VERSION 5.8 ;
BUSBITCHARS "[]" ;
DIVIDERCHAR "/" ;
UNITS
    DATABASE MICRONS 1000 ;
END UNITS

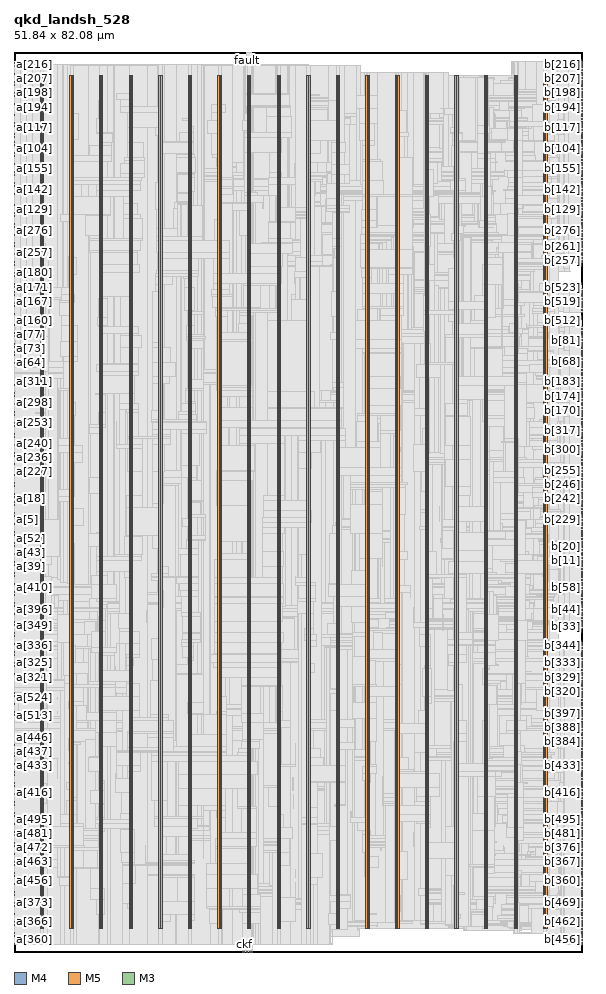
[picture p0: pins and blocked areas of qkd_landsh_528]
MACRO qkd_landsh_528
  FOREIGN qkd_landsh_528 0 0 ;
  CLASS BLOCK ;
  SIZE 51.84 BY 82.08 ;
  PIN a[0]
    DIRECTION INPUT ;
    USE SIGNAL ;
    PORT
      LAYER M4 ;
        RECT  0 38.736 0.084 38.76 ;
    END
  END a[0]
  PIN a[100]
    DIRECTION INPUT ;
    USE SIGNAL ;
    PORT
      LAYER M4 ;
        RECT  0 72.72 0.084 72.744 ;
    END
  END a[100]
  PIN a[101]
    DIRECTION INPUT ;
    USE SIGNAL ;
    PORT
      LAYER M4 ;
        RECT  0 72.864 0.084 72.888 ;
    END
  END a[101]
  PIN a[102]
    DIRECTION INPUT ;
    USE SIGNAL ;
    PORT
      LAYER M4 ;
        RECT  0 73.008 0.084 73.032 ;
    END
  END a[102]
  PIN a[103]
    DIRECTION INPUT ;
    USE SIGNAL ;
    PORT
      LAYER M4 ;
        RECT  0 73.152 0.084 73.176 ;
    END
  END a[103]
  PIN a[104]
    DIRECTION INPUT ;
    USE SIGNAL ;
    PORT
      LAYER M4 ;
        RECT  0 73.296 0.084 73.32 ;
    END
  END a[104]
  PIN a[105]
    DIRECTION INPUT ;
    USE SIGNAL ;
    PORT
      LAYER M4 ;
        RECT  0 73.44 0.084 73.464 ;
    END
  END a[105]
  PIN a[106]
    DIRECTION INPUT ;
    USE SIGNAL ;
    PORT
      LAYER M4 ;
        RECT  0 73.584 0.084 73.608 ;
    END
  END a[106]
  PIN a[107]
    DIRECTION INPUT ;
    USE SIGNAL ;
    PORT
      LAYER M4 ;
        RECT  0 73.728 0.084 73.752 ;
    END
  END a[107]
  PIN a[108]
    DIRECTION INPUT ;
    USE SIGNAL ;
    PORT
      LAYER M4 ;
        RECT  0 73.872 0.084 73.896 ;
    END
  END a[108]
  PIN a[109]
    DIRECTION INPUT ;
    USE SIGNAL ;
    PORT
      LAYER M4 ;
        RECT  0 74.016 0.084 74.04 ;
    END
  END a[109]
  PIN a[10]
    DIRECTION INPUT ;
    USE SIGNAL ;
    PORT
      LAYER M4 ;
        RECT  0 40.176 0.084 40.2 ;
    END
  END a[10]
  PIN a[110]
    DIRECTION INPUT ;
    USE SIGNAL ;
    PORT
      LAYER M4 ;
        RECT  0 74.16 0.084 74.184 ;
    END
  END a[110]
  PIN a[111]
    DIRECTION INPUT ;
    USE SIGNAL ;
    PORT
      LAYER M4 ;
        RECT  0 74.304 0.084 74.328 ;
    END
  END a[111]
  PIN a[112]
    DIRECTION INPUT ;
    USE SIGNAL ;
    PORT
      LAYER M4 ;
        RECT  0 74.448 0.084 74.472 ;
    END
  END a[112]
  PIN a[113]
    DIRECTION INPUT ;
    USE SIGNAL ;
    PORT
      LAYER M4 ;
        RECT  0 74.592 0.084 74.616 ;
    END
  END a[113]
  PIN a[114]
    DIRECTION INPUT ;
    USE SIGNAL ;
    PORT
      LAYER M4 ;
        RECT  0 74.736 0.084 74.76 ;
    END
  END a[114]
  PIN a[115]
    DIRECTION INPUT ;
    USE SIGNAL ;
    PORT
      LAYER M4 ;
        RECT  0 74.88 0.084 74.904 ;
    END
  END a[115]
  PIN a[116]
    DIRECTION INPUT ;
    USE SIGNAL ;
    PORT
      LAYER M4 ;
        RECT  0 75.024 0.084 75.048 ;
    END
  END a[116]
  PIN a[117]
    DIRECTION INPUT ;
    USE SIGNAL ;
    PORT
      LAYER M4 ;
        RECT  0 75.168 0.084 75.192 ;
    END
  END a[117]
  PIN a[118]
    DIRECTION INPUT ;
    USE SIGNAL ;
    PORT
      LAYER M4 ;
        RECT  0 75.312 0.084 75.336 ;
    END
  END a[118]
  PIN a[119]
    DIRECTION INPUT ;
    USE SIGNAL ;
    PORT
      LAYER M4 ;
        RECT  0 75.456 0.084 75.48 ;
    END
  END a[119]
  PIN a[11]
    DIRECTION INPUT ;
    USE SIGNAL ;
    PORT
      LAYER M4 ;
        RECT  0 40.32 0.084 40.344 ;
    END
  END a[11]
  PIN a[120]
    DIRECTION INPUT ;
    USE SIGNAL ;
    PORT
      LAYER M4 ;
        RECT  0 75.6 0.084 75.624 ;
    END
  END a[120]
  PIN a[121]
    DIRECTION INPUT ;
    USE SIGNAL ;
    PORT
      LAYER M4 ;
        RECT  0 75.744 0.084 75.768 ;
    END
  END a[121]
  PIN a[122]
    DIRECTION INPUT ;
    USE SIGNAL ;
    PORT
      LAYER M4 ;
        RECT  0 75.888 0.084 75.912 ;
    END
  END a[122]
  PIN a[123]
    DIRECTION INPUT ;
    USE SIGNAL ;
    PORT
      LAYER M4 ;
        RECT  0 76.032 0.084 76.056 ;
    END
  END a[123]
  PIN a[124]
    DIRECTION INPUT ;
    USE SIGNAL ;
    PORT
      LAYER M4 ;
        RECT  0 76.176 0.084 76.2 ;
    END
  END a[124]
  PIN a[125]
    DIRECTION INPUT ;
    USE SIGNAL ;
    PORT
      LAYER M4 ;
        RECT  0 76.32 0.084 76.344 ;
    END
  END a[125]
  PIN a[126]
    DIRECTION INPUT ;
    USE SIGNAL ;
    PORT
      LAYER M4 ;
        RECT  0 76.464 0.084 76.488 ;
    END
  END a[126]
  PIN a[127]
    DIRECTION INPUT ;
    USE SIGNAL ;
    PORT
      LAYER M4 ;
        RECT  0 76.608 0.084 76.632 ;
    END
  END a[127]
  PIN a[128]
    DIRECTION INPUT ;
    USE SIGNAL ;
    PORT
      LAYER M4 ;
        RECT  0 67.536 0.084 67.56 ;
    END
  END a[128]
  PIN a[129]
    DIRECTION INPUT ;
    USE SIGNAL ;
    PORT
      LAYER M4 ;
        RECT  0 67.68 0.084 67.704 ;
    END
  END a[129]
  PIN a[12]
    DIRECTION INPUT ;
    USE SIGNAL ;
    PORT
      LAYER M4 ;
        RECT  0 40.464 0.084 40.488 ;
    END
  END a[12]
  PIN a[130]
    DIRECTION INPUT ;
    USE SIGNAL ;
    PORT
      LAYER M4 ;
        RECT  0 67.824 0.084 67.848 ;
    END
  END a[130]
  PIN a[131]
    DIRECTION INPUT ;
    USE SIGNAL ;
    PORT
      LAYER M4 ;
        RECT  0 67.968 0.084 67.992 ;
    END
  END a[131]
  PIN a[132]
    DIRECTION INPUT ;
    USE SIGNAL ;
    PORT
      LAYER M4 ;
        RECT  0 68.112 0.084 68.136 ;
    END
  END a[132]
  PIN a[133]
    DIRECTION INPUT ;
    USE SIGNAL ;
    PORT
      LAYER M4 ;
        RECT  0 68.256 0.084 68.28 ;
    END
  END a[133]
  PIN a[134]
    DIRECTION INPUT ;
    USE SIGNAL ;
    PORT
      LAYER M4 ;
        RECT  0 68.4 0.084 68.424 ;
    END
  END a[134]
  PIN a[135]
    DIRECTION INPUT ;
    USE SIGNAL ;
    PORT
      LAYER M4 ;
        RECT  0 68.544 0.084 68.568 ;
    END
  END a[135]
  PIN a[136]
    DIRECTION INPUT ;
    USE SIGNAL ;
    PORT
      LAYER M4 ;
        RECT  0 68.688 0.084 68.712 ;
    END
  END a[136]
  PIN a[137]
    DIRECTION INPUT ;
    USE SIGNAL ;
    PORT
      LAYER M4 ;
        RECT  0 68.832 0.084 68.856 ;
    END
  END a[137]
  PIN a[138]
    DIRECTION INPUT ;
    USE SIGNAL ;
    PORT
      LAYER M4 ;
        RECT  0 68.976 0.084 69 ;
    END
  END a[138]
  PIN a[139]
    DIRECTION INPUT ;
    USE SIGNAL ;
    PORT
      LAYER M4 ;
        RECT  0 69.12 0.084 69.144 ;
    END
  END a[139]
  PIN a[13]
    DIRECTION INPUT ;
    USE SIGNAL ;
    PORT
      LAYER M4 ;
        RECT  0 40.608 0.084 40.632 ;
    END
  END a[13]
  PIN a[140]
    DIRECTION INPUT ;
    USE SIGNAL ;
    PORT
      LAYER M4 ;
        RECT  0 69.264 0.084 69.288 ;
    END
  END a[140]
  PIN a[141]
    DIRECTION INPUT ;
    USE SIGNAL ;
    PORT
      LAYER M4 ;
        RECT  0 69.408 0.084 69.432 ;
    END
  END a[141]
  PIN a[142]
    DIRECTION INPUT ;
    USE SIGNAL ;
    PORT
      LAYER M4 ;
        RECT  0 69.552 0.084 69.576 ;
    END
  END a[142]
  PIN a[143]
    DIRECTION INPUT ;
    USE SIGNAL ;
    PORT
      LAYER M4 ;
        RECT  0 69.696 0.084 69.72 ;
    END
  END a[143]
  PIN a[144]
    DIRECTION INPUT ;
    USE SIGNAL ;
    PORT
      LAYER M4 ;
        RECT  0 69.84 0.084 69.864 ;
    END
  END a[144]
  PIN a[145]
    DIRECTION INPUT ;
    USE SIGNAL ;
    PORT
      LAYER M4 ;
        RECT  0 69.984 0.084 70.008 ;
    END
  END a[145]
  PIN a[146]
    DIRECTION INPUT ;
    USE SIGNAL ;
    PORT
      LAYER M4 ;
        RECT  0 70.128 0.084 70.152 ;
    END
  END a[146]
  PIN a[147]
    DIRECTION INPUT ;
    USE SIGNAL ;
    PORT
      LAYER M4 ;
        RECT  0 70.272 0.084 70.296 ;
    END
  END a[147]
  PIN a[148]
    DIRECTION INPUT ;
    USE SIGNAL ;
    PORT
      LAYER M4 ;
        RECT  0 70.416 0.084 70.44 ;
    END
  END a[148]
  PIN a[149]
    DIRECTION INPUT ;
    USE SIGNAL ;
    PORT
      LAYER M4 ;
        RECT  0 70.56 0.084 70.584 ;
    END
  END a[149]
  PIN a[14]
    DIRECTION INPUT ;
    USE SIGNAL ;
    PORT
      LAYER M4 ;
        RECT  0 40.752 0.084 40.776 ;
    END
  END a[14]
  PIN a[150]
    DIRECTION INPUT ;
    USE SIGNAL ;
    PORT
      LAYER M4 ;
        RECT  0 70.704 0.084 70.728 ;
    END
  END a[150]
  PIN a[151]
    DIRECTION INPUT ;
    USE SIGNAL ;
    PORT
      LAYER M4 ;
        RECT  0 70.848 0.084 70.872 ;
    END
  END a[151]
  PIN a[152]
    DIRECTION INPUT ;
    USE SIGNAL ;
    PORT
      LAYER M4 ;
        RECT  0 70.992 0.084 71.016 ;
    END
  END a[152]
  PIN a[153]
    DIRECTION INPUT ;
    USE SIGNAL ;
    PORT
      LAYER M4 ;
        RECT  0 71.136 0.084 71.16 ;
    END
  END a[153]
  PIN a[154]
    DIRECTION INPUT ;
    USE SIGNAL ;
    PORT
      LAYER M4 ;
        RECT  0 71.28 0.084 71.304 ;
    END
  END a[154]
  PIN a[155]
    DIRECTION INPUT ;
    USE SIGNAL ;
    PORT
      LAYER M4 ;
        RECT  0 71.424 0.084 71.448 ;
    END
  END a[155]
  PIN a[156]
    DIRECTION INPUT ;
    USE SIGNAL ;
    PORT
      LAYER M4 ;
        RECT  0 71.568 0.084 71.592 ;
    END
  END a[156]
  PIN a[157]
    DIRECTION INPUT ;
    USE SIGNAL ;
    PORT
      LAYER M4 ;
        RECT  0 71.712 0.084 71.736 ;
    END
  END a[157]
  PIN a[158]
    DIRECTION INPUT ;
    USE SIGNAL ;
    PORT
      LAYER M4 ;
        RECT  0 71.856 0.084 71.88 ;
    END
  END a[158]
  PIN a[159]
    DIRECTION INPUT ;
    USE SIGNAL ;
    PORT
      LAYER M4 ;
        RECT  0 72 0.084 72.024 ;
    END
  END a[159]
  PIN a[15]
    DIRECTION INPUT ;
    USE SIGNAL ;
    PORT
      LAYER M4 ;
        RECT  0 40.896 0.084 40.92 ;
    END
  END a[15]
  PIN a[160]
    DIRECTION INPUT ;
    USE SIGNAL ;
    PORT
      LAYER M4 ;
        RECT  0 58.32 0.084 58.344 ;
    END
  END a[160]
  PIN a[161]
    DIRECTION INPUT ;
    USE SIGNAL ;
    PORT
      LAYER M4 ;
        RECT  0 58.464 0.084 58.488 ;
    END
  END a[161]
  PIN a[162]
    DIRECTION INPUT ;
    USE SIGNAL ;
    PORT
      LAYER M4 ;
        RECT  0 58.608 0.084 58.632 ;
    END
  END a[162]
  PIN a[163]
    DIRECTION INPUT ;
    USE SIGNAL ;
    PORT
      LAYER M4 ;
        RECT  0 58.752 0.084 58.776 ;
    END
  END a[163]
  PIN a[164]
    DIRECTION INPUT ;
    USE SIGNAL ;
    PORT
      LAYER M4 ;
        RECT  0 58.896 0.084 58.92 ;
    END
  END a[164]
  PIN a[165]
    DIRECTION INPUT ;
    USE SIGNAL ;
    PORT
      LAYER M4 ;
        RECT  0 59.04 0.084 59.064 ;
    END
  END a[165]
  PIN a[166]
    DIRECTION INPUT ;
    USE SIGNAL ;
    PORT
      LAYER M4 ;
        RECT  0 59.184 0.084 59.208 ;
    END
  END a[166]
  PIN a[167]
    DIRECTION INPUT ;
    USE SIGNAL ;
    PORT
      LAYER M4 ;
        RECT  0 59.328 0.084 59.352 ;
    END
  END a[167]
  PIN a[168]
    DIRECTION INPUT ;
    USE SIGNAL ;
    PORT
      LAYER M4 ;
        RECT  0 59.472 0.084 59.496 ;
    END
  END a[168]
  PIN a[169]
    DIRECTION INPUT ;
    USE SIGNAL ;
    PORT
      LAYER M4 ;
        RECT  0 59.616 0.084 59.64 ;
    END
  END a[169]
  PIN a[16]
    DIRECTION INPUT ;
    USE SIGNAL ;
    PORT
      LAYER M4 ;
        RECT  0 41.04 0.084 41.064 ;
    END
  END a[16]
  PIN a[170]
    DIRECTION INPUT ;
    USE SIGNAL ;
    PORT
      LAYER M4 ;
        RECT  0 59.76 0.084 59.784 ;
    END
  END a[170]
  PIN a[171]
    DIRECTION INPUT ;
    USE SIGNAL ;
    PORT
      LAYER M4 ;
        RECT  0 59.904 0.084 59.928 ;
    END
  END a[171]
  PIN a[172]
    DIRECTION INPUT ;
    USE SIGNAL ;
    PORT
      LAYER M4 ;
        RECT  0 60.048 0.084 60.072 ;
    END
  END a[172]
  PIN a[173]
    DIRECTION INPUT ;
    USE SIGNAL ;
    PORT
      LAYER M4 ;
        RECT  0 60.192 0.084 60.216 ;
    END
  END a[173]
  PIN a[174]
    DIRECTION INPUT ;
    USE SIGNAL ;
    PORT
      LAYER M4 ;
        RECT  0 60.336 0.084 60.36 ;
    END
  END a[174]
  PIN a[175]
    DIRECTION INPUT ;
    USE SIGNAL ;
    PORT
      LAYER M4 ;
        RECT  0 60.48 0.084 60.504 ;
    END
  END a[175]
  PIN a[176]
    DIRECTION INPUT ;
    USE SIGNAL ;
    PORT
      LAYER M4 ;
        RECT  0 60.624 0.084 60.648 ;
    END
  END a[176]
  PIN a[177]
    DIRECTION INPUT ;
    USE SIGNAL ;
    PORT
      LAYER M4 ;
        RECT  0 60.768 0.084 60.792 ;
    END
  END a[177]
  PIN a[178]
    DIRECTION INPUT ;
    USE SIGNAL ;
    PORT
      LAYER M4 ;
        RECT  0 60.912 0.084 60.936 ;
    END
  END a[178]
  PIN a[179]
    DIRECTION INPUT ;
    USE SIGNAL ;
    PORT
      LAYER M4 ;
        RECT  0 61.056 0.084 61.08 ;
    END
  END a[179]
  PIN a[17]
    DIRECTION INPUT ;
    USE SIGNAL ;
    PORT
      LAYER M4 ;
        RECT  0 41.184 0.084 41.208 ;
    END
  END a[17]
  PIN a[180]
    DIRECTION INPUT ;
    USE SIGNAL ;
    PORT
      LAYER M4 ;
        RECT  0 61.2 0.084 61.224 ;
    END
  END a[180]
  PIN a[181]
    DIRECTION INPUT ;
    USE SIGNAL ;
    PORT
      LAYER M4 ;
        RECT  0 61.344 0.084 61.368 ;
    END
  END a[181]
  PIN a[182]
    DIRECTION INPUT ;
    USE SIGNAL ;
    PORT
      LAYER M4 ;
        RECT  0 61.488 0.084 61.512 ;
    END
  END a[182]
  PIN a[183]
    DIRECTION INPUT ;
    USE SIGNAL ;
    PORT
      LAYER M4 ;
        RECT  0 61.632 0.084 61.656 ;
    END
  END a[183]
  PIN a[184]
    DIRECTION INPUT ;
    USE SIGNAL ;
    PORT
      LAYER M4 ;
        RECT  0 61.776 0.084 61.8 ;
    END
  END a[184]
  PIN a[185]
    DIRECTION INPUT ;
    USE SIGNAL ;
    PORT
      LAYER M4 ;
        RECT  0 61.92 0.084 61.944 ;
    END
  END a[185]
  PIN a[186]
    DIRECTION INPUT ;
    USE SIGNAL ;
    PORT
      LAYER M4 ;
        RECT  0 62.064 0.084 62.088 ;
    END
  END a[186]
  PIN a[187]
    DIRECTION INPUT ;
    USE SIGNAL ;
    PORT
      LAYER M4 ;
        RECT  0 62.208 0.084 62.232 ;
    END
  END a[187]
  PIN a[188]
    DIRECTION INPUT ;
    USE SIGNAL ;
    PORT
      LAYER M4 ;
        RECT  0 62.352 0.084 62.376 ;
    END
  END a[188]
  PIN a[189]
    DIRECTION INPUT ;
    USE SIGNAL ;
    PORT
      LAYER M4 ;
        RECT  0 62.496 0.084 62.52 ;
    END
  END a[189]
  PIN a[18]
    DIRECTION INPUT ;
    USE SIGNAL ;
    PORT
      LAYER M4 ;
        RECT  0 41.328 0.084 41.352 ;
    END
  END a[18]
  PIN a[190]
    DIRECTION INPUT ;
    USE SIGNAL ;
    PORT
      LAYER M4 ;
        RECT  0 62.64 0.084 62.664 ;
    END
  END a[190]
  PIN a[191]
    DIRECTION INPUT ;
    USE SIGNAL ;
    PORT
      LAYER M4 ;
        RECT  0 62.784 0.084 62.808 ;
    END
  END a[191]
  PIN a[192]
    DIRECTION INPUT ;
    USE SIGNAL ;
    PORT
      LAYER M4 ;
        RECT  0 76.752 0.084 76.776 ;
    END
  END a[192]
  PIN a[193]
    DIRECTION INPUT ;
    USE SIGNAL ;
    PORT
      LAYER M4 ;
        RECT  0 76.896 0.084 76.92 ;
    END
  END a[193]
  PIN a[194]
    DIRECTION INPUT ;
    USE SIGNAL ;
    PORT
      LAYER M4 ;
        RECT  0 77.04 0.084 77.064 ;
    END
  END a[194]
  PIN a[195]
    DIRECTION INPUT ;
    USE SIGNAL ;
    PORT
      LAYER M4 ;
        RECT  0 77.184 0.084 77.208 ;
    END
  END a[195]
  PIN a[196]
    DIRECTION INPUT ;
    USE SIGNAL ;
    PORT
      LAYER M4 ;
        RECT  0 77.328 0.084 77.352 ;
    END
  END a[196]
  PIN a[197]
    DIRECTION INPUT ;
    USE SIGNAL ;
    PORT
      LAYER M4 ;
        RECT  0 77.472 0.084 77.496 ;
    END
  END a[197]
  PIN a[198]
    DIRECTION INPUT ;
    USE SIGNAL ;
    PORT
      LAYER M4 ;
        RECT  0 77.616 0.084 77.64 ;
    END
  END a[198]
  PIN a[199]
    DIRECTION INPUT ;
    USE SIGNAL ;
    PORT
      LAYER M4 ;
        RECT  0 77.76 0.084 77.784 ;
    END
  END a[199]
  PIN a[19]
    DIRECTION INPUT ;
    USE SIGNAL ;
    PORT
      LAYER M4 ;
        RECT  0 41.472 0.084 41.496 ;
    END
  END a[19]
  PIN a[1]
    DIRECTION INPUT ;
    USE SIGNAL ;
    PORT
      LAYER M4 ;
        RECT  0 38.88 0.084 38.904 ;
    END
  END a[1]
  PIN a[200]
    DIRECTION INPUT ;
    USE SIGNAL ;
    PORT
      LAYER M4 ;
        RECT  0 77.904 0.084 77.928 ;
    END
  END a[200]
  PIN a[201]
    DIRECTION INPUT ;
    USE SIGNAL ;
    PORT
      LAYER M4 ;
        RECT  0 78.048 0.084 78.072 ;
    END
  END a[201]
  PIN a[202]
    DIRECTION INPUT ;
    USE SIGNAL ;
    PORT
      LAYER M4 ;
        RECT  0 78.192 0.084 78.216 ;
    END
  END a[202]
  PIN a[203]
    DIRECTION INPUT ;
    USE SIGNAL ;
    PORT
      LAYER M4 ;
        RECT  0 78.336 0.084 78.36 ;
    END
  END a[203]
  PIN a[204]
    DIRECTION INPUT ;
    USE SIGNAL ;
    PORT
      LAYER M4 ;
        RECT  0 78.48 0.084 78.504 ;
    END
  END a[204]
  PIN a[205]
    DIRECTION INPUT ;
    USE SIGNAL ;
    PORT
      LAYER M4 ;
        RECT  0 78.624 0.084 78.648 ;
    END
  END a[205]
  PIN a[206]
    DIRECTION INPUT ;
    USE SIGNAL ;
    PORT
      LAYER M4 ;
        RECT  0 78.768 0.084 78.792 ;
    END
  END a[206]
  PIN a[207]
    DIRECTION INPUT ;
    USE SIGNAL ;
    PORT
      LAYER M4 ;
        RECT  0 78.912 0.084 78.936 ;
    END
  END a[207]
  PIN a[208]
    DIRECTION INPUT ;
    USE SIGNAL ;
    PORT
      LAYER M4 ;
        RECT  0 79.056 0.084 79.08 ;
    END
  END a[208]
  PIN a[209]
    DIRECTION INPUT ;
    USE SIGNAL ;
    PORT
      LAYER M4 ;
        RECT  0 79.2 0.084 79.224 ;
    END
  END a[209]
  PIN a[20]
    DIRECTION INPUT ;
    USE SIGNAL ;
    PORT
      LAYER M4 ;
        RECT  0 41.616 0.084 41.64 ;
    END
  END a[20]
  PIN a[210]
    DIRECTION INPUT ;
    USE SIGNAL ;
    PORT
      LAYER M4 ;
        RECT  0 79.344 0.084 79.368 ;
    END
  END a[210]
  PIN a[211]
    DIRECTION INPUT ;
    USE SIGNAL ;
    PORT
      LAYER M4 ;
        RECT  0 79.488 0.084 79.512 ;
    END
  END a[211]
  PIN a[212]
    DIRECTION INPUT ;
    USE SIGNAL ;
    PORT
      LAYER M4 ;
        RECT  0 79.632 0.084 79.656 ;
    END
  END a[212]
  PIN a[213]
    DIRECTION INPUT ;
    USE SIGNAL ;
    PORT
      LAYER M4 ;
        RECT  0 79.776 0.084 79.8 ;
    END
  END a[213]
  PIN a[214]
    DIRECTION INPUT ;
    USE SIGNAL ;
    PORT
      LAYER M4 ;
        RECT  0 79.92 0.084 79.944 ;
    END
  END a[214]
  PIN a[215]
    DIRECTION INPUT ;
    USE SIGNAL ;
    PORT
      LAYER M4 ;
        RECT  0 80.064 0.084 80.088 ;
    END
  END a[215]
  PIN a[216]
    DIRECTION INPUT ;
    USE SIGNAL ;
    PORT
      LAYER M4 ;
        RECT  0 80.208 0.084 80.232 ;
    END
  END a[216]
  PIN a[217]
    DIRECTION INPUT ;
    USE SIGNAL ;
    PORT
      LAYER M4 ;
        RECT  0 80.352 0.084 80.376 ;
    END
  END a[217]
  PIN a[218]
    DIRECTION INPUT ;
    USE SIGNAL ;
    PORT
      LAYER M4 ;
        RECT  0 80.496 0.084 80.52 ;
    END
  END a[218]
  PIN a[219]
    DIRECTION INPUT ;
    USE SIGNAL ;
    PORT
      LAYER M4 ;
        RECT  0 80.64 0.084 80.664 ;
    END
  END a[219]
  PIN a[21]
    DIRECTION INPUT ;
    USE SIGNAL ;
    PORT
      LAYER M4 ;
        RECT  0 41.76 0.084 41.784 ;
    END
  END a[21]
  PIN a[220]
    DIRECTION INPUT ;
    USE SIGNAL ;
    PORT
      LAYER M4 ;
        RECT  0 80.784 0.084 80.808 ;
    END
  END a[220]
  PIN a[221]
    DIRECTION INPUT ;
    USE SIGNAL ;
    PORT
      LAYER M4 ;
        RECT  0 80.928 0.084 80.952 ;
    END
  END a[221]
  PIN a[222]
    DIRECTION INPUT ;
    USE SIGNAL ;
    PORT
      LAYER M4 ;
        RECT  0 81.072 0.084 81.096 ;
    END
  END a[222]
  PIN a[223]
    DIRECTION INPUT ;
    USE SIGNAL ;
    PORT
      LAYER M4 ;
        RECT  0 81.216 0.084 81.24 ;
    END
  END a[223]
  PIN a[224]
    DIRECTION INPUT ;
    USE SIGNAL ;
    PORT
      LAYER M4 ;
        RECT  0 43.344 0.084 43.368 ;
    END
  END a[224]
  PIN a[225]
    DIRECTION INPUT ;
    USE SIGNAL ;
    PORT
      LAYER M4 ;
        RECT  0 43.488 0.084 43.512 ;
    END
  END a[225]
  PIN a[226]
    DIRECTION INPUT ;
    USE SIGNAL ;
    PORT
      LAYER M4 ;
        RECT  0 43.632 0.084 43.656 ;
    END
  END a[226]
  PIN a[227]
    DIRECTION INPUT ;
    USE SIGNAL ;
    PORT
      LAYER M4 ;
        RECT  0 43.776 0.084 43.8 ;
    END
  END a[227]
  PIN a[228]
    DIRECTION INPUT ;
    USE SIGNAL ;
    PORT
      LAYER M4 ;
        RECT  0 43.92 0.084 43.944 ;
    END
  END a[228]
  PIN a[229]
    DIRECTION INPUT ;
    USE SIGNAL ;
    PORT
      LAYER M4 ;
        RECT  0 44.064 0.084 44.088 ;
    END
  END a[229]
  PIN a[22]
    DIRECTION INPUT ;
    USE SIGNAL ;
    PORT
      LAYER M4 ;
        RECT  0 41.904 0.084 41.928 ;
    END
  END a[22]
  PIN a[230]
    DIRECTION INPUT ;
    USE SIGNAL ;
    PORT
      LAYER M4 ;
        RECT  0 44.208 0.084 44.232 ;
    END
  END a[230]
  PIN a[231]
    DIRECTION INPUT ;
    USE SIGNAL ;
    PORT
      LAYER M4 ;
        RECT  0 44.352 0.084 44.376 ;
    END
  END a[231]
  PIN a[232]
    DIRECTION INPUT ;
    USE SIGNAL ;
    PORT
      LAYER M4 ;
        RECT  0 44.496 0.084 44.52 ;
    END
  END a[232]
  PIN a[233]
    DIRECTION INPUT ;
    USE SIGNAL ;
    PORT
      LAYER M4 ;
        RECT  0 44.64 0.084 44.664 ;
    END
  END a[233]
  PIN a[234]
    DIRECTION INPUT ;
    USE SIGNAL ;
    PORT
      LAYER M4 ;
        RECT  0 44.784 0.084 44.808 ;
    END
  END a[234]
  PIN a[235]
    DIRECTION INPUT ;
    USE SIGNAL ;
    PORT
      LAYER M4 ;
        RECT  0 44.928 0.084 44.952 ;
    END
  END a[235]
  PIN a[236]
    DIRECTION INPUT ;
    USE SIGNAL ;
    PORT
      LAYER M4 ;
        RECT  0 45.072 0.084 45.096 ;
    END
  END a[236]
  PIN a[237]
    DIRECTION INPUT ;
    USE SIGNAL ;
    PORT
      LAYER M4 ;
        RECT  0 45.216 0.084 45.24 ;
    END
  END a[237]
  PIN a[238]
    DIRECTION INPUT ;
    USE SIGNAL ;
    PORT
      LAYER M4 ;
        RECT  0 45.36 0.084 45.384 ;
    END
  END a[238]
  PIN a[239]
    DIRECTION INPUT ;
    USE SIGNAL ;
    PORT
      LAYER M4 ;
        RECT  0 45.504 0.084 45.528 ;
    END
  END a[239]
  PIN a[23]
    DIRECTION INPUT ;
    USE SIGNAL ;
    PORT
      LAYER M4 ;
        RECT  0 42.048 0.084 42.072 ;
    END
  END a[23]
  PIN a[240]
    DIRECTION INPUT ;
    USE SIGNAL ;
    PORT
      LAYER M4 ;
        RECT  0 45.648 0.084 45.672 ;
    END
  END a[240]
  PIN a[241]
    DIRECTION INPUT ;
    USE SIGNAL ;
    PORT
      LAYER M4 ;
        RECT  0 45.792 0.084 45.816 ;
    END
  END a[241]
  PIN a[242]
    DIRECTION INPUT ;
    USE SIGNAL ;
    PORT
      LAYER M4 ;
        RECT  0 45.936 0.084 45.96 ;
    END
  END a[242]
  PIN a[243]
    DIRECTION INPUT ;
    USE SIGNAL ;
    PORT
      LAYER M4 ;
        RECT  0 46.08 0.084 46.104 ;
    END
  END a[243]
  PIN a[244]
    DIRECTION INPUT ;
    USE SIGNAL ;
    PORT
      LAYER M4 ;
        RECT  0 46.224 0.084 46.248 ;
    END
  END a[244]
  PIN a[245]
    DIRECTION INPUT ;
    USE SIGNAL ;
    PORT
      LAYER M4 ;
        RECT  0 46.368 0.084 46.392 ;
    END
  END a[245]
  PIN a[246]
    DIRECTION INPUT ;
    USE SIGNAL ;
    PORT
      LAYER M4 ;
        RECT  0 46.512 0.084 46.536 ;
    END
  END a[246]
  PIN a[247]
    DIRECTION INPUT ;
    USE SIGNAL ;
    PORT
      LAYER M4 ;
        RECT  0 46.656 0.084 46.68 ;
    END
  END a[247]
  PIN a[248]
    DIRECTION INPUT ;
    USE SIGNAL ;
    PORT
      LAYER M4 ;
        RECT  0 46.8 0.084 46.824 ;
    END
  END a[248]
  PIN a[249]
    DIRECTION INPUT ;
    USE SIGNAL ;
    PORT
      LAYER M4 ;
        RECT  0 46.944 0.084 46.968 ;
    END
  END a[249]
  PIN a[24]
    DIRECTION INPUT ;
    USE SIGNAL ;
    PORT
      LAYER M4 ;
        RECT  0 42.192 0.084 42.216 ;
    END
  END a[24]
  PIN a[250]
    DIRECTION INPUT ;
    USE SIGNAL ;
    PORT
      LAYER M4 ;
        RECT  0 47.088 0.084 47.112 ;
    END
  END a[250]
  PIN a[251]
    DIRECTION INPUT ;
    USE SIGNAL ;
    PORT
      LAYER M4 ;
        RECT  0 47.232 0.084 47.256 ;
    END
  END a[251]
  PIN a[252]
    DIRECTION INPUT ;
    USE SIGNAL ;
    PORT
      LAYER M4 ;
        RECT  0 47.376 0.084 47.4 ;
    END
  END a[252]
  PIN a[253]
    DIRECTION INPUT ;
    USE SIGNAL ;
    PORT
      LAYER M4 ;
        RECT  0 47.52 0.084 47.544 ;
    END
  END a[253]
  PIN a[254]
    DIRECTION INPUT ;
    USE SIGNAL ;
    PORT
      LAYER M4 ;
        RECT  0 47.664 0.084 47.688 ;
    END
  END a[254]
  PIN a[255]
    DIRECTION INPUT ;
    USE SIGNAL ;
    PORT
      LAYER M4 ;
        RECT  0 47.808 0.084 47.832 ;
    END
  END a[255]
  PIN a[256]
    DIRECTION INPUT ;
    USE SIGNAL ;
    PORT
      LAYER M4 ;
        RECT  0 62.928 0.084 62.952 ;
    END
  END a[256]
  PIN a[257]
    DIRECTION INPUT ;
    USE SIGNAL ;
    PORT
      LAYER M4 ;
        RECT  0 63.072 0.084 63.096 ;
    END
  END a[257]
  PIN a[258]
    DIRECTION INPUT ;
    USE SIGNAL ;
    PORT
      LAYER M4 ;
        RECT  0 63.216 0.084 63.24 ;
    END
  END a[258]
  PIN a[259]
    DIRECTION INPUT ;
    USE SIGNAL ;
    PORT
      LAYER M4 ;
        RECT  0 63.36 0.084 63.384 ;
    END
  END a[259]
  PIN a[25]
    DIRECTION INPUT ;
    USE SIGNAL ;
    PORT
      LAYER M4 ;
        RECT  0 42.336 0.084 42.36 ;
    END
  END a[25]
  PIN a[260]
    DIRECTION INPUT ;
    USE SIGNAL ;
    PORT
      LAYER M4 ;
        RECT  0 63.504 0.084 63.528 ;
    END
  END a[260]
  PIN a[261]
    DIRECTION INPUT ;
    USE SIGNAL ;
    PORT
      LAYER M4 ;
        RECT  0 63.648 0.084 63.672 ;
    END
  END a[261]
  PIN a[262]
    DIRECTION INPUT ;
    USE SIGNAL ;
    PORT
      LAYER M4 ;
        RECT  0 63.792 0.084 63.816 ;
    END
  END a[262]
  PIN a[263]
    DIRECTION INPUT ;
    USE SIGNAL ;
    PORT
      LAYER M4 ;
        RECT  0 63.936 0.084 63.96 ;
    END
  END a[263]
  PIN a[264]
    DIRECTION INPUT ;
    USE SIGNAL ;
    PORT
      LAYER M4 ;
        RECT  0 64.08 0.084 64.104 ;
    END
  END a[264]
  PIN a[265]
    DIRECTION INPUT ;
    USE SIGNAL ;
    PORT
      LAYER M4 ;
        RECT  0 64.224 0.084 64.248 ;
    END
  END a[265]
  PIN a[266]
    DIRECTION INPUT ;
    USE SIGNAL ;
    PORT
      LAYER M4 ;
        RECT  0 64.368 0.084 64.392 ;
    END
  END a[266]
  PIN a[267]
    DIRECTION INPUT ;
    USE SIGNAL ;
    PORT
      LAYER M4 ;
        RECT  0 64.512 0.084 64.536 ;
    END
  END a[267]
  PIN a[268]
    DIRECTION INPUT ;
    USE SIGNAL ;
    PORT
      LAYER M4 ;
        RECT  0 64.656 0.084 64.68 ;
    END
  END a[268]
  PIN a[269]
    DIRECTION INPUT ;
    USE SIGNAL ;
    PORT
      LAYER M4 ;
        RECT  0 64.8 0.084 64.824 ;
    END
  END a[269]
  PIN a[26]
    DIRECTION INPUT ;
    USE SIGNAL ;
    PORT
      LAYER M4 ;
        RECT  0 42.48 0.084 42.504 ;
    END
  END a[26]
  PIN a[270]
    DIRECTION INPUT ;
    USE SIGNAL ;
    PORT
      LAYER M4 ;
        RECT  0 64.944 0.084 64.968 ;
    END
  END a[270]
  PIN a[271]
    DIRECTION INPUT ;
    USE SIGNAL ;
    PORT
      LAYER M4 ;
        RECT  0 65.088 0.084 65.112 ;
    END
  END a[271]
  PIN a[272]
    DIRECTION INPUT ;
    USE SIGNAL ;
    PORT
      LAYER M4 ;
        RECT  0 65.232 0.084 65.256 ;
    END
  END a[272]
  PIN a[273]
    DIRECTION INPUT ;
    USE SIGNAL ;
    PORT
      LAYER M4 ;
        RECT  0 65.376 0.084 65.4 ;
    END
  END a[273]
  PIN a[274]
    DIRECTION INPUT ;
    USE SIGNAL ;
    PORT
      LAYER M4 ;
        RECT  0 65.52 0.084 65.544 ;
    END
  END a[274]
  PIN a[275]
    DIRECTION INPUT ;
    USE SIGNAL ;
    PORT
      LAYER M4 ;
        RECT  0 65.664 0.084 65.688 ;
    END
  END a[275]
  PIN a[276]
    DIRECTION INPUT ;
    USE SIGNAL ;
    PORT
      LAYER M4 ;
        RECT  0 65.808 0.084 65.832 ;
    END
  END a[276]
  PIN a[277]
    DIRECTION INPUT ;
    USE SIGNAL ;
    PORT
      LAYER M4 ;
        RECT  0 65.952 0.084 65.976 ;
    END
  END a[277]
  PIN a[278]
    DIRECTION INPUT ;
    USE SIGNAL ;
    PORT
      LAYER M4 ;
        RECT  0 66.096 0.084 66.12 ;
    END
  END a[278]
  PIN a[279]
    DIRECTION INPUT ;
    USE SIGNAL ;
    PORT
      LAYER M4 ;
        RECT  0 66.24 0.084 66.264 ;
    END
  END a[279]
  PIN a[27]
    DIRECTION INPUT ;
    USE SIGNAL ;
    PORT
      LAYER M4 ;
        RECT  0 42.624 0.084 42.648 ;
    END
  END a[27]
  PIN a[280]
    DIRECTION INPUT ;
    USE SIGNAL ;
    PORT
      LAYER M4 ;
        RECT  0 66.384 0.084 66.408 ;
    END
  END a[280]
  PIN a[281]
    DIRECTION INPUT ;
    USE SIGNAL ;
    PORT
      LAYER M4 ;
        RECT  0 66.528 0.084 66.552 ;
    END
  END a[281]
  PIN a[282]
    DIRECTION INPUT ;
    USE SIGNAL ;
    PORT
      LAYER M4 ;
        RECT  0 66.672 0.084 66.696 ;
    END
  END a[282]
  PIN a[283]
    DIRECTION INPUT ;
    USE SIGNAL ;
    PORT
      LAYER M4 ;
        RECT  0 66.816 0.084 66.84 ;
    END
  END a[283]
  PIN a[284]
    DIRECTION INPUT ;
    USE SIGNAL ;
    PORT
      LAYER M4 ;
        RECT  0 66.96 0.084 66.984 ;
    END
  END a[284]
  PIN a[285]
    DIRECTION INPUT ;
    USE SIGNAL ;
    PORT
      LAYER M4 ;
        RECT  0 67.104 0.084 67.128 ;
    END
  END a[285]
  PIN a[286]
    DIRECTION INPUT ;
    USE SIGNAL ;
    PORT
      LAYER M4 ;
        RECT  0 67.248 0.084 67.272 ;
    END
  END a[286]
  PIN a[287]
    DIRECTION INPUT ;
    USE SIGNAL ;
    PORT
      LAYER M4 ;
        RECT  0 67.392 0.084 67.416 ;
    END
  END a[287]
  PIN a[288]
    DIRECTION INPUT ;
    USE SIGNAL ;
    PORT
      LAYER M4 ;
        RECT  0 47.952 0.084 47.976 ;
    END
  END a[288]
  PIN a[289]
    DIRECTION INPUT ;
    USE SIGNAL ;
    PORT
      LAYER M4 ;
        RECT  0 48.096 0.084 48.12 ;
    END
  END a[289]
  PIN a[28]
    DIRECTION INPUT ;
    USE SIGNAL ;
    PORT
      LAYER M4 ;
        RECT  0 42.768 0.084 42.792 ;
    END
  END a[28]
  PIN a[290]
    DIRECTION INPUT ;
    USE SIGNAL ;
    PORT
      LAYER M4 ;
        RECT  0 48.24 0.084 48.264 ;
    END
  END a[290]
  PIN a[291]
    DIRECTION INPUT ;
    USE SIGNAL ;
    PORT
      LAYER M4 ;
        RECT  0 48.384 0.084 48.408 ;
    END
  END a[291]
  PIN a[292]
    DIRECTION INPUT ;
    USE SIGNAL ;
    PORT
      LAYER M4 ;
        RECT  0 48.528 0.084 48.552 ;
    END
  END a[292]
  PIN a[293]
    DIRECTION INPUT ;
    USE SIGNAL ;
    PORT
      LAYER M4 ;
        RECT  0 48.672 0.084 48.696 ;
    END
  END a[293]
  PIN a[294]
    DIRECTION INPUT ;
    USE SIGNAL ;
    PORT
      LAYER M4 ;
        RECT  0 48.816 0.084 48.84 ;
    END
  END a[294]
  PIN a[295]
    DIRECTION INPUT ;
    USE SIGNAL ;
    PORT
      LAYER M4 ;
        RECT  0 48.96 0.084 48.984 ;
    END
  END a[295]
  PIN a[296]
    DIRECTION INPUT ;
    USE SIGNAL ;
    PORT
      LAYER M4 ;
        RECT  0 49.104 0.084 49.128 ;
    END
  END a[296]
  PIN a[297]
    DIRECTION INPUT ;
    USE SIGNAL ;
    PORT
      LAYER M4 ;
        RECT  0 49.248 0.084 49.272 ;
    END
  END a[297]
  PIN a[298]
    DIRECTION INPUT ;
    USE SIGNAL ;
    PORT
      LAYER M4 ;
        RECT  0 49.392 0.084 49.416 ;
    END
  END a[298]
  PIN a[299]
    DIRECTION INPUT ;
    USE SIGNAL ;
    PORT
      LAYER M4 ;
        RECT  0 49.536 0.084 49.56 ;
    END
  END a[299]
  PIN a[29]
    DIRECTION INPUT ;
    USE SIGNAL ;
    PORT
      LAYER M4 ;
        RECT  0 42.912 0.084 42.936 ;
    END
  END a[29]
  PIN a[2]
    DIRECTION INPUT ;
    USE SIGNAL ;
    PORT
      LAYER M4 ;
        RECT  0 39.024 0.084 39.048 ;
    END
  END a[2]
  PIN a[300]
    DIRECTION INPUT ;
    USE SIGNAL ;
    PORT
      LAYER M4 ;
        RECT  0 49.68 0.084 49.704 ;
    END
  END a[300]
  PIN a[301]
    DIRECTION INPUT ;
    USE SIGNAL ;
    PORT
      LAYER M4 ;
        RECT  0 49.824 0.084 49.848 ;
    END
  END a[301]
  PIN a[302]
    DIRECTION INPUT ;
    USE SIGNAL ;
    PORT
      LAYER M4 ;
        RECT  0 49.968 0.084 49.992 ;
    END
  END a[302]
  PIN a[303]
    DIRECTION INPUT ;
    USE SIGNAL ;
    PORT
      LAYER M4 ;
        RECT  0 50.112 0.084 50.136 ;
    END
  END a[303]
  PIN a[304]
    DIRECTION INPUT ;
    USE SIGNAL ;
    PORT
      LAYER M4 ;
        RECT  0 50.256 0.084 50.28 ;
    END
  END a[304]
  PIN a[305]
    DIRECTION INPUT ;
    USE SIGNAL ;
    PORT
      LAYER M4 ;
        RECT  0 50.4 0.084 50.424 ;
    END
  END a[305]
  PIN a[306]
    DIRECTION INPUT ;
    USE SIGNAL ;
    PORT
      LAYER M4 ;
        RECT  0 50.544 0.084 50.568 ;
    END
  END a[306]
  PIN a[307]
    DIRECTION INPUT ;
    USE SIGNAL ;
    PORT
      LAYER M4 ;
        RECT  0 50.688 0.084 50.712 ;
    END
  END a[307]
  PIN a[308]
    DIRECTION INPUT ;
    USE SIGNAL ;
    PORT
      LAYER M4 ;
        RECT  0 50.832 0.084 50.856 ;
    END
  END a[308]
  PIN a[309]
    DIRECTION INPUT ;
    USE SIGNAL ;
    PORT
      LAYER M4 ;
        RECT  0 50.976 0.084 51 ;
    END
  END a[309]
  PIN a[30]
    DIRECTION INPUT ;
    USE SIGNAL ;
    PORT
      LAYER M4 ;
        RECT  0 43.056 0.084 43.08 ;
    END
  END a[30]
  PIN a[310]
    DIRECTION INPUT ;
    USE SIGNAL ;
    PORT
      LAYER M4 ;
        RECT  0 51.12 0.084 51.144 ;
    END
  END a[310]
  PIN a[311]
    DIRECTION INPUT ;
    USE SIGNAL ;
    PORT
      LAYER M4 ;
        RECT  0 51.264 0.084 51.288 ;
    END
  END a[311]
  PIN a[312]
    DIRECTION INPUT ;
    USE SIGNAL ;
    PORT
      LAYER M4 ;
        RECT  0 51.408 0.084 51.432 ;
    END
  END a[312]
  PIN a[313]
    DIRECTION INPUT ;
    USE SIGNAL ;
    PORT
      LAYER M4 ;
        RECT  0 51.552 0.084 51.576 ;
    END
  END a[313]
  PIN a[314]
    DIRECTION INPUT ;
    USE SIGNAL ;
    PORT
      LAYER M4 ;
        RECT  0 51.696 0.084 51.72 ;
    END
  END a[314]
  PIN a[315]
    DIRECTION INPUT ;
    USE SIGNAL ;
    PORT
      LAYER M4 ;
        RECT  0 51.84 0.084 51.864 ;
    END
  END a[315]
  PIN a[316]
    DIRECTION INPUT ;
    USE SIGNAL ;
    PORT
      LAYER M4 ;
        RECT  0 51.984 0.084 52.008 ;
    END
  END a[316]
  PIN a[317]
    DIRECTION INPUT ;
    USE SIGNAL ;
    PORT
      LAYER M4 ;
        RECT  0 52.128 0.084 52.152 ;
    END
  END a[317]
  PIN a[318]
    DIRECTION INPUT ;
    USE SIGNAL ;
    PORT
      LAYER M4 ;
        RECT  0 52.272 0.084 52.296 ;
    END
  END a[318]
  PIN a[319]
    DIRECTION INPUT ;
    USE SIGNAL ;
    PORT
      LAYER M4 ;
        RECT  0 52.416 0.084 52.44 ;
    END
  END a[319]
  PIN a[31]
    DIRECTION INPUT ;
    USE SIGNAL ;
    PORT
      LAYER M4 ;
        RECT  0 43.2 0.084 43.224 ;
    END
  END a[31]
  PIN a[320]
    DIRECTION INPUT ;
    USE SIGNAL ;
    PORT
      LAYER M4 ;
        RECT  0 24.912 0.084 24.936 ;
    END
  END a[320]
  PIN a[321]
    DIRECTION INPUT ;
    USE SIGNAL ;
    PORT
      LAYER M4 ;
        RECT  0 25.056 0.084 25.08 ;
    END
  END a[321]
  PIN a[322]
    DIRECTION INPUT ;
    USE SIGNAL ;
    PORT
      LAYER M4 ;
        RECT  0 25.2 0.084 25.224 ;
    END
  END a[322]
  PIN a[323]
    DIRECTION INPUT ;
    USE SIGNAL ;
    PORT
      LAYER M4 ;
        RECT  0 25.344 0.084 25.368 ;
    END
  END a[323]
  PIN a[324]
    DIRECTION INPUT ;
    USE SIGNAL ;
    PORT
      LAYER M4 ;
        RECT  0 25.488 0.084 25.512 ;
    END
  END a[324]
  PIN a[325]
    DIRECTION INPUT ;
    USE SIGNAL ;
    PORT
      LAYER M4 ;
        RECT  0 25.632 0.084 25.656 ;
    END
  END a[325]
  PIN a[326]
    DIRECTION INPUT ;
    USE SIGNAL ;
    PORT
      LAYER M4 ;
        RECT  0 25.776 0.084 25.8 ;
    END
  END a[326]
  PIN a[327]
    DIRECTION INPUT ;
    USE SIGNAL ;
    PORT
      LAYER M4 ;
        RECT  0 25.92 0.084 25.944 ;
    END
  END a[327]
  PIN a[328]
    DIRECTION INPUT ;
    USE SIGNAL ;
    PORT
      LAYER M4 ;
        RECT  0 26.064 0.084 26.088 ;
    END
  END a[328]
  PIN a[329]
    DIRECTION INPUT ;
    USE SIGNAL ;
    PORT
      LAYER M4 ;
        RECT  0 26.208 0.084 26.232 ;
    END
  END a[329]
  PIN a[32]
    DIRECTION INPUT ;
    USE SIGNAL ;
    PORT
      LAYER M4 ;
        RECT  0 34.128 0.084 34.152 ;
    END
  END a[32]
  PIN a[330]
    DIRECTION INPUT ;
    USE SIGNAL ;
    PORT
      LAYER M4 ;
        RECT  0 26.352 0.084 26.376 ;
    END
  END a[330]
  PIN a[331]
    DIRECTION INPUT ;
    USE SIGNAL ;
    PORT
      LAYER M4 ;
        RECT  0 26.496 0.084 26.52 ;
    END
  END a[331]
  PIN a[332]
    DIRECTION INPUT ;
    USE SIGNAL ;
    PORT
      LAYER M4 ;
        RECT  0 26.64 0.084 26.664 ;
    END
  END a[332]
  PIN a[333]
    DIRECTION INPUT ;
    USE SIGNAL ;
    PORT
      LAYER M4 ;
        RECT  0 26.784 0.084 26.808 ;
    END
  END a[333]
  PIN a[334]
    DIRECTION INPUT ;
    USE SIGNAL ;
    PORT
      LAYER M4 ;
        RECT  0 26.928 0.084 26.952 ;
    END
  END a[334]
  PIN a[335]
    DIRECTION INPUT ;
    USE SIGNAL ;
    PORT
      LAYER M4 ;
        RECT  0 27.072 0.084 27.096 ;
    END
  END a[335]
  PIN a[336]
    DIRECTION INPUT ;
    USE SIGNAL ;
    PORT
      LAYER M4 ;
        RECT  0 27.216 0.084 27.24 ;
    END
  END a[336]
  PIN a[337]
    DIRECTION INPUT ;
    USE SIGNAL ;
    PORT
      LAYER M4 ;
        RECT  0 27.36 0.084 27.384 ;
    END
  END a[337]
  PIN a[338]
    DIRECTION INPUT ;
    USE SIGNAL ;
    PORT
      LAYER M4 ;
        RECT  0 27.504 0.084 27.528 ;
    END
  END a[338]
  PIN a[339]
    DIRECTION INPUT ;
    USE SIGNAL ;
    PORT
      LAYER M4 ;
        RECT  0 27.648 0.084 27.672 ;
    END
  END a[339]
  PIN a[33]
    DIRECTION INPUT ;
    USE SIGNAL ;
    PORT
      LAYER M4 ;
        RECT  0 34.272 0.084 34.296 ;
    END
  END a[33]
  PIN a[340]
    DIRECTION INPUT ;
    USE SIGNAL ;
    PORT
      LAYER M4 ;
        RECT  0 27.792 0.084 27.816 ;
    END
  END a[340]
  PIN a[341]
    DIRECTION INPUT ;
    USE SIGNAL ;
    PORT
      LAYER M4 ;
        RECT  0 27.936 0.084 27.96 ;
    END
  END a[341]
  PIN a[342]
    DIRECTION INPUT ;
    USE SIGNAL ;
    PORT
      LAYER M4 ;
        RECT  0 28.08 0.084 28.104 ;
    END
  END a[342]
  PIN a[343]
    DIRECTION INPUT ;
    USE SIGNAL ;
    PORT
      LAYER M4 ;
        RECT  0 28.224 0.084 28.248 ;
    END
  END a[343]
  PIN a[344]
    DIRECTION INPUT ;
    USE SIGNAL ;
    PORT
      LAYER M4 ;
        RECT  0 28.368 0.084 28.392 ;
    END
  END a[344]
  PIN a[345]
    DIRECTION INPUT ;
    USE SIGNAL ;
    PORT
      LAYER M4 ;
        RECT  0 28.512 0.084 28.536 ;
    END
  END a[345]
  PIN a[346]
    DIRECTION INPUT ;
    USE SIGNAL ;
    PORT
      LAYER M4 ;
        RECT  0 28.656 0.084 28.68 ;
    END
  END a[346]
  PIN a[347]
    DIRECTION INPUT ;
    USE SIGNAL ;
    PORT
      LAYER M4 ;
        RECT  0 28.8 0.084 28.824 ;
    END
  END a[347]
  PIN a[348]
    DIRECTION INPUT ;
    USE SIGNAL ;
    PORT
      LAYER M4 ;
        RECT  0 28.944 0.084 28.968 ;
    END
  END a[348]
  PIN a[349]
    DIRECTION INPUT ;
    USE SIGNAL ;
    PORT
      LAYER M4 ;
        RECT  0 29.088 0.084 29.112 ;
    END
  END a[349]
  PIN a[34]
    DIRECTION INPUT ;
    USE SIGNAL ;
    PORT
      LAYER M4 ;
        RECT  0 34.416 0.084 34.44 ;
    END
  END a[34]
  PIN a[350]
    DIRECTION INPUT ;
    USE SIGNAL ;
    PORT
      LAYER M4 ;
        RECT  0 29.232 0.084 29.256 ;
    END
  END a[350]
  PIN a[351]
    DIRECTION INPUT ;
    USE SIGNAL ;
    PORT
      LAYER M4 ;
        RECT  0 29.376 0.084 29.4 ;
    END
  END a[351]
  PIN a[352]
    DIRECTION INPUT ;
    USE SIGNAL ;
    PORT
      LAYER M4 ;
        RECT  0 0.72 0.084 0.744 ;
    END
  END a[352]
  PIN a[353]
    DIRECTION INPUT ;
    USE SIGNAL ;
    PORT
      LAYER M4 ;
        RECT  0 0.864 0.084 0.888 ;
    END
  END a[353]
  PIN a[354]
    DIRECTION INPUT ;
    USE SIGNAL ;
    PORT
      LAYER M4 ;
        RECT  0 1.008 0.084 1.032 ;
    END
  END a[354]
  PIN a[355]
    DIRECTION INPUT ;
    USE SIGNAL ;
    PORT
      LAYER M4 ;
        RECT  0 1.152 0.084 1.176 ;
    END
  END a[355]
  PIN a[356]
    DIRECTION INPUT ;
    USE SIGNAL ;
    PORT
      LAYER M4 ;
        RECT  0 1.296 0.084 1.32 ;
    END
  END a[356]
  PIN a[357]
    DIRECTION INPUT ;
    USE SIGNAL ;
    PORT
      LAYER M4 ;
        RECT  0 1.44 0.084 1.464 ;
    END
  END a[357]
  PIN a[358]
    DIRECTION INPUT ;
    USE SIGNAL ;
    PORT
      LAYER M4 ;
        RECT  0 1.584 0.084 1.608 ;
    END
  END a[358]
  PIN a[359]
    DIRECTION INPUT ;
    USE SIGNAL ;
    PORT
      LAYER M4 ;
        RECT  0 1.728 0.084 1.752 ;
    END
  END a[359]
  PIN a[35]
    DIRECTION INPUT ;
    USE SIGNAL ;
    PORT
      LAYER M4 ;
        RECT  0 34.56 0.084 34.584 ;
    END
  END a[35]
  PIN a[360]
    DIRECTION INPUT ;
    USE SIGNAL ;
    PORT
      LAYER M4 ;
        RECT  0 1.872 0.084 1.896 ;
    END
  END a[360]
  PIN a[361]
    DIRECTION INPUT ;
    USE SIGNAL ;
    PORT
      LAYER M4 ;
        RECT  0 2.016 0.084 2.04 ;
    END
  END a[361]
  PIN a[362]
    DIRECTION INPUT ;
    USE SIGNAL ;
    PORT
      LAYER M4 ;
        RECT  0 2.16 0.084 2.184 ;
    END
  END a[362]
  PIN a[363]
    DIRECTION INPUT ;
    USE SIGNAL ;
    PORT
      LAYER M4 ;
        RECT  0 2.304 0.084 2.328 ;
    END
  END a[363]
  PIN a[364]
    DIRECTION INPUT ;
    USE SIGNAL ;
    PORT
      LAYER M4 ;
        RECT  0 2.448 0.084 2.472 ;
    END
  END a[364]
  PIN a[365]
    DIRECTION INPUT ;
    USE SIGNAL ;
    PORT
      LAYER M4 ;
        RECT  0 2.592 0.084 2.616 ;
    END
  END a[365]
  PIN a[366]
    DIRECTION INPUT ;
    USE SIGNAL ;
    PORT
      LAYER M4 ;
        RECT  0 2.736 0.084 2.76 ;
    END
  END a[366]
  PIN a[367]
    DIRECTION INPUT ;
    USE SIGNAL ;
    PORT
      LAYER M4 ;
        RECT  0 2.88 0.084 2.904 ;
    END
  END a[367]
  PIN a[368]
    DIRECTION INPUT ;
    USE SIGNAL ;
    PORT
      LAYER M4 ;
        RECT  0 3.024 0.084 3.048 ;
    END
  END a[368]
  PIN a[369]
    DIRECTION INPUT ;
    USE SIGNAL ;
    PORT
      LAYER M4 ;
        RECT  0 3.168 0.084 3.192 ;
    END
  END a[369]
  PIN a[36]
    DIRECTION INPUT ;
    USE SIGNAL ;
    PORT
      LAYER M4 ;
        RECT  0 34.704 0.084 34.728 ;
    END
  END a[36]
  PIN a[370]
    DIRECTION INPUT ;
    USE SIGNAL ;
    PORT
      LAYER M4 ;
        RECT  0 3.312 0.084 3.336 ;
    END
  END a[370]
  PIN a[371]
    DIRECTION INPUT ;
    USE SIGNAL ;
    PORT
      LAYER M4 ;
        RECT  0 3.456 0.084 3.48 ;
    END
  END a[371]
  PIN a[372]
    DIRECTION INPUT ;
    USE SIGNAL ;
    PORT
      LAYER M4 ;
        RECT  0 3.6 0.084 3.624 ;
    END
  END a[372]
  PIN a[373]
    DIRECTION INPUT ;
    USE SIGNAL ;
    PORT
      LAYER M4 ;
        RECT  0 3.744 0.084 3.768 ;
    END
  END a[373]
  PIN a[374]
    DIRECTION INPUT ;
    USE SIGNAL ;
    PORT
      LAYER M4 ;
        RECT  0 3.888 0.084 3.912 ;
    END
  END a[374]
  PIN a[375]
    DIRECTION INPUT ;
    USE SIGNAL ;
    PORT
      LAYER M4 ;
        RECT  0 4.032 0.084 4.056 ;
    END
  END a[375]
  PIN a[376]
    DIRECTION INPUT ;
    USE SIGNAL ;
    PORT
      LAYER M4 ;
        RECT  0 4.176 0.084 4.2 ;
    END
  END a[376]
  PIN a[377]
    DIRECTION INPUT ;
    USE SIGNAL ;
    PORT
      LAYER M4 ;
        RECT  0 4.32 0.084 4.344 ;
    END
  END a[377]
  PIN a[378]
    DIRECTION INPUT ;
    USE SIGNAL ;
    PORT
      LAYER M4 ;
        RECT  0 4.464 0.084 4.488 ;
    END
  END a[378]
  PIN a[379]
    DIRECTION INPUT ;
    USE SIGNAL ;
    PORT
      LAYER M4 ;
        RECT  0 4.608 0.084 4.632 ;
    END
  END a[379]
  PIN a[37]
    DIRECTION INPUT ;
    USE SIGNAL ;
    PORT
      LAYER M4 ;
        RECT  0 34.848 0.084 34.872 ;
    END
  END a[37]
  PIN a[380]
    DIRECTION INPUT ;
    USE SIGNAL ;
    PORT
      LAYER M4 ;
        RECT  0 4.752 0.084 4.776 ;
    END
  END a[380]
  PIN a[381]
    DIRECTION INPUT ;
    USE SIGNAL ;
    PORT
      LAYER M4 ;
        RECT  0 4.896 0.084 4.92 ;
    END
  END a[381]
  PIN a[382]
    DIRECTION INPUT ;
    USE SIGNAL ;
    PORT
      LAYER M4 ;
        RECT  0 5.04 0.084 5.064 ;
    END
  END a[382]
  PIN a[383]
    DIRECTION INPUT ;
    USE SIGNAL ;
    PORT
      LAYER M4 ;
        RECT  0 5.184 0.084 5.208 ;
    END
  END a[383]
  PIN a[384]
    DIRECTION INPUT ;
    USE SIGNAL ;
    PORT
      LAYER M4 ;
        RECT  0 29.52 0.084 29.544 ;
    END
  END a[384]
  PIN a[385]
    DIRECTION INPUT ;
    USE SIGNAL ;
    PORT
      LAYER M4 ;
        RECT  0 29.664 0.084 29.688 ;
    END
  END a[385]
  PIN a[386]
    DIRECTION INPUT ;
    USE SIGNAL ;
    PORT
      LAYER M4 ;
        RECT  0 29.808 0.084 29.832 ;
    END
  END a[386]
  PIN a[387]
    DIRECTION INPUT ;
    USE SIGNAL ;
    PORT
      LAYER M4 ;
        RECT  0 29.952 0.084 29.976 ;
    END
  END a[387]
  PIN a[388]
    DIRECTION INPUT ;
    USE SIGNAL ;
    PORT
      LAYER M4 ;
        RECT  0 30.096 0.084 30.12 ;
    END
  END a[388]
  PIN a[389]
    DIRECTION INPUT ;
    USE SIGNAL ;
    PORT
      LAYER M4 ;
        RECT  0 30.24 0.084 30.264 ;
    END
  END a[389]
  PIN a[38]
    DIRECTION INPUT ;
    USE SIGNAL ;
    PORT
      LAYER M4 ;
        RECT  0 34.992 0.084 35.016 ;
    END
  END a[38]
  PIN a[390]
    DIRECTION INPUT ;
    USE SIGNAL ;
    PORT
      LAYER M4 ;
        RECT  0 30.384 0.084 30.408 ;
    END
  END a[390]
  PIN a[391]
    DIRECTION INPUT ;
    USE SIGNAL ;
    PORT
      LAYER M4 ;
        RECT  0 30.528 0.084 30.552 ;
    END
  END a[391]
  PIN a[392]
    DIRECTION INPUT ;
    USE SIGNAL ;
    PORT
      LAYER M4 ;
        RECT  0 30.672 0.084 30.696 ;
    END
  END a[392]
  PIN a[393]
    DIRECTION INPUT ;
    USE SIGNAL ;
    PORT
      LAYER M4 ;
        RECT  0 30.816 0.084 30.84 ;
    END
  END a[393]
  PIN a[394]
    DIRECTION INPUT ;
    USE SIGNAL ;
    PORT
      LAYER M4 ;
        RECT  0 30.96 0.084 30.984 ;
    END
  END a[394]
  PIN a[395]
    DIRECTION INPUT ;
    USE SIGNAL ;
    PORT
      LAYER M4 ;
        RECT  0 31.104 0.084 31.128 ;
    END
  END a[395]
  PIN a[396]
    DIRECTION INPUT ;
    USE SIGNAL ;
    PORT
      LAYER M4 ;
        RECT  0 31.248 0.084 31.272 ;
    END
  END a[396]
  PIN a[397]
    DIRECTION INPUT ;
    USE SIGNAL ;
    PORT
      LAYER M4 ;
        RECT  0 31.392 0.084 31.416 ;
    END
  END a[397]
  PIN a[398]
    DIRECTION INPUT ;
    USE SIGNAL ;
    PORT
      LAYER M4 ;
        RECT  0 31.536 0.084 31.56 ;
    END
  END a[398]
  PIN a[399]
    DIRECTION INPUT ;
    USE SIGNAL ;
    PORT
      LAYER M4 ;
        RECT  0 31.68 0.084 31.704 ;
    END
  END a[399]
  PIN a[39]
    DIRECTION INPUT ;
    USE SIGNAL ;
    PORT
      LAYER M4 ;
        RECT  0 35.136 0.084 35.16 ;
    END
  END a[39]
  PIN a[3]
    DIRECTION INPUT ;
    USE SIGNAL ;
    PORT
      LAYER M4 ;
        RECT  0 39.168 0.084 39.192 ;
    END
  END a[3]
  PIN a[400]
    DIRECTION INPUT ;
    USE SIGNAL ;
    PORT
      LAYER M4 ;
        RECT  0 31.824 0.084 31.848 ;
    END
  END a[400]
  PIN a[401]
    DIRECTION INPUT ;
    USE SIGNAL ;
    PORT
      LAYER M4 ;
        RECT  0 31.968 0.084 31.992 ;
    END
  END a[401]
  PIN a[402]
    DIRECTION INPUT ;
    USE SIGNAL ;
    PORT
      LAYER M4 ;
        RECT  0 32.112 0.084 32.136 ;
    END
  END a[402]
  PIN a[403]
    DIRECTION INPUT ;
    USE SIGNAL ;
    PORT
      LAYER M4 ;
        RECT  0 32.256 0.084 32.28 ;
    END
  END a[403]
  PIN a[404]
    DIRECTION INPUT ;
    USE SIGNAL ;
    PORT
      LAYER M4 ;
        RECT  0 32.4 0.084 32.424 ;
    END
  END a[404]
  PIN a[405]
    DIRECTION INPUT ;
    USE SIGNAL ;
    PORT
      LAYER M4 ;
        RECT  0 32.544 0.084 32.568 ;
    END
  END a[405]
  PIN a[406]
    DIRECTION INPUT ;
    USE SIGNAL ;
    PORT
      LAYER M4 ;
        RECT  0 32.688 0.084 32.712 ;
    END
  END a[406]
  PIN a[407]
    DIRECTION INPUT ;
    USE SIGNAL ;
    PORT
      LAYER M4 ;
        RECT  0 32.832 0.084 32.856 ;
    END
  END a[407]
  PIN a[408]
    DIRECTION INPUT ;
    USE SIGNAL ;
    PORT
      LAYER M4 ;
        RECT  0 32.976 0.084 33 ;
    END
  END a[408]
  PIN a[409]
    DIRECTION INPUT ;
    USE SIGNAL ;
    PORT
      LAYER M4 ;
        RECT  0 33.12 0.084 33.144 ;
    END
  END a[409]
  PIN a[40]
    DIRECTION INPUT ;
    USE SIGNAL ;
    PORT
      LAYER M4 ;
        RECT  0 35.28 0.084 35.304 ;
    END
  END a[40]
  PIN a[410]
    DIRECTION INPUT ;
    USE SIGNAL ;
    PORT
      LAYER M4 ;
        RECT  0 33.264 0.084 33.288 ;
    END
  END a[410]
  PIN a[411]
    DIRECTION INPUT ;
    USE SIGNAL ;
    PORT
      LAYER M4 ;
        RECT  0 33.408 0.084 33.432 ;
    END
  END a[411]
  PIN a[412]
    DIRECTION INPUT ;
    USE SIGNAL ;
    PORT
      LAYER M4 ;
        RECT  0 33.552 0.084 33.576 ;
    END
  END a[412]
  PIN a[413]
    DIRECTION INPUT ;
    USE SIGNAL ;
    PORT
      LAYER M4 ;
        RECT  0 33.696 0.084 33.72 ;
    END
  END a[413]
  PIN a[414]
    DIRECTION INPUT ;
    USE SIGNAL ;
    PORT
      LAYER M4 ;
        RECT  0 33.84 0.084 33.864 ;
    END
  END a[414]
  PIN a[415]
    DIRECTION INPUT ;
    USE SIGNAL ;
    PORT
      LAYER M4 ;
        RECT  0 33.984 0.084 34.008 ;
    END
  END a[415]
  PIN a[416]
    DIRECTION INPUT ;
    USE SIGNAL ;
    PORT
      LAYER M4 ;
        RECT  0 14.544 0.084 14.568 ;
    END
  END a[416]
  PIN a[417]
    DIRECTION INPUT ;
    USE SIGNAL ;
    PORT
      LAYER M4 ;
        RECT  0 14.688 0.084 14.712 ;
    END
  END a[417]
  PIN a[418]
    DIRECTION INPUT ;
    USE SIGNAL ;
    PORT
      LAYER M4 ;
        RECT  0 14.832 0.084 14.856 ;
    END
  END a[418]
  PIN a[419]
    DIRECTION INPUT ;
    USE SIGNAL ;
    PORT
      LAYER M4 ;
        RECT  0 14.976 0.084 15 ;
    END
  END a[419]
  PIN a[41]
    DIRECTION INPUT ;
    USE SIGNAL ;
    PORT
      LAYER M4 ;
        RECT  0 35.424 0.084 35.448 ;
    END
  END a[41]
  PIN a[420]
    DIRECTION INPUT ;
    USE SIGNAL ;
    PORT
      LAYER M4 ;
        RECT  0 15.12 0.084 15.144 ;
    END
  END a[420]
  PIN a[421]
    DIRECTION INPUT ;
    USE SIGNAL ;
    PORT
      LAYER M4 ;
        RECT  0 15.264 0.084 15.288 ;
    END
  END a[421]
  PIN a[422]
    DIRECTION INPUT ;
    USE SIGNAL ;
    PORT
      LAYER M4 ;
        RECT  0 15.408 0.084 15.432 ;
    END
  END a[422]
  PIN a[423]
    DIRECTION INPUT ;
    USE SIGNAL ;
    PORT
      LAYER M4 ;
        RECT  0 15.552 0.084 15.576 ;
    END
  END a[423]
  PIN a[424]
    DIRECTION INPUT ;
    USE SIGNAL ;
    PORT
      LAYER M4 ;
        RECT  0 15.696 0.084 15.72 ;
    END
  END a[424]
  PIN a[425]
    DIRECTION INPUT ;
    USE SIGNAL ;
    PORT
      LAYER M4 ;
        RECT  0 15.84 0.084 15.864 ;
    END
  END a[425]
  PIN a[426]
    DIRECTION INPUT ;
    USE SIGNAL ;
    PORT
      LAYER M4 ;
        RECT  0 15.984 0.084 16.008 ;
    END
  END a[426]
  PIN a[427]
    DIRECTION INPUT ;
    USE SIGNAL ;
    PORT
      LAYER M4 ;
        RECT  0 16.128 0.084 16.152 ;
    END
  END a[427]
  PIN a[428]
    DIRECTION INPUT ;
    USE SIGNAL ;
    PORT
      LAYER M4 ;
        RECT  0 16.272 0.084 16.296 ;
    END
  END a[428]
  PIN a[429]
    DIRECTION INPUT ;
    USE SIGNAL ;
    PORT
      LAYER M4 ;
        RECT  0 16.416 0.084 16.44 ;
    END
  END a[429]
  PIN a[42]
    DIRECTION INPUT ;
    USE SIGNAL ;
    PORT
      LAYER M4 ;
        RECT  0 35.568 0.084 35.592 ;
    END
  END a[42]
  PIN a[430]
    DIRECTION INPUT ;
    USE SIGNAL ;
    PORT
      LAYER M4 ;
        RECT  0 16.56 0.084 16.584 ;
    END
  END a[430]
  PIN a[431]
    DIRECTION INPUT ;
    USE SIGNAL ;
    PORT
      LAYER M4 ;
        RECT  0 16.704 0.084 16.728 ;
    END
  END a[431]
  PIN a[432]
    DIRECTION INPUT ;
    USE SIGNAL ;
    PORT
      LAYER M4 ;
        RECT  0 16.848 0.084 16.872 ;
    END
  END a[432]
  PIN a[433]
    DIRECTION INPUT ;
    USE SIGNAL ;
    PORT
      LAYER M4 ;
        RECT  0 16.992 0.084 17.016 ;
    END
  END a[433]
  PIN a[434]
    DIRECTION INPUT ;
    USE SIGNAL ;
    PORT
      LAYER M4 ;
        RECT  0 17.136 0.084 17.16 ;
    END
  END a[434]
  PIN a[435]
    DIRECTION INPUT ;
    USE SIGNAL ;
    PORT
      LAYER M4 ;
        RECT  0 17.28 0.084 17.304 ;
    END
  END a[435]
  PIN a[436]
    DIRECTION INPUT ;
    USE SIGNAL ;
    PORT
      LAYER M4 ;
        RECT  0 17.424 0.084 17.448 ;
    END
  END a[436]
  PIN a[437]
    DIRECTION INPUT ;
    USE SIGNAL ;
    PORT
      LAYER M4 ;
        RECT  0 17.568 0.084 17.592 ;
    END
  END a[437]
  PIN a[438]
    DIRECTION INPUT ;
    USE SIGNAL ;
    PORT
      LAYER M4 ;
        RECT  0 17.712 0.084 17.736 ;
    END
  END a[438]
  PIN a[439]
    DIRECTION INPUT ;
    USE SIGNAL ;
    PORT
      LAYER M4 ;
        RECT  0 17.856 0.084 17.88 ;
    END
  END a[439]
  PIN a[43]
    DIRECTION INPUT ;
    USE SIGNAL ;
    PORT
      LAYER M4 ;
        RECT  0 35.712 0.084 35.736 ;
    END
  END a[43]
  PIN a[440]
    DIRECTION INPUT ;
    USE SIGNAL ;
    PORT
      LAYER M4 ;
        RECT  0 18 0.084 18.024 ;
    END
  END a[440]
  PIN a[441]
    DIRECTION INPUT ;
    USE SIGNAL ;
    PORT
      LAYER M4 ;
        RECT  0 18.144 0.084 18.168 ;
    END
  END a[441]
  PIN a[442]
    DIRECTION INPUT ;
    USE SIGNAL ;
    PORT
      LAYER M4 ;
        RECT  0 18.288 0.084 18.312 ;
    END
  END a[442]
  PIN a[443]
    DIRECTION INPUT ;
    USE SIGNAL ;
    PORT
      LAYER M4 ;
        RECT  0 18.432 0.084 18.456 ;
    END
  END a[443]
  PIN a[444]
    DIRECTION INPUT ;
    USE SIGNAL ;
    PORT
      LAYER M4 ;
        RECT  0 18.576 0.084 18.6 ;
    END
  END a[444]
  PIN a[445]
    DIRECTION INPUT ;
    USE SIGNAL ;
    PORT
      LAYER M4 ;
        RECT  0 18.72 0.084 18.744 ;
    END
  END a[445]
  PIN a[446]
    DIRECTION INPUT ;
    USE SIGNAL ;
    PORT
      LAYER M4 ;
        RECT  0 18.864 0.084 18.888 ;
    END
  END a[446]
  PIN a[447]
    DIRECTION INPUT ;
    USE SIGNAL ;
    PORT
      LAYER M4 ;
        RECT  0 19.008 0.084 19.032 ;
    END
  END a[447]
  PIN a[448]
    DIRECTION INPUT ;
    USE SIGNAL ;
    PORT
      LAYER M4 ;
        RECT  0 5.328 0.084 5.352 ;
    END
  END a[448]
  PIN a[449]
    DIRECTION INPUT ;
    USE SIGNAL ;
    PORT
      LAYER M4 ;
        RECT  0 5.472 0.084 5.496 ;
    END
  END a[449]
  PIN a[44]
    DIRECTION INPUT ;
    USE SIGNAL ;
    PORT
      LAYER M4 ;
        RECT  0 35.856 0.084 35.88 ;
    END
  END a[44]
  PIN a[450]
    DIRECTION INPUT ;
    USE SIGNAL ;
    PORT
      LAYER M4 ;
        RECT  0 5.616 0.084 5.64 ;
    END
  END a[450]
  PIN a[451]
    DIRECTION INPUT ;
    USE SIGNAL ;
    PORT
      LAYER M4 ;
        RECT  0 5.76 0.084 5.784 ;
    END
  END a[451]
  PIN a[452]
    DIRECTION INPUT ;
    USE SIGNAL ;
    PORT
      LAYER M4 ;
        RECT  0 5.904 0.084 5.928 ;
    END
  END a[452]
  PIN a[453]
    DIRECTION INPUT ;
    USE SIGNAL ;
    PORT
      LAYER M4 ;
        RECT  0 6.048 0.084 6.072 ;
    END
  END a[453]
  PIN a[454]
    DIRECTION INPUT ;
    USE SIGNAL ;
    PORT
      LAYER M4 ;
        RECT  0 6.192 0.084 6.216 ;
    END
  END a[454]
  PIN a[455]
    DIRECTION INPUT ;
    USE SIGNAL ;
    PORT
      LAYER M4 ;
        RECT  0 6.336 0.084 6.36 ;
    END
  END a[455]
  PIN a[456]
    DIRECTION INPUT ;
    USE SIGNAL ;
    PORT
      LAYER M4 ;
        RECT  0 6.48 0.084 6.504 ;
    END
  END a[456]
  PIN a[457]
    DIRECTION INPUT ;
    USE SIGNAL ;
    PORT
      LAYER M4 ;
        RECT  0 6.624 0.084 6.648 ;
    END
  END a[457]
  PIN a[458]
    DIRECTION INPUT ;
    USE SIGNAL ;
    PORT
      LAYER M4 ;
        RECT  0 6.768 0.084 6.792 ;
    END
  END a[458]
  PIN a[459]
    DIRECTION INPUT ;
    USE SIGNAL ;
    PORT
      LAYER M4 ;
        RECT  0 6.912 0.084 6.936 ;
    END
  END a[459]
  PIN a[45]
    DIRECTION INPUT ;
    USE SIGNAL ;
    PORT
      LAYER M4 ;
        RECT  0 36 0.084 36.024 ;
    END
  END a[45]
  PIN a[460]
    DIRECTION INPUT ;
    USE SIGNAL ;
    PORT
      LAYER M4 ;
        RECT  0 7.056 0.084 7.08 ;
    END
  END a[460]
  PIN a[461]
    DIRECTION INPUT ;
    USE SIGNAL ;
    PORT
      LAYER M4 ;
        RECT  0 7.2 0.084 7.224 ;
    END
  END a[461]
  PIN a[462]
    DIRECTION INPUT ;
    USE SIGNAL ;
    PORT
      LAYER M4 ;
        RECT  0 7.344 0.084 7.368 ;
    END
  END a[462]
  PIN a[463]
    DIRECTION INPUT ;
    USE SIGNAL ;
    PORT
      LAYER M4 ;
        RECT  0 7.488 0.084 7.512 ;
    END
  END a[463]
  PIN a[464]
    DIRECTION INPUT ;
    USE SIGNAL ;
    PORT
      LAYER M4 ;
        RECT  0 7.632 0.084 7.656 ;
    END
  END a[464]
  PIN a[465]
    DIRECTION INPUT ;
    USE SIGNAL ;
    PORT
      LAYER M4 ;
        RECT  0 7.776 0.084 7.8 ;
    END
  END a[465]
  PIN a[466]
    DIRECTION INPUT ;
    USE SIGNAL ;
    PORT
      LAYER M4 ;
        RECT  0 7.92 0.084 7.944 ;
    END
  END a[466]
  PIN a[467]
    DIRECTION INPUT ;
    USE SIGNAL ;
    PORT
      LAYER M4 ;
        RECT  0 8.064 0.084 8.088 ;
    END
  END a[467]
  PIN a[468]
    DIRECTION INPUT ;
    USE SIGNAL ;
    PORT
      LAYER M4 ;
        RECT  0 8.208 0.084 8.232 ;
    END
  END a[468]
  PIN a[469]
    DIRECTION INPUT ;
    USE SIGNAL ;
    PORT
      LAYER M4 ;
        RECT  0 8.352 0.084 8.376 ;
    END
  END a[469]
  PIN a[46]
    DIRECTION INPUT ;
    USE SIGNAL ;
    PORT
      LAYER M4 ;
        RECT  0 36.144 0.084 36.168 ;
    END
  END a[46]
  PIN a[470]
    DIRECTION INPUT ;
    USE SIGNAL ;
    PORT
      LAYER M4 ;
        RECT  0 8.496 0.084 8.52 ;
    END
  END a[470]
  PIN a[471]
    DIRECTION INPUT ;
    USE SIGNAL ;
    PORT
      LAYER M4 ;
        RECT  0 8.64 0.084 8.664 ;
    END
  END a[471]
  PIN a[472]
    DIRECTION INPUT ;
    USE SIGNAL ;
    PORT
      LAYER M4 ;
        RECT  0 8.784 0.084 8.808 ;
    END
  END a[472]
  PIN a[473]
    DIRECTION INPUT ;
    USE SIGNAL ;
    PORT
      LAYER M4 ;
        RECT  0 8.928 0.084 8.952 ;
    END
  END a[473]
  PIN a[474]
    DIRECTION INPUT ;
    USE SIGNAL ;
    PORT
      LAYER M4 ;
        RECT  0 9.072 0.084 9.096 ;
    END
  END a[474]
  PIN a[475]
    DIRECTION INPUT ;
    USE SIGNAL ;
    PORT
      LAYER M4 ;
        RECT  0 9.216 0.084 9.24 ;
    END
  END a[475]
  PIN a[476]
    DIRECTION INPUT ;
    USE SIGNAL ;
    PORT
      LAYER M4 ;
        RECT  0 9.36 0.084 9.384 ;
    END
  END a[476]
  PIN a[477]
    DIRECTION INPUT ;
    USE SIGNAL ;
    PORT
      LAYER M4 ;
        RECT  0 9.504 0.084 9.528 ;
    END
  END a[477]
  PIN a[478]
    DIRECTION INPUT ;
    USE SIGNAL ;
    PORT
      LAYER M4 ;
        RECT  0 9.648 0.084 9.672 ;
    END
  END a[478]
  PIN a[479]
    DIRECTION INPUT ;
    USE SIGNAL ;
    PORT
      LAYER M4 ;
        RECT  0 9.792 0.084 9.816 ;
    END
  END a[479]
  PIN a[47]
    DIRECTION INPUT ;
    USE SIGNAL ;
    PORT
      LAYER M4 ;
        RECT  0 36.288 0.084 36.312 ;
    END
  END a[47]
  PIN a[480]
    DIRECTION INPUT ;
    USE SIGNAL ;
    PORT
      LAYER M4 ;
        RECT  0 9.936 0.084 9.96 ;
    END
  END a[480]
  PIN a[481]
    DIRECTION INPUT ;
    USE SIGNAL ;
    PORT
      LAYER M4 ;
        RECT  0 10.08 0.084 10.104 ;
    END
  END a[481]
  PIN a[482]
    DIRECTION INPUT ;
    USE SIGNAL ;
    PORT
      LAYER M4 ;
        RECT  0 10.224 0.084 10.248 ;
    END
  END a[482]
  PIN a[483]
    DIRECTION INPUT ;
    USE SIGNAL ;
    PORT
      LAYER M4 ;
        RECT  0 10.368 0.084 10.392 ;
    END
  END a[483]
  PIN a[484]
    DIRECTION INPUT ;
    USE SIGNAL ;
    PORT
      LAYER M4 ;
        RECT  0 10.512 0.084 10.536 ;
    END
  END a[484]
  PIN a[485]
    DIRECTION INPUT ;
    USE SIGNAL ;
    PORT
      LAYER M4 ;
        RECT  0 10.656 0.084 10.68 ;
    END
  END a[485]
  PIN a[486]
    DIRECTION INPUT ;
    USE SIGNAL ;
    PORT
      LAYER M4 ;
        RECT  0 10.8 0.084 10.824 ;
    END
  END a[486]
  PIN a[487]
    DIRECTION INPUT ;
    USE SIGNAL ;
    PORT
      LAYER M4 ;
        RECT  0 10.944 0.084 10.968 ;
    END
  END a[487]
  PIN a[488]
    DIRECTION INPUT ;
    USE SIGNAL ;
    PORT
      LAYER M4 ;
        RECT  0 11.088 0.084 11.112 ;
    END
  END a[488]
  PIN a[489]
    DIRECTION INPUT ;
    USE SIGNAL ;
    PORT
      LAYER M4 ;
        RECT  0 11.232 0.084 11.256 ;
    END
  END a[489]
  PIN a[48]
    DIRECTION INPUT ;
    USE SIGNAL ;
    PORT
      LAYER M4 ;
        RECT  0 36.432 0.084 36.456 ;
    END
  END a[48]
  PIN a[490]
    DIRECTION INPUT ;
    USE SIGNAL ;
    PORT
      LAYER M4 ;
        RECT  0 11.376 0.084 11.4 ;
    END
  END a[490]
  PIN a[491]
    DIRECTION INPUT ;
    USE SIGNAL ;
    PORT
      LAYER M4 ;
        RECT  0 11.52 0.084 11.544 ;
    END
  END a[491]
  PIN a[492]
    DIRECTION INPUT ;
    USE SIGNAL ;
    PORT
      LAYER M4 ;
        RECT  0 11.664 0.084 11.688 ;
    END
  END a[492]
  PIN a[493]
    DIRECTION INPUT ;
    USE SIGNAL ;
    PORT
      LAYER M4 ;
        RECT  0 11.808 0.084 11.832 ;
    END
  END a[493]
  PIN a[494]
    DIRECTION INPUT ;
    USE SIGNAL ;
    PORT
      LAYER M4 ;
        RECT  0 11.952 0.084 11.976 ;
    END
  END a[494]
  PIN a[495]
    DIRECTION INPUT ;
    USE SIGNAL ;
    PORT
      LAYER M4 ;
        RECT  0 12.096 0.084 12.12 ;
    END
  END a[495]
  PIN a[496]
    DIRECTION INPUT ;
    USE SIGNAL ;
    PORT
      LAYER M4 ;
        RECT  0 12.24 0.084 12.264 ;
    END
  END a[496]
  PIN a[497]
    DIRECTION INPUT ;
    USE SIGNAL ;
    PORT
      LAYER M4 ;
        RECT  0 12.384 0.084 12.408 ;
    END
  END a[497]
  PIN a[498]
    DIRECTION INPUT ;
    USE SIGNAL ;
    PORT
      LAYER M4 ;
        RECT  0 12.528 0.084 12.552 ;
    END
  END a[498]
  PIN a[499]
    DIRECTION INPUT ;
    USE SIGNAL ;
    PORT
      LAYER M4 ;
        RECT  0 12.672 0.084 12.696 ;
    END
  END a[499]
  PIN a[49]
    DIRECTION INPUT ;
    USE SIGNAL ;
    PORT
      LAYER M4 ;
        RECT  0 36.576 0.084 36.6 ;
    END
  END a[49]
  PIN a[4]
    DIRECTION INPUT ;
    USE SIGNAL ;
    PORT
      LAYER M4 ;
        RECT  0 39.312 0.084 39.336 ;
    END
  END a[4]
  PIN a[500]
    DIRECTION INPUT ;
    USE SIGNAL ;
    PORT
      LAYER M4 ;
        RECT  0 12.816 0.084 12.84 ;
    END
  END a[500]
  PIN a[501]
    DIRECTION INPUT ;
    USE SIGNAL ;
    PORT
      LAYER M4 ;
        RECT  0 12.96 0.084 12.984 ;
    END
  END a[501]
  PIN a[502]
    DIRECTION INPUT ;
    USE SIGNAL ;
    PORT
      LAYER M4 ;
        RECT  0 13.104 0.084 13.128 ;
    END
  END a[502]
  PIN a[503]
    DIRECTION INPUT ;
    USE SIGNAL ;
    PORT
      LAYER M4 ;
        RECT  0 13.248 0.084 13.272 ;
    END
  END a[503]
  PIN a[504]
    DIRECTION INPUT ;
    USE SIGNAL ;
    PORT
      LAYER M4 ;
        RECT  0 13.392 0.084 13.416 ;
    END
  END a[504]
  PIN a[505]
    DIRECTION INPUT ;
    USE SIGNAL ;
    PORT
      LAYER M4 ;
        RECT  0 13.536 0.084 13.56 ;
    END
  END a[505]
  PIN a[506]
    DIRECTION INPUT ;
    USE SIGNAL ;
    PORT
      LAYER M4 ;
        RECT  0 13.68 0.084 13.704 ;
    END
  END a[506]
  PIN a[507]
    DIRECTION INPUT ;
    USE SIGNAL ;
    PORT
      LAYER M4 ;
        RECT  0 13.824 0.084 13.848 ;
    END
  END a[507]
  PIN a[508]
    DIRECTION INPUT ;
    USE SIGNAL ;
    PORT
      LAYER M4 ;
        RECT  0 13.968 0.084 13.992 ;
    END
  END a[508]
  PIN a[509]
    DIRECTION INPUT ;
    USE SIGNAL ;
    PORT
      LAYER M4 ;
        RECT  0 14.112 0.084 14.136 ;
    END
  END a[509]
  PIN a[50]
    DIRECTION INPUT ;
    USE SIGNAL ;
    PORT
      LAYER M4 ;
        RECT  0 36.72 0.084 36.744 ;
    END
  END a[50]
  PIN a[510]
    DIRECTION INPUT ;
    USE SIGNAL ;
    PORT
      LAYER M4 ;
        RECT  0 14.256 0.084 14.28 ;
    END
  END a[510]
  PIN a[511]
    DIRECTION INPUT ;
    USE SIGNAL ;
    PORT
      LAYER M4 ;
        RECT  0 14.4 0.084 14.424 ;
    END
  END a[511]
  PIN a[512]
    DIRECTION INPUT ;
    USE SIGNAL ;
    PORT
      LAYER M4 ;
        RECT  0 21.456 0.084 21.48 ;
    END
  END a[512]
  PIN a[513]
    DIRECTION INPUT ;
    USE SIGNAL ;
    PORT
      LAYER M4 ;
        RECT  0 21.6 0.084 21.624 ;
    END
  END a[513]
  PIN a[514]
    DIRECTION INPUT ;
    USE SIGNAL ;
    PORT
      LAYER M4 ;
        RECT  0 21.744 0.084 21.768 ;
    END
  END a[514]
  PIN a[515]
    DIRECTION INPUT ;
    USE SIGNAL ;
    PORT
      LAYER M4 ;
        RECT  0 21.888 0.084 21.912 ;
    END
  END a[515]
  PIN a[516]
    DIRECTION INPUT ;
    USE SIGNAL ;
    PORT
      LAYER M4 ;
        RECT  0 22.032 0.084 22.056 ;
    END
  END a[516]
  PIN a[517]
    DIRECTION INPUT ;
    USE SIGNAL ;
    PORT
      LAYER M4 ;
        RECT  0 22.176 0.084 22.2 ;
    END
  END a[517]
  PIN a[518]
    DIRECTION INPUT ;
    USE SIGNAL ;
    PORT
      LAYER M4 ;
        RECT  0 22.32 0.084 22.344 ;
    END
  END a[518]
  PIN a[519]
    DIRECTION INPUT ;
    USE SIGNAL ;
    PORT
      LAYER M4 ;
        RECT  0 22.464 0.084 22.488 ;
    END
  END a[519]
  PIN a[51]
    DIRECTION INPUT ;
    USE SIGNAL ;
    PORT
      LAYER M4 ;
        RECT  0 36.864 0.084 36.888 ;
    END
  END a[51]
  PIN a[520]
    DIRECTION INPUT ;
    USE SIGNAL ;
    PORT
      LAYER M4 ;
        RECT  0 22.608 0.084 22.632 ;
    END
  END a[520]
  PIN a[521]
    DIRECTION INPUT ;
    USE SIGNAL ;
    PORT
      LAYER M4 ;
        RECT  0 22.752 0.084 22.776 ;
    END
  END a[521]
  PIN a[522]
    DIRECTION INPUT ;
    USE SIGNAL ;
    PORT
      LAYER M4 ;
        RECT  0 22.896 0.084 22.92 ;
    END
  END a[522]
  PIN a[523]
    DIRECTION INPUT ;
    USE SIGNAL ;
    PORT
      LAYER M4 ;
        RECT  0 23.04 0.084 23.064 ;
    END
  END a[523]
  PIN a[524]
    DIRECTION INPUT ;
    USE SIGNAL ;
    PORT
      LAYER M4 ;
        RECT  0 23.184 0.084 23.208 ;
    END
  END a[524]
  PIN a[525]
    DIRECTION INPUT ;
    USE SIGNAL ;
    PORT
      LAYER M4 ;
        RECT  0 23.328 0.084 23.352 ;
    END
  END a[525]
  PIN a[526]
    DIRECTION INPUT ;
    USE SIGNAL ;
    PORT
      LAYER M4 ;
        RECT  0 23.472 0.084 23.496 ;
    END
  END a[526]
  PIN a[527]
    DIRECTION INPUT ;
    USE SIGNAL ;
    PORT
      LAYER M4 ;
        RECT  0 23.616 0.084 23.64 ;
    END
  END a[527]
  PIN a[52]
    DIRECTION INPUT ;
    USE SIGNAL ;
    PORT
      LAYER M4 ;
        RECT  0 37.008 0.084 37.032 ;
    END
  END a[52]
  PIN a[53]
    DIRECTION INPUT ;
    USE SIGNAL ;
    PORT
      LAYER M4 ;
        RECT  0 37.152 0.084 37.176 ;
    END
  END a[53]
  PIN a[54]
    DIRECTION INPUT ;
    USE SIGNAL ;
    PORT
      LAYER M4 ;
        RECT  0 37.296 0.084 37.32 ;
    END
  END a[54]
  PIN a[55]
    DIRECTION INPUT ;
    USE SIGNAL ;
    PORT
      LAYER M4 ;
        RECT  0 37.44 0.084 37.464 ;
    END
  END a[55]
  PIN a[56]
    DIRECTION INPUT ;
    USE SIGNAL ;
    PORT
      LAYER M4 ;
        RECT  0 37.584 0.084 37.608 ;
    END
  END a[56]
  PIN a[57]
    DIRECTION INPUT ;
    USE SIGNAL ;
    PORT
      LAYER M4 ;
        RECT  0 37.728 0.084 37.752 ;
    END
  END a[57]
  PIN a[58]
    DIRECTION INPUT ;
    USE SIGNAL ;
    PORT
      LAYER M4 ;
        RECT  0 37.872 0.084 37.896 ;
    END
  END a[58]
  PIN a[59]
    DIRECTION INPUT ;
    USE SIGNAL ;
    PORT
      LAYER M4 ;
        RECT  0 38.016 0.084 38.04 ;
    END
  END a[59]
  PIN a[5]
    DIRECTION INPUT ;
    USE SIGNAL ;
    PORT
      LAYER M4 ;
        RECT  0 39.456 0.084 39.48 ;
    END
  END a[5]
  PIN a[60]
    DIRECTION INPUT ;
    USE SIGNAL ;
    PORT
      LAYER M4 ;
        RECT  0 38.16 0.084 38.184 ;
    END
  END a[60]
  PIN a[61]
    DIRECTION INPUT ;
    USE SIGNAL ;
    PORT
      LAYER M4 ;
        RECT  0 38.304 0.084 38.328 ;
    END
  END a[61]
  PIN a[62]
    DIRECTION INPUT ;
    USE SIGNAL ;
    PORT
      LAYER M4 ;
        RECT  0 38.448 0.084 38.472 ;
    END
  END a[62]
  PIN a[63]
    DIRECTION INPUT ;
    USE SIGNAL ;
    PORT
      LAYER M4 ;
        RECT  0 38.592 0.084 38.616 ;
    END
  END a[63]
  PIN a[64]
    DIRECTION INPUT ;
    USE SIGNAL ;
    PORT
      LAYER M4 ;
        RECT  0 53.712 0.084 53.736 ;
    END
  END a[64]
  PIN a[65]
    DIRECTION INPUT ;
    USE SIGNAL ;
    PORT
      LAYER M4 ;
        RECT  0 53.856 0.084 53.88 ;
    END
  END a[65]
  PIN a[66]
    DIRECTION INPUT ;
    USE SIGNAL ;
    PORT
      LAYER M4 ;
        RECT  0 54 0.084 54.024 ;
    END
  END a[66]
  PIN a[67]
    DIRECTION INPUT ;
    USE SIGNAL ;
    PORT
      LAYER M4 ;
        RECT  0 54.144 0.084 54.168 ;
    END
  END a[67]
  PIN a[68]
    DIRECTION INPUT ;
    USE SIGNAL ;
    PORT
      LAYER M4 ;
        RECT  0 54.288 0.084 54.312 ;
    END
  END a[68]
  PIN a[69]
    DIRECTION INPUT ;
    USE SIGNAL ;
    PORT
      LAYER M4 ;
        RECT  0 54.432 0.084 54.456 ;
    END
  END a[69]
  PIN a[6]
    DIRECTION INPUT ;
    USE SIGNAL ;
    PORT
      LAYER M4 ;
        RECT  0 39.6 0.084 39.624 ;
    END
  END a[6]
  PIN a[70]
    DIRECTION INPUT ;
    USE SIGNAL ;
    PORT
      LAYER M4 ;
        RECT  0 54.576 0.084 54.6 ;
    END
  END a[70]
  PIN a[71]
    DIRECTION INPUT ;
    USE SIGNAL ;
    PORT
      LAYER M4 ;
        RECT  0 54.72 0.084 54.744 ;
    END
  END a[71]
  PIN a[72]
    DIRECTION INPUT ;
    USE SIGNAL ;
    PORT
      LAYER M4 ;
        RECT  0 54.864 0.084 54.888 ;
    END
  END a[72]
  PIN a[73]
    DIRECTION INPUT ;
    USE SIGNAL ;
    PORT
      LAYER M4 ;
        RECT  0 55.008 0.084 55.032 ;
    END
  END a[73]
  PIN a[74]
    DIRECTION INPUT ;
    USE SIGNAL ;
    PORT
      LAYER M4 ;
        RECT  0 55.152 0.084 55.176 ;
    END
  END a[74]
  PIN a[75]
    DIRECTION INPUT ;
    USE SIGNAL ;
    PORT
      LAYER M4 ;
        RECT  0 55.296 0.084 55.32 ;
    END
  END a[75]
  PIN a[76]
    DIRECTION INPUT ;
    USE SIGNAL ;
    PORT
      LAYER M4 ;
        RECT  0 55.44 0.084 55.464 ;
    END
  END a[76]
  PIN a[77]
    DIRECTION INPUT ;
    USE SIGNAL ;
    PORT
      LAYER M4 ;
        RECT  0 55.584 0.084 55.608 ;
    END
  END a[77]
  PIN a[78]
    DIRECTION INPUT ;
    USE SIGNAL ;
    PORT
      LAYER M4 ;
        RECT  0 55.728 0.084 55.752 ;
    END
  END a[78]
  PIN a[79]
    DIRECTION INPUT ;
    USE SIGNAL ;
    PORT
      LAYER M4 ;
        RECT  0 55.872 0.084 55.896 ;
    END
  END a[79]
  PIN a[7]
    DIRECTION INPUT ;
    USE SIGNAL ;
    PORT
      LAYER M4 ;
        RECT  0 39.744 0.084 39.768 ;
    END
  END a[7]
  PIN a[80]
    DIRECTION INPUT ;
    USE SIGNAL ;
    PORT
      LAYER M4 ;
        RECT  0 56.016 0.084 56.04 ;
    END
  END a[80]
  PIN a[81]
    DIRECTION INPUT ;
    USE SIGNAL ;
    PORT
      LAYER M4 ;
        RECT  0 56.16 0.084 56.184 ;
    END
  END a[81]
  PIN a[82]
    DIRECTION INPUT ;
    USE SIGNAL ;
    PORT
      LAYER M4 ;
        RECT  0 56.304 0.084 56.328 ;
    END
  END a[82]
  PIN a[83]
    DIRECTION INPUT ;
    USE SIGNAL ;
    PORT
      LAYER M4 ;
        RECT  0 56.448 0.084 56.472 ;
    END
  END a[83]
  PIN a[84]
    DIRECTION INPUT ;
    USE SIGNAL ;
    PORT
      LAYER M4 ;
        RECT  0 56.592 0.084 56.616 ;
    END
  END a[84]
  PIN a[85]
    DIRECTION INPUT ;
    USE SIGNAL ;
    PORT
      LAYER M4 ;
        RECT  0 56.736 0.084 56.76 ;
    END
  END a[85]
  PIN a[86]
    DIRECTION INPUT ;
    USE SIGNAL ;
    PORT
      LAYER M4 ;
        RECT  0 56.88 0.084 56.904 ;
    END
  END a[86]
  PIN a[87]
    DIRECTION INPUT ;
    USE SIGNAL ;
    PORT
      LAYER M4 ;
        RECT  0 57.024 0.084 57.048 ;
    END
  END a[87]
  PIN a[88]
    DIRECTION INPUT ;
    USE SIGNAL ;
    PORT
      LAYER M4 ;
        RECT  0 57.168 0.084 57.192 ;
    END
  END a[88]
  PIN a[89]
    DIRECTION INPUT ;
    USE SIGNAL ;
    PORT
      LAYER M4 ;
        RECT  0 57.312 0.084 57.336 ;
    END
  END a[89]
  PIN a[8]
    DIRECTION INPUT ;
    USE SIGNAL ;
    PORT
      LAYER M4 ;
        RECT  0 39.888 0.084 39.912 ;
    END
  END a[8]
  PIN a[90]
    DIRECTION INPUT ;
    USE SIGNAL ;
    PORT
      LAYER M4 ;
        RECT  0 57.456 0.084 57.48 ;
    END
  END a[90]
  PIN a[91]
    DIRECTION INPUT ;
    USE SIGNAL ;
    PORT
      LAYER M4 ;
        RECT  0 57.6 0.084 57.624 ;
    END
  END a[91]
  PIN a[92]
    DIRECTION INPUT ;
    USE SIGNAL ;
    PORT
      LAYER M4 ;
        RECT  0 57.744 0.084 57.768 ;
    END
  END a[92]
  PIN a[93]
    DIRECTION INPUT ;
    USE SIGNAL ;
    PORT
      LAYER M4 ;
        RECT  0 57.888 0.084 57.912 ;
    END
  END a[93]
  PIN a[94]
    DIRECTION INPUT ;
    USE SIGNAL ;
    PORT
      LAYER M4 ;
        RECT  0 58.032 0.084 58.056 ;
    END
  END a[94]
  PIN a[95]
    DIRECTION INPUT ;
    USE SIGNAL ;
    PORT
      LAYER M4 ;
        RECT  0 58.176 0.084 58.2 ;
    END
  END a[95]
  PIN a[96]
    DIRECTION INPUT ;
    USE SIGNAL ;
    PORT
      LAYER M4 ;
        RECT  0 72.144 0.084 72.168 ;
    END
  END a[96]
  PIN a[97]
    DIRECTION INPUT ;
    USE SIGNAL ;
    PORT
      LAYER M4 ;
        RECT  0 72.288 0.084 72.312 ;
    END
  END a[97]
  PIN a[98]
    DIRECTION INPUT ;
    USE SIGNAL ;
    PORT
      LAYER M4 ;
        RECT  0 72.432 0.084 72.456 ;
    END
  END a[98]
  PIN a[99]
    DIRECTION INPUT ;
    USE SIGNAL ;
    PORT
      LAYER M4 ;
        RECT  0 72.576 0.084 72.6 ;
    END
  END a[99]
  PIN a[9]
    DIRECTION INPUT ;
    USE SIGNAL ;
    PORT
      LAYER M4 ;
        RECT  0 40.032 0.084 40.056 ;
    END
  END a[9]
  PIN b[0]
    DIRECTION OUTPUT ;
    USE SIGNAL ;
    PORT
      LAYER M4 ;
        RECT  51.756 34.128 51.84 34.152 ;
    END
  END b[0]
  PIN b[100]
    DIRECTION OUTPUT ;
    USE SIGNAL ;
    PORT
      LAYER M4 ;
        RECT  51.756 72.72 51.84 72.744 ;
    END
  END b[100]
  PIN b[101]
    DIRECTION OUTPUT ;
    USE SIGNAL ;
    PORT
      LAYER M4 ;
        RECT  51.756 72.864 51.84 72.888 ;
    END
  END b[101]
  PIN b[102]
    DIRECTION OUTPUT ;
    USE SIGNAL ;
    PORT
      LAYER M4 ;
        RECT  51.756 73.008 51.84 73.032 ;
    END
  END b[102]
  PIN b[103]
    DIRECTION OUTPUT ;
    USE SIGNAL ;
    PORT
      LAYER M4 ;
        RECT  51.756 73.152 51.84 73.176 ;
    END
  END b[103]
  PIN b[104]
    DIRECTION OUTPUT ;
    USE SIGNAL ;
    PORT
      LAYER M4 ;
        RECT  51.756 73.296 51.84 73.32 ;
    END
  END b[104]
  PIN b[105]
    DIRECTION OUTPUT ;
    USE SIGNAL ;
    PORT
      LAYER M4 ;
        RECT  51.756 73.44 51.84 73.464 ;
    END
  END b[105]
  PIN b[106]
    DIRECTION OUTPUT ;
    USE SIGNAL ;
    PORT
      LAYER M4 ;
        RECT  51.756 73.584 51.84 73.608 ;
    END
  END b[106]
  PIN b[107]
    DIRECTION OUTPUT ;
    USE SIGNAL ;
    PORT
      LAYER M4 ;
        RECT  51.756 73.728 51.84 73.752 ;
    END
  END b[107]
  PIN b[108]
    DIRECTION OUTPUT ;
    USE SIGNAL ;
    PORT
      LAYER M4 ;
        RECT  51.756 73.872 51.84 73.896 ;
    END
  END b[108]
  PIN b[109]
    DIRECTION OUTPUT ;
    USE SIGNAL ;
    PORT
      LAYER M4 ;
        RECT  51.756 74.016 51.84 74.04 ;
    END
  END b[109]
  PIN b[10]
    DIRECTION OUTPUT ;
    USE SIGNAL ;
    PORT
      LAYER M4 ;
        RECT  51.756 35.568 51.84 35.592 ;
    END
  END b[10]
  PIN b[110]
    DIRECTION OUTPUT ;
    USE SIGNAL ;
    PORT
      LAYER M4 ;
        RECT  51.756 74.16 51.84 74.184 ;
    END
  END b[110]
  PIN b[111]
    DIRECTION OUTPUT ;
    USE SIGNAL ;
    PORT
      LAYER M4 ;
        RECT  51.756 74.304 51.84 74.328 ;
    END
  END b[111]
  PIN b[112]
    DIRECTION OUTPUT ;
    USE SIGNAL ;
    PORT
      LAYER M4 ;
        RECT  51.756 74.448 51.84 74.472 ;
    END
  END b[112]
  PIN b[113]
    DIRECTION OUTPUT ;
    USE SIGNAL ;
    PORT
      LAYER M4 ;
        RECT  51.756 74.592 51.84 74.616 ;
    END
  END b[113]
  PIN b[114]
    DIRECTION OUTPUT ;
    USE SIGNAL ;
    PORT
      LAYER M4 ;
        RECT  51.756 74.736 51.84 74.76 ;
    END
  END b[114]
  PIN b[115]
    DIRECTION OUTPUT ;
    USE SIGNAL ;
    PORT
      LAYER M4 ;
        RECT  51.756 74.88 51.84 74.904 ;
    END
  END b[115]
  PIN b[116]
    DIRECTION OUTPUT ;
    USE SIGNAL ;
    PORT
      LAYER M4 ;
        RECT  51.756 75.024 51.84 75.048 ;
    END
  END b[116]
  PIN b[117]
    DIRECTION OUTPUT ;
    USE SIGNAL ;
    PORT
      LAYER M4 ;
        RECT  51.756 75.168 51.84 75.192 ;
    END
  END b[117]
  PIN b[118]
    DIRECTION OUTPUT ;
    USE SIGNAL ;
    PORT
      LAYER M4 ;
        RECT  51.756 75.312 51.84 75.336 ;
    END
  END b[118]
  PIN b[119]
    DIRECTION OUTPUT ;
    USE SIGNAL ;
    PORT
      LAYER M4 ;
        RECT  51.756 75.456 51.84 75.48 ;
    END
  END b[119]
  PIN b[11]
    DIRECTION OUTPUT ;
    USE SIGNAL ;
    PORT
      LAYER M4 ;
        RECT  51.756 35.712 51.84 35.736 ;
    END
  END b[11]
  PIN b[120]
    DIRECTION OUTPUT ;
    USE SIGNAL ;
    PORT
      LAYER M4 ;
        RECT  51.756 75.6 51.84 75.624 ;
    END
  END b[120]
  PIN b[121]
    DIRECTION OUTPUT ;
    USE SIGNAL ;
    PORT
      LAYER M4 ;
        RECT  51.756 75.744 51.84 75.768 ;
    END
  END b[121]
  PIN b[122]
    DIRECTION OUTPUT ;
    USE SIGNAL ;
    PORT
      LAYER M4 ;
        RECT  51.756 75.888 51.84 75.912 ;
    END
  END b[122]
  PIN b[123]
    DIRECTION OUTPUT ;
    USE SIGNAL ;
    PORT
      LAYER M4 ;
        RECT  51.756 76.032 51.84 76.056 ;
    END
  END b[123]
  PIN b[124]
    DIRECTION OUTPUT ;
    USE SIGNAL ;
    PORT
      LAYER M4 ;
        RECT  51.756 76.176 51.84 76.2 ;
    END
  END b[124]
  PIN b[125]
    DIRECTION OUTPUT ;
    USE SIGNAL ;
    PORT
      LAYER M4 ;
        RECT  51.756 76.32 51.84 76.344 ;
    END
  END b[125]
  PIN b[126]
    DIRECTION OUTPUT ;
    USE SIGNAL ;
    PORT
      LAYER M4 ;
        RECT  51.756 76.464 51.84 76.488 ;
    END
  END b[126]
  PIN b[127]
    DIRECTION OUTPUT ;
    USE SIGNAL ;
    PORT
      LAYER M4 ;
        RECT  51.756 76.608 51.84 76.632 ;
    END
  END b[127]
  PIN b[128]
    DIRECTION OUTPUT ;
    USE SIGNAL ;
    PORT
      LAYER M4 ;
        RECT  51.756 67.536 51.84 67.56 ;
    END
  END b[128]
  PIN b[129]
    DIRECTION OUTPUT ;
    USE SIGNAL ;
    PORT
      LAYER M4 ;
        RECT  51.756 67.68 51.84 67.704 ;
    END
  END b[129]
  PIN b[12]
    DIRECTION OUTPUT ;
    USE SIGNAL ;
    PORT
      LAYER M4 ;
        RECT  51.756 35.856 51.84 35.88 ;
    END
  END b[12]
  PIN b[130]
    DIRECTION OUTPUT ;
    USE SIGNAL ;
    PORT
      LAYER M4 ;
        RECT  51.756 67.824 51.84 67.848 ;
    END
  END b[130]
  PIN b[131]
    DIRECTION OUTPUT ;
    USE SIGNAL ;
    PORT
      LAYER M4 ;
        RECT  51.756 67.968 51.84 67.992 ;
    END
  END b[131]
  PIN b[132]
    DIRECTION OUTPUT ;
    USE SIGNAL ;
    PORT
      LAYER M4 ;
        RECT  51.756 68.112 51.84 68.136 ;
    END
  END b[132]
  PIN b[133]
    DIRECTION OUTPUT ;
    USE SIGNAL ;
    PORT
      LAYER M4 ;
        RECT  51.756 68.256 51.84 68.28 ;
    END
  END b[133]
  PIN b[134]
    DIRECTION OUTPUT ;
    USE SIGNAL ;
    PORT
      LAYER M4 ;
        RECT  51.756 68.4 51.84 68.424 ;
    END
  END b[134]
  PIN b[135]
    DIRECTION OUTPUT ;
    USE SIGNAL ;
    PORT
      LAYER M4 ;
        RECT  51.756 68.544 51.84 68.568 ;
    END
  END b[135]
  PIN b[136]
    DIRECTION OUTPUT ;
    USE SIGNAL ;
    PORT
      LAYER M4 ;
        RECT  51.756 68.688 51.84 68.712 ;
    END
  END b[136]
  PIN b[137]
    DIRECTION OUTPUT ;
    USE SIGNAL ;
    PORT
      LAYER M4 ;
        RECT  51.756 68.832 51.84 68.856 ;
    END
  END b[137]
  PIN b[138]
    DIRECTION OUTPUT ;
    USE SIGNAL ;
    PORT
      LAYER M4 ;
        RECT  51.756 68.976 51.84 69 ;
    END
  END b[138]
  PIN b[139]
    DIRECTION OUTPUT ;
    USE SIGNAL ;
    PORT
      LAYER M4 ;
        RECT  51.756 69.12 51.84 69.144 ;
    END
  END b[139]
  PIN b[13]
    DIRECTION OUTPUT ;
    USE SIGNAL ;
    PORT
      LAYER M4 ;
        RECT  51.756 36 51.84 36.024 ;
    END
  END b[13]
  PIN b[140]
    DIRECTION OUTPUT ;
    USE SIGNAL ;
    PORT
      LAYER M4 ;
        RECT  51.756 69.264 51.84 69.288 ;
    END
  END b[140]
  PIN b[141]
    DIRECTION OUTPUT ;
    USE SIGNAL ;
    PORT
      LAYER M4 ;
        RECT  51.756 69.408 51.84 69.432 ;
    END
  END b[141]
  PIN b[142]
    DIRECTION OUTPUT ;
    USE SIGNAL ;
    PORT
      LAYER M4 ;
        RECT  51.756 69.552 51.84 69.576 ;
    END
  END b[142]
  PIN b[143]
    DIRECTION OUTPUT ;
    USE SIGNAL ;
    PORT
      LAYER M4 ;
        RECT  51.756 69.696 51.84 69.72 ;
    END
  END b[143]
  PIN b[144]
    DIRECTION OUTPUT ;
    USE SIGNAL ;
    PORT
      LAYER M4 ;
        RECT  51.756 69.84 51.84 69.864 ;
    END
  END b[144]
  PIN b[145]
    DIRECTION OUTPUT ;
    USE SIGNAL ;
    PORT
      LAYER M4 ;
        RECT  51.756 69.984 51.84 70.008 ;
    END
  END b[145]
  PIN b[146]
    DIRECTION OUTPUT ;
    USE SIGNAL ;
    PORT
      LAYER M4 ;
        RECT  51.756 70.128 51.84 70.152 ;
    END
  END b[146]
  PIN b[147]
    DIRECTION OUTPUT ;
    USE SIGNAL ;
    PORT
      LAYER M4 ;
        RECT  51.756 70.272 51.84 70.296 ;
    END
  END b[147]
  PIN b[148]
    DIRECTION OUTPUT ;
    USE SIGNAL ;
    PORT
      LAYER M4 ;
        RECT  51.756 70.416 51.84 70.44 ;
    END
  END b[148]
  PIN b[149]
    DIRECTION OUTPUT ;
    USE SIGNAL ;
    PORT
      LAYER M4 ;
        RECT  51.756 70.56 51.84 70.584 ;
    END
  END b[149]
  PIN b[14]
    DIRECTION OUTPUT ;
    USE SIGNAL ;
    PORT
      LAYER M4 ;
        RECT  51.756 36.144 51.84 36.168 ;
    END
  END b[14]
  PIN b[150]
    DIRECTION OUTPUT ;
    USE SIGNAL ;
    PORT
      LAYER M4 ;
        RECT  51.756 70.704 51.84 70.728 ;
    END
  END b[150]
  PIN b[151]
    DIRECTION OUTPUT ;
    USE SIGNAL ;
    PORT
      LAYER M4 ;
        RECT  51.756 70.848 51.84 70.872 ;
    END
  END b[151]
  PIN b[152]
    DIRECTION OUTPUT ;
    USE SIGNAL ;
    PORT
      LAYER M4 ;
        RECT  51.756 70.992 51.84 71.016 ;
    END
  END b[152]
  PIN b[153]
    DIRECTION OUTPUT ;
    USE SIGNAL ;
    PORT
      LAYER M4 ;
        RECT  51.756 71.136 51.84 71.16 ;
    END
  END b[153]
  PIN b[154]
    DIRECTION OUTPUT ;
    USE SIGNAL ;
    PORT
      LAYER M4 ;
        RECT  51.756 71.28 51.84 71.304 ;
    END
  END b[154]
  PIN b[155]
    DIRECTION OUTPUT ;
    USE SIGNAL ;
    PORT
      LAYER M4 ;
        RECT  51.756 71.424 51.84 71.448 ;
    END
  END b[155]
  PIN b[156]
    DIRECTION OUTPUT ;
    USE SIGNAL ;
    PORT
      LAYER M4 ;
        RECT  51.756 71.568 51.84 71.592 ;
    END
  END b[156]
  PIN b[157]
    DIRECTION OUTPUT ;
    USE SIGNAL ;
    PORT
      LAYER M4 ;
        RECT  51.756 71.712 51.84 71.736 ;
    END
  END b[157]
  PIN b[158]
    DIRECTION OUTPUT ;
    USE SIGNAL ;
    PORT
      LAYER M4 ;
        RECT  51.756 71.856 51.84 71.88 ;
    END
  END b[158]
  PIN b[159]
    DIRECTION OUTPUT ;
    USE SIGNAL ;
    PORT
      LAYER M4 ;
        RECT  51.756 72 51.84 72.024 ;
    END
  END b[159]
  PIN b[15]
    DIRECTION OUTPUT ;
    USE SIGNAL ;
    PORT
      LAYER M4 ;
        RECT  51.756 36.288 51.84 36.312 ;
    END
  END b[15]
  PIN b[160]
    DIRECTION OUTPUT ;
    USE SIGNAL ;
    PORT
      LAYER M4 ;
        RECT  51.756 47.952 51.84 47.976 ;
    END
  END b[160]
  PIN b[161]
    DIRECTION OUTPUT ;
    USE SIGNAL ;
    PORT
      LAYER M4 ;
        RECT  51.756 48.096 51.84 48.12 ;
    END
  END b[161]
  PIN b[162]
    DIRECTION OUTPUT ;
    USE SIGNAL ;
    PORT
      LAYER M4 ;
        RECT  51.756 48.24 51.84 48.264 ;
    END
  END b[162]
  PIN b[163]
    DIRECTION OUTPUT ;
    USE SIGNAL ;
    PORT
      LAYER M4 ;
        RECT  51.756 48.384 51.84 48.408 ;
    END
  END b[163]
  PIN b[164]
    DIRECTION OUTPUT ;
    USE SIGNAL ;
    PORT
      LAYER M4 ;
        RECT  51.756 48.528 51.84 48.552 ;
    END
  END b[164]
  PIN b[165]
    DIRECTION OUTPUT ;
    USE SIGNAL ;
    PORT
      LAYER M4 ;
        RECT  51.756 48.672 51.84 48.696 ;
    END
  END b[165]
  PIN b[166]
    DIRECTION OUTPUT ;
    USE SIGNAL ;
    PORT
      LAYER M4 ;
        RECT  51.756 48.816 51.84 48.84 ;
    END
  END b[166]
  PIN b[167]
    DIRECTION OUTPUT ;
    USE SIGNAL ;
    PORT
      LAYER M4 ;
        RECT  51.756 48.96 51.84 48.984 ;
    END
  END b[167]
  PIN b[168]
    DIRECTION OUTPUT ;
    USE SIGNAL ;
    PORT
      LAYER M4 ;
        RECT  51.756 49.104 51.84 49.128 ;
    END
  END b[168]
  PIN b[169]
    DIRECTION OUTPUT ;
    USE SIGNAL ;
    PORT
      LAYER M4 ;
        RECT  51.756 49.248 51.84 49.272 ;
    END
  END b[169]
  PIN b[16]
    DIRECTION OUTPUT ;
    USE SIGNAL ;
    PORT
      LAYER M4 ;
        RECT  51.756 36.432 51.84 36.456 ;
    END
  END b[16]
  PIN b[170]
    DIRECTION OUTPUT ;
    USE SIGNAL ;
    PORT
      LAYER M4 ;
        RECT  51.756 49.392 51.84 49.416 ;
    END
  END b[170]
  PIN b[171]
    DIRECTION OUTPUT ;
    USE SIGNAL ;
    PORT
      LAYER M4 ;
        RECT  51.756 49.536 51.84 49.56 ;
    END
  END b[171]
  PIN b[172]
    DIRECTION OUTPUT ;
    USE SIGNAL ;
    PORT
      LAYER M4 ;
        RECT  51.756 49.68 51.84 49.704 ;
    END
  END b[172]
  PIN b[173]
    DIRECTION OUTPUT ;
    USE SIGNAL ;
    PORT
      LAYER M4 ;
        RECT  51.756 49.824 51.84 49.848 ;
    END
  END b[173]
  PIN b[174]
    DIRECTION OUTPUT ;
    USE SIGNAL ;
    PORT
      LAYER M4 ;
        RECT  51.756 49.968 51.84 49.992 ;
    END
  END b[174]
  PIN b[175]
    DIRECTION OUTPUT ;
    USE SIGNAL ;
    PORT
      LAYER M4 ;
        RECT  51.756 50.112 51.84 50.136 ;
    END
  END b[175]
  PIN b[176]
    DIRECTION OUTPUT ;
    USE SIGNAL ;
    PORT
      LAYER M4 ;
        RECT  51.756 50.256 51.84 50.28 ;
    END
  END b[176]
  PIN b[177]
    DIRECTION OUTPUT ;
    USE SIGNAL ;
    PORT
      LAYER M4 ;
        RECT  51.756 50.4 51.84 50.424 ;
    END
  END b[177]
  PIN b[178]
    DIRECTION OUTPUT ;
    USE SIGNAL ;
    PORT
      LAYER M4 ;
        RECT  51.756 50.544 51.84 50.568 ;
    END
  END b[178]
  PIN b[179]
    DIRECTION OUTPUT ;
    USE SIGNAL ;
    PORT
      LAYER M4 ;
        RECT  51.756 50.688 51.84 50.712 ;
    END
  END b[179]
  PIN b[17]
    DIRECTION OUTPUT ;
    USE SIGNAL ;
    PORT
      LAYER M4 ;
        RECT  51.756 36.576 51.84 36.6 ;
    END
  END b[17]
  PIN b[180]
    DIRECTION OUTPUT ;
    USE SIGNAL ;
    PORT
      LAYER M4 ;
        RECT  51.756 50.832 51.84 50.856 ;
    END
  END b[180]
  PIN b[181]
    DIRECTION OUTPUT ;
    USE SIGNAL ;
    PORT
      LAYER M4 ;
        RECT  51.756 50.976 51.84 51 ;
    END
  END b[181]
  PIN b[182]
    DIRECTION OUTPUT ;
    USE SIGNAL ;
    PORT
      LAYER M4 ;
        RECT  51.756 51.12 51.84 51.144 ;
    END
  END b[182]
  PIN b[183]
    DIRECTION OUTPUT ;
    USE SIGNAL ;
    PORT
      LAYER M4 ;
        RECT  51.756 51.264 51.84 51.288 ;
    END
  END b[183]
  PIN b[184]
    DIRECTION OUTPUT ;
    USE SIGNAL ;
    PORT
      LAYER M4 ;
        RECT  51.756 51.408 51.84 51.432 ;
    END
  END b[184]
  PIN b[185]
    DIRECTION OUTPUT ;
    USE SIGNAL ;
    PORT
      LAYER M4 ;
        RECT  51.756 51.552 51.84 51.576 ;
    END
  END b[185]
  PIN b[186]
    DIRECTION OUTPUT ;
    USE SIGNAL ;
    PORT
      LAYER M4 ;
        RECT  51.756 51.696 51.84 51.72 ;
    END
  END b[186]
  PIN b[187]
    DIRECTION OUTPUT ;
    USE SIGNAL ;
    PORT
      LAYER M4 ;
        RECT  51.756 51.84 51.84 51.864 ;
    END
  END b[187]
  PIN b[188]
    DIRECTION OUTPUT ;
    USE SIGNAL ;
    PORT
      LAYER M4 ;
        RECT  51.756 51.984 51.84 52.008 ;
    END
  END b[188]
  PIN b[189]
    DIRECTION OUTPUT ;
    USE SIGNAL ;
    PORT
      LAYER M4 ;
        RECT  51.756 52.128 51.84 52.152 ;
    END
  END b[189]
  PIN b[18]
    DIRECTION OUTPUT ;
    USE SIGNAL ;
    PORT
      LAYER M4 ;
        RECT  51.756 36.72 51.84 36.744 ;
    END
  END b[18]
  PIN b[190]
    DIRECTION OUTPUT ;
    USE SIGNAL ;
    PORT
      LAYER M4 ;
        RECT  51.756 52.272 51.84 52.296 ;
    END
  END b[190]
  PIN b[191]
    DIRECTION OUTPUT ;
    USE SIGNAL ;
    PORT
      LAYER M4 ;
        RECT  51.756 52.416 51.84 52.44 ;
    END
  END b[191]
  PIN b[192]
    DIRECTION OUTPUT ;
    USE SIGNAL ;
    PORT
      LAYER M4 ;
        RECT  51.756 76.752 51.84 76.776 ;
    END
  END b[192]
  PIN b[193]
    DIRECTION OUTPUT ;
    USE SIGNAL ;
    PORT
      LAYER M4 ;
        RECT  51.756 76.896 51.84 76.92 ;
    END
  END b[193]
  PIN b[194]
    DIRECTION OUTPUT ;
    USE SIGNAL ;
    PORT
      LAYER M4 ;
        RECT  51.756 77.04 51.84 77.064 ;
    END
  END b[194]
  PIN b[195]
    DIRECTION OUTPUT ;
    USE SIGNAL ;
    PORT
      LAYER M4 ;
        RECT  51.756 77.184 51.84 77.208 ;
    END
  END b[195]
  PIN b[196]
    DIRECTION OUTPUT ;
    USE SIGNAL ;
    PORT
      LAYER M4 ;
        RECT  51.756 77.328 51.84 77.352 ;
    END
  END b[196]
  PIN b[197]
    DIRECTION OUTPUT ;
    USE SIGNAL ;
    PORT
      LAYER M4 ;
        RECT  51.756 77.472 51.84 77.496 ;
    END
  END b[197]
  PIN b[198]
    DIRECTION OUTPUT ;
    USE SIGNAL ;
    PORT
      LAYER M4 ;
        RECT  51.756 77.616 51.84 77.64 ;
    END
  END b[198]
  PIN b[199]
    DIRECTION OUTPUT ;
    USE SIGNAL ;
    PORT
      LAYER M4 ;
        RECT  51.756 77.76 51.84 77.784 ;
    END
  END b[199]
  PIN b[19]
    DIRECTION OUTPUT ;
    USE SIGNAL ;
    PORT
      LAYER M4 ;
        RECT  51.756 36.864 51.84 36.888 ;
    END
  END b[19]
  PIN b[1]
    DIRECTION OUTPUT ;
    USE SIGNAL ;
    PORT
      LAYER M4 ;
        RECT  51.756 34.272 51.84 34.296 ;
    END
  END b[1]
  PIN b[200]
    DIRECTION OUTPUT ;
    USE SIGNAL ;
    PORT
      LAYER M4 ;
        RECT  51.756 77.904 51.84 77.928 ;
    END
  END b[200]
  PIN b[201]
    DIRECTION OUTPUT ;
    USE SIGNAL ;
    PORT
      LAYER M4 ;
        RECT  51.756 78.048 51.84 78.072 ;
    END
  END b[201]
  PIN b[202]
    DIRECTION OUTPUT ;
    USE SIGNAL ;
    PORT
      LAYER M4 ;
        RECT  51.756 78.192 51.84 78.216 ;
    END
  END b[202]
  PIN b[203]
    DIRECTION OUTPUT ;
    USE SIGNAL ;
    PORT
      LAYER M4 ;
        RECT  51.756 78.336 51.84 78.36 ;
    END
  END b[203]
  PIN b[204]
    DIRECTION OUTPUT ;
    USE SIGNAL ;
    PORT
      LAYER M4 ;
        RECT  51.756 78.48 51.84 78.504 ;
    END
  END b[204]
  PIN b[205]
    DIRECTION OUTPUT ;
    USE SIGNAL ;
    PORT
      LAYER M4 ;
        RECT  51.756 78.624 51.84 78.648 ;
    END
  END b[205]
  PIN b[206]
    DIRECTION OUTPUT ;
    USE SIGNAL ;
    PORT
      LAYER M4 ;
        RECT  51.756 78.768 51.84 78.792 ;
    END
  END b[206]
  PIN b[207]
    DIRECTION OUTPUT ;
    USE SIGNAL ;
    PORT
      LAYER M4 ;
        RECT  51.756 78.912 51.84 78.936 ;
    END
  END b[207]
  PIN b[208]
    DIRECTION OUTPUT ;
    USE SIGNAL ;
    PORT
      LAYER M4 ;
        RECT  51.756 79.056 51.84 79.08 ;
    END
  END b[208]
  PIN b[209]
    DIRECTION OUTPUT ;
    USE SIGNAL ;
    PORT
      LAYER M4 ;
        RECT  51.756 79.2 51.84 79.224 ;
    END
  END b[209]
  PIN b[20]
    DIRECTION OUTPUT ;
    USE SIGNAL ;
    PORT
      LAYER M4 ;
        RECT  51.756 37.008 51.84 37.032 ;
    END
  END b[20]
  PIN b[210]
    DIRECTION OUTPUT ;
    USE SIGNAL ;
    PORT
      LAYER M4 ;
        RECT  51.756 79.344 51.84 79.368 ;
    END
  END b[210]
  PIN b[211]
    DIRECTION OUTPUT ;
    USE SIGNAL ;
    PORT
      LAYER M4 ;
        RECT  51.756 79.488 51.84 79.512 ;
    END
  END b[211]
  PIN b[212]
    DIRECTION OUTPUT ;
    USE SIGNAL ;
    PORT
      LAYER M4 ;
        RECT  51.756 79.632 51.84 79.656 ;
    END
  END b[212]
  PIN b[213]
    DIRECTION OUTPUT ;
    USE SIGNAL ;
    PORT
      LAYER M4 ;
        RECT  51.756 79.776 51.84 79.8 ;
    END
  END b[213]
  PIN b[214]
    DIRECTION OUTPUT ;
    USE SIGNAL ;
    PORT
      LAYER M4 ;
        RECT  51.756 79.92 51.84 79.944 ;
    END
  END b[214]
  PIN b[215]
    DIRECTION OUTPUT ;
    USE SIGNAL ;
    PORT
      LAYER M4 ;
        RECT  51.756 80.064 51.84 80.088 ;
    END
  END b[215]
  PIN b[216]
    DIRECTION OUTPUT ;
    USE SIGNAL ;
    PORT
      LAYER M4 ;
        RECT  51.756 80.208 51.84 80.232 ;
    END
  END b[216]
  PIN b[217]
    DIRECTION OUTPUT ;
    USE SIGNAL ;
    PORT
      LAYER M4 ;
        RECT  51.756 80.352 51.84 80.376 ;
    END
  END b[217]
  PIN b[218]
    DIRECTION OUTPUT ;
    USE SIGNAL ;
    PORT
      LAYER M4 ;
        RECT  51.756 80.496 51.84 80.52 ;
    END
  END b[218]
  PIN b[219]
    DIRECTION OUTPUT ;
    USE SIGNAL ;
    PORT
      LAYER M4 ;
        RECT  51.756 80.64 51.84 80.664 ;
    END
  END b[219]
  PIN b[21]
    DIRECTION OUTPUT ;
    USE SIGNAL ;
    PORT
      LAYER M4 ;
        RECT  51.756 37.152 51.84 37.176 ;
    END
  END b[21]
  PIN b[220]
    DIRECTION OUTPUT ;
    USE SIGNAL ;
    PORT
      LAYER M4 ;
        RECT  51.756 80.784 51.84 80.808 ;
    END
  END b[220]
  PIN b[221]
    DIRECTION OUTPUT ;
    USE SIGNAL ;
    PORT
      LAYER M4 ;
        RECT  51.756 80.928 51.84 80.952 ;
    END
  END b[221]
  PIN b[222]
    DIRECTION OUTPUT ;
    USE SIGNAL ;
    PORT
      LAYER M4 ;
        RECT  51.756 81.072 51.84 81.096 ;
    END
  END b[222]
  PIN b[223]
    DIRECTION OUTPUT ;
    USE SIGNAL ;
    PORT
      LAYER M4 ;
        RECT  51.756 81.216 51.84 81.24 ;
    END
  END b[223]
  PIN b[224]
    DIRECTION OUTPUT ;
    USE SIGNAL ;
    PORT
      LAYER M4 ;
        RECT  51.756 38.736 51.84 38.76 ;
    END
  END b[224]
  PIN b[225]
    DIRECTION OUTPUT ;
    USE SIGNAL ;
    PORT
      LAYER M4 ;
        RECT  51.756 38.88 51.84 38.904 ;
    END
  END b[225]
  PIN b[226]
    DIRECTION OUTPUT ;
    USE SIGNAL ;
    PORT
      LAYER M4 ;
        RECT  51.756 39.024 51.84 39.048 ;
    END
  END b[226]
  PIN b[227]
    DIRECTION OUTPUT ;
    USE SIGNAL ;
    PORT
      LAYER M4 ;
        RECT  51.756 39.168 51.84 39.192 ;
    END
  END b[227]
  PIN b[228]
    DIRECTION OUTPUT ;
    USE SIGNAL ;
    PORT
      LAYER M4 ;
        RECT  51.756 39.312 51.84 39.336 ;
    END
  END b[228]
  PIN b[229]
    DIRECTION OUTPUT ;
    USE SIGNAL ;
    PORT
      LAYER M4 ;
        RECT  51.756 39.456 51.84 39.48 ;
    END
  END b[229]
  PIN b[22]
    DIRECTION OUTPUT ;
    USE SIGNAL ;
    PORT
      LAYER M4 ;
        RECT  51.756 37.296 51.84 37.32 ;
    END
  END b[22]
  PIN b[230]
    DIRECTION OUTPUT ;
    USE SIGNAL ;
    PORT
      LAYER M4 ;
        RECT  51.756 39.6 51.84 39.624 ;
    END
  END b[230]
  PIN b[231]
    DIRECTION OUTPUT ;
    USE SIGNAL ;
    PORT
      LAYER M4 ;
        RECT  51.756 39.744 51.84 39.768 ;
    END
  END b[231]
  PIN b[232]
    DIRECTION OUTPUT ;
    USE SIGNAL ;
    PORT
      LAYER M4 ;
        RECT  51.756 39.888 51.84 39.912 ;
    END
  END b[232]
  PIN b[233]
    DIRECTION OUTPUT ;
    USE SIGNAL ;
    PORT
      LAYER M4 ;
        RECT  51.756 40.032 51.84 40.056 ;
    END
  END b[233]
  PIN b[234]
    DIRECTION OUTPUT ;
    USE SIGNAL ;
    PORT
      LAYER M4 ;
        RECT  51.756 40.176 51.84 40.2 ;
    END
  END b[234]
  PIN b[235]
    DIRECTION OUTPUT ;
    USE SIGNAL ;
    PORT
      LAYER M4 ;
        RECT  51.756 40.32 51.84 40.344 ;
    END
  END b[235]
  PIN b[236]
    DIRECTION OUTPUT ;
    USE SIGNAL ;
    PORT
      LAYER M4 ;
        RECT  51.756 40.464 51.84 40.488 ;
    END
  END b[236]
  PIN b[237]
    DIRECTION OUTPUT ;
    USE SIGNAL ;
    PORT
      LAYER M4 ;
        RECT  51.756 40.608 51.84 40.632 ;
    END
  END b[237]
  PIN b[238]
    DIRECTION OUTPUT ;
    USE SIGNAL ;
    PORT
      LAYER M4 ;
        RECT  51.756 40.752 51.84 40.776 ;
    END
  END b[238]
  PIN b[239]
    DIRECTION OUTPUT ;
    USE SIGNAL ;
    PORT
      LAYER M4 ;
        RECT  51.756 40.896 51.84 40.92 ;
    END
  END b[239]
  PIN b[23]
    DIRECTION OUTPUT ;
    USE SIGNAL ;
    PORT
      LAYER M4 ;
        RECT  51.756 37.44 51.84 37.464 ;
    END
  END b[23]
  PIN b[240]
    DIRECTION OUTPUT ;
    USE SIGNAL ;
    PORT
      LAYER M4 ;
        RECT  51.756 41.04 51.84 41.064 ;
    END
  END b[240]
  PIN b[241]
    DIRECTION OUTPUT ;
    USE SIGNAL ;
    PORT
      LAYER M4 ;
        RECT  51.756 41.184 51.84 41.208 ;
    END
  END b[241]
  PIN b[242]
    DIRECTION OUTPUT ;
    USE SIGNAL ;
    PORT
      LAYER M4 ;
        RECT  51.756 41.328 51.84 41.352 ;
    END
  END b[242]
  PIN b[243]
    DIRECTION OUTPUT ;
    USE SIGNAL ;
    PORT
      LAYER M4 ;
        RECT  51.756 41.472 51.84 41.496 ;
    END
  END b[243]
  PIN b[244]
    DIRECTION OUTPUT ;
    USE SIGNAL ;
    PORT
      LAYER M4 ;
        RECT  51.756 41.616 51.84 41.64 ;
    END
  END b[244]
  PIN b[245]
    DIRECTION OUTPUT ;
    USE SIGNAL ;
    PORT
      LAYER M4 ;
        RECT  51.756 41.76 51.84 41.784 ;
    END
  END b[245]
  PIN b[246]
    DIRECTION OUTPUT ;
    USE SIGNAL ;
    PORT
      LAYER M4 ;
        RECT  51.756 41.904 51.84 41.928 ;
    END
  END b[246]
  PIN b[247]
    DIRECTION OUTPUT ;
    USE SIGNAL ;
    PORT
      LAYER M4 ;
        RECT  51.756 42.048 51.84 42.072 ;
    END
  END b[247]
  PIN b[248]
    DIRECTION OUTPUT ;
    USE SIGNAL ;
    PORT
      LAYER M4 ;
        RECT  51.756 42.192 51.84 42.216 ;
    END
  END b[248]
  PIN b[249]
    DIRECTION OUTPUT ;
    USE SIGNAL ;
    PORT
      LAYER M4 ;
        RECT  51.756 42.336 51.84 42.36 ;
    END
  END b[249]
  PIN b[24]
    DIRECTION OUTPUT ;
    USE SIGNAL ;
    PORT
      LAYER M4 ;
        RECT  51.756 37.584 51.84 37.608 ;
    END
  END b[24]
  PIN b[250]
    DIRECTION OUTPUT ;
    USE SIGNAL ;
    PORT
      LAYER M4 ;
        RECT  51.756 42.48 51.84 42.504 ;
    END
  END b[250]
  PIN b[251]
    DIRECTION OUTPUT ;
    USE SIGNAL ;
    PORT
      LAYER M4 ;
        RECT  51.756 42.624 51.84 42.648 ;
    END
  END b[251]
  PIN b[252]
    DIRECTION OUTPUT ;
    USE SIGNAL ;
    PORT
      LAYER M4 ;
        RECT  51.756 42.768 51.84 42.792 ;
    END
  END b[252]
  PIN b[253]
    DIRECTION OUTPUT ;
    USE SIGNAL ;
    PORT
      LAYER M4 ;
        RECT  51.756 42.912 51.84 42.936 ;
    END
  END b[253]
  PIN b[254]
    DIRECTION OUTPUT ;
    USE SIGNAL ;
    PORT
      LAYER M4 ;
        RECT  51.756 43.056 51.84 43.08 ;
    END
  END b[254]
  PIN b[255]
    DIRECTION OUTPUT ;
    USE SIGNAL ;
    PORT
      LAYER M4 ;
        RECT  51.756 43.2 51.84 43.224 ;
    END
  END b[255]
  PIN b[256]
    DIRECTION OUTPUT ;
    USE SIGNAL ;
    PORT
      LAYER M4 ;
        RECT  51.756 62.928 51.84 62.952 ;
    END
  END b[256]
  PIN b[257]
    DIRECTION OUTPUT ;
    USE SIGNAL ;
    PORT
      LAYER M4 ;
        RECT  51.756 63.072 51.84 63.096 ;
    END
  END b[257]
  PIN b[258]
    DIRECTION OUTPUT ;
    USE SIGNAL ;
    PORT
      LAYER M4 ;
        RECT  51.756 63.216 51.84 63.24 ;
    END
  END b[258]
  PIN b[259]
    DIRECTION OUTPUT ;
    USE SIGNAL ;
    PORT
      LAYER M4 ;
        RECT  51.756 63.36 51.84 63.384 ;
    END
  END b[259]
  PIN b[25]
    DIRECTION OUTPUT ;
    USE SIGNAL ;
    PORT
      LAYER M4 ;
        RECT  51.756 37.728 51.84 37.752 ;
    END
  END b[25]
  PIN b[260]
    DIRECTION OUTPUT ;
    USE SIGNAL ;
    PORT
      LAYER M4 ;
        RECT  51.756 63.504 51.84 63.528 ;
    END
  END b[260]
  PIN b[261]
    DIRECTION OUTPUT ;
    USE SIGNAL ;
    PORT
      LAYER M4 ;
        RECT  51.756 63.648 51.84 63.672 ;
    END
  END b[261]
  PIN b[262]
    DIRECTION OUTPUT ;
    USE SIGNAL ;
    PORT
      LAYER M4 ;
        RECT  51.756 63.792 51.84 63.816 ;
    END
  END b[262]
  PIN b[263]
    DIRECTION OUTPUT ;
    USE SIGNAL ;
    PORT
      LAYER M4 ;
        RECT  51.756 63.936 51.84 63.96 ;
    END
  END b[263]
  PIN b[264]
    DIRECTION OUTPUT ;
    USE SIGNAL ;
    PORT
      LAYER M4 ;
        RECT  51.756 64.08 51.84 64.104 ;
    END
  END b[264]
  PIN b[265]
    DIRECTION OUTPUT ;
    USE SIGNAL ;
    PORT
      LAYER M4 ;
        RECT  51.756 64.224 51.84 64.248 ;
    END
  END b[265]
  PIN b[266]
    DIRECTION OUTPUT ;
    USE SIGNAL ;
    PORT
      LAYER M4 ;
        RECT  51.756 64.368 51.84 64.392 ;
    END
  END b[266]
  PIN b[267]
    DIRECTION OUTPUT ;
    USE SIGNAL ;
    PORT
      LAYER M4 ;
        RECT  51.756 64.512 51.84 64.536 ;
    END
  END b[267]
  PIN b[268]
    DIRECTION OUTPUT ;
    USE SIGNAL ;
    PORT
      LAYER M4 ;
        RECT  51.756 64.656 51.84 64.68 ;
    END
  END b[268]
  PIN b[269]
    DIRECTION OUTPUT ;
    USE SIGNAL ;
    PORT
      LAYER M4 ;
        RECT  51.756 64.8 51.84 64.824 ;
    END
  END b[269]
  PIN b[26]
    DIRECTION OUTPUT ;
    USE SIGNAL ;
    PORT
      LAYER M4 ;
        RECT  51.756 37.872 51.84 37.896 ;
    END
  END b[26]
  PIN b[270]
    DIRECTION OUTPUT ;
    USE SIGNAL ;
    PORT
      LAYER M4 ;
        RECT  51.756 64.944 51.84 64.968 ;
    END
  END b[270]
  PIN b[271]
    DIRECTION OUTPUT ;
    USE SIGNAL ;
    PORT
      LAYER M4 ;
        RECT  51.756 65.088 51.84 65.112 ;
    END
  END b[271]
  PIN b[272]
    DIRECTION OUTPUT ;
    USE SIGNAL ;
    PORT
      LAYER M4 ;
        RECT  51.756 65.232 51.84 65.256 ;
    END
  END b[272]
  PIN b[273]
    DIRECTION OUTPUT ;
    USE SIGNAL ;
    PORT
      LAYER M4 ;
        RECT  51.756 65.376 51.84 65.4 ;
    END
  END b[273]
  PIN b[274]
    DIRECTION OUTPUT ;
    USE SIGNAL ;
    PORT
      LAYER M4 ;
        RECT  51.756 65.52 51.84 65.544 ;
    END
  END b[274]
  PIN b[275]
    DIRECTION OUTPUT ;
    USE SIGNAL ;
    PORT
      LAYER M4 ;
        RECT  51.756 65.664 51.84 65.688 ;
    END
  END b[275]
  PIN b[276]
    DIRECTION OUTPUT ;
    USE SIGNAL ;
    PORT
      LAYER M4 ;
        RECT  51.756 65.808 51.84 65.832 ;
    END
  END b[276]
  PIN b[277]
    DIRECTION OUTPUT ;
    USE SIGNAL ;
    PORT
      LAYER M4 ;
        RECT  51.756 65.952 51.84 65.976 ;
    END
  END b[277]
  PIN b[278]
    DIRECTION OUTPUT ;
    USE SIGNAL ;
    PORT
      LAYER M4 ;
        RECT  51.756 66.096 51.84 66.12 ;
    END
  END b[278]
  PIN b[279]
    DIRECTION OUTPUT ;
    USE SIGNAL ;
    PORT
      LAYER M4 ;
        RECT  51.756 66.24 51.84 66.264 ;
    END
  END b[279]
  PIN b[27]
    DIRECTION OUTPUT ;
    USE SIGNAL ;
    PORT
      LAYER M4 ;
        RECT  51.756 38.016 51.84 38.04 ;
    END
  END b[27]
  PIN b[280]
    DIRECTION OUTPUT ;
    USE SIGNAL ;
    PORT
      LAYER M4 ;
        RECT  51.756 66.384 51.84 66.408 ;
    END
  END b[280]
  PIN b[281]
    DIRECTION OUTPUT ;
    USE SIGNAL ;
    PORT
      LAYER M4 ;
        RECT  51.756 66.528 51.84 66.552 ;
    END
  END b[281]
  PIN b[282]
    DIRECTION OUTPUT ;
    USE SIGNAL ;
    PORT
      LAYER M4 ;
        RECT  51.756 66.672 51.84 66.696 ;
    END
  END b[282]
  PIN b[283]
    DIRECTION OUTPUT ;
    USE SIGNAL ;
    PORT
      LAYER M4 ;
        RECT  51.756 66.816 51.84 66.84 ;
    END
  END b[283]
  PIN b[284]
    DIRECTION OUTPUT ;
    USE SIGNAL ;
    PORT
      LAYER M4 ;
        RECT  51.756 66.96 51.84 66.984 ;
    END
  END b[284]
  PIN b[285]
    DIRECTION OUTPUT ;
    USE SIGNAL ;
    PORT
      LAYER M4 ;
        RECT  51.756 67.104 51.84 67.128 ;
    END
  END b[285]
  PIN b[286]
    DIRECTION OUTPUT ;
    USE SIGNAL ;
    PORT
      LAYER M4 ;
        RECT  51.756 67.248 51.84 67.272 ;
    END
  END b[286]
  PIN b[287]
    DIRECTION OUTPUT ;
    USE SIGNAL ;
    PORT
      LAYER M4 ;
        RECT  51.756 67.392 51.84 67.416 ;
    END
  END b[287]
  PIN b[288]
    DIRECTION OUTPUT ;
    USE SIGNAL ;
    PORT
      LAYER M4 ;
        RECT  51.756 43.344 51.84 43.368 ;
    END
  END b[288]
  PIN b[289]
    DIRECTION OUTPUT ;
    USE SIGNAL ;
    PORT
      LAYER M4 ;
        RECT  51.756 43.488 51.84 43.512 ;
    END
  END b[289]
  PIN b[28]
    DIRECTION OUTPUT ;
    USE SIGNAL ;
    PORT
      LAYER M4 ;
        RECT  51.756 38.16 51.84 38.184 ;
    END
  END b[28]
  PIN b[290]
    DIRECTION OUTPUT ;
    USE SIGNAL ;
    PORT
      LAYER M4 ;
        RECT  51.756 43.632 51.84 43.656 ;
    END
  END b[290]
  PIN b[291]
    DIRECTION OUTPUT ;
    USE SIGNAL ;
    PORT
      LAYER M4 ;
        RECT  51.756 43.776 51.84 43.8 ;
    END
  END b[291]
  PIN b[292]
    DIRECTION OUTPUT ;
    USE SIGNAL ;
    PORT
      LAYER M4 ;
        RECT  51.756 43.92 51.84 43.944 ;
    END
  END b[292]
  PIN b[293]
    DIRECTION OUTPUT ;
    USE SIGNAL ;
    PORT
      LAYER M4 ;
        RECT  51.756 44.064 51.84 44.088 ;
    END
  END b[293]
  PIN b[294]
    DIRECTION OUTPUT ;
    USE SIGNAL ;
    PORT
      LAYER M4 ;
        RECT  51.756 44.208 51.84 44.232 ;
    END
  END b[294]
  PIN b[295]
    DIRECTION OUTPUT ;
    USE SIGNAL ;
    PORT
      LAYER M4 ;
        RECT  51.756 44.352 51.84 44.376 ;
    END
  END b[295]
  PIN b[296]
    DIRECTION OUTPUT ;
    USE SIGNAL ;
    PORT
      LAYER M4 ;
        RECT  51.756 44.496 51.84 44.52 ;
    END
  END b[296]
  PIN b[297]
    DIRECTION OUTPUT ;
    USE SIGNAL ;
    PORT
      LAYER M4 ;
        RECT  51.756 44.64 51.84 44.664 ;
    END
  END b[297]
  PIN b[298]
    DIRECTION OUTPUT ;
    USE SIGNAL ;
    PORT
      LAYER M4 ;
        RECT  51.756 44.784 51.84 44.808 ;
    END
  END b[298]
  PIN b[299]
    DIRECTION OUTPUT ;
    USE SIGNAL ;
    PORT
      LAYER M4 ;
        RECT  51.756 44.928 51.84 44.952 ;
    END
  END b[299]
  PIN b[29]
    DIRECTION OUTPUT ;
    USE SIGNAL ;
    PORT
      LAYER M4 ;
        RECT  51.756 38.304 51.84 38.328 ;
    END
  END b[29]
  PIN b[2]
    DIRECTION OUTPUT ;
    USE SIGNAL ;
    PORT
      LAYER M4 ;
        RECT  51.756 34.416 51.84 34.44 ;
    END
  END b[2]
  PIN b[300]
    DIRECTION OUTPUT ;
    USE SIGNAL ;
    PORT
      LAYER M4 ;
        RECT  51.756 45.072 51.84 45.096 ;
    END
  END b[300]
  PIN b[301]
    DIRECTION OUTPUT ;
    USE SIGNAL ;
    PORT
      LAYER M4 ;
        RECT  51.756 45.216 51.84 45.24 ;
    END
  END b[301]
  PIN b[302]
    DIRECTION OUTPUT ;
    USE SIGNAL ;
    PORT
      LAYER M4 ;
        RECT  51.756 45.36 51.84 45.384 ;
    END
  END b[302]
  PIN b[303]
    DIRECTION OUTPUT ;
    USE SIGNAL ;
    PORT
      LAYER M4 ;
        RECT  51.756 45.504 51.84 45.528 ;
    END
  END b[303]
  PIN b[304]
    DIRECTION OUTPUT ;
    USE SIGNAL ;
    PORT
      LAYER M4 ;
        RECT  51.756 45.648 51.84 45.672 ;
    END
  END b[304]
  PIN b[305]
    DIRECTION OUTPUT ;
    USE SIGNAL ;
    PORT
      LAYER M4 ;
        RECT  51.756 45.792 51.84 45.816 ;
    END
  END b[305]
  PIN b[306]
    DIRECTION OUTPUT ;
    USE SIGNAL ;
    PORT
      LAYER M4 ;
        RECT  51.756 45.936 51.84 45.96 ;
    END
  END b[306]
  PIN b[307]
    DIRECTION OUTPUT ;
    USE SIGNAL ;
    PORT
      LAYER M4 ;
        RECT  51.756 46.08 51.84 46.104 ;
    END
  END b[307]
  PIN b[308]
    DIRECTION OUTPUT ;
    USE SIGNAL ;
    PORT
      LAYER M4 ;
        RECT  51.756 46.224 51.84 46.248 ;
    END
  END b[308]
  PIN b[309]
    DIRECTION OUTPUT ;
    USE SIGNAL ;
    PORT
      LAYER M4 ;
        RECT  51.756 46.368 51.84 46.392 ;
    END
  END b[309]
  PIN b[30]
    DIRECTION OUTPUT ;
    USE SIGNAL ;
    PORT
      LAYER M4 ;
        RECT  51.756 38.448 51.84 38.472 ;
    END
  END b[30]
  PIN b[310]
    DIRECTION OUTPUT ;
    USE SIGNAL ;
    PORT
      LAYER M4 ;
        RECT  51.756 46.512 51.84 46.536 ;
    END
  END b[310]
  PIN b[311]
    DIRECTION OUTPUT ;
    USE SIGNAL ;
    PORT
      LAYER M4 ;
        RECT  51.756 46.656 51.84 46.68 ;
    END
  END b[311]
  PIN b[312]
    DIRECTION OUTPUT ;
    USE SIGNAL ;
    PORT
      LAYER M4 ;
        RECT  51.756 46.8 51.84 46.824 ;
    END
  END b[312]
  PIN b[313]
    DIRECTION OUTPUT ;
    USE SIGNAL ;
    PORT
      LAYER M4 ;
        RECT  51.756 46.944 51.84 46.968 ;
    END
  END b[313]
  PIN b[314]
    DIRECTION OUTPUT ;
    USE SIGNAL ;
    PORT
      LAYER M4 ;
        RECT  51.756 47.088 51.84 47.112 ;
    END
  END b[314]
  PIN b[315]
    DIRECTION OUTPUT ;
    USE SIGNAL ;
    PORT
      LAYER M4 ;
        RECT  51.756 47.232 51.84 47.256 ;
    END
  END b[315]
  PIN b[316]
    DIRECTION OUTPUT ;
    USE SIGNAL ;
    PORT
      LAYER M4 ;
        RECT  51.756 47.376 51.84 47.4 ;
    END
  END b[316]
  PIN b[317]
    DIRECTION OUTPUT ;
    USE SIGNAL ;
    PORT
      LAYER M4 ;
        RECT  51.756 47.52 51.84 47.544 ;
    END
  END b[317]
  PIN b[318]
    DIRECTION OUTPUT ;
    USE SIGNAL ;
    PORT
      LAYER M4 ;
        RECT  51.756 47.664 51.84 47.688 ;
    END
  END b[318]
  PIN b[319]
    DIRECTION OUTPUT ;
    USE SIGNAL ;
    PORT
      LAYER M4 ;
        RECT  51.756 47.808 51.84 47.832 ;
    END
  END b[319]
  PIN b[31]
    DIRECTION OUTPUT ;
    USE SIGNAL ;
    PORT
      LAYER M4 ;
        RECT  51.756 38.592 51.84 38.616 ;
    END
  END b[31]
  PIN b[320]
    DIRECTION OUTPUT ;
    USE SIGNAL ;
    PORT
      LAYER M4 ;
        RECT  51.756 23.76 51.84 23.784 ;
    END
  END b[320]
  PIN b[321]
    DIRECTION OUTPUT ;
    USE SIGNAL ;
    PORT
      LAYER M4 ;
        RECT  51.756 23.904 51.84 23.928 ;
    END
  END b[321]
  PIN b[322]
    DIRECTION OUTPUT ;
    USE SIGNAL ;
    PORT
      LAYER M4 ;
        RECT  51.756 24.048 51.84 24.072 ;
    END
  END b[322]
  PIN b[323]
    DIRECTION OUTPUT ;
    USE SIGNAL ;
    PORT
      LAYER M4 ;
        RECT  51.756 24.192 51.84 24.216 ;
    END
  END b[323]
  PIN b[324]
    DIRECTION OUTPUT ;
    USE SIGNAL ;
    PORT
      LAYER M4 ;
        RECT  51.756 24.336 51.84 24.36 ;
    END
  END b[324]
  PIN b[325]
    DIRECTION OUTPUT ;
    USE SIGNAL ;
    PORT
      LAYER M4 ;
        RECT  51.756 24.48 51.84 24.504 ;
    END
  END b[325]
  PIN b[326]
    DIRECTION OUTPUT ;
    USE SIGNAL ;
    PORT
      LAYER M4 ;
        RECT  51.756 24.624 51.84 24.648 ;
    END
  END b[326]
  PIN b[327]
    DIRECTION OUTPUT ;
    USE SIGNAL ;
    PORT
      LAYER M4 ;
        RECT  51.756 24.768 51.84 24.792 ;
    END
  END b[327]
  PIN b[328]
    DIRECTION OUTPUT ;
    USE SIGNAL ;
    PORT
      LAYER M4 ;
        RECT  51.756 24.912 51.84 24.936 ;
    END
  END b[328]
  PIN b[329]
    DIRECTION OUTPUT ;
    USE SIGNAL ;
    PORT
      LAYER M4 ;
        RECT  51.756 25.056 51.84 25.08 ;
    END
  END b[329]
  PIN b[32]
    DIRECTION OUTPUT ;
    USE SIGNAL ;
    PORT
      LAYER M4 ;
        RECT  51.756 29.52 51.84 29.544 ;
    END
  END b[32]
  PIN b[330]
    DIRECTION OUTPUT ;
    USE SIGNAL ;
    PORT
      LAYER M4 ;
        RECT  51.756 25.2 51.84 25.224 ;
    END
  END b[330]
  PIN b[331]
    DIRECTION OUTPUT ;
    USE SIGNAL ;
    PORT
      LAYER M4 ;
        RECT  51.756 25.344 51.84 25.368 ;
    END
  END b[331]
  PIN b[332]
    DIRECTION OUTPUT ;
    USE SIGNAL ;
    PORT
      LAYER M4 ;
        RECT  51.756 25.488 51.84 25.512 ;
    END
  END b[332]
  PIN b[333]
    DIRECTION OUTPUT ;
    USE SIGNAL ;
    PORT
      LAYER M4 ;
        RECT  51.756 25.632 51.84 25.656 ;
    END
  END b[333]
  PIN b[334]
    DIRECTION OUTPUT ;
    USE SIGNAL ;
    PORT
      LAYER M4 ;
        RECT  51.756 25.776 51.84 25.8 ;
    END
  END b[334]
  PIN b[335]
    DIRECTION OUTPUT ;
    USE SIGNAL ;
    PORT
      LAYER M4 ;
        RECT  51.756 25.92 51.84 25.944 ;
    END
  END b[335]
  PIN b[336]
    DIRECTION OUTPUT ;
    USE SIGNAL ;
    PORT
      LAYER M4 ;
        RECT  51.756 26.064 51.84 26.088 ;
    END
  END b[336]
  PIN b[337]
    DIRECTION OUTPUT ;
    USE SIGNAL ;
    PORT
      LAYER M4 ;
        RECT  51.756 26.208 51.84 26.232 ;
    END
  END b[337]
  PIN b[338]
    DIRECTION OUTPUT ;
    USE SIGNAL ;
    PORT
      LAYER M4 ;
        RECT  51.756 26.352 51.84 26.376 ;
    END
  END b[338]
  PIN b[339]
    DIRECTION OUTPUT ;
    USE SIGNAL ;
    PORT
      LAYER M4 ;
        RECT  51.756 26.496 51.84 26.52 ;
    END
  END b[339]
  PIN b[33]
    DIRECTION OUTPUT ;
    USE SIGNAL ;
    PORT
      LAYER M4 ;
        RECT  51.756 29.664 51.84 29.688 ;
    END
  END b[33]
  PIN b[340]
    DIRECTION OUTPUT ;
    USE SIGNAL ;
    PORT
      LAYER M4 ;
        RECT  51.756 26.64 51.84 26.664 ;
    END
  END b[340]
  PIN b[341]
    DIRECTION OUTPUT ;
    USE SIGNAL ;
    PORT
      LAYER M4 ;
        RECT  51.756 26.784 51.84 26.808 ;
    END
  END b[341]
  PIN b[342]
    DIRECTION OUTPUT ;
    USE SIGNAL ;
    PORT
      LAYER M4 ;
        RECT  51.756 26.928 51.84 26.952 ;
    END
  END b[342]
  PIN b[343]
    DIRECTION OUTPUT ;
    USE SIGNAL ;
    PORT
      LAYER M4 ;
        RECT  51.756 27.072 51.84 27.096 ;
    END
  END b[343]
  PIN b[344]
    DIRECTION OUTPUT ;
    USE SIGNAL ;
    PORT
      LAYER M4 ;
        RECT  51.756 27.216 51.84 27.24 ;
    END
  END b[344]
  PIN b[345]
    DIRECTION OUTPUT ;
    USE SIGNAL ;
    PORT
      LAYER M4 ;
        RECT  51.756 27.36 51.84 27.384 ;
    END
  END b[345]
  PIN b[346]
    DIRECTION OUTPUT ;
    USE SIGNAL ;
    PORT
      LAYER M4 ;
        RECT  51.756 27.504 51.84 27.528 ;
    END
  END b[346]
  PIN b[347]
    DIRECTION OUTPUT ;
    USE SIGNAL ;
    PORT
      LAYER M4 ;
        RECT  51.756 27.648 51.84 27.672 ;
    END
  END b[347]
  PIN b[348]
    DIRECTION OUTPUT ;
    USE SIGNAL ;
    PORT
      LAYER M4 ;
        RECT  51.756 27.792 51.84 27.816 ;
    END
  END b[348]
  PIN b[349]
    DIRECTION OUTPUT ;
    USE SIGNAL ;
    PORT
      LAYER M4 ;
        RECT  51.756 27.936 51.84 27.96 ;
    END
  END b[349]
  PIN b[34]
    DIRECTION OUTPUT ;
    USE SIGNAL ;
    PORT
      LAYER M4 ;
        RECT  51.756 29.808 51.84 29.832 ;
    END
  END b[34]
  PIN b[350]
    DIRECTION OUTPUT ;
    USE SIGNAL ;
    PORT
      LAYER M4 ;
        RECT  51.756 28.08 51.84 28.104 ;
    END
  END b[350]
  PIN b[351]
    DIRECTION OUTPUT ;
    USE SIGNAL ;
    PORT
      LAYER M4 ;
        RECT  51.756 28.224 51.84 28.248 ;
    END
  END b[351]
  PIN b[352]
    DIRECTION OUTPUT ;
    USE SIGNAL ;
    PORT
      LAYER M4 ;
        RECT  51.756 5.328 51.84 5.352 ;
    END
  END b[352]
  PIN b[353]
    DIRECTION OUTPUT ;
    USE SIGNAL ;
    PORT
      LAYER M4 ;
        RECT  51.756 5.472 51.84 5.496 ;
    END
  END b[353]
  PIN b[354]
    DIRECTION OUTPUT ;
    USE SIGNAL ;
    PORT
      LAYER M4 ;
        RECT  51.756 5.616 51.84 5.64 ;
    END
  END b[354]
  PIN b[355]
    DIRECTION OUTPUT ;
    USE SIGNAL ;
    PORT
      LAYER M4 ;
        RECT  51.756 5.76 51.84 5.784 ;
    END
  END b[355]
  PIN b[356]
    DIRECTION OUTPUT ;
    USE SIGNAL ;
    PORT
      LAYER M4 ;
        RECT  51.756 5.904 51.84 5.928 ;
    END
  END b[356]
  PIN b[357]
    DIRECTION OUTPUT ;
    USE SIGNAL ;
    PORT
      LAYER M4 ;
        RECT  51.756 6.048 51.84 6.072 ;
    END
  END b[357]
  PIN b[358]
    DIRECTION OUTPUT ;
    USE SIGNAL ;
    PORT
      LAYER M4 ;
        RECT  51.756 6.192 51.84 6.216 ;
    END
  END b[358]
  PIN b[359]
    DIRECTION OUTPUT ;
    USE SIGNAL ;
    PORT
      LAYER M4 ;
        RECT  51.756 6.336 51.84 6.36 ;
    END
  END b[359]
  PIN b[35]
    DIRECTION OUTPUT ;
    USE SIGNAL ;
    PORT
      LAYER M4 ;
        RECT  51.756 29.952 51.84 29.976 ;
    END
  END b[35]
  PIN b[360]
    DIRECTION OUTPUT ;
    USE SIGNAL ;
    PORT
      LAYER M4 ;
        RECT  51.756 6.48 51.84 6.504 ;
    END
  END b[360]
  PIN b[361]
    DIRECTION OUTPUT ;
    USE SIGNAL ;
    PORT
      LAYER M4 ;
        RECT  51.756 6.624 51.84 6.648 ;
    END
  END b[361]
  PIN b[362]
    DIRECTION OUTPUT ;
    USE SIGNAL ;
    PORT
      LAYER M4 ;
        RECT  51.756 6.768 51.84 6.792 ;
    END
  END b[362]
  PIN b[363]
    DIRECTION OUTPUT ;
    USE SIGNAL ;
    PORT
      LAYER M4 ;
        RECT  51.756 6.912 51.84 6.936 ;
    END
  END b[363]
  PIN b[364]
    DIRECTION OUTPUT ;
    USE SIGNAL ;
    PORT
      LAYER M4 ;
        RECT  51.756 7.056 51.84 7.08 ;
    END
  END b[364]
  PIN b[365]
    DIRECTION OUTPUT ;
    USE SIGNAL ;
    PORT
      LAYER M4 ;
        RECT  51.756 7.2 51.84 7.224 ;
    END
  END b[365]
  PIN b[366]
    DIRECTION OUTPUT ;
    USE SIGNAL ;
    PORT
      LAYER M4 ;
        RECT  51.756 7.344 51.84 7.368 ;
    END
  END b[366]
  PIN b[367]
    DIRECTION OUTPUT ;
    USE SIGNAL ;
    PORT
      LAYER M4 ;
        RECT  51.756 7.488 51.84 7.512 ;
    END
  END b[367]
  PIN b[368]
    DIRECTION OUTPUT ;
    USE SIGNAL ;
    PORT
      LAYER M4 ;
        RECT  51.756 7.632 51.84 7.656 ;
    END
  END b[368]
  PIN b[369]
    DIRECTION OUTPUT ;
    USE SIGNAL ;
    PORT
      LAYER M4 ;
        RECT  51.756 7.776 51.84 7.8 ;
    END
  END b[369]
  PIN b[36]
    DIRECTION OUTPUT ;
    USE SIGNAL ;
    PORT
      LAYER M4 ;
        RECT  51.756 30.096 51.84 30.12 ;
    END
  END b[36]
  PIN b[370]
    DIRECTION OUTPUT ;
    USE SIGNAL ;
    PORT
      LAYER M4 ;
        RECT  51.756 7.92 51.84 7.944 ;
    END
  END b[370]
  PIN b[371]
    DIRECTION OUTPUT ;
    USE SIGNAL ;
    PORT
      LAYER M4 ;
        RECT  51.756 8.064 51.84 8.088 ;
    END
  END b[371]
  PIN b[372]
    DIRECTION OUTPUT ;
    USE SIGNAL ;
    PORT
      LAYER M4 ;
        RECT  51.756 8.208 51.84 8.232 ;
    END
  END b[372]
  PIN b[373]
    DIRECTION OUTPUT ;
    USE SIGNAL ;
    PORT
      LAYER M4 ;
        RECT  51.756 8.352 51.84 8.376 ;
    END
  END b[373]
  PIN b[374]
    DIRECTION OUTPUT ;
    USE SIGNAL ;
    PORT
      LAYER M4 ;
        RECT  51.756 8.496 51.84 8.52 ;
    END
  END b[374]
  PIN b[375]
    DIRECTION OUTPUT ;
    USE SIGNAL ;
    PORT
      LAYER M4 ;
        RECT  51.756 8.64 51.84 8.664 ;
    END
  END b[375]
  PIN b[376]
    DIRECTION OUTPUT ;
    USE SIGNAL ;
    PORT
      LAYER M4 ;
        RECT  51.756 8.784 51.84 8.808 ;
    END
  END b[376]
  PIN b[377]
    DIRECTION OUTPUT ;
    USE SIGNAL ;
    PORT
      LAYER M4 ;
        RECT  51.756 8.928 51.84 8.952 ;
    END
  END b[377]
  PIN b[378]
    DIRECTION OUTPUT ;
    USE SIGNAL ;
    PORT
      LAYER M4 ;
        RECT  51.756 9.072 51.84 9.096 ;
    END
  END b[378]
  PIN b[379]
    DIRECTION OUTPUT ;
    USE SIGNAL ;
    PORT
      LAYER M4 ;
        RECT  51.756 9.216 51.84 9.24 ;
    END
  END b[379]
  PIN b[37]
    DIRECTION OUTPUT ;
    USE SIGNAL ;
    PORT
      LAYER M4 ;
        RECT  51.756 30.24 51.84 30.264 ;
    END
  END b[37]
  PIN b[380]
    DIRECTION OUTPUT ;
    USE SIGNAL ;
    PORT
      LAYER M4 ;
        RECT  51.756 9.36 51.84 9.384 ;
    END
  END b[380]
  PIN b[381]
    DIRECTION OUTPUT ;
    USE SIGNAL ;
    PORT
      LAYER M4 ;
        RECT  51.756 9.504 51.84 9.528 ;
    END
  END b[381]
  PIN b[382]
    DIRECTION OUTPUT ;
    USE SIGNAL ;
    PORT
      LAYER M4 ;
        RECT  51.756 9.648 51.84 9.672 ;
    END
  END b[382]
  PIN b[383]
    DIRECTION OUTPUT ;
    USE SIGNAL ;
    PORT
      LAYER M4 ;
        RECT  51.756 9.792 51.84 9.816 ;
    END
  END b[383]
  PIN b[384]
    DIRECTION OUTPUT ;
    USE SIGNAL ;
    PORT
      LAYER M4 ;
        RECT  51.756 19.152 51.84 19.176 ;
    END
  END b[384]
  PIN b[385]
    DIRECTION OUTPUT ;
    USE SIGNAL ;
    PORT
      LAYER M4 ;
        RECT  51.756 19.296 51.84 19.32 ;
    END
  END b[385]
  PIN b[386]
    DIRECTION OUTPUT ;
    USE SIGNAL ;
    PORT
      LAYER M4 ;
        RECT  51.756 19.44 51.84 19.464 ;
    END
  END b[386]
  PIN b[387]
    DIRECTION OUTPUT ;
    USE SIGNAL ;
    PORT
      LAYER M4 ;
        RECT  51.756 19.584 51.84 19.608 ;
    END
  END b[387]
  PIN b[388]
    DIRECTION OUTPUT ;
    USE SIGNAL ;
    PORT
      LAYER M4 ;
        RECT  51.756 19.728 51.84 19.752 ;
    END
  END b[388]
  PIN b[389]
    DIRECTION OUTPUT ;
    USE SIGNAL ;
    PORT
      LAYER M4 ;
        RECT  51.756 19.872 51.84 19.896 ;
    END
  END b[389]
  PIN b[38]
    DIRECTION OUTPUT ;
    USE SIGNAL ;
    PORT
      LAYER M4 ;
        RECT  51.756 30.384 51.84 30.408 ;
    END
  END b[38]
  PIN b[390]
    DIRECTION OUTPUT ;
    USE SIGNAL ;
    PORT
      LAYER M4 ;
        RECT  51.756 20.016 51.84 20.04 ;
    END
  END b[390]
  PIN b[391]
    DIRECTION OUTPUT ;
    USE SIGNAL ;
    PORT
      LAYER M4 ;
        RECT  51.756 20.16 51.84 20.184 ;
    END
  END b[391]
  PIN b[392]
    DIRECTION OUTPUT ;
    USE SIGNAL ;
    PORT
      LAYER M4 ;
        RECT  51.756 20.304 51.84 20.328 ;
    END
  END b[392]
  PIN b[393]
    DIRECTION OUTPUT ;
    USE SIGNAL ;
    PORT
      LAYER M4 ;
        RECT  51.756 20.448 51.84 20.472 ;
    END
  END b[393]
  PIN b[394]
    DIRECTION OUTPUT ;
    USE SIGNAL ;
    PORT
      LAYER M4 ;
        RECT  51.756 20.592 51.84 20.616 ;
    END
  END b[394]
  PIN b[395]
    DIRECTION OUTPUT ;
    USE SIGNAL ;
    PORT
      LAYER M4 ;
        RECT  51.756 20.736 51.84 20.76 ;
    END
  END b[395]
  PIN b[396]
    DIRECTION OUTPUT ;
    USE SIGNAL ;
    PORT
      LAYER M4 ;
        RECT  51.756 20.88 51.84 20.904 ;
    END
  END b[396]
  PIN b[397]
    DIRECTION OUTPUT ;
    USE SIGNAL ;
    PORT
      LAYER M4 ;
        RECT  51.756 21.024 51.84 21.048 ;
    END
  END b[397]
  PIN b[398]
    DIRECTION OUTPUT ;
    USE SIGNAL ;
    PORT
      LAYER M4 ;
        RECT  51.756 21.168 51.84 21.192 ;
    END
  END b[398]
  PIN b[399]
    DIRECTION OUTPUT ;
    USE SIGNAL ;
    PORT
      LAYER M4 ;
        RECT  51.756 21.312 51.84 21.336 ;
    END
  END b[399]
  PIN b[39]
    DIRECTION OUTPUT ;
    USE SIGNAL ;
    PORT
      LAYER M4 ;
        RECT  51.756 30.528 51.84 30.552 ;
    END
  END b[39]
  PIN b[3]
    DIRECTION OUTPUT ;
    USE SIGNAL ;
    PORT
      LAYER M4 ;
        RECT  51.756 34.56 51.84 34.584 ;
    END
  END b[3]
  PIN b[400]
    DIRECTION OUTPUT ;
    USE SIGNAL ;
    PORT
      LAYER M4 ;
        RECT  51.756 21.456 51.84 21.48 ;
    END
  END b[400]
  PIN b[401]
    DIRECTION OUTPUT ;
    USE SIGNAL ;
    PORT
      LAYER M4 ;
        RECT  51.756 21.6 51.84 21.624 ;
    END
  END b[401]
  PIN b[402]
    DIRECTION OUTPUT ;
    USE SIGNAL ;
    PORT
      LAYER M4 ;
        RECT  51.756 21.744 51.84 21.768 ;
    END
  END b[402]
  PIN b[403]
    DIRECTION OUTPUT ;
    USE SIGNAL ;
    PORT
      LAYER M4 ;
        RECT  51.756 21.888 51.84 21.912 ;
    END
  END b[403]
  PIN b[404]
    DIRECTION OUTPUT ;
    USE SIGNAL ;
    PORT
      LAYER M4 ;
        RECT  51.756 22.032 51.84 22.056 ;
    END
  END b[404]
  PIN b[405]
    DIRECTION OUTPUT ;
    USE SIGNAL ;
    PORT
      LAYER M4 ;
        RECT  51.756 22.176 51.84 22.2 ;
    END
  END b[405]
  PIN b[406]
    DIRECTION OUTPUT ;
    USE SIGNAL ;
    PORT
      LAYER M4 ;
        RECT  51.756 22.32 51.84 22.344 ;
    END
  END b[406]
  PIN b[407]
    DIRECTION OUTPUT ;
    USE SIGNAL ;
    PORT
      LAYER M4 ;
        RECT  51.756 22.464 51.84 22.488 ;
    END
  END b[407]
  PIN b[408]
    DIRECTION OUTPUT ;
    USE SIGNAL ;
    PORT
      LAYER M4 ;
        RECT  51.756 22.608 51.84 22.632 ;
    END
  END b[408]
  PIN b[409]
    DIRECTION OUTPUT ;
    USE SIGNAL ;
    PORT
      LAYER M4 ;
        RECT  51.756 22.752 51.84 22.776 ;
    END
  END b[409]
  PIN b[40]
    DIRECTION OUTPUT ;
    USE SIGNAL ;
    PORT
      LAYER M4 ;
        RECT  51.756 30.672 51.84 30.696 ;
    END
  END b[40]
  PIN b[410]
    DIRECTION OUTPUT ;
    USE SIGNAL ;
    PORT
      LAYER M4 ;
        RECT  51.756 22.896 51.84 22.92 ;
    END
  END b[410]
  PIN b[411]
    DIRECTION OUTPUT ;
    USE SIGNAL ;
    PORT
      LAYER M4 ;
        RECT  51.756 23.04 51.84 23.064 ;
    END
  END b[411]
  PIN b[412]
    DIRECTION OUTPUT ;
    USE SIGNAL ;
    PORT
      LAYER M4 ;
        RECT  51.756 23.184 51.84 23.208 ;
    END
  END b[412]
  PIN b[413]
    DIRECTION OUTPUT ;
    USE SIGNAL ;
    PORT
      LAYER M4 ;
        RECT  51.756 23.328 51.84 23.352 ;
    END
  END b[413]
  PIN b[414]
    DIRECTION OUTPUT ;
    USE SIGNAL ;
    PORT
      LAYER M4 ;
        RECT  51.756 23.472 51.84 23.496 ;
    END
  END b[414]
  PIN b[415]
    DIRECTION OUTPUT ;
    USE SIGNAL ;
    PORT
      LAYER M4 ;
        RECT  51.756 23.616 51.84 23.64 ;
    END
  END b[415]
  PIN b[416]
    DIRECTION OUTPUT ;
    USE SIGNAL ;
    PORT
      LAYER M4 ;
        RECT  51.756 14.544 51.84 14.568 ;
    END
  END b[416]
  PIN b[417]
    DIRECTION OUTPUT ;
    USE SIGNAL ;
    PORT
      LAYER M4 ;
        RECT  51.756 14.688 51.84 14.712 ;
    END
  END b[417]
  PIN b[418]
    DIRECTION OUTPUT ;
    USE SIGNAL ;
    PORT
      LAYER M4 ;
        RECT  51.756 14.832 51.84 14.856 ;
    END
  END b[418]
  PIN b[419]
    DIRECTION OUTPUT ;
    USE SIGNAL ;
    PORT
      LAYER M4 ;
        RECT  51.756 14.976 51.84 15 ;
    END
  END b[419]
  PIN b[41]
    DIRECTION OUTPUT ;
    USE SIGNAL ;
    PORT
      LAYER M4 ;
        RECT  51.756 30.816 51.84 30.84 ;
    END
  END b[41]
  PIN b[420]
    DIRECTION OUTPUT ;
    USE SIGNAL ;
    PORT
      LAYER M4 ;
        RECT  51.756 15.12 51.84 15.144 ;
    END
  END b[420]
  PIN b[421]
    DIRECTION OUTPUT ;
    USE SIGNAL ;
    PORT
      LAYER M4 ;
        RECT  51.756 15.264 51.84 15.288 ;
    END
  END b[421]
  PIN b[422]
    DIRECTION OUTPUT ;
    USE SIGNAL ;
    PORT
      LAYER M4 ;
        RECT  51.756 15.408 51.84 15.432 ;
    END
  END b[422]
  PIN b[423]
    DIRECTION OUTPUT ;
    USE SIGNAL ;
    PORT
      LAYER M4 ;
        RECT  51.756 15.552 51.84 15.576 ;
    END
  END b[423]
  PIN b[424]
    DIRECTION OUTPUT ;
    USE SIGNAL ;
    PORT
      LAYER M4 ;
        RECT  51.756 15.696 51.84 15.72 ;
    END
  END b[424]
  PIN b[425]
    DIRECTION OUTPUT ;
    USE SIGNAL ;
    PORT
      LAYER M4 ;
        RECT  51.756 15.84 51.84 15.864 ;
    END
  END b[425]
  PIN b[426]
    DIRECTION OUTPUT ;
    USE SIGNAL ;
    PORT
      LAYER M4 ;
        RECT  51.756 15.984 51.84 16.008 ;
    END
  END b[426]
  PIN b[427]
    DIRECTION OUTPUT ;
    USE SIGNAL ;
    PORT
      LAYER M4 ;
        RECT  51.756 16.128 51.84 16.152 ;
    END
  END b[427]
  PIN b[428]
    DIRECTION OUTPUT ;
    USE SIGNAL ;
    PORT
      LAYER M4 ;
        RECT  51.756 16.272 51.84 16.296 ;
    END
  END b[428]
  PIN b[429]
    DIRECTION OUTPUT ;
    USE SIGNAL ;
    PORT
      LAYER M4 ;
        RECT  51.756 16.416 51.84 16.44 ;
    END
  END b[429]
  PIN b[42]
    DIRECTION OUTPUT ;
    USE SIGNAL ;
    PORT
      LAYER M4 ;
        RECT  51.756 30.96 51.84 30.984 ;
    END
  END b[42]
  PIN b[430]
    DIRECTION OUTPUT ;
    USE SIGNAL ;
    PORT
      LAYER M4 ;
        RECT  51.756 16.56 51.84 16.584 ;
    END
  END b[430]
  PIN b[431]
    DIRECTION OUTPUT ;
    USE SIGNAL ;
    PORT
      LAYER M4 ;
        RECT  51.756 16.704 51.84 16.728 ;
    END
  END b[431]
  PIN b[432]
    DIRECTION OUTPUT ;
    USE SIGNAL ;
    PORT
      LAYER M4 ;
        RECT  51.756 16.848 51.84 16.872 ;
    END
  END b[432]
  PIN b[433]
    DIRECTION OUTPUT ;
    USE SIGNAL ;
    PORT
      LAYER M4 ;
        RECT  51.756 16.992 51.84 17.016 ;
    END
  END b[433]
  PIN b[434]
    DIRECTION OUTPUT ;
    USE SIGNAL ;
    PORT
      LAYER M4 ;
        RECT  51.756 17.136 51.84 17.16 ;
    END
  END b[434]
  PIN b[435]
    DIRECTION OUTPUT ;
    USE SIGNAL ;
    PORT
      LAYER M4 ;
        RECT  51.756 17.28 51.84 17.304 ;
    END
  END b[435]
  PIN b[436]
    DIRECTION OUTPUT ;
    USE SIGNAL ;
    PORT
      LAYER M4 ;
        RECT  51.756 17.424 51.84 17.448 ;
    END
  END b[436]
  PIN b[437]
    DIRECTION OUTPUT ;
    USE SIGNAL ;
    PORT
      LAYER M4 ;
        RECT  51.756 17.568 51.84 17.592 ;
    END
  END b[437]
  PIN b[438]
    DIRECTION OUTPUT ;
    USE SIGNAL ;
    PORT
      LAYER M4 ;
        RECT  51.756 17.712 51.84 17.736 ;
    END
  END b[438]
  PIN b[439]
    DIRECTION OUTPUT ;
    USE SIGNAL ;
    PORT
      LAYER M4 ;
        RECT  51.756 17.856 51.84 17.88 ;
    END
  END b[439]
  PIN b[43]
    DIRECTION OUTPUT ;
    USE SIGNAL ;
    PORT
      LAYER M4 ;
        RECT  51.756 31.104 51.84 31.128 ;
    END
  END b[43]
  PIN b[440]
    DIRECTION OUTPUT ;
    USE SIGNAL ;
    PORT
      LAYER M4 ;
        RECT  51.756 18 51.84 18.024 ;
    END
  END b[440]
  PIN b[441]
    DIRECTION OUTPUT ;
    USE SIGNAL ;
    PORT
      LAYER M4 ;
        RECT  51.756 18.144 51.84 18.168 ;
    END
  END b[441]
  PIN b[442]
    DIRECTION OUTPUT ;
    USE SIGNAL ;
    PORT
      LAYER M4 ;
        RECT  51.756 18.288 51.84 18.312 ;
    END
  END b[442]
  PIN b[443]
    DIRECTION OUTPUT ;
    USE SIGNAL ;
    PORT
      LAYER M4 ;
        RECT  51.756 18.432 51.84 18.456 ;
    END
  END b[443]
  PIN b[444]
    DIRECTION OUTPUT ;
    USE SIGNAL ;
    PORT
      LAYER M4 ;
        RECT  51.756 18.576 51.84 18.6 ;
    END
  END b[444]
  PIN b[445]
    DIRECTION OUTPUT ;
    USE SIGNAL ;
    PORT
      LAYER M4 ;
        RECT  51.756 18.72 51.84 18.744 ;
    END
  END b[445]
  PIN b[446]
    DIRECTION OUTPUT ;
    USE SIGNAL ;
    PORT
      LAYER M4 ;
        RECT  51.756 18.864 51.84 18.888 ;
    END
  END b[446]
  PIN b[447]
    DIRECTION OUTPUT ;
    USE SIGNAL ;
    PORT
      LAYER M4 ;
        RECT  51.756 19.008 51.84 19.032 ;
    END
  END b[447]
  PIN b[448]
    DIRECTION OUTPUT ;
    USE SIGNAL ;
    PORT
      LAYER M4 ;
        RECT  51.756 0.72 51.84 0.744 ;
    END
  END b[448]
  PIN b[449]
    DIRECTION OUTPUT ;
    USE SIGNAL ;
    PORT
      LAYER M4 ;
        RECT  51.756 0.864 51.84 0.888 ;
    END
  END b[449]
  PIN b[44]
    DIRECTION OUTPUT ;
    USE SIGNAL ;
    PORT
      LAYER M4 ;
        RECT  51.756 31.248 51.84 31.272 ;
    END
  END b[44]
  PIN b[450]
    DIRECTION OUTPUT ;
    USE SIGNAL ;
    PORT
      LAYER M4 ;
        RECT  51.756 1.008 51.84 1.032 ;
    END
  END b[450]
  PIN b[451]
    DIRECTION OUTPUT ;
    USE SIGNAL ;
    PORT
      LAYER M4 ;
        RECT  51.756 1.152 51.84 1.176 ;
    END
  END b[451]
  PIN b[452]
    DIRECTION OUTPUT ;
    USE SIGNAL ;
    PORT
      LAYER M4 ;
        RECT  51.756 1.296 51.84 1.32 ;
    END
  END b[452]
  PIN b[453]
    DIRECTION OUTPUT ;
    USE SIGNAL ;
    PORT
      LAYER M4 ;
        RECT  51.756 1.44 51.84 1.464 ;
    END
  END b[453]
  PIN b[454]
    DIRECTION OUTPUT ;
    USE SIGNAL ;
    PORT
      LAYER M4 ;
        RECT  51.756 1.584 51.84 1.608 ;
    END
  END b[454]
  PIN b[455]
    DIRECTION OUTPUT ;
    USE SIGNAL ;
    PORT
      LAYER M4 ;
        RECT  51.756 1.728 51.84 1.752 ;
    END
  END b[455]
  PIN b[456]
    DIRECTION OUTPUT ;
    USE SIGNAL ;
    PORT
      LAYER M4 ;
        RECT  51.756 1.872 51.84 1.896 ;
    END
  END b[456]
  PIN b[457]
    DIRECTION OUTPUT ;
    USE SIGNAL ;
    PORT
      LAYER M4 ;
        RECT  51.756 2.016 51.84 2.04 ;
    END
  END b[457]
  PIN b[458]
    DIRECTION OUTPUT ;
    USE SIGNAL ;
    PORT
      LAYER M4 ;
        RECT  51.756 2.16 51.84 2.184 ;
    END
  END b[458]
  PIN b[459]
    DIRECTION OUTPUT ;
    USE SIGNAL ;
    PORT
      LAYER M4 ;
        RECT  51.756 2.304 51.84 2.328 ;
    END
  END b[459]
  PIN b[45]
    DIRECTION OUTPUT ;
    USE SIGNAL ;
    PORT
      LAYER M4 ;
        RECT  51.756 31.392 51.84 31.416 ;
    END
  END b[45]
  PIN b[460]
    DIRECTION OUTPUT ;
    USE SIGNAL ;
    PORT
      LAYER M4 ;
        RECT  51.756 2.448 51.84 2.472 ;
    END
  END b[460]
  PIN b[461]
    DIRECTION OUTPUT ;
    USE SIGNAL ;
    PORT
      LAYER M4 ;
        RECT  51.756 2.592 51.84 2.616 ;
    END
  END b[461]
  PIN b[462]
    DIRECTION OUTPUT ;
    USE SIGNAL ;
    PORT
      LAYER M4 ;
        RECT  51.756 2.736 51.84 2.76 ;
    END
  END b[462]
  PIN b[463]
    DIRECTION OUTPUT ;
    USE SIGNAL ;
    PORT
      LAYER M4 ;
        RECT  51.756 2.88 51.84 2.904 ;
    END
  END b[463]
  PIN b[464]
    DIRECTION OUTPUT ;
    USE SIGNAL ;
    PORT
      LAYER M4 ;
        RECT  51.756 3.024 51.84 3.048 ;
    END
  END b[464]
  PIN b[465]
    DIRECTION OUTPUT ;
    USE SIGNAL ;
    PORT
      LAYER M4 ;
        RECT  51.756 3.168 51.84 3.192 ;
    END
  END b[465]
  PIN b[466]
    DIRECTION OUTPUT ;
    USE SIGNAL ;
    PORT
      LAYER M4 ;
        RECT  51.756 3.312 51.84 3.336 ;
    END
  END b[466]
  PIN b[467]
    DIRECTION OUTPUT ;
    USE SIGNAL ;
    PORT
      LAYER M4 ;
        RECT  51.756 3.456 51.84 3.48 ;
    END
  END b[467]
  PIN b[468]
    DIRECTION OUTPUT ;
    USE SIGNAL ;
    PORT
      LAYER M4 ;
        RECT  51.756 3.6 51.84 3.624 ;
    END
  END b[468]
  PIN b[469]
    DIRECTION OUTPUT ;
    USE SIGNAL ;
    PORT
      LAYER M4 ;
        RECT  51.756 3.744 51.84 3.768 ;
    END
  END b[469]
  PIN b[46]
    DIRECTION OUTPUT ;
    USE SIGNAL ;
    PORT
      LAYER M4 ;
        RECT  51.756 31.536 51.84 31.56 ;
    END
  END b[46]
  PIN b[470]
    DIRECTION OUTPUT ;
    USE SIGNAL ;
    PORT
      LAYER M4 ;
        RECT  51.756 3.888 51.84 3.912 ;
    END
  END b[470]
  PIN b[471]
    DIRECTION OUTPUT ;
    USE SIGNAL ;
    PORT
      LAYER M4 ;
        RECT  51.756 4.032 51.84 4.056 ;
    END
  END b[471]
  PIN b[472]
    DIRECTION OUTPUT ;
    USE SIGNAL ;
    PORT
      LAYER M4 ;
        RECT  51.756 4.176 51.84 4.2 ;
    END
  END b[472]
  PIN b[473]
    DIRECTION OUTPUT ;
    USE SIGNAL ;
    PORT
      LAYER M4 ;
        RECT  51.756 4.32 51.84 4.344 ;
    END
  END b[473]
  PIN b[474]
    DIRECTION OUTPUT ;
    USE SIGNAL ;
    PORT
      LAYER M4 ;
        RECT  51.756 4.464 51.84 4.488 ;
    END
  END b[474]
  PIN b[475]
    DIRECTION OUTPUT ;
    USE SIGNAL ;
    PORT
      LAYER M4 ;
        RECT  51.756 4.608 51.84 4.632 ;
    END
  END b[475]
  PIN b[476]
    DIRECTION OUTPUT ;
    USE SIGNAL ;
    PORT
      LAYER M4 ;
        RECT  51.756 4.752 51.84 4.776 ;
    END
  END b[476]
  PIN b[477]
    DIRECTION OUTPUT ;
    USE SIGNAL ;
    PORT
      LAYER M4 ;
        RECT  51.756 4.896 51.84 4.92 ;
    END
  END b[477]
  PIN b[478]
    DIRECTION OUTPUT ;
    USE SIGNAL ;
    PORT
      LAYER M4 ;
        RECT  51.756 5.04 51.84 5.064 ;
    END
  END b[478]
  PIN b[479]
    DIRECTION OUTPUT ;
    USE SIGNAL ;
    PORT
      LAYER M4 ;
        RECT  51.756 5.184 51.84 5.208 ;
    END
  END b[479]
  PIN b[47]
    DIRECTION OUTPUT ;
    USE SIGNAL ;
    PORT
      LAYER M4 ;
        RECT  51.756 31.68 51.84 31.704 ;
    END
  END b[47]
  PIN b[480]
    DIRECTION OUTPUT ;
    USE SIGNAL ;
    PORT
      LAYER M4 ;
        RECT  51.756 9.936 51.84 9.96 ;
    END
  END b[480]
  PIN b[481]
    DIRECTION OUTPUT ;
    USE SIGNAL ;
    PORT
      LAYER M4 ;
        RECT  51.756 10.08 51.84 10.104 ;
    END
  END b[481]
  PIN b[482]
    DIRECTION OUTPUT ;
    USE SIGNAL ;
    PORT
      LAYER M4 ;
        RECT  51.756 10.224 51.84 10.248 ;
    END
  END b[482]
  PIN b[483]
    DIRECTION OUTPUT ;
    USE SIGNAL ;
    PORT
      LAYER M4 ;
        RECT  51.756 10.368 51.84 10.392 ;
    END
  END b[483]
  PIN b[484]
    DIRECTION OUTPUT ;
    USE SIGNAL ;
    PORT
      LAYER M4 ;
        RECT  51.756 10.512 51.84 10.536 ;
    END
  END b[484]
  PIN b[485]
    DIRECTION OUTPUT ;
    USE SIGNAL ;
    PORT
      LAYER M4 ;
        RECT  51.756 10.656 51.84 10.68 ;
    END
  END b[485]
  PIN b[486]
    DIRECTION OUTPUT ;
    USE SIGNAL ;
    PORT
      LAYER M4 ;
        RECT  51.756 10.8 51.84 10.824 ;
    END
  END b[486]
  PIN b[487]
    DIRECTION OUTPUT ;
    USE SIGNAL ;
    PORT
      LAYER M4 ;
        RECT  51.756 10.944 51.84 10.968 ;
    END
  END b[487]
  PIN b[488]
    DIRECTION OUTPUT ;
    USE SIGNAL ;
    PORT
      LAYER M4 ;
        RECT  51.756 11.088 51.84 11.112 ;
    END
  END b[488]
  PIN b[489]
    DIRECTION OUTPUT ;
    USE SIGNAL ;
    PORT
      LAYER M4 ;
        RECT  51.756 11.232 51.84 11.256 ;
    END
  END b[489]
  PIN b[48]
    DIRECTION OUTPUT ;
    USE SIGNAL ;
    PORT
      LAYER M4 ;
        RECT  51.756 31.824 51.84 31.848 ;
    END
  END b[48]
  PIN b[490]
    DIRECTION OUTPUT ;
    USE SIGNAL ;
    PORT
      LAYER M4 ;
        RECT  51.756 11.376 51.84 11.4 ;
    END
  END b[490]
  PIN b[491]
    DIRECTION OUTPUT ;
    USE SIGNAL ;
    PORT
      LAYER M4 ;
        RECT  51.756 11.52 51.84 11.544 ;
    END
  END b[491]
  PIN b[492]
    DIRECTION OUTPUT ;
    USE SIGNAL ;
    PORT
      LAYER M4 ;
        RECT  51.756 11.664 51.84 11.688 ;
    END
  END b[492]
  PIN b[493]
    DIRECTION OUTPUT ;
    USE SIGNAL ;
    PORT
      LAYER M4 ;
        RECT  51.756 11.808 51.84 11.832 ;
    END
  END b[493]
  PIN b[494]
    DIRECTION OUTPUT ;
    USE SIGNAL ;
    PORT
      LAYER M4 ;
        RECT  51.756 11.952 51.84 11.976 ;
    END
  END b[494]
  PIN b[495]
    DIRECTION OUTPUT ;
    USE SIGNAL ;
    PORT
      LAYER M4 ;
        RECT  51.756 12.096 51.84 12.12 ;
    END
  END b[495]
  PIN b[496]
    DIRECTION OUTPUT ;
    USE SIGNAL ;
    PORT
      LAYER M4 ;
        RECT  51.756 12.24 51.84 12.264 ;
    END
  END b[496]
  PIN b[497]
    DIRECTION OUTPUT ;
    USE SIGNAL ;
    PORT
      LAYER M4 ;
        RECT  51.756 12.384 51.84 12.408 ;
    END
  END b[497]
  PIN b[498]
    DIRECTION OUTPUT ;
    USE SIGNAL ;
    PORT
      LAYER M4 ;
        RECT  51.756 12.528 51.84 12.552 ;
    END
  END b[498]
  PIN b[499]
    DIRECTION OUTPUT ;
    USE SIGNAL ;
    PORT
      LAYER M4 ;
        RECT  51.756 12.672 51.84 12.696 ;
    END
  END b[499]
  PIN b[49]
    DIRECTION OUTPUT ;
    USE SIGNAL ;
    PORT
      LAYER M4 ;
        RECT  51.756 31.968 51.84 31.992 ;
    END
  END b[49]
  PIN b[4]
    DIRECTION OUTPUT ;
    USE SIGNAL ;
    PORT
      LAYER M4 ;
        RECT  51.756 34.704 51.84 34.728 ;
    END
  END b[4]
  PIN b[500]
    DIRECTION OUTPUT ;
    USE SIGNAL ;
    PORT
      LAYER M4 ;
        RECT  51.756 12.816 51.84 12.84 ;
    END
  END b[500]
  PIN b[501]
    DIRECTION OUTPUT ;
    USE SIGNAL ;
    PORT
      LAYER M4 ;
        RECT  51.756 12.96 51.84 12.984 ;
    END
  END b[501]
  PIN b[502]
    DIRECTION OUTPUT ;
    USE SIGNAL ;
    PORT
      LAYER M4 ;
        RECT  51.756 13.104 51.84 13.128 ;
    END
  END b[502]
  PIN b[503]
    DIRECTION OUTPUT ;
    USE SIGNAL ;
    PORT
      LAYER M4 ;
        RECT  51.756 13.248 51.84 13.272 ;
    END
  END b[503]
  PIN b[504]
    DIRECTION OUTPUT ;
    USE SIGNAL ;
    PORT
      LAYER M4 ;
        RECT  51.756 13.392 51.84 13.416 ;
    END
  END b[504]
  PIN b[505]
    DIRECTION OUTPUT ;
    USE SIGNAL ;
    PORT
      LAYER M4 ;
        RECT  51.756 13.536 51.84 13.56 ;
    END
  END b[505]
  PIN b[506]
    DIRECTION OUTPUT ;
    USE SIGNAL ;
    PORT
      LAYER M4 ;
        RECT  51.756 13.68 51.84 13.704 ;
    END
  END b[506]
  PIN b[507]
    DIRECTION OUTPUT ;
    USE SIGNAL ;
    PORT
      LAYER M4 ;
        RECT  51.756 13.824 51.84 13.848 ;
    END
  END b[507]
  PIN b[508]
    DIRECTION OUTPUT ;
    USE SIGNAL ;
    PORT
      LAYER M4 ;
        RECT  51.756 13.968 51.84 13.992 ;
    END
  END b[508]
  PIN b[509]
    DIRECTION OUTPUT ;
    USE SIGNAL ;
    PORT
      LAYER M4 ;
        RECT  51.756 14.112 51.84 14.136 ;
    END
  END b[509]
  PIN b[50]
    DIRECTION OUTPUT ;
    USE SIGNAL ;
    PORT
      LAYER M4 ;
        RECT  51.756 32.112 51.84 32.136 ;
    END
  END b[50]
  PIN b[510]
    DIRECTION OUTPUT ;
    USE SIGNAL ;
    PORT
      LAYER M4 ;
        RECT  51.756 14.256 51.84 14.28 ;
    END
  END b[510]
  PIN b[511]
    DIRECTION OUTPUT ;
    USE SIGNAL ;
    PORT
      LAYER M4 ;
        RECT  51.756 14.4 51.84 14.424 ;
    END
  END b[511]
  PIN b[512]
    DIRECTION OUTPUT ;
    USE SIGNAL ;
    PORT
      LAYER M4 ;
        RECT  51.756 58.32 51.84 58.344 ;
    END
  END b[512]
  PIN b[513]
    DIRECTION OUTPUT ;
    USE SIGNAL ;
    PORT
      LAYER M4 ;
        RECT  51.756 58.464 51.84 58.488 ;
    END
  END b[513]
  PIN b[514]
    DIRECTION OUTPUT ;
    USE SIGNAL ;
    PORT
      LAYER M4 ;
        RECT  51.756 58.608 51.84 58.632 ;
    END
  END b[514]
  PIN b[515]
    DIRECTION OUTPUT ;
    USE SIGNAL ;
    PORT
      LAYER M4 ;
        RECT  51.756 58.752 51.84 58.776 ;
    END
  END b[515]
  PIN b[516]
    DIRECTION OUTPUT ;
    USE SIGNAL ;
    PORT
      LAYER M4 ;
        RECT  51.756 58.896 51.84 58.92 ;
    END
  END b[516]
  PIN b[517]
    DIRECTION OUTPUT ;
    USE SIGNAL ;
    PORT
      LAYER M4 ;
        RECT  51.756 59.04 51.84 59.064 ;
    END
  END b[517]
  PIN b[518]
    DIRECTION OUTPUT ;
    USE SIGNAL ;
    PORT
      LAYER M4 ;
        RECT  51.756 59.184 51.84 59.208 ;
    END
  END b[518]
  PIN b[519]
    DIRECTION OUTPUT ;
    USE SIGNAL ;
    PORT
      LAYER M4 ;
        RECT  51.756 59.328 51.84 59.352 ;
    END
  END b[519]
  PIN b[51]
    DIRECTION OUTPUT ;
    USE SIGNAL ;
    PORT
      LAYER M4 ;
        RECT  51.756 32.256 51.84 32.28 ;
    END
  END b[51]
  PIN b[520]
    DIRECTION OUTPUT ;
    USE SIGNAL ;
    PORT
      LAYER M4 ;
        RECT  51.756 59.472 51.84 59.496 ;
    END
  END b[520]
  PIN b[521]
    DIRECTION OUTPUT ;
    USE SIGNAL ;
    PORT
      LAYER M4 ;
        RECT  51.756 59.616 51.84 59.64 ;
    END
  END b[521]
  PIN b[522]
    DIRECTION OUTPUT ;
    USE SIGNAL ;
    PORT
      LAYER M4 ;
        RECT  51.756 59.76 51.84 59.784 ;
    END
  END b[522]
  PIN b[523]
    DIRECTION OUTPUT ;
    USE SIGNAL ;
    PORT
      LAYER M4 ;
        RECT  51.756 59.904 51.84 59.928 ;
    END
  END b[523]
  PIN b[524]
    DIRECTION OUTPUT ;
    USE SIGNAL ;
    PORT
      LAYER M4 ;
        RECT  51.756 60.048 51.84 60.072 ;
    END
  END b[524]
  PIN b[525]
    DIRECTION OUTPUT ;
    USE SIGNAL ;
    PORT
      LAYER M4 ;
        RECT  51.756 60.192 51.84 60.216 ;
    END
  END b[525]
  PIN b[526]
    DIRECTION OUTPUT ;
    USE SIGNAL ;
    PORT
      LAYER M4 ;
        RECT  51.756 60.336 51.84 60.36 ;
    END
  END b[526]
  PIN b[527]
    DIRECTION OUTPUT ;
    USE SIGNAL ;
    PORT
      LAYER M4 ;
        RECT  51.756 60.48 51.84 60.504 ;
    END
  END b[527]
  PIN b[52]
    DIRECTION OUTPUT ;
    USE SIGNAL ;
    PORT
      LAYER M4 ;
        RECT  51.756 32.4 51.84 32.424 ;
    END
  END b[52]
  PIN b[53]
    DIRECTION OUTPUT ;
    USE SIGNAL ;
    PORT
      LAYER M4 ;
        RECT  51.756 32.544 51.84 32.568 ;
    END
  END b[53]
  PIN b[54]
    DIRECTION OUTPUT ;
    USE SIGNAL ;
    PORT
      LAYER M4 ;
        RECT  51.756 32.688 51.84 32.712 ;
    END
  END b[54]
  PIN b[55]
    DIRECTION OUTPUT ;
    USE SIGNAL ;
    PORT
      LAYER M4 ;
        RECT  51.756 32.832 51.84 32.856 ;
    END
  END b[55]
  PIN b[56]
    DIRECTION OUTPUT ;
    USE SIGNAL ;
    PORT
      LAYER M4 ;
        RECT  51.756 32.976 51.84 33 ;
    END
  END b[56]
  PIN b[57]
    DIRECTION OUTPUT ;
    USE SIGNAL ;
    PORT
      LAYER M4 ;
        RECT  51.756 33.12 51.84 33.144 ;
    END
  END b[57]
  PIN b[58]
    DIRECTION OUTPUT ;
    USE SIGNAL ;
    PORT
      LAYER M4 ;
        RECT  51.756 33.264 51.84 33.288 ;
    END
  END b[58]
  PIN b[59]
    DIRECTION OUTPUT ;
    USE SIGNAL ;
    PORT
      LAYER M4 ;
        RECT  51.756 33.408 51.84 33.432 ;
    END
  END b[59]
  PIN b[5]
    DIRECTION OUTPUT ;
    USE SIGNAL ;
    PORT
      LAYER M4 ;
        RECT  51.756 34.848 51.84 34.872 ;
    END
  END b[5]
  PIN b[60]
    DIRECTION OUTPUT ;
    USE SIGNAL ;
    PORT
      LAYER M4 ;
        RECT  51.756 33.552 51.84 33.576 ;
    END
  END b[60]
  PIN b[61]
    DIRECTION OUTPUT ;
    USE SIGNAL ;
    PORT
      LAYER M4 ;
        RECT  51.756 33.696 51.84 33.72 ;
    END
  END b[61]
  PIN b[62]
    DIRECTION OUTPUT ;
    USE SIGNAL ;
    PORT
      LAYER M4 ;
        RECT  51.756 33.84 51.84 33.864 ;
    END
  END b[62]
  PIN b[63]
    DIRECTION OUTPUT ;
    USE SIGNAL ;
    PORT
      LAYER M4 ;
        RECT  51.756 33.984 51.84 34.008 ;
    END
  END b[63]
  PIN b[64]
    DIRECTION OUTPUT ;
    USE SIGNAL ;
    PORT
      LAYER M4 ;
        RECT  51.756 52.56 51.84 52.584 ;
    END
  END b[64]
  PIN b[65]
    DIRECTION OUTPUT ;
    USE SIGNAL ;
    PORT
      LAYER M4 ;
        RECT  51.756 52.704 51.84 52.728 ;
    END
  END b[65]
  PIN b[66]
    DIRECTION OUTPUT ;
    USE SIGNAL ;
    PORT
      LAYER M4 ;
        RECT  51.756 52.848 51.84 52.872 ;
    END
  END b[66]
  PIN b[67]
    DIRECTION OUTPUT ;
    USE SIGNAL ;
    PORT
      LAYER M4 ;
        RECT  51.756 52.992 51.84 53.016 ;
    END
  END b[67]
  PIN b[68]
    DIRECTION OUTPUT ;
    USE SIGNAL ;
    PORT
      LAYER M4 ;
        RECT  51.756 53.136 51.84 53.16 ;
    END
  END b[68]
  PIN b[69]
    DIRECTION OUTPUT ;
    USE SIGNAL ;
    PORT
      LAYER M4 ;
        RECT  51.756 53.28 51.84 53.304 ;
    END
  END b[69]
  PIN b[6]
    DIRECTION OUTPUT ;
    USE SIGNAL ;
    PORT
      LAYER M4 ;
        RECT  51.756 34.992 51.84 35.016 ;
    END
  END b[6]
  PIN b[70]
    DIRECTION OUTPUT ;
    USE SIGNAL ;
    PORT
      LAYER M4 ;
        RECT  51.756 53.424 51.84 53.448 ;
    END
  END b[70]
  PIN b[71]
    DIRECTION OUTPUT ;
    USE SIGNAL ;
    PORT
      LAYER M4 ;
        RECT  51.756 53.568 51.84 53.592 ;
    END
  END b[71]
  PIN b[72]
    DIRECTION OUTPUT ;
    USE SIGNAL ;
    PORT
      LAYER M4 ;
        RECT  51.756 53.712 51.84 53.736 ;
    END
  END b[72]
  PIN b[73]
    DIRECTION OUTPUT ;
    USE SIGNAL ;
    PORT
      LAYER M4 ;
        RECT  51.756 53.856 51.84 53.88 ;
    END
  END b[73]
  PIN b[74]
    DIRECTION OUTPUT ;
    USE SIGNAL ;
    PORT
      LAYER M4 ;
        RECT  51.756 54 51.84 54.024 ;
    END
  END b[74]
  PIN b[75]
    DIRECTION OUTPUT ;
    USE SIGNAL ;
    PORT
      LAYER M4 ;
        RECT  51.756 54.144 51.84 54.168 ;
    END
  END b[75]
  PIN b[76]
    DIRECTION OUTPUT ;
    USE SIGNAL ;
    PORT
      LAYER M4 ;
        RECT  51.756 54.288 51.84 54.312 ;
    END
  END b[76]
  PIN b[77]
    DIRECTION OUTPUT ;
    USE SIGNAL ;
    PORT
      LAYER M4 ;
        RECT  51.756 54.432 51.84 54.456 ;
    END
  END b[77]
  PIN b[78]
    DIRECTION OUTPUT ;
    USE SIGNAL ;
    PORT
      LAYER M4 ;
        RECT  51.756 54.576 51.84 54.6 ;
    END
  END b[78]
  PIN b[79]
    DIRECTION OUTPUT ;
    USE SIGNAL ;
    PORT
      LAYER M4 ;
        RECT  51.756 54.72 51.84 54.744 ;
    END
  END b[79]
  PIN b[7]
    DIRECTION OUTPUT ;
    USE SIGNAL ;
    PORT
      LAYER M4 ;
        RECT  51.756 35.136 51.84 35.16 ;
    END
  END b[7]
  PIN b[80]
    DIRECTION OUTPUT ;
    USE SIGNAL ;
    PORT
      LAYER M4 ;
        RECT  51.756 54.864 51.84 54.888 ;
    END
  END b[80]
  PIN b[81]
    DIRECTION OUTPUT ;
    USE SIGNAL ;
    PORT
      LAYER M4 ;
        RECT  51.756 55.008 51.84 55.032 ;
    END
  END b[81]
  PIN b[82]
    DIRECTION OUTPUT ;
    USE SIGNAL ;
    PORT
      LAYER M4 ;
        RECT  51.756 55.152 51.84 55.176 ;
    END
  END b[82]
  PIN b[83]
    DIRECTION OUTPUT ;
    USE SIGNAL ;
    PORT
      LAYER M4 ;
        RECT  51.756 55.296 51.84 55.32 ;
    END
  END b[83]
  PIN b[84]
    DIRECTION OUTPUT ;
    USE SIGNAL ;
    PORT
      LAYER M4 ;
        RECT  51.756 55.44 51.84 55.464 ;
    END
  END b[84]
  PIN b[85]
    DIRECTION OUTPUT ;
    USE SIGNAL ;
    PORT
      LAYER M4 ;
        RECT  51.756 55.584 51.84 55.608 ;
    END
  END b[85]
  PIN b[86]
    DIRECTION OUTPUT ;
    USE SIGNAL ;
    PORT
      LAYER M4 ;
        RECT  51.756 55.728 51.84 55.752 ;
    END
  END b[86]
  PIN b[87]
    DIRECTION OUTPUT ;
    USE SIGNAL ;
    PORT
      LAYER M4 ;
        RECT  51.756 55.872 51.84 55.896 ;
    END
  END b[87]
  PIN b[88]
    DIRECTION OUTPUT ;
    USE SIGNAL ;
    PORT
      LAYER M4 ;
        RECT  51.756 56.016 51.84 56.04 ;
    END
  END b[88]
  PIN b[89]
    DIRECTION OUTPUT ;
    USE SIGNAL ;
    PORT
      LAYER M4 ;
        RECT  51.756 56.16 51.84 56.184 ;
    END
  END b[89]
  PIN b[8]
    DIRECTION OUTPUT ;
    USE SIGNAL ;
    PORT
      LAYER M4 ;
        RECT  51.756 35.28 51.84 35.304 ;
    END
  END b[8]
  PIN b[90]
    DIRECTION OUTPUT ;
    USE SIGNAL ;
    PORT
      LAYER M4 ;
        RECT  51.756 56.304 51.84 56.328 ;
    END
  END b[90]
  PIN b[91]
    DIRECTION OUTPUT ;
    USE SIGNAL ;
    PORT
      LAYER M4 ;
        RECT  51.756 56.448 51.84 56.472 ;
    END
  END b[91]
  PIN b[92]
    DIRECTION OUTPUT ;
    USE SIGNAL ;
    PORT
      LAYER M4 ;
        RECT  51.756 56.592 51.84 56.616 ;
    END
  END b[92]
  PIN b[93]
    DIRECTION OUTPUT ;
    USE SIGNAL ;
    PORT
      LAYER M4 ;
        RECT  51.756 56.736 51.84 56.76 ;
    END
  END b[93]
  PIN b[94]
    DIRECTION OUTPUT ;
    USE SIGNAL ;
    PORT
      LAYER M4 ;
        RECT  51.756 56.88 51.84 56.904 ;
    END
  END b[94]
  PIN b[95]
    DIRECTION OUTPUT ;
    USE SIGNAL ;
    PORT
      LAYER M4 ;
        RECT  51.756 57.024 51.84 57.048 ;
    END
  END b[95]
  PIN b[96]
    DIRECTION OUTPUT ;
    USE SIGNAL ;
    PORT
      LAYER M4 ;
        RECT  51.756 72.144 51.84 72.168 ;
    END
  END b[96]
  PIN b[97]
    DIRECTION OUTPUT ;
    USE SIGNAL ;
    PORT
      LAYER M4 ;
        RECT  51.756 72.288 51.84 72.312 ;
    END
  END b[97]
  PIN b[98]
    DIRECTION OUTPUT ;
    USE SIGNAL ;
    PORT
      LAYER M4 ;
        RECT  51.756 72.432 51.84 72.456 ;
    END
  END b[98]
  PIN b[99]
    DIRECTION OUTPUT ;
    USE SIGNAL ;
    PORT
      LAYER M4 ;
        RECT  51.756 72.576 51.84 72.6 ;
    END
  END b[99]
  PIN b[9]
    DIRECTION OUTPUT ;
    USE SIGNAL ;
    PORT
      LAYER M4 ;
        RECT  51.756 35.424 51.84 35.448 ;
    END
  END b[9]
  PIN ck
    DIRECTION INPUT ;
    USE SIGNAL ;
    PORT
      LAYER M5 ;
        RECT  20.88 0 20.904 0.084 ;
    END
  END ck
  PIN ckf
    DIRECTION INPUT ;
    USE SIGNAL ;
    PORT
      LAYER M5 ;
        RECT  21.024 0 21.048 0.084 ;
    END
  END ckf
  PIN ea
    DIRECTION INPUT ;
    USE SIGNAL ;
    PORT
      LAYER M5 ;
        RECT  21.168 0 21.192 0.084 ;
    END
  END ea
  PIN fault
    DIRECTION OUTPUT ;
    USE SIGNAL ;
    PORT
      LAYER M3 ;
        RECT  21.276 82.043 21.294 82.08 ;
    END
  END fault
  PIN k0
    DIRECTION INPUT ;
    USE SIGNAL ;
    PORT
      LAYER M5 ;
        RECT  21.312 0 21.336 0.084 ;
    END
  END k0
  PIN k1
    DIRECTION INPUT ;
    USE SIGNAL ;
    PORT
      LAYER M5 ;
        RECT  21.456 0 21.48 0.084 ;
    END
  END k1
  PIN k2
    DIRECTION INPUT ;
    USE SIGNAL ;
    PORT
      LAYER M5 ;
        RECT  21.6 0 21.624 0.084 ;
    END
  END k2
  PIN rs
    DIRECTION INPUT ;
    USE SIGNAL ;
    PORT
      LAYER M5 ;
        RECT  21.744 0 21.768 0.084 ;
    END
  END rs
  PIN tie_hi
    DIRECTION OUTPUT ;
    USE SIGNAL ;
    PORT
      LAYER M3 ;
        RECT  21.384 82.043 21.402 82.08 ;
    END
  END tie_hi
  PIN tie_lo
    DIRECTION OUTPUT ;
    USE SIGNAL ;
    PORT
      LAYER M3 ;
        RECT  21.492 82.043 21.51 82.08 ;
    END
  END tie_lo
  PIN VDD
    DIRECTION INOUT ;
    USE POWER ;
    PORT
      LAYER M5 ;
        RECT  48.492 2.151 48.612 79.929 ;
        RECT  45.792 2.151 45.912 79.929 ;
        RECT  43.092 2.151 43.212 79.929 ;
        RECT  40.392 2.151 40.512 79.929 ;
        RECT  37.692 2.151 37.812 79.929 ;
        RECT  34.992 2.151 35.112 79.929 ;
        RECT  32.292 2.151 32.412 79.929 ;
        RECT  29.592 2.151 29.712 79.929 ;
        RECT  26.892 2.151 27.012 79.929 ;
        RECT  24.192 2.151 24.312 79.929 ;
        RECT  21.492 2.151 21.612 79.929 ;
        RECT  18.792 2.151 18.912 79.929 ;
        RECT  16.092 2.151 16.212 79.929 ;
        RECT  13.392 2.151 13.512 79.929 ;
        RECT  10.692 2.151 10.812 79.929 ;
        RECT  7.992 2.151 8.112 79.929 ;
        RECT  5.292 2.151 5.412 79.929 ;
        RECT  2.592 2.151 2.712 79.929 ;
    END
  END VDD
  PIN VSS
    DIRECTION INOUT ;
    USE GROUND ;
    PORT
      LAYER M5 ;
        RECT  48.3 2.137 48.42 79.943 ;
        RECT  45.6 2.137 45.72 79.943 ;
        RECT  42.9 2.137 43.02 79.943 ;
        RECT  40.2 2.137 40.32 79.943 ;
        RECT  37.5 2.137 37.62 79.943 ;
        RECT  34.8 2.137 34.92 79.943 ;
        RECT  32.1 2.137 32.22 79.943 ;
        RECT  29.4 2.137 29.52 79.943 ;
        RECT  26.7 2.137 26.82 79.943 ;
        RECT  24 2.137 24.12 79.943 ;
        RECT  21.3 2.137 21.42 79.943 ;
        RECT  18.6 2.137 18.72 79.943 ;
        RECT  15.9 2.137 16.02 79.943 ;
        RECT  13.2 2.137 13.32 79.943 ;
        RECT  10.5 2.137 10.62 79.943 ;
        RECT  7.8 2.137 7.92 79.943 ;
        RECT  5.1 2.137 5.22 79.943 ;
        RECT  2.4 2.137 2.52 79.943 ;
    END
  END VSS
  OBS
    LAYER LVTN ;
     RECT  9.99 3.645 10.314 3.78 ;
     RECT  13.554 4.185 14.094 4.32 ;
     RECT  14.202 4.185 14.364 4.32 ;
     RECT  12.852 4.86 13.392 4.995 ;
     RECT  13.5 5.805 13.932 5.94 ;
     RECT  13.5 6.48 13.662 6.615 ;
     RECT  13.662 7.02 14.202 7.155 ;
     RECT  13.824 7.965 14.256 8.1 ;
     RECT  14.85 9.045 15.39 9.18 ;
     RECT  11.124 10.8 11.448 10.935 ;
     RECT  39.744 11.745 40.068 11.88 ;
     RECT  19.278 17.82 19.818 17.955 ;
     RECT  22.464 19.305 22.788 19.44 ;
     RECT  10.098 21.06 10.422 21.195 ;
     RECT  14.31 21.465 14.742 21.6 ;
     RECT  41.418 21.6 41.85 21.735 ;
     RECT  8.316 22.005 8.748 22.14 ;
     RECT  17.766 25.245 18.09 25.38 ;
     RECT  30.024 29.7 30.348 29.835 ;
     RECT  22.572 30.24 22.896 30.375 ;
     RECT  8.1 31.185 8.532 31.32 ;
     RECT  14.04 32.805 14.364 32.94 ;
     RECT  11.718 38.205 12.096 38.34 ;
     RECT  24.3 38.205 24.84 38.34 ;
     RECT  31.482 40.905 31.806 41.04 ;
     RECT  20.034 43.065 20.358 43.2 ;
     RECT  10.908 43.74 11.232 43.875 ;
     RECT  22.626 43.74 22.95 43.875 ;
     RECT  31.59 45.36 31.914 45.495 ;
     RECT  24.03 48.465 24.354 48.6 ;
     RECT  21.006 53.325 21.438 53.46 ;
     RECT  8.37 55.485 8.694 55.62 ;
     RECT  32.562 57.78 32.886 57.915 ;
     RECT  14.58 61.56 14.958 61.695 ;
     RECT  8.532 63.18 9.18 63.315 ;
     RECT  22.356 63.18 22.68 63.315 ;
     RECT  31.212 64.26 31.536 64.395 ;
     RECT  10.53 64.8 10.854 64.935 ;
     RECT  8.586 65.205 8.91 65.34 ;
     RECT  13.5 65.205 13.824 65.34 ;
     RECT  19.818 65.745 20.142 65.88 ;
     RECT  8.856 65.88 9.18 66.015 ;
     RECT  20.628 66.285 20.952 66.42 ;
     RECT  11.556 66.42 11.88 66.555 ;
     RECT  9.072 66.96 9.396 67.095 ;
     RECT  8.64 68.985 8.964 69.12 ;
     RECT  11.232 69.525 11.556 69.66 ;
     RECT  7.29 70.065 7.722 70.2 ;
     RECT  7.236 70.605 7.56 70.74 ;
     RECT  8.478 71.28 8.802 71.415 ;
     RECT  5.184 72.225 5.508 72.36 ;
     RECT  5.724 72.225 6.048 72.36 ;
     RECT  6.372 72.225 6.804 72.36 ;
     RECT  6.048 72.36 6.696 72.495 ;
     RECT  21.816 72.36 22.248 72.495 ;
     RECT  29.97 72.765 30.294 72.9 ;
     RECT  30.942 73.845 31.266 73.98 ;
     RECT  32.994 73.845 33.318 73.98 ;
     RECT  33.642 73.845 33.966 73.98 ;
     RECT  5.022 73.98 5.346 74.115 ;
     RECT  6.048 73.98 6.372 74.115 ;
     RECT  31.428 73.98 31.752 74.115 ;
     RECT  17.658 75.6 18.036 75.735 ;
     RECT  33.696 76.005 34.344 76.14 ;
     RECT  31.374 76.14 31.698 76.275 ;
     RECT  32.076 76.14 32.4 76.275 ;
     RECT  30.078 76.545 31.05 76.68 ;
     RECT  32.778 76.545 33.102 76.68 ;
     RECT  33.264 76.545 33.588 76.68 ;
     RECT  33.696 76.545 34.02 76.68 ;
     RECT  29.7 76.68 30.024 76.815 ;
     RECT  32.346 76.68 32.67 76.815 ;
     RECT  32.886 76.68 33.21 76.815 ;
     RECT  33.534 76.68 33.858 76.815 ;
     RECT  23.598 78.165 23.922 78.3 ;
     RECT  23.814 78.705 24.138 78.84 ;
     RECT  25.542 78.705 26.19 78.84 ;
    LAYER LVTP ;
     RECT  9.99 3.51 10.314 3.645 ;
     RECT  13.554 4.05 14.094 4.185 ;
     RECT  14.202 4.05 14.364 4.185 ;
     RECT  12.852 4.995 13.392 5.13 ;
     RECT  13.5 5.67 13.932 5.805 ;
     RECT  13.5 6.615 13.662 6.75 ;
     RECT  13.662 7.155 14.202 7.29 ;
     RECT  13.824 7.83 14.256 7.965 ;
     RECT  14.85 8.91 15.39 9.045 ;
     RECT  11.124 10.935 11.448 11.07 ;
     RECT  39.744 11.61 40.068 11.745 ;
     RECT  19.278 17.955 19.818 18.09 ;
     RECT  22.464 19.17 22.788 19.305 ;
     RECT  10.098 21.195 10.422 21.33 ;
     RECT  14.31 21.33 14.742 21.465 ;
     RECT  41.418 21.735 41.85 21.87 ;
     RECT  8.316 21.87 8.748 22.005 ;
     RECT  17.766 25.11 18.09 25.245 ;
     RECT  30.024 29.835 30.348 29.97 ;
     RECT  22.572 30.375 22.896 30.51 ;
     RECT  8.1 31.05 8.532 31.185 ;
     RECT  14.04 32.67 14.364 32.805 ;
     RECT  11.718 38.07 12.096 38.205 ;
     RECT  24.3 38.07 24.84 38.205 ;
     RECT  31.482 40.77 31.806 40.905 ;
     RECT  20.034 42.93 20.358 43.065 ;
     RECT  10.908 43.875 11.232 44.01 ;
     RECT  22.626 43.875 22.95 44.01 ;
     RECT  31.59 45.495 31.914 45.63 ;
     RECT  24.03 48.33 24.354 48.465 ;
     RECT  21.006 53.19 21.438 53.325 ;
     RECT  8.37 55.35 8.694 55.485 ;
     RECT  32.562 57.915 32.886 58.05 ;
     RECT  14.58 61.695 14.958 61.83 ;
     RECT  8.532 63.315 9.18 63.45 ;
     RECT  22.356 63.315 22.68 63.45 ;
     RECT  31.212 64.395 31.536 64.53 ;
     RECT  10.53 64.935 10.854 65.07 ;
     RECT  8.586 65.07 8.91 65.205 ;
     RECT  13.5 65.07 13.824 65.205 ;
     RECT  19.818 65.61 20.142 65.745 ;
     RECT  8.856 66.015 9.18 66.15 ;
     RECT  20.628 66.15 20.952 66.285 ;
     RECT  11.556 66.555 11.88 66.69 ;
     RECT  9.072 67.095 9.396 67.23 ;
     RECT  8.64 68.85 8.964 68.985 ;
     RECT  11.232 69.39 11.556 69.525 ;
     RECT  7.29 69.93 7.722 70.065 ;
     RECT  7.236 70.47 7.56 70.605 ;
     RECT  8.478 71.415 8.802 71.55 ;
     RECT  5.184 72.09 5.508 72.225 ;
     RECT  5.724 72.09 6.048 72.225 ;
     RECT  6.372 72.09 6.804 72.225 ;
     RECT  6.048 72.495 6.696 72.63 ;
     RECT  21.816 72.495 22.248 72.63 ;
     RECT  29.97 72.63 30.294 72.765 ;
     RECT  30.942 73.71 31.266 73.845 ;
     RECT  32.994 73.71 33.318 73.845 ;
     RECT  33.642 73.71 33.966 73.845 ;
     RECT  5.022 74.115 5.346 74.25 ;
     RECT  6.048 74.115 6.372 74.25 ;
     RECT  31.428 74.115 31.752 74.25 ;
     RECT  17.658 75.735 18.036 75.87 ;
     RECT  33.696 75.87 34.344 76.005 ;
     RECT  31.374 76.275 31.698 76.41 ;
     RECT  32.076 76.275 32.4 76.41 ;
     RECT  30.078 76.41 31.05 76.545 ;
     RECT  32.778 76.41 33.102 76.545 ;
     RECT  33.264 76.41 33.588 76.545 ;
     RECT  33.696 76.41 34.02 76.545 ;
     RECT  29.7 76.815 30.024 76.95 ;
     RECT  32.346 76.815 32.67 76.95 ;
     RECT  32.886 76.815 33.21 76.95 ;
     RECT  33.534 76.815 33.858 76.95 ;
     RECT  23.598 78.03 23.922 78.165 ;
     RECT  23.814 78.57 24.138 78.705 ;
     RECT  25.542 78.57 26.19 78.705 ;
    LAYER RVTN ;
     RECT  2.16 2.16 49.68 2.295 ;
     RECT  2.16 2.565 49.68 2.835 ;
     RECT  2.16 3.105 49.68 3.375 ;
     RECT  2.16 3.645 9.99 3.78 ;
     RECT  10.314 3.645 49.68 3.78 ;
     RECT  2.16 3.78 49.68 3.915 ;
     RECT  2.16 4.185 13.554 4.32 ;
     RECT  14.094 4.185 14.202 4.32 ;
     RECT  14.364 4.185 49.68 4.32 ;
     RECT  2.16 4.32 49.68 4.455 ;
     RECT  2.16 4.725 49.68 4.86 ;
     RECT  2.16 4.86 12.852 4.995 ;
     RECT  13.392 4.86 49.68 4.995 ;
     RECT  2.16 5.265 49.68 5.535 ;
     RECT  2.16 5.805 13.5 5.94 ;
     RECT  13.932 5.805 49.68 5.94 ;
     RECT  2.16 5.94 49.68 6.075 ;
     RECT  2.16 6.345 49.68 6.48 ;
     RECT  2.16 6.48 13.5 6.615 ;
     RECT  13.662 6.48 49.68 6.615 ;
     RECT  2.16 6.885 49.68 7.02 ;
     RECT  2.16 7.02 13.662 7.155 ;
     RECT  14.202 7.02 49.68 7.155 ;
     RECT  2.16 7.425 49.68 7.695 ;
     RECT  2.16 7.965 13.824 8.1 ;
     RECT  14.256 7.965 49.68 8.1 ;
     RECT  2.16 8.1 49.68 8.235 ;
     RECT  2.16 8.505 49.68 8.775 ;
     RECT  2.16 9.045 14.85 9.18 ;
     RECT  15.39 9.045 49.68 9.18 ;
     RECT  2.16 9.18 49.68 9.315 ;
     RECT  2.16 9.585 49.68 9.855 ;
     RECT  2.16 10.125 49.68 10.395 ;
     RECT  2.16 10.665 49.68 10.8 ;
     RECT  2.16 10.8 11.124 10.935 ;
     RECT  11.448 10.8 49.68 10.935 ;
     RECT  2.16 11.205 49.68 11.475 ;
     RECT  2.16 11.745 39.744 11.88 ;
     RECT  40.068 11.745 49.68 11.88 ;
     RECT  2.16 11.88 49.68 12.015 ;
     RECT  2.16 12.285 49.68 12.555 ;
     RECT  2.16 12.825 49.68 13.095 ;
     RECT  2.16 13.365 49.68 13.635 ;
     RECT  2.16 13.905 49.68 14.175 ;
     RECT  2.16 14.445 49.68 14.715 ;
     RECT  2.16 14.985 49.68 15.255 ;
     RECT  2.16 15.525 49.68 15.795 ;
     RECT  2.16 16.065 49.68 16.335 ;
     RECT  2.16 16.605 49.68 16.875 ;
     RECT  2.16 17.145 49.68 17.415 ;
     RECT  2.16 17.685 49.68 17.82 ;
     RECT  2.16 17.82 19.278 17.955 ;
     RECT  19.818 17.82 49.68 17.955 ;
     RECT  2.16 18.225 49.68 18.495 ;
     RECT  2.16 18.765 49.68 19.035 ;
     RECT  2.16 19.305 22.464 19.44 ;
     RECT  22.788 19.305 49.68 19.44 ;
     RECT  2.16 19.44 49.68 19.575 ;
     RECT  2.16 19.845 49.68 20.115 ;
     RECT  2.16 20.385 49.68 20.655 ;
     RECT  2.16 20.925 49.68 21.06 ;
     RECT  2.16 21.06 10.098 21.195 ;
     RECT  10.422 21.06 49.68 21.195 ;
     RECT  2.16 21.465 14.31 21.6 ;
     RECT  14.742 21.465 49.68 21.6 ;
     RECT  2.16 21.6 41.418 21.735 ;
     RECT  41.85 21.6 49.68 21.735 ;
     RECT  2.16 22.005 8.316 22.14 ;
     RECT  8.748 22.005 49.68 22.14 ;
     RECT  2.16 22.14 49.68 22.275 ;
     RECT  2.16 22.545 49.68 22.815 ;
     RECT  2.16 23.085 49.68 23.355 ;
     RECT  2.16 23.625 49.68 23.895 ;
     RECT  2.16 24.165 49.68 24.435 ;
     RECT  2.16 24.705 49.68 24.975 ;
     RECT  2.16 25.245 17.766 25.38 ;
     RECT  18.09 25.245 49.68 25.38 ;
     RECT  2.16 25.38 49.68 25.515 ;
     RECT  2.16 25.785 49.68 26.055 ;
     RECT  2.16 26.325 49.68 26.595 ;
     RECT  2.16 26.865 49.68 27.135 ;
     RECT  2.16 27.405 49.68 27.675 ;
     RECT  2.16 27.945 49.68 28.215 ;
     RECT  2.16 28.485 49.68 28.755 ;
     RECT  2.16 29.025 49.68 29.295 ;
     RECT  2.16 29.565 49.68 29.7 ;
     RECT  2.16 29.7 30.024 29.835 ;
     RECT  30.348 29.7 49.68 29.835 ;
     RECT  2.16 30.105 49.68 30.24 ;
     RECT  2.16 30.24 22.572 30.375 ;
     RECT  22.896 30.24 49.68 30.375 ;
     RECT  2.16 30.645 49.68 30.915 ;
     RECT  2.16 31.185 8.1 31.32 ;
     RECT  8.532 31.185 49.68 31.32 ;
     RECT  2.16 31.32 49.68 31.455 ;
     RECT  2.16 31.725 49.68 31.995 ;
     RECT  2.16 32.265 49.68 32.535 ;
     RECT  2.16 32.805 14.04 32.94 ;
     RECT  14.364 32.805 49.68 32.94 ;
     RECT  2.16 32.94 49.68 33.075 ;
     RECT  2.16 33.345 49.68 33.615 ;
     RECT  2.16 33.885 49.68 34.155 ;
     RECT  2.16 34.425 49.68 34.695 ;
     RECT  2.16 34.965 49.68 35.235 ;
     RECT  2.16 35.505 49.68 35.775 ;
     RECT  2.16 36.045 49.68 36.315 ;
     RECT  2.16 36.585 49.68 36.855 ;
     RECT  2.16 37.125 49.68 37.395 ;
     RECT  2.16 37.665 49.68 37.935 ;
     RECT  2.16 38.205 11.718 38.34 ;
     RECT  12.096 38.205 24.3 38.34 ;
     RECT  24.84 38.205 49.68 38.34 ;
     RECT  2.16 38.34 49.68 38.475 ;
     RECT  2.16 38.745 49.68 39.015 ;
     RECT  2.16 39.285 49.68 39.555 ;
     RECT  2.16 39.825 49.68 40.095 ;
     RECT  2.16 40.365 49.68 40.635 ;
     RECT  2.16 40.905 31.482 41.04 ;
     RECT  31.806 40.905 49.68 41.04 ;
     RECT  2.16 41.04 49.68 41.175 ;
     RECT  2.16 41.445 49.68 41.715 ;
     RECT  2.16 41.985 49.68 42.255 ;
     RECT  2.16 42.525 49.68 42.795 ;
     RECT  2.16 43.065 20.034 43.2 ;
     RECT  20.358 43.065 49.68 43.2 ;
     RECT  2.16 43.2 49.68 43.335 ;
     RECT  2.16 43.605 49.68 43.74 ;
     RECT  2.16 43.74 10.908 43.875 ;
     RECT  11.232 43.74 22.626 43.875 ;
     RECT  22.95 43.74 49.68 43.875 ;
     RECT  2.16 44.145 49.68 44.415 ;
     RECT  2.16 44.685 49.68 44.955 ;
     RECT  2.16 45.225 49.68 45.36 ;
     RECT  2.16 45.36 31.59 45.495 ;
     RECT  31.914 45.36 49.68 45.495 ;
     RECT  2.16 45.765 49.68 46.035 ;
     RECT  2.16 46.305 49.68 46.575 ;
     RECT  2.16 46.845 49.68 47.115 ;
     RECT  2.16 47.385 49.68 47.655 ;
     RECT  2.16 47.925 49.68 48.195 ;
     RECT  2.16 48.465 24.03 48.6 ;
     RECT  24.354 48.465 49.68 48.6 ;
     RECT  2.16 48.6 49.68 48.735 ;
     RECT  2.16 49.005 49.68 49.275 ;
     RECT  2.16 49.545 49.68 49.815 ;
     RECT  2.16 50.085 49.68 50.355 ;
     RECT  2.16 50.625 49.68 50.895 ;
     RECT  2.16 51.165 49.68 51.435 ;
     RECT  2.16 51.705 49.68 51.975 ;
     RECT  2.16 52.245 49.68 52.515 ;
     RECT  2.16 52.785 49.68 53.055 ;
     RECT  2.16 53.325 21.006 53.46 ;
     RECT  21.438 53.325 49.68 53.46 ;
     RECT  2.16 53.46 49.68 53.595 ;
     RECT  2.16 53.865 49.68 54.135 ;
     RECT  2.16 54.405 49.68 54.675 ;
     RECT  2.16 54.945 49.68 55.215 ;
     RECT  2.16 55.485 8.37 55.62 ;
     RECT  8.694 55.485 49.68 55.62 ;
     RECT  2.16 55.62 49.68 55.755 ;
     RECT  2.16 56.025 49.68 56.295 ;
     RECT  2.16 56.565 49.68 56.835 ;
     RECT  2.16 57.105 49.68 57.375 ;
     RECT  2.16 57.645 49.68 57.78 ;
     RECT  2.16 57.78 32.562 57.915 ;
     RECT  32.886 57.78 49.68 57.915 ;
     RECT  2.16 58.185 49.68 58.455 ;
     RECT  2.16 58.725 49.68 58.995 ;
     RECT  2.16 59.265 49.68 59.535 ;
     RECT  2.16 59.805 49.68 60.075 ;
     RECT  2.16 60.345 49.68 60.615 ;
     RECT  2.16 60.885 49.68 61.155 ;
     RECT  2.16 61.425 49.68 61.56 ;
     RECT  2.16 61.56 14.58 61.695 ;
     RECT  14.958 61.56 49.68 61.695 ;
     RECT  2.16 61.965 49.68 62.235 ;
     RECT  2.16 62.505 49.68 62.775 ;
     RECT  2.16 63.045 49.68 63.18 ;
     RECT  2.16 63.18 8.532 63.315 ;
     RECT  9.18 63.18 22.356 63.315 ;
     RECT  22.68 63.18 49.68 63.315 ;
     RECT  2.16 63.585 49.68 63.855 ;
     RECT  2.16 64.125 49.68 64.26 ;
     RECT  2.16 64.26 31.212 64.395 ;
     RECT  31.536 64.26 49.68 64.395 ;
     RECT  2.16 64.665 49.68 64.8 ;
     RECT  2.16 64.8 10.53 64.935 ;
     RECT  10.854 64.8 49.68 64.935 ;
     RECT  2.16 65.205 8.586 65.34 ;
     RECT  8.91 65.205 13.5 65.34 ;
     RECT  13.824 65.205 49.68 65.34 ;
     RECT  2.16 65.34 49.68 65.475 ;
     RECT  2.16 65.745 19.818 65.88 ;
     RECT  20.142 65.745 49.68 65.88 ;
     RECT  2.16 65.88 8.856 66.015 ;
     RECT  9.18 65.88 49.68 66.015 ;
     RECT  2.16 66.285 20.628 66.42 ;
     RECT  20.952 66.285 49.68 66.42 ;
     RECT  2.16 66.42 11.556 66.555 ;
     RECT  11.88 66.42 49.68 66.555 ;
     RECT  2.16 66.825 49.68 66.96 ;
     RECT  2.16 66.96 9.072 67.095 ;
     RECT  9.396 66.96 49.68 67.095 ;
     RECT  2.16 67.365 49.68 67.635 ;
     RECT  2.16 67.905 49.68 68.175 ;
     RECT  2.16 68.445 49.68 68.715 ;
     RECT  2.16 68.985 8.64 69.12 ;
     RECT  8.964 68.985 49.68 69.12 ;
     RECT  2.16 69.12 49.68 69.255 ;
     RECT  2.16 69.525 11.232 69.66 ;
     RECT  11.556 69.525 49.68 69.66 ;
     RECT  2.16 69.66 49.68 69.795 ;
     RECT  2.16 70.065 7.29 70.2 ;
     RECT  7.722 70.065 49.68 70.2 ;
     RECT  2.16 70.2 49.68 70.335 ;
     RECT  2.16 70.605 7.236 70.74 ;
     RECT  7.56 70.605 49.68 70.74 ;
     RECT  2.16 70.74 49.68 70.875 ;
     RECT  2.16 71.145 49.68 71.28 ;
     RECT  2.16 71.28 8.478 71.415 ;
     RECT  8.802 71.28 49.68 71.415 ;
     RECT  2.16 71.685 49.68 71.955 ;
     RECT  2.16 72.225 5.184 72.36 ;
     RECT  5.508 72.225 5.724 72.36 ;
     RECT  6.048 72.225 6.372 72.36 ;
     RECT  6.804 72.225 49.68 72.36 ;
     RECT  2.16 72.36 6.048 72.495 ;
     RECT  6.696 72.36 21.816 72.495 ;
     RECT  22.248 72.36 49.68 72.495 ;
     RECT  2.16 72.765 29.97 72.9 ;
     RECT  30.294 72.765 49.68 72.9 ;
     RECT  2.16 72.9 49.68 73.035 ;
     RECT  2.16 73.305 49.68 73.575 ;
     RECT  2.16 73.845 30.942 73.98 ;
     RECT  31.266 73.845 32.994 73.98 ;
     RECT  33.318 73.845 33.642 73.98 ;
     RECT  33.966 73.845 49.68 73.98 ;
     RECT  2.16 73.98 5.022 74.115 ;
     RECT  5.346 73.98 6.048 74.115 ;
     RECT  6.372 73.98 31.428 74.115 ;
     RECT  31.752 73.98 49.68 74.115 ;
     RECT  2.16 74.385 49.68 74.655 ;
     RECT  2.16 74.925 49.68 75.195 ;
     RECT  2.16 75.465 49.68 75.6 ;
     RECT  2.16 75.6 17.658 75.735 ;
     RECT  18.036 75.6 49.68 75.735 ;
     RECT  2.16 76.005 33.696 76.14 ;
     RECT  34.344 76.005 49.68 76.14 ;
     RECT  2.16 76.14 31.374 76.275 ;
     RECT  31.698 76.14 32.076 76.275 ;
     RECT  32.4 76.14 49.68 76.275 ;
     RECT  2.16 76.545 30.078 76.68 ;
     RECT  31.05 76.545 32.778 76.68 ;
     RECT  33.102 76.545 33.264 76.68 ;
     RECT  33.588 76.545 33.696 76.68 ;
     RECT  34.02 76.545 49.68 76.68 ;
     RECT  2.16 76.68 29.7 76.815 ;
     RECT  30.024 76.68 32.346 76.815 ;
     RECT  32.67 76.68 32.886 76.815 ;
     RECT  33.21 76.68 33.534 76.815 ;
     RECT  33.858 76.68 49.68 76.815 ;
     RECT  2.16 77.085 49.68 77.355 ;
     RECT  2.16 77.625 49.68 77.895 ;
     RECT  2.16 78.165 23.598 78.3 ;
     RECT  23.922 78.165 49.68 78.3 ;
     RECT  2.16 78.3 49.68 78.435 ;
     RECT  2.16 78.705 23.814 78.84 ;
     RECT  24.138 78.705 25.542 78.84 ;
     RECT  26.19 78.705 49.68 78.84 ;
     RECT  2.16 78.84 49.68 78.975 ;
     RECT  2.16 79.245 49.68 79.515 ;
     RECT  2.16 79.785 49.68 79.92 ;
    LAYER RVTP ;
     RECT  2.16 2.295 49.68 2.565 ;
     RECT  2.16 2.835 49.68 3.105 ;
     RECT  2.16 3.375 49.68 3.51 ;
     RECT  2.16 3.51 9.99 3.645 ;
     RECT  10.314 3.51 49.68 3.645 ;
     RECT  2.16 3.915 49.68 4.05 ;
     RECT  2.16 4.05 13.554 4.185 ;
     RECT  14.094 4.05 14.202 4.185 ;
     RECT  14.364 4.05 49.68 4.185 ;
     RECT  2.16 4.455 49.68 4.725 ;
     RECT  2.16 4.995 12.852 5.13 ;
     RECT  13.392 4.995 49.68 5.13 ;
     RECT  2.16 5.13 49.68 5.265 ;
     RECT  2.16 5.535 49.68 5.67 ;
     RECT  2.16 5.67 13.5 5.805 ;
     RECT  13.932 5.67 49.68 5.805 ;
     RECT  2.16 6.075 49.68 6.345 ;
     RECT  2.16 6.615 13.5 6.75 ;
     RECT  13.662 6.615 49.68 6.75 ;
     RECT  2.16 6.75 49.68 6.885 ;
     RECT  2.16 7.155 13.662 7.29 ;
     RECT  14.202 7.155 49.68 7.29 ;
     RECT  2.16 7.29 49.68 7.425 ;
     RECT  2.16 7.695 49.68 7.83 ;
     RECT  2.16 7.83 13.824 7.965 ;
     RECT  14.256 7.83 49.68 7.965 ;
     RECT  2.16 8.235 49.68 8.505 ;
     RECT  2.16 8.775 49.68 8.91 ;
     RECT  2.16 8.91 14.85 9.045 ;
     RECT  15.39 8.91 49.68 9.045 ;
     RECT  2.16 9.315 49.68 9.585 ;
     RECT  2.16 9.855 49.68 10.125 ;
     RECT  2.16 10.395 49.68 10.665 ;
     RECT  2.16 10.935 11.124 11.07 ;
     RECT  11.448 10.935 49.68 11.07 ;
     RECT  2.16 11.07 49.68 11.205 ;
     RECT  2.16 11.475 49.68 11.61 ;
     RECT  2.16 11.61 39.744 11.745 ;
     RECT  40.068 11.61 49.68 11.745 ;
     RECT  2.16 12.015 49.68 12.285 ;
     RECT  2.16 12.555 49.68 12.825 ;
     RECT  2.16 13.095 49.68 13.365 ;
     RECT  2.16 13.635 49.68 13.905 ;
     RECT  2.16 14.175 49.68 14.445 ;
     RECT  2.16 14.715 49.68 14.985 ;
     RECT  2.16 15.255 49.68 15.525 ;
     RECT  2.16 15.795 49.68 16.065 ;
     RECT  2.16 16.335 49.68 16.605 ;
     RECT  2.16 16.875 49.68 17.145 ;
     RECT  2.16 17.415 49.68 17.685 ;
     RECT  2.16 17.955 19.278 18.09 ;
     RECT  19.818 17.955 49.68 18.09 ;
     RECT  2.16 18.09 49.68 18.225 ;
     RECT  2.16 18.495 49.68 18.765 ;
     RECT  2.16 19.035 49.68 19.17 ;
     RECT  2.16 19.17 22.464 19.305 ;
     RECT  22.788 19.17 49.68 19.305 ;
     RECT  2.16 19.575 49.68 19.845 ;
     RECT  2.16 20.115 49.68 20.385 ;
     RECT  2.16 20.655 49.68 20.925 ;
     RECT  2.16 21.195 10.098 21.33 ;
     RECT  10.422 21.195 49.68 21.33 ;
     RECT  2.16 21.33 14.31 21.465 ;
     RECT  14.742 21.33 49.68 21.465 ;
     RECT  2.16 21.735 41.418 21.87 ;
     RECT  41.85 21.735 49.68 21.87 ;
     RECT  2.16 21.87 8.316 22.005 ;
     RECT  8.748 21.87 49.68 22.005 ;
     RECT  2.16 22.275 49.68 22.545 ;
     RECT  2.16 22.815 49.68 23.085 ;
     RECT  2.16 23.355 49.68 23.625 ;
     RECT  2.16 23.895 49.68 24.165 ;
     RECT  2.16 24.435 49.68 24.705 ;
     RECT  2.16 24.975 49.68 25.11 ;
     RECT  2.16 25.11 17.766 25.245 ;
     RECT  18.09 25.11 49.68 25.245 ;
     RECT  2.16 25.515 49.68 25.785 ;
     RECT  2.16 26.055 49.68 26.325 ;
     RECT  2.16 26.595 49.68 26.865 ;
     RECT  2.16 27.135 49.68 27.405 ;
     RECT  2.16 27.675 49.68 27.945 ;
     RECT  2.16 28.215 49.68 28.485 ;
     RECT  2.16 28.755 49.68 29.025 ;
     RECT  2.16 29.295 49.68 29.565 ;
     RECT  2.16 29.835 30.024 29.97 ;
     RECT  30.348 29.835 49.68 29.97 ;
     RECT  2.16 29.97 49.68 30.105 ;
     RECT  2.16 30.375 22.572 30.51 ;
     RECT  22.896 30.375 49.68 30.51 ;
     RECT  2.16 30.51 49.68 30.645 ;
     RECT  2.16 30.915 49.68 31.05 ;
     RECT  2.16 31.05 8.1 31.185 ;
     RECT  8.532 31.05 49.68 31.185 ;
     RECT  2.16 31.455 49.68 31.725 ;
     RECT  2.16 31.995 49.68 32.265 ;
     RECT  2.16 32.535 49.68 32.67 ;
     RECT  2.16 32.67 14.04 32.805 ;
     RECT  14.364 32.67 49.68 32.805 ;
     RECT  2.16 33.075 49.68 33.345 ;
     RECT  2.16 33.615 49.68 33.885 ;
     RECT  2.16 34.155 49.68 34.425 ;
     RECT  2.16 34.695 49.68 34.965 ;
     RECT  2.16 35.235 49.68 35.505 ;
     RECT  2.16 35.775 49.68 36.045 ;
     RECT  2.16 36.315 49.68 36.585 ;
     RECT  2.16 36.855 49.68 37.125 ;
     RECT  2.16 37.395 49.68 37.665 ;
     RECT  2.16 37.935 49.68 38.07 ;
     RECT  2.16 38.07 11.718 38.205 ;
     RECT  12.096 38.07 24.3 38.205 ;
     RECT  24.84 38.07 49.68 38.205 ;
     RECT  2.16 38.475 49.68 38.745 ;
     RECT  2.16 39.015 49.68 39.285 ;
     RECT  2.16 39.555 49.68 39.825 ;
     RECT  2.16 40.095 49.68 40.365 ;
     RECT  2.16 40.635 49.68 40.77 ;
     RECT  2.16 40.77 31.482 40.905 ;
     RECT  31.806 40.77 49.68 40.905 ;
     RECT  2.16 41.175 49.68 41.445 ;
     RECT  2.16 41.715 49.68 41.985 ;
     RECT  2.16 42.255 49.68 42.525 ;
     RECT  2.16 42.795 49.68 42.93 ;
     RECT  2.16 42.93 20.034 43.065 ;
     RECT  20.358 42.93 49.68 43.065 ;
     RECT  2.16 43.335 49.68 43.605 ;
     RECT  2.16 43.875 10.908 44.01 ;
     RECT  11.232 43.875 22.626 44.01 ;
     RECT  22.95 43.875 49.68 44.01 ;
     RECT  2.16 44.01 49.68 44.145 ;
     RECT  2.16 44.415 49.68 44.685 ;
     RECT  2.16 44.955 49.68 45.225 ;
     RECT  2.16 45.495 31.59 45.63 ;
     RECT  31.914 45.495 49.68 45.63 ;
     RECT  2.16 45.63 49.68 45.765 ;
     RECT  2.16 46.035 49.68 46.305 ;
     RECT  2.16 46.575 49.68 46.845 ;
     RECT  2.16 47.115 49.68 47.385 ;
     RECT  2.16 47.655 49.68 47.925 ;
     RECT  2.16 48.195 49.68 48.33 ;
     RECT  2.16 48.33 24.03 48.465 ;
     RECT  24.354 48.33 49.68 48.465 ;
     RECT  2.16 48.735 49.68 49.005 ;
     RECT  2.16 49.275 49.68 49.545 ;
     RECT  2.16 49.815 49.68 50.085 ;
     RECT  2.16 50.355 49.68 50.625 ;
     RECT  2.16 50.895 49.68 51.165 ;
     RECT  2.16 51.435 49.68 51.705 ;
     RECT  2.16 51.975 49.68 52.245 ;
     RECT  2.16 52.515 49.68 52.785 ;
     RECT  2.16 53.055 49.68 53.19 ;
     RECT  2.16 53.19 21.006 53.325 ;
     RECT  21.438 53.19 49.68 53.325 ;
     RECT  2.16 53.595 49.68 53.865 ;
     RECT  2.16 54.135 49.68 54.405 ;
     RECT  2.16 54.675 49.68 54.945 ;
     RECT  2.16 55.215 49.68 55.35 ;
     RECT  2.16 55.35 8.37 55.485 ;
     RECT  8.694 55.35 49.68 55.485 ;
     RECT  2.16 55.755 49.68 56.025 ;
     RECT  2.16 56.295 49.68 56.565 ;
     RECT  2.16 56.835 49.68 57.105 ;
     RECT  2.16 57.375 49.68 57.645 ;
     RECT  2.16 57.915 32.562 58.05 ;
     RECT  32.886 57.915 49.68 58.05 ;
     RECT  2.16 58.05 49.68 58.185 ;
     RECT  2.16 58.455 49.68 58.725 ;
     RECT  2.16 58.995 49.68 59.265 ;
     RECT  2.16 59.535 49.68 59.805 ;
     RECT  2.16 60.075 49.68 60.345 ;
     RECT  2.16 60.615 49.68 60.885 ;
     RECT  2.16 61.155 49.68 61.425 ;
     RECT  2.16 61.695 14.58 61.83 ;
     RECT  14.958 61.695 49.68 61.83 ;
     RECT  2.16 61.83 49.68 61.965 ;
     RECT  2.16 62.235 49.68 62.505 ;
     RECT  2.16 62.775 49.68 63.045 ;
     RECT  2.16 63.315 8.532 63.45 ;
     RECT  9.18 63.315 22.356 63.45 ;
     RECT  22.68 63.315 49.68 63.45 ;
     RECT  2.16 63.45 49.68 63.585 ;
     RECT  2.16 63.855 49.68 64.125 ;
     RECT  2.16 64.395 31.212 64.53 ;
     RECT  31.536 64.395 49.68 64.53 ;
     RECT  2.16 64.53 49.68 64.665 ;
     RECT  2.16 64.935 10.53 65.07 ;
     RECT  10.854 64.935 49.68 65.07 ;
     RECT  2.16 65.07 8.586 65.205 ;
     RECT  8.91 65.07 13.5 65.205 ;
     RECT  13.824 65.07 49.68 65.205 ;
     RECT  2.16 65.475 49.68 65.61 ;
     RECT  2.16 65.61 19.818 65.745 ;
     RECT  20.142 65.61 49.68 65.745 ;
     RECT  2.16 66.015 8.856 66.15 ;
     RECT  9.18 66.015 49.68 66.15 ;
     RECT  2.16 66.15 20.628 66.285 ;
     RECT  20.952 66.15 49.68 66.285 ;
     RECT  2.16 66.555 11.556 66.69 ;
     RECT  11.88 66.555 49.68 66.69 ;
     RECT  2.16 66.69 49.68 66.825 ;
     RECT  2.16 67.095 9.072 67.23 ;
     RECT  9.396 67.095 49.68 67.23 ;
     RECT  2.16 67.23 49.68 67.365 ;
     RECT  2.16 67.635 49.68 67.905 ;
     RECT  2.16 68.175 49.68 68.445 ;
     RECT  2.16 68.715 49.68 68.85 ;
     RECT  2.16 68.85 8.64 68.985 ;
     RECT  8.964 68.85 49.68 68.985 ;
     RECT  2.16 69.255 49.68 69.39 ;
     RECT  2.16 69.39 11.232 69.525 ;
     RECT  11.556 69.39 49.68 69.525 ;
     RECT  2.16 69.795 49.68 69.93 ;
     RECT  2.16 69.93 7.29 70.065 ;
     RECT  7.722 69.93 49.68 70.065 ;
     RECT  2.16 70.335 49.68 70.47 ;
     RECT  2.16 70.47 7.236 70.605 ;
     RECT  7.56 70.47 49.68 70.605 ;
     RECT  2.16 70.875 49.68 71.145 ;
     RECT  2.16 71.415 8.478 71.55 ;
     RECT  8.802 71.415 49.68 71.55 ;
     RECT  2.16 71.55 49.68 71.685 ;
     RECT  2.16 71.955 49.68 72.09 ;
     RECT  2.16 72.09 5.184 72.225 ;
     RECT  5.508 72.09 5.724 72.225 ;
     RECT  6.048 72.09 6.372 72.225 ;
     RECT  6.804 72.09 49.68 72.225 ;
     RECT  2.16 72.495 6.048 72.63 ;
     RECT  6.696 72.495 21.816 72.63 ;
     RECT  22.248 72.495 49.68 72.63 ;
     RECT  2.16 72.63 29.97 72.765 ;
     RECT  30.294 72.63 49.68 72.765 ;
     RECT  2.16 73.035 49.68 73.305 ;
     RECT  2.16 73.575 49.68 73.71 ;
     RECT  2.16 73.71 30.942 73.845 ;
     RECT  31.266 73.71 32.994 73.845 ;
     RECT  33.318 73.71 33.642 73.845 ;
     RECT  33.966 73.71 49.68 73.845 ;
     RECT  2.16 74.115 5.022 74.25 ;
     RECT  5.346 74.115 6.048 74.25 ;
     RECT  6.372 74.115 31.428 74.25 ;
     RECT  31.752 74.115 49.68 74.25 ;
     RECT  2.16 74.25 49.68 74.385 ;
     RECT  2.16 74.655 49.68 74.925 ;
     RECT  2.16 75.195 49.68 75.465 ;
     RECT  2.16 75.735 17.658 75.87 ;
     RECT  18.036 75.735 49.68 75.87 ;
     RECT  2.16 75.87 33.696 76.005 ;
     RECT  34.344 75.87 49.68 76.005 ;
     RECT  2.16 76.275 31.374 76.41 ;
     RECT  31.698 76.275 32.076 76.41 ;
     RECT  32.4 76.275 49.68 76.41 ;
     RECT  2.16 76.41 30.078 76.545 ;
     RECT  31.05 76.41 32.778 76.545 ;
     RECT  33.102 76.41 33.264 76.545 ;
     RECT  33.588 76.41 33.696 76.545 ;
     RECT  34.02 76.41 49.68 76.545 ;
     RECT  2.16 76.815 29.7 76.95 ;
     RECT  30.024 76.815 32.346 76.95 ;
     RECT  32.67 76.815 32.886 76.95 ;
     RECT  33.21 76.815 33.534 76.95 ;
     RECT  33.858 76.815 49.68 76.95 ;
     RECT  2.16 76.95 49.68 77.085 ;
     RECT  2.16 77.355 49.68 77.625 ;
     RECT  2.16 77.895 49.68 78.03 ;
     RECT  2.16 78.03 23.598 78.165 ;
     RECT  23.922 78.03 49.68 78.165 ;
     RECT  2.16 78.435 49.68 78.57 ;
     RECT  2.16 78.57 23.814 78.705 ;
     RECT  24.138 78.57 25.542 78.705 ;
     RECT  26.19 78.57 49.68 78.705 ;
     RECT  2.16 78.975 49.68 79.245 ;
     RECT  2.16 79.515 49.68 79.785 ;
    LAYER M1 ;
     RECT  2.16 2.151 49.68 79.929 ;
    LAYER M2 ;
     RECT  0.031 60.12 0.067 60.138 ;
     RECT  0.031 14.724 0.103 14.742 ;
     RECT  0.067 33.696 0.103 33.714 ;
     RECT  0.031 40.068 0.103 40.086 ;
     RECT  0.031 57.078 0.103 57.168 ;
     RECT  0.067 58.896 0.131 60.138 ;
     RECT  0.031 65.214 0.131 65.232 ;
     RECT  0.103 4.581 0.139 4.599 ;
     RECT  0.103 12.906 0.139 13.014 ;
     RECT  0.103 16.848 0.139 16.866 ;
     RECT  0.103 17.694 0.139 18.252 ;
     RECT  0.103 23.976 0.139 23.994 ;
     RECT  0.067 52.911 0.139 52.929 ;
     RECT  0.067 63.486 0.167 63.504 ;
     RECT  0.139 4.581 0.175 5.526 ;
     RECT  0.139 16.848 0.175 18.639 ;
     RECT  0.139 23.976 0.175 24.228 ;
     RECT  0.031 29.916 0.175 29.934 ;
     RECT  0.103 51.246 0.175 51.264 ;
     RECT  0.175 3.924 0.211 5.526 ;
     RECT  0.139 12.87 0.211 13.014 ;
     RECT  0.103 14.724 0.211 14.904 ;
     RECT  0.175 16.848 0.211 18.684 ;
     RECT  0.103 19.818 0.211 19.836 ;
     RECT  0.175 23.976 0.211 25.074 ;
     RECT  0.175 38.718 0.211 38.736 ;
     RECT  0.211 16.308 0.247 18.684 ;
     RECT  0.103 36.252 0.247 36.27 ;
     RECT  0.103 37.368 0.247 37.386 ;
     RECT  0.211 38.52 0.247 38.736 ;
     RECT  0.139 52.911 0.247 53.046 ;
     RECT  0.103 54.756 0.247 54.774 ;
     RECT  0.103 62.136 0.275 62.154 ;
     RECT  0.175 63.864 0.275 63.882 ;
     RECT  0.247 16.146 0.283 18.684 ;
     RECT  0.139 22.518 0.283 22.536 ;
     RECT  0.247 52.596 0.283 53.28 ;
     RECT  0.103 49.284 0.319 49.302 ;
     RECT  0.175 50.67 0.319 51.264 ;
     RECT  0.283 52.56 0.319 53.352 ;
     RECT  0.247 61.128 0.347 61.146 ;
     RECT  0.319 50.67 0.355 53.388 ;
     RECT  0.211 23.634 0.383 25.074 ;
     RECT  0.131 58.896 0.391 59.832 ;
     RECT  0.103 68.256 0.391 68.274 ;
     RECT  0.211 70.92 0.391 70.938 ;
     RECT  0.319 49.014 0.419 49.302 ;
     RECT  0.355 50.67 0.419 53.658 ;
     RECT  0.139 27.414 0.427 27.432 ;
     RECT  0.103 32.31 0.427 33.714 ;
     RECT  0.103 67.176 0.427 67.194 ;
     RECT  0.391 68.256 0.427 68.742 ;
     RECT  0.211 14.526 0.455 14.904 ;
     RECT  0.103 57.006 0.455 57.168 ;
     RECT  0.427 27.414 0.463 27.936 ;
     RECT  0.139 34.632 0.463 34.65 ;
     RECT  0.391 58.536 0.463 59.832 ;
     RECT  0.427 69.876 0.463 69.894 ;
     RECT  0.103 74.736 0.463 74.754 ;
     RECT  0.391 64.944 0.491 64.962 ;
     RECT  0.463 34.632 0.499 34.758 ;
     RECT  0.247 36.252 0.499 37.386 ;
     RECT  0.103 41.346 0.499 41.364 ;
     RECT  0.463 58.23 0.499 59.832 ;
     RECT  0.427 65.754 0.499 65.772 ;
     RECT  0.031 72.27 0.499 72.288 ;
     RECT  0.031 75.861 0.499 75.879 ;
     RECT  0.499 65.754 0.527 65.844 ;
     RECT  0.211 12.87 0.535 13.356 ;
     RECT  0.067 26.262 0.535 26.28 ;
     RECT  0.463 27.342 0.535 27.936 ;
     RECT  0.427 32.238 0.535 33.714 ;
     RECT  0.499 34.47 0.535 34.758 ;
     RECT  0.499 36.252 0.535 37.458 ;
     RECT  0.247 38.412 0.535 38.736 ;
     RECT  0.103 40.068 0.535 40.428 ;
     RECT  0.103 42.732 0.535 42.75 ;
     RECT  0.103 43.812 0.535 43.83 ;
     RECT  0.103 44.73 0.535 44.748 ;
     RECT  0.319 46.386 0.535 46.404 ;
     RECT  0.455 57.114 0.535 57.168 ;
     RECT  0.499 57.996 0.535 59.832 ;
     RECT  0.391 64.17 0.535 64.188 ;
     RECT  0.427 66.87 0.535 67.194 ;
     RECT  0.427 68.256 0.535 68.976 ;
     RECT  0.391 70.65 0.535 70.938 ;
     RECT  0.499 71.766 0.535 72.288 ;
     RECT  0.499 75.78 0.535 75.96 ;
     RECT  0.499 76.788 0.535 77.382 ;
     RECT  0.499 78.984 0.535 79.002 ;
     RECT  0.455 14.526 0.571 14.544 ;
     RECT  0.283 16.146 0.571 18.864 ;
     RECT  0.211 19.818 0.571 20.448 ;
     RECT  0.535 75.78 0.635 77.382 ;
     RECT  0.535 66.87 0.823 68.976 ;
     RECT  0.571 10.836 0.859 10.854 ;
     RECT  0.499 63.09 0.859 63.108 ;
     RECT  0.535 57.114 0.895 59.832 ;
     RECT  0.419 50.67 0.931 51.804 ;
     RECT  0.283 22.518 1.003 22.608 ;
     RECT  0.383 23.634 1.003 24.804 ;
     RECT  0.571 16.146 1.031 20.448 ;
     RECT  1.031 18 1.039 20.448 ;
     RECT  1.003 22.356 1.039 22.608 ;
     RECT  1.039 18 1.067 20.484 ;
     RECT  1.039 22.212 1.075 22.608 ;
     RECT  1.003 23.4 1.075 24.804 ;
     RECT  0.211 3.582 1.111 5.526 ;
     RECT  0.859 10.836 1.111 11.538 ;
     RECT  0.535 12.492 1.111 13.356 ;
     RECT  0.463 69.804 1.111 69.894 ;
     RECT  0.535 70.65 1.111 73.026 ;
     RECT  0.175 29.916 1.147 30.06 ;
     RECT  0.535 46.116 1.147 46.908 ;
     RECT  0.247 54.756 1.147 55.008 ;
     RECT  0.895 57.114 1.147 60.102 ;
     RECT  1.147 54.756 1.175 55.044 ;
     RECT  0.247 8.046 1.399 8.064 ;
     RECT  1.147 57.114 1.399 60.174 ;
     RECT  0.823 66.87 1.399 69.048 ;
     RECT  1.111 69.804 1.399 73.026 ;
     RECT  0.319 31.356 1.427 31.374 ;
     RECT  1.031 16.146 1.435 17.1 ;
     RECT  0.419 52.56 1.435 53.658 ;
     RECT  0.463 62.01 1.435 62.064 ;
     RECT  0.859 62.982 1.435 63.108 ;
     RECT  0.571 14.256 1.471 14.544 ;
     RECT  1.175 54.99 1.471 55.044 ;
     RECT  0.931 50.634 1.507 51.804 ;
     RECT  1.435 52.56 1.507 53.82 ;
     RECT  1.067 18.846 1.543 20.484 ;
     RECT  1.075 22.212 1.615 24.804 ;
     RECT  0.535 78.984 1.651 79.074 ;
     RECT  1.651 78.948 1.687 79.074 ;
     RECT  1.111 10.368 1.975 11.538 ;
     RECT  1.111 12.366 2.047 13.356 ;
     RECT  0.419 49.284 2.047 49.302 ;
     RECT  1.435 62.01 2.047 63.108 ;
     RECT  1.435 16.11 2.083 17.1 ;
     RECT  1.067 18 2.083 18.018 ;
     RECT  1.111 3.582 2.16 6.264 ;
     RECT  1.399 7.398 2.16 8.064 ;
     RECT  1.975 9.63 2.16 11.538 ;
     RECT  2.047 12.366 2.16 13.428 ;
     RECT  1.471 14.256 2.16 14.976 ;
     RECT  2.083 16.11 2.16 18.018 ;
     RECT  1.543 18.846 2.16 20.988 ;
     RECT  1.615 21.78 2.16 24.804 ;
     RECT  0.535 25.56 2.16 26.28 ;
     RECT  0.535 27.18 2.16 28.476 ;
     RECT  1.147 29.916 2.16 30.6 ;
     RECT  0.535 32.238 2.16 35.028 ;
     RECT  0.535 36.252 2.16 38.736 ;
     RECT  0.535 39.87 2.16 40.428 ;
     RECT  0.499 41.346 2.16 41.706 ;
     RECT  0.535 42.606 2.16 42.75 ;
     RECT  0.535 43.812 2.16 45.018 ;
     RECT  1.147 46.116 2.16 47.178 ;
     RECT  2.047 49.284 2.16 49.5 ;
     RECT  1.507 50.634 2.16 53.82 ;
     RECT  1.471 54.99 2.16 55.44 ;
     RECT  1.399 57.042 2.16 60.174 ;
     RECT  2.047 61.668 2.16 63.108 ;
     RECT  0.535 64.17 2.16 64.854 ;
     RECT  0.527 65.826 2.16 65.844 ;
     RECT  1.399 66.87 2.16 73.026 ;
     RECT  0.463 74.736 2.16 74.988 ;
     RECT  0.635 75.942 2.16 77.382 ;
     RECT  1.687 78.948 2.16 79.506 ;
     RECT  2.16 2.151 3.415 79.929 ;
     RECT  5.143 80.91 13.091 80.928 ;
     RECT  21.235 82.026 21.659 82.044 ;
     RECT  17.095 80.91 26.879 80.928 ;
     RECT  3.415 1.422 31.487 79.929 ;
     RECT  31.487 2.151 41.035 79.929 ;
     RECT  41.035 1.962 46.283 79.929 ;
     RECT  46.283 2.034 47.363 79.929 ;
     RECT  47.363 2.151 48.595 79.929 ;
     RECT  48.595 2.106 48.883 79.929 ;
     RECT  48.883 2.07 49.68 79.929 ;
     RECT  49.68 2.07 49.811 28.314 ;
     RECT  49.811 2.106 49.847 28.314 ;
     RECT  49.68 58.392 50.171 61.074 ;
     RECT  50.171 58.392 50.207 60.804 ;
     RECT  49.68 62.046 50.207 79.776 ;
     RECT  50.207 64.026 50.243 64.044 ;
     RECT  50.207 64.836 50.243 79.776 ;
     RECT  49.847 2.106 50.279 28.134 ;
     RECT  50.279 3.006 50.675 28.134 ;
     RECT  49.68 29.376 50.675 57.564 ;
     RECT  50.207 62.046 50.675 63.27 ;
     RECT  50.279 2.106 50.711 2.214 ;
     RECT  50.675 3.114 50.711 28.134 ;
     RECT  50.675 29.376 50.711 56.484 ;
     RECT  50.675 57.276 50.711 57.564 ;
     RECT  50.207 58.392 50.711 58.644 ;
     RECT  50.207 59.436 50.711 60.804 ;
     RECT  50.675 62.046 50.711 62.064 ;
     RECT  50.243 64.836 50.711 69.984 ;
     RECT  50.243 70.776 50.711 79.776 ;
     RECT  50.711 5.706 50.747 8.064 ;
     RECT  50.711 11.016 50.747 12.348 ;
     RECT  50.711 13.986 50.747 15.552 ;
     RECT  50.711 16.506 50.747 16.704 ;
     RECT  50.711 22.014 50.747 22.914 ;
     RECT  50.711 29.376 50.747 29.628 ;
     RECT  50.711 30.384 50.747 30.402 ;
     RECT  50.711 31.896 50.747 33.714 ;
     RECT  50.711 34.974 50.747 34.992 ;
     RECT  50.711 38.556 50.747 38.574 ;
     RECT  50.711 39.762 50.747 40.122 ;
     RECT  50.711 40.986 50.747 42.444 ;
     RECT  50.711 43.308 50.747 45.594 ;
     RECT  50.711 46.656 50.747 48.564 ;
     RECT  50.711 52.326 50.747 52.974 ;
     RECT  50.675 63.252 50.747 63.27 ;
     RECT  50.711 65.016 50.747 66.852 ;
     RECT  50.711 67.806 50.747 69.444 ;
     RECT  50.711 72.666 50.747 72.684 ;
     RECT  50.711 73.512 50.747 74.952 ;
     RECT  50.711 76.014 50.747 78.084 ;
     RECT  50.711 79.218 50.747 79.614 ;
     RECT  50.747 29.61 50.783 29.628 ;
     RECT  50.747 32.238 50.783 32.256 ;
     RECT  50.711 36.324 50.783 37.422 ;
     RECT  50.747 46.656 50.783 47.304 ;
     RECT  50.747 77.292 50.783 77.922 ;
     RECT  50.747 79.596 50.783 79.614 ;
     RECT  50.747 44.388 50.819 45.018 ;
     RECT  50.711 4.734 51.719 4.824 ;
     RECT  50.711 2.106 51.755 2.124 ;
     RECT  51.719 4.734 51.755 4.752 ;
     RECT  50.747 5.706 51.755 7.722 ;
     RECT  50.711 9.9 51.755 9.918 ;
     RECT  50.747 11.556 51.755 11.574 ;
     RECT  50.747 13.986 51.755 15.012 ;
     RECT  50.711 18.504 51.755 18.522 ;
     RECT  50.711 19.314 51.755 19.332 ;
     RECT  50.711 20.16 51.755 20.178 ;
     RECT  50.711 21.204 51.755 21.222 ;
     RECT  50.747 22.014 51.755 22.032 ;
     RECT  50.711 24.246 51.755 24.804 ;
     RECT  50.711 26.064 51.755 26.784 ;
     RECT  50.783 36.324 51.755 37.044 ;
     RECT  50.747 39.762 51.755 39.78 ;
     RECT  50.747 42.066 51.755 42.084 ;
     RECT  50.819 44.388 51.755 44.406 ;
     RECT  50.783 46.656 51.755 46.674 ;
     RECT  50.711 50.436 51.755 50.454 ;
     RECT  50.711 51.516 51.755 51.534 ;
     RECT  50.711 54.954 51.755 54.972 ;
     RECT  50.711 57.546 51.755 57.564 ;
     RECT  50.711 58.392 51.755 58.41 ;
     RECT  50.711 59.544 51.755 59.562 ;
     RECT  50.711 60.786 51.755 60.804 ;
     RECT  50.747 65.826 51.755 66.852 ;
     RECT  50.747 74.43 51.755 74.952 ;
     RECT  50.783 77.292 51.755 77.31 ;
    LAYER M3 ;
     RECT  50.148 0.715 50.166 0.859 ;
     RECT  3.42 0.859 3.438 1.003 ;
     RECT  49.968 0.859 50.166 1.003 ;
     RECT  21.636 0.091 21.654 1.051 ;
     RECT  49.968 1.003 50.202 1.147 ;
     RECT  2.988 1.003 3.438 1.291 ;
     RECT  29.016 0.715 29.034 1.435 ;
     RECT  2.988 1.291 3.474 1.579 ;
     RECT  49.968 1.147 50.238 1.579 ;
     RECT  21.204 1.051 21.654 1.723 ;
     RECT  28.872 1.435 29.034 1.867 ;
     RECT  49.968 1.579 50.274 1.867 ;
     RECT  45.54 1.723 45.558 1.957 ;
     RECT  31.464 1.417 31.482 1.993 ;
     RECT  49.968 1.867 50.706 2.011 ;
     RECT  41.04 1.957 41.058 2.029 ;
     RECT  49.572 2.011 50.706 2.065 ;
     RECT  45.54 1.957 46.278 2.101 ;
     RECT  48.888 2.065 50.706 2.101 ;
     RECT  51.732 1.435 51.75 2.129 ;
     RECT  15.84 0.811 15.858 2.143 ;
     RECT  28.188 1.867 29.034 2.143 ;
     RECT  31.284 1.993 31.482 2.143 ;
     RECT  42.732 2.101 42.75 2.143 ;
     RECT  48.6 2.101 50.706 2.143 ;
     RECT  24.015 2.143 24.105 2.191 ;
     RECT  48.315 2.143 50.706 2.219 ;
     RECT  47.34 2.029 47.358 2.227 ;
     RECT  48.315 2.219 50.67 2.227 ;
     RECT  45.18 2.101 46.278 2.251 ;
     RECT  15.84 2.143 16.005 2.263 ;
     RECT  23.328 2.191 24.105 2.263 ;
     RECT  40.215 2.143 40.305 2.263 ;
     RECT  28.188 2.143 29.505 2.293 ;
     RECT  5.115 2.143 5.205 2.299 ;
     RECT  21.132 1.723 21.654 2.299 ;
     RECT  25.092 2.293 25.11 2.299 ;
     RECT  26.715 2.143 26.805 2.299 ;
     RECT  28.188 2.293 29.538 2.299 ;
     RECT  30.384 2.011 30.402 2.299 ;
     RECT  41.04 2.029 41.31 2.299 ;
     RECT  45 2.251 46.278 2.299 ;
     RECT  28.188 2.299 30.402 2.335 ;
     RECT  31.284 2.143 32.205 2.335 ;
     RECT  39.636 2.263 40.305 2.335 ;
     RECT  41.04 2.299 41.526 2.335 ;
     RECT  2.304 1.579 3.474 2.371 ;
     RECT  14.472 1.723 14.49 2.371 ;
     RECT  15.552 2.263 16.29 2.371 ;
     RECT  21.096 2.299 21.654 2.371 ;
     RECT  26.28 2.299 26.805 2.371 ;
     RECT  28.188 2.335 32.205 2.371 ;
     RECT  44.604 2.299 46.278 2.371 ;
     RECT  47.268 2.227 50.67 2.371 ;
     RECT  7.815 2.143 7.905 2.413 ;
     RECT  10.515 2.143 10.605 2.413 ;
     RECT  13.215 2.143 13.305 2.413 ;
     RECT  18.615 2.143 18.705 2.413 ;
     RECT  19.476 1.099 19.494 2.413 ;
     RECT  23.04 2.263 24.105 2.413 ;
     RECT  25.992 2.371 26.805 2.413 ;
     RECT  28.008 2.371 32.205 2.413 ;
     RECT  33.084 2.371 33.174 2.413 ;
     RECT  34.815 2.143 34.905 2.413 ;
     RECT  37.515 2.143 37.605 2.413 ;
     RECT  42.732 2.143 43.005 2.413 ;
     RECT  14.472 2.371 16.29 2.461 ;
     RECT  18.615 2.413 19.494 2.461 ;
     RECT  28.008 2.413 33.174 2.461 ;
     RECT  39.636 2.335 41.526 2.461 ;
     RECT  42.732 2.413 43.197 2.461 ;
     RECT  44.604 2.371 50.67 2.461 ;
     RECT  2.304 2.371 3.546 2.489 ;
     RECT  39.384 2.461 41.526 2.491 ;
     RECT  42.732 2.461 50.67 2.491 ;
     RECT  13.215 2.413 13.497 2.497 ;
     RECT  14.472 2.461 16.758 2.497 ;
     RECT  25.092 2.299 25.182 2.497 ;
     RECT  25.992 2.413 26.997 2.497 ;
     RECT  37.515 2.413 37.797 2.497 ;
     RECT  10.515 2.413 10.797 2.539 ;
     RECT  13.215 2.497 16.758 2.569 ;
     RECT  37.044 2.497 37.797 2.569 ;
     RECT  0.144 2.155 0.162 2.573 ;
     RECT  17.748 1.147 17.766 2.587 ;
     RECT  18.54 2.461 19.494 2.587 ;
     RECT  20.844 2.371 21.654 2.587 ;
     RECT  23.04 2.413 24.297 2.587 ;
     RECT  5.115 2.299 5.742 2.632 ;
     RECT  25.092 2.497 26.997 2.641 ;
     RECT  34.815 2.413 35.097 2.641 ;
     RECT  35.928 2.569 35.946 2.641 ;
     RECT  37.044 2.569 38.358 2.641 ;
     RECT  39.384 2.491 50.67 2.641 ;
     RECT  7.815 2.413 8.097 2.731 ;
     RECT  10.515 2.539 10.854 2.731 ;
     RECT  13.14 2.569 16.758 2.731 ;
     RECT  17.748 2.587 19.782 2.731 ;
     RECT  20.7 2.587 21.726 2.731 ;
     RECT  25.02 2.641 26.997 2.731 ;
     RECT  27.828 2.461 33.174 2.731 ;
     RECT  7.776 2.731 8.097 2.767 ;
     RECT  8.82 2.587 8.838 2.767 ;
     RECT  22.608 2.587 24.297 2.767 ;
     RECT  25.02 2.731 33.894 2.767 ;
     RECT  34.815 2.641 36.306 2.767 ;
     RECT  10.368 2.731 10.854 2.803 ;
     RECT  13.14 2.731 21.762 2.839 ;
     RECT  10.368 2.803 10.998 2.875 ;
     RECT  37.044 2.641 50.67 2.909 ;
     RECT  6.84 2.539 6.858 2.911 ;
     RECT  7.776 2.767 8.838 2.911 ;
     RECT  22.608 2.767 36.306 2.911 ;
     RECT  37.044 2.909 43.197 2.911 ;
     RECT  13.14 2.839 21.798 3.001 ;
     RECT  22.608 2.911 43.197 3.001 ;
     RECT  44.136 2.909 50.67 3.019 ;
     RECT  6.84 2.911 8.838 3.037 ;
     RECT  5.004 2.632 5.742 3.065 ;
     RECT  10.368 2.875 11.502 3.145 ;
     RECT  6.84 3.037 9.018 3.181 ;
     RECT  10.224 3.145 11.502 3.181 ;
     RECT  2.304 2.489 3.294 3.209 ;
     RECT  5.004 3.065 5.397 3.209 ;
     RECT  2.415 3.209 3.294 3.299 ;
     RECT  0.216 2.731 0.594 3.307 ;
     RECT  2.415 3.299 3.006 3.335 ;
     RECT  44.136 3.019 50.706 3.335 ;
     RECT  13.14 3.001 43.197 3.343 ;
     RECT  44.46 3.335 50.706 3.407 ;
     RECT  13.104 3.343 43.197 3.437 ;
     RECT  0.144 3.307 0.594 3.595 ;
     RECT  6.84 3.181 11.538 3.595 ;
     RECT  26.1 3.437 43.197 3.605 ;
     RECT  6.732 3.595 11.538 3.649 ;
     RECT  26.208 3.605 43.197 3.649 ;
     RECT  6.732 3.649 11.862 3.685 ;
     RECT  13.104 3.437 25.29 3.685 ;
     RECT  44.46 3.407 49.59 3.749 ;
     RECT  26.208 3.649 43.47 3.839 ;
     RECT  44.46 3.749 48.762 3.839 ;
     RECT  6.732 3.685 25.29 3.847 ;
     RECT  49.572 3.749 49.59 3.92 ;
     RECT  44.46 3.839 48.69 3.983 ;
     RECT  42.915 3.839 43.47 4.075 ;
     RECT  0.108 3.595 0.594 4.145 ;
     RECT  44.46 3.983 48.654 4.289 ;
     RECT  50.508 3.407 50.706 4.315 ;
     RECT  6.228 3.847 25.29 4.351 ;
     RECT  26.208 3.839 42.174 4.351 ;
     RECT  44.784 4.289 48.654 4.379 ;
     RECT  50.148 4.315 50.706 4.379 ;
     RECT  42.915 4.075 43.686 4.387 ;
     RECT  6.228 4.351 42.174 4.415 ;
     RECT  6.336 4.415 42.174 4.559 ;
     RECT  51.732 4.459 51.75 4.603 ;
     RECT  0.108 4.145 0.558 4.604 ;
     RECT  3.96 3.919 3.978 4.685 ;
     RECT  51.696 4.603 51.75 4.757 ;
     RECT  2.415 3.335 2.934 4.765 ;
     RECT  9.936 4.559 42.174 4.801 ;
     RECT  42.915 4.387 43.938 4.801 ;
     RECT  51.696 4.757 51.714 4.829 ;
     RECT  2.415 4.765 2.97 4.891 ;
     RECT  5.115 3.209 5.397 4.891 ;
     RECT  44.892 4.379 48.654 4.927 ;
     RECT  49.824 4.747 49.842 4.927 ;
     RECT  2.304 4.891 2.97 5.027 ;
     RECT  44.892 4.927 49.842 5.189 ;
     RECT  6.336 4.559 9.126 5.305 ;
     RECT  49.608 5.189 49.842 5.333 ;
     RECT  6.336 5.305 9.198 5.341 ;
     RECT  9.936 4.801 43.938 5.341 ;
     RECT  44.892 5.189 48.762 5.341 ;
     RECT  2.304 5.027 2.862 5.369 ;
     RECT  5.004 4.891 5.397 5.431 ;
     RECT  6.192 5.341 9.198 5.431 ;
     RECT  9.936 5.341 48.762 5.431 ;
     RECT  6.192 5.431 48.762 5.459 ;
     RECT  4.788 5.431 5.397 5.575 ;
     RECT  4.14 5.575 5.397 5.611 ;
     RECT  6.192 5.459 47.574 5.611 ;
     RECT  48.315 5.459 48.762 5.639 ;
     RECT  49.788 5.333 49.842 5.639 ;
     RECT  2.376 5.369 2.862 5.645 ;
     RECT  4.14 5.611 47.574 5.659 ;
     RECT  49.824 5.639 49.842 5.755 ;
     RECT  50.688 4.379 50.706 5.755 ;
     RECT  0.144 4.604 0.558 5.789 ;
     RECT  3.924 5.659 47.574 5.999 ;
     RECT  49.824 5.755 50.706 5.999 ;
     RECT  2.415 5.645 2.862 6.151 ;
     RECT  49.824 5.999 50.202 6.179 ;
     RECT  48.315 5.639 48.597 6.385 ;
     RECT  46.98 5.999 47.574 6.421 ;
     RECT  48.315 6.385 48.798 6.421 ;
     RECT  50.112 6.179 50.202 6.539 ;
     RECT  2.415 6.151 3.078 6.691 ;
     RECT  2.415 6.691 3.15 6.763 ;
     RECT  2.304 6.763 3.15 6.817 ;
     RECT  3.924 5.999 46.206 6.817 ;
     RECT  2.304 6.817 46.206 6.845 ;
     RECT  2.415 6.845 46.206 7.051 ;
     RECT  46.98 6.421 48.798 7.051 ;
     RECT  50.148 6.539 50.202 7.088 ;
     RECT  2.415 7.051 48.798 7.231 ;
     RECT  1.116 6.241 1.134 7.393 ;
     RECT  49.752 7.339 49.77 7.421 ;
     RECT  1.116 7.393 1.422 7.517 ;
     RECT  51.732 5.611 51.75 7.727 ;
     RECT  2.415 7.231 48.87 7.915 ;
     RECT  50.688 7.195 50.706 8.041 ;
     RECT  0.144 5.789 0.27 8.069 ;
     RECT  50.688 8.041 50.742 8.093 ;
     RECT  2.415 7.915 49.014 8.429 ;
     RECT  50.688 8.093 50.706 8.491 ;
     RECT  46.692 8.429 49.014 8.581 ;
     RECT  50.184 8.491 50.706 8.581 ;
     RECT  46.692 8.581 50.706 8.699 ;
     RECT  46.692 8.699 47.574 8.879 ;
     RECT  48.315 8.699 50.706 8.879 ;
     RECT  15.915 8.429 45.954 8.969 ;
     RECT  2.415 8.429 15.138 9.053 ;
     RECT  46.836 8.879 47.574 9.149 ;
     RECT  45.615 8.969 45.954 9.211 ;
     RECT  15.915 8.969 44.694 9.239 ;
     RECT  48.315 8.879 49.806 9.245 ;
     RECT  44.604 9.239 44.694 9.509 ;
     RECT  46.908 9.149 47.574 9.553 ;
     RECT  48.315 9.245 49.05 9.553 ;
     RECT  46.908 9.553 49.05 9.581 ;
     RECT  1.404 7.517 1.422 9.625 ;
     RECT  2.415 9.053 15.102 9.625 ;
     RECT  50.688 8.879 50.706 9.643 ;
     RECT  44.604 9.509 44.622 9.689 ;
     RECT  15.915 9.239 43.866 9.751 ;
     RECT  1.404 9.625 15.102 9.787 ;
     RECT  15.876 9.751 43.866 9.787 ;
     RECT  0.144 8.069 0.162 9.917 ;
     RECT  51.732 9.787 51.75 9.923 ;
     RECT  45.615 9.211 46.062 9.931 ;
     RECT  46.908 9.581 48.942 9.931 ;
     RECT  1.404 9.787 43.866 10.027 ;
     RECT  0.216 9.931 0.234 10.075 ;
     RECT  1.404 10.027 44.01 10.085 ;
     RECT  1.404 10.085 43.866 10.319 ;
     RECT  0.216 10.075 0.342 10.363 ;
     RECT  1.404 10.319 43.542 10.363 ;
     RECT  45.615 9.931 48.942 10.411 ;
     RECT  44.928 10.411 48.942 10.471 ;
     RECT  50.148 9.643 50.706 10.499 ;
     RECT  0.216 10.363 43.542 10.651 ;
     RECT  44.928 10.471 49.266 10.705 ;
     RECT  50.184 10.499 50.706 10.795 ;
     RECT  44.928 10.705 49.338 10.895 ;
     RECT  49.32 10.895 49.338 10.967 ;
     RECT  50.184 10.795 50.742 11.039 ;
     RECT  0.108 10.651 43.542 11.083 ;
     RECT  50.184 11.039 50.706 11.281 ;
     RECT  49.608 11.281 50.706 11.405 ;
     RECT  0.108 11.083 43.65 11.443 ;
     RECT  0.108 11.443 43.902 11.453 ;
     RECT  51.732 11.515 51.75 11.579 ;
     RECT  12.564 11.453 43.902 11.707 ;
     RECT  44.928 10.895 48.597 11.707 ;
     RECT  12.564 11.707 48.597 11.777 ;
     RECT  12.564 11.777 43.902 11.789 ;
     RECT  50.148 11.405 50.706 11.939 ;
     RECT  45.036 11.777 48.597 12.019 ;
     RECT  50.688 11.939 50.706 12.085 ;
     RECT  45.036 12.019 49.014 12.119 ;
     RECT  0.108 11.453 11.79 12.181 ;
     RECT  12.564 11.789 43.794 12.181 ;
     RECT  0.108 12.181 43.794 12.523 ;
     RECT  50.688 12.085 50.742 12.557 ;
     RECT  45.036 12.119 48.69 12.865 ;
     RECT  0.108 12.523 44.154 13.099 ;
     RECT  45.036 12.865 48.762 13.099 ;
     RECT  49.788 12.811 49.806 13.099 ;
     RECT  0.108 13.099 49.806 13.531 ;
     RECT  50.688 12.557 50.706 13.531 ;
     RECT  0.108 13.531 50.706 13.739 ;
     RECT  50.112 13.739 50.706 14.071 ;
     RECT  0.108 13.739 49.05 14.099 ;
     RECT  50.112 14.071 50.742 14.141 ;
     RECT  50.148 14.141 50.742 14.369 ;
     RECT  50.688 14.369 50.742 14.573 ;
     RECT  0.108 14.099 21.942 14.719 ;
     RECT  22.716 14.099 49.05 14.791 ;
     RECT  0.036 14.719 21.942 14.881 ;
     RECT  22.716 14.791 49.122 14.881 ;
     RECT  51.732 13.819 51.75 15.017 ;
     RECT  0.036 14.881 49.122 15.115 ;
     RECT  50.688 14.573 50.706 15.529 ;
     RECT  50.688 15.529 50.742 15.581 ;
     RECT  0.036 15.115 49.806 15.629 ;
     RECT  50.688 15.581 50.706 15.691 ;
     RECT  50.148 15.691 50.706 15.728 ;
     RECT  0.036 15.629 49.302 15.827 ;
     RECT  50.184 15.728 50.706 16.367 ;
     RECT  50.688 16.367 50.706 16.501 ;
     RECT  0.036 15.827 49.266 16.529 ;
     RECT  0.036 16.529 48.597 16.565 ;
     RECT  50.688 16.501 50.742 16.733 ;
     RECT  22.536 16.565 48.597 16.907 ;
     RECT  22.824 16.907 48.597 16.973 ;
     RECT  49.572 16.987 49.59 17.069 ;
     RECT  50.688 16.733 50.706 17.221 ;
     RECT  0.036 16.565 21.69 17.419 ;
     RECT  22.932 16.973 48.597 17.491 ;
     RECT  50.148 17.221 50.706 17.519 ;
     RECT  0.036 17.419 21.978 17.752 ;
     RECT  22.932 17.491 49.014 17.752 ;
     RECT  0.036 17.752 49.014 17.789 ;
     RECT  38.556 17.789 49.014 18.031 ;
     RECT  38.556 18.031 49.266 18.221 ;
     RECT  50.184 17.519 50.706 18.283 ;
     RECT  50.148 18.283 50.706 18.419 ;
     RECT  0.036 17.789 37.797 18.535 ;
     RECT  38.556 18.221 48.597 18.535 ;
     RECT  49.608 18.571 49.626 18.689 ;
     RECT  50.508 18.419 50.706 19.435 ;
     RECT  50.184 19.435 50.706 19.579 ;
     RECT  51.732 18.427 51.75 20.183 ;
     RECT  0.036 18.535 48.597 20.191 ;
     RECT  0.036 20.191 48.762 20.389 ;
     RECT  49.608 19.579 50.706 20.389 ;
     RECT  0.036 20.389 50.706 20.957 ;
     RECT  0.036 20.957 49.806 21.263 ;
     RECT  49.572 21.263 49.806 21.929 ;
     RECT  50.688 20.957 50.706 21.973 ;
     RECT  51.732 21.019 51.75 22.037 ;
     RECT  0.036 21.263 48.69 22.081 ;
     RECT  0.036 22.081 49.014 22.199 ;
     RECT  49.86 21.973 50.706 22.205 ;
     RECT  0.036 22.199 48.798 22.235 ;
     RECT  50.184 22.205 50.706 22.279 ;
     RECT  50.184 22.279 50.742 22.349 ;
     RECT  50.616 22.349 50.742 23.069 ;
     RECT  0.036 22.235 48.597 23.161 ;
     RECT  50.616 23.069 50.706 23.161 ;
     RECT  0.036 23.161 48.942 23.279 ;
     RECT  0.036 23.279 48.87 23.315 ;
     RECT  25.02 23.315 48.87 23.351 ;
     RECT  50.148 23.161 50.706 23.431 ;
     RECT  49.608 23.431 50.706 23.645 ;
     RECT  25.02 23.351 48.834 23.927 ;
     RECT  50.148 23.645 50.706 24.089 ;
     RECT  0.036 23.315 24.297 24.091 ;
     RECT  25.02 23.927 48.597 24.091 ;
     RECT  49.788 24.619 49.806 24.737 ;
     RECT  0.036 24.091 48.597 24.781 ;
     RECT  51.732 24.187 51.75 24.809 ;
     RECT  50.688 24.089 50.706 25.195 ;
     RECT  0.036 24.781 48.618 25.285 ;
     RECT  0.036 25.285 48.798 25.439 ;
     RECT  50.184 25.195 50.706 25.483 ;
     RECT  49.572 25.483 50.706 25.619 ;
     RECT  49.752 25.619 50.706 25.979 ;
     RECT  49.752 25.979 49.77 26.347 ;
     RECT  0.036 25.439 48.597 26.491 ;
     RECT  49.572 26.347 49.77 26.491 ;
     RECT  0.036 26.491 49.77 26.519 ;
     RECT  0.036 26.519 49.23 26.789 ;
     RECT  51.732 25.915 51.75 26.813 ;
     RECT  50.688 25.979 50.706 26.923 ;
     RECT  50.184 26.923 50.706 27.167 ;
     RECT  38.808 26.789 49.23 27.365 ;
     RECT  0.036 26.789 37.998 27.571 ;
     RECT  38.808 27.365 48.597 27.571 ;
     RECT  50.652 27.167 50.706 27.599 ;
     RECT  0.036 27.571 48.597 27.905 ;
     RECT  7.452 27.905 48.597 27.917 ;
     RECT  49.572 27.499 49.806 27.931 ;
     RECT  50.688 27.599 50.706 28.139 ;
     RECT  28.836 27.917 48.597 28.255 ;
     RECT  49.572 27.931 49.842 28.255 ;
     RECT  28.836 28.255 49.842 28.256 ;
     RECT  49.824 28.256 49.842 28.319 ;
     RECT  28.836 28.256 48.906 28.409 ;
     RECT  28.836 28.409 48.87 28.445 ;
     RECT  40.215 28.445 48.87 28.481 ;
     RECT  7.452 27.917 28.062 28.651 ;
     RECT  28.836 28.445 39.33 28.651 ;
     RECT  0.036 27.905 6.678 28.957 ;
     RECT  7.452 28.651 39.33 28.957 ;
     RECT  40.215 28.481 48.597 29.129 ;
     RECT  40.215 29.129 44.154 29.191 ;
     RECT  0.036 28.957 39.33 29.323 ;
     RECT  40.104 29.191 44.154 29.323 ;
     RECT  44.892 29.129 48.597 29.399 ;
     RECT  50.724 29.371 50.742 29.515 ;
     RECT  0.036 29.323 44.154 29.525 ;
     RECT  0.036 29.525 33.246 29.549 ;
     RECT  50.688 29.515 50.742 29.605 ;
     RECT  33.984 29.525 44.154 29.633 ;
     RECT  47.268 29.399 48.597 29.641 ;
     RECT  50.688 29.605 50.778 29.837 ;
     RECT  34.2 29.633 44.154 29.875 ;
     RECT  44.892 29.399 46.458 29.875 ;
     RECT  47.268 29.641 48.69 29.875 ;
     RECT  47.268 29.875 49.338 29.911 ;
     RECT  0.036 29.549 9.162 29.939 ;
     RECT  47.268 29.911 49.626 29.981 ;
     RECT  47.268 29.981 49.338 30.029 ;
     RECT  34.2 29.875 46.458 30.167 ;
     RECT  47.268 30.029 49.086 30.167 ;
     RECT  34.2 30.167 49.086 30.209 ;
     RECT  0.072 29.939 9.162 30.283 ;
     RECT  9.936 29.549 33.246 30.283 ;
     RECT  34.2 30.209 47.394 30.299 ;
     RECT  0.072 30.283 33.246 30.307 ;
     RECT  0.072 30.307 33.282 30.335 ;
     RECT  50.688 29.837 50.742 30.379 ;
     RECT  7.632 30.335 33.282 30.451 ;
     RECT  34.2 30.299 46.386 30.451 ;
     RECT  7.632 30.451 46.386 30.479 ;
     RECT  50.184 30.379 50.742 30.557 ;
     RECT  7.632 30.479 46.242 30.569 ;
     RECT  47.232 30.299 47.394 30.911 ;
     RECT  0.072 30.335 6.858 31.081 ;
     RECT  7.632 30.569 46.062 31.081 ;
     RECT  50.184 30.557 50.706 31.099 ;
     RECT  50.148 31.099 50.706 31.253 ;
     RECT  0.072 31.081 46.062 31.291 ;
     RECT  48.315 30.209 49.086 31.459 ;
     RECT  47.376 30.911 47.394 31.531 ;
     RECT  0.072 31.291 46.53 31.765 ;
     RECT  47.376 31.531 47.502 31.765 ;
     RECT  0.072 31.765 47.502 31.829 ;
     RECT  50.184 31.253 50.706 31.891 ;
     RECT  48.315 31.459 49.158 32.035 ;
     RECT  39.816 31.829 47.502 32.161 ;
     RECT  48.315 32.035 49.194 32.161 ;
     RECT  50.184 31.891 50.742 32.233 ;
     RECT  39.816 32.161 49.194 32.341 ;
     RECT  39.816 32.341 49.266 32.459 ;
     RECT  45.615 32.459 49.266 32.567 ;
     RECT  0.072 31.829 39.078 32.611 ;
     RECT  39.816 32.459 44.838 32.611 ;
     RECT  46.98 32.567 49.266 32.611 ;
     RECT  50.184 32.233 50.778 32.611 ;
     RECT  46.98 32.611 50.778 32.717 ;
     RECT  49.86 32.717 50.778 32.861 ;
     RECT  46.98 32.717 49.122 32.999 ;
     RECT  46.98 32.999 48.942 33.035 ;
     RECT  48.315 33.035 48.942 33.071 ;
     RECT  0.072 32.611 44.838 33.269 ;
     RECT  0.072 33.269 33.57 33.293 ;
     RECT  34.815 33.269 44.838 33.313 ;
     RECT  45.615 32.567 46.242 33.313 ;
     RECT  46.98 33.035 47.322 33.413 ;
     RECT  46.98 33.413 47.178 33.449 ;
     RECT  34.815 33.313 46.242 33.511 ;
     RECT  46.98 33.449 47.07 33.511 ;
     RECT  49.86 32.861 50.742 33.581 ;
     RECT  0.072 33.293 1.458 33.719 ;
     RECT  48.315 33.071 48.654 33.817 ;
     RECT  0.144 33.719 1.458 33.869 ;
     RECT  50.688 33.581 50.742 34.013 ;
     RECT  34.815 33.511 47.07 34.051 ;
     RECT  2.415 33.293 33.57 34.195 ;
     RECT  34.416 34.051 47.07 34.195 ;
     RECT  48.315 33.817 48.726 34.231 ;
     RECT  49.716 33.691 49.734 34.411 ;
     RECT  49.68 34.411 49.734 34.429 ;
     RECT  50.688 34.013 50.706 34.429 ;
     RECT  2.415 34.195 47.07 34.457 ;
     RECT  44.856 34.457 47.07 34.465 ;
     RECT  48.24 34.231 48.726 34.465 ;
     RECT  49.68 34.429 50.706 34.589 ;
     RECT  2.415 34.457 44.01 34.619 ;
     RECT  44.856 34.465 48.726 34.619 ;
     RECT  2.415 34.619 43.758 34.655 ;
     RECT  49.68 34.589 49.842 34.843 ;
     RECT  50.688 34.589 50.706 34.969 ;
     RECT  2.415 34.655 43.614 35.021 ;
     RECT  2.415 35.021 43.47 35.131 ;
     RECT  50.688 34.969 50.742 35.165 ;
     RECT  47.052 34.619 48.726 35.231 ;
     RECT  47.592 35.231 48.726 35.275 ;
     RECT  49.572 34.843 49.842 35.275 ;
     RECT  47.592 35.275 49.842 35.339 ;
     RECT  44.856 34.619 46.134 35.401 ;
     RECT  0.144 33.869 1.422 35.453 ;
     RECT  47.7 35.339 49.806 35.537 ;
     RECT  44.856 35.401 46.854 35.581 ;
     RECT  47.7 35.537 49.014 35.699 ;
     RECT  2.304 35.131 43.47 35.851 ;
     RECT  44.388 35.581 46.854 35.851 ;
     RECT  2.304 35.851 46.854 35.879 ;
     RECT  47.7 35.699 48.942 36.077 ;
     RECT  49.788 35.537 49.806 36.077 ;
     RECT  45.615 35.879 46.854 36.121 ;
     RECT  47.7 36.077 48.597 36.121 ;
     RECT  45.615 36.121 48.597 36.239 ;
     RECT  0.216 35.453 1.422 36.247 ;
     RECT  50.688 35.165 50.706 36.391 ;
     RECT  45.615 36.239 46.926 36.545 ;
     RECT  50.148 36.391 50.706 36.617 ;
     RECT  2.304 35.879 44.514 36.787 ;
     RECT  45.615 36.545 46.53 36.787 ;
     RECT  2.304 36.787 46.53 36.923 ;
     RECT  51.732 36.283 51.75 37.049 ;
     RECT  49.356 36.895 49.374 37.147 ;
     RECT  47.88 36.239 48.597 37.201 ;
     RECT  49.356 37.147 49.626 37.201 ;
     RECT  50.688 36.617 50.706 37.399 ;
     RECT  47.88 37.201 49.626 37.435 ;
     RECT  50.688 37.399 50.778 37.469 ;
     RECT  47.844 37.435 49.626 37.499 ;
     RECT  31.284 36.923 46.53 37.589 ;
     RECT  47.844 37.499 49.338 37.589 ;
     RECT  50.688 37.469 50.706 37.597 ;
     RECT  2.304 36.923 30.366 37.669 ;
     RECT  31.284 37.589 44.838 37.669 ;
     RECT  45.615 37.589 46.53 37.669 ;
     RECT  47.844 37.589 48.762 37.669 ;
     RECT  50.652 37.597 50.706 37.669 ;
     RECT  45.615 37.669 48.762 38.039 ;
     RECT  0.108 36.247 1.422 38.333 ;
     RECT  2.304 37.669 44.838 38.371 ;
     RECT  45.615 38.039 48.597 38.371 ;
     RECT  50.148 37.669 50.706 38.551 ;
     RECT  50.148 38.551 50.742 38.621 ;
     RECT  2.304 38.371 48.597 38.669 ;
     RECT  2.304 38.669 46.782 38.785 ;
     RECT  47.592 38.669 48.597 39.091 ;
     RECT  2.268 38.785 46.782 39.451 ;
     RECT  47.592 39.091 48.69 39.451 ;
     RECT  2.268 39.451 48.69 39.479 ;
     RECT  47.88 39.479 48.69 39.587 ;
     RECT  48.024 39.587 48.69 39.595 ;
     RECT  50.148 38.621 50.706 39.659 ;
     RECT  48.024 39.595 48.762 39.757 ;
     RECT  51.732 39.739 51.75 39.785 ;
     RECT  51.66 39.883 51.678 40.013 ;
     RECT  0.144 38.333 1.422 40.063 ;
     RECT  50.688 39.659 50.706 40.099 ;
     RECT  48.024 39.757 49.014 40.171 ;
     RECT  49.824 40.027 49.842 40.171 ;
     RECT  2.268 39.479 47.106 40.205 ;
     RECT  48.024 40.171 49.842 40.397 ;
     RECT  50.688 40.099 50.742 40.441 ;
     RECT  2.415 40.205 47.106 40.459 ;
     RECT  48.024 40.397 48.762 40.459 ;
     RECT  2.415 40.459 48.762 40.493 ;
     RECT  47.448 40.493 48.762 40.703 ;
     RECT  2.415 40.493 46.422 41.099 ;
     RECT  47.844 40.703 48.762 41.251 ;
     RECT  50.148 40.441 50.742 41.251 ;
     RECT  47.844 41.251 50.742 41.449 ;
     RECT  44.316 41.099 46.422 41.647 ;
     RECT  2.415 41.099 43.506 41.749 ;
     RECT  44.316 41.647 46.458 41.917 ;
     RECT  47.268 41.449 50.742 41.917 ;
     RECT  51.732 42.043 51.75 42.089 ;
     RECT  0.036 40.063 1.422 42.283 ;
     RECT  2.304 41.749 43.506 42.283 ;
     RECT  44.316 41.917 50.742 42.323 ;
     RECT  0.036 42.283 43.506 42.529 ;
     RECT  44.316 42.323 48.798 42.529 ;
     RECT  49.824 42.323 50.742 42.629 ;
     RECT  0.036 42.529 48.798 42.755 ;
     RECT  50.148 42.629 50.742 42.989 ;
     RECT  47.448 42.755 48.597 43.061 ;
     RECT  0.036 42.755 46.53 43.259 ;
     RECT  47.52 43.061 48.597 43.295 ;
     RECT  48.24 43.295 48.597 43.771 ;
     RECT  50.184 42.989 50.742 44.093 ;
     RECT  0.036 43.259 46.494 44.149 ;
     RECT  50.184 44.093 50.706 44.149 ;
     RECT  0.036 44.149 47.106 44.185 ;
     RECT  48.24 43.771 49.266 44.185 ;
     RECT  51.732 44.347 51.75 44.411 ;
     RECT  0.036 44.185 49.266 44.669 ;
     RECT  50.148 44.149 50.706 44.813 ;
     RECT  0.036 44.669 49.014 44.879 ;
     RECT  50.184 44.813 50.706 44.959 ;
     RECT  50.184 44.959 50.742 44.995 ;
     RECT  0.036 44.879 46.782 45.059 ;
     RECT  50.184 44.995 50.814 45.101 ;
     RECT  48.315 44.879 49.014 45.149 ;
     RECT  50.184 45.101 50.742 45.677 ;
     RECT  50.184 45.677 50.706 45.787 ;
     RECT  47.52 45.769 47.538 45.805 ;
     RECT  48.315 45.149 48.978 45.805 ;
     RECT  47.52 45.805 48.978 45.841 ;
     RECT  47.304 45.841 48.978 46.103 ;
     RECT  47.304 46.103 48.597 46.123 ;
     RECT  49.824 45.787 50.706 46.363 ;
     RECT  49.788 46.363 50.706 46.381 ;
     RECT  49.608 46.381 50.706 46.781 ;
     RECT  0.036 45.059 46.53 46.795 ;
     RECT  47.268 46.123 48.597 46.795 ;
     RECT  51.732 46.651 51.75 46.829 ;
     RECT  0.036 46.795 48.597 47.119 ;
     RECT  49.5 47.083 49.518 47.119 ;
     RECT  50.688 46.781 50.706 47.119 ;
     RECT  0.036 47.119 49.518 47.219 ;
     RECT  50.688 47.119 50.742 47.281 ;
     RECT  50.688 47.281 50.778 47.549 ;
     RECT  50.688 47.549 50.742 47.659 ;
     RECT  0.036 47.219 49.122 47.849 ;
     RECT  47.88 47.849 49.122 48.029 ;
     RECT  50.148 47.659 50.742 48.091 ;
     RECT  49.572 48.091 50.742 48.128 ;
     RECT  49.608 48.128 50.742 48.413 ;
     RECT  47.88 48.029 48.597 48.533 ;
     RECT  0.036 47.849 47.07 48.667 ;
     RECT  50.148 48.413 50.742 48.848 ;
     RECT  50.688 48.848 50.742 48.989 ;
     RECT  48.315 48.533 48.597 49.441 ;
     RECT  48.315 49.441 49.05 49.549 ;
     RECT  0.036 48.667 47.466 49.613 ;
     RECT  50.688 48.989 50.706 49.675 ;
     RECT  0.036 49.613 47.394 50.009 ;
     RECT  48.315 49.549 49.122 50.161 ;
     RECT  0.036 50.009 47.106 50.279 ;
     RECT  48.315 50.161 49.302 50.315 ;
     RECT  51.732 49.963 51.75 50.459 ;
     RECT  50.652 49.675 50.706 50.573 ;
     RECT  48.315 50.315 48.597 50.701 ;
     RECT  28.872 50.279 47.106 50.827 ;
     RECT  47.88 50.701 48.597 50.827 ;
     RECT  28.872 50.827 48.597 51.061 ;
     RECT  28.872 51.061 49.05 51.089 ;
     RECT  47.808 51.089 49.05 51.149 ;
     RECT  49.824 51.115 49.842 51.197 ;
     RECT  0.036 50.279 28.062 51.241 ;
     RECT  28.872 51.089 46.782 51.241 ;
     RECT  48.204 51.149 49.05 51.241 ;
     RECT  0.036 51.241 46.782 51.269 ;
     RECT  48.204 51.241 49.698 51.359 ;
     RECT  51.732 51.259 51.75 51.539 ;
     RECT  51.66 51.739 51.678 51.869 ;
     RECT  0.036 51.269 46.746 51.971 ;
     RECT  49.68 51.359 49.698 51.979 ;
     RECT  50.688 50.573 50.706 51.979 ;
     RECT  48.204 51.359 48.597 52.213 ;
     RECT  49.68 51.979 50.706 52.213 ;
     RECT  47.628 52.213 50.706 52.321 ;
     RECT  47.628 52.321 50.742 52.475 ;
     RECT  49.608 52.475 50.742 52.589 ;
     RECT  47.628 52.475 48.597 52.591 ;
     RECT  0.036 51.971 46.71 52.789 ;
     RECT  0.036 52.789 46.782 52.861 ;
     RECT  47.556 52.591 48.597 52.861 ;
     RECT  49.752 52.589 50.742 53.021 ;
     RECT  0.036 52.861 48.597 53.329 ;
     RECT  49.752 53.021 50.706 53.357 ;
     RECT  49.752 53.357 49.77 53.393 ;
     RECT  0.036 53.329 48.942 53.941 ;
     RECT  0.036 53.941 49.23 53.969 ;
     RECT  47.772 53.969 49.23 54.059 ;
     RECT  0.036 53.969 46.818 54.751 ;
     RECT  47.772 54.059 49.194 54.751 ;
     RECT  50.652 53.357 50.706 54.859 ;
     RECT  0.036 54.751 49.194 54.869 ;
     RECT  51.732 54.715 51.75 54.977 ;
     RECT  50.148 54.859 50.706 55.003 ;
     RECT  49.68 55.003 50.706 55.139 ;
     RECT  0.036 54.869 48.597 55.211 ;
     RECT  46.908 55.211 48.597 55.921 ;
     RECT  49.68 55.139 49.914 55.921 ;
     RECT  46.908 55.921 49.914 56.057 ;
     RECT  46.908 56.057 48.762 56.093 ;
     RECT  0.036 55.211 46.062 56.101 ;
     RECT  49.716 56.057 49.914 56.155 ;
     RECT  50.652 55.139 50.706 56.155 ;
     RECT  0.036 56.101 46.17 56.371 ;
     RECT  46.908 56.093 46.926 56.371 ;
     RECT  47.772 56.093 48.762 56.489 ;
     RECT  0.036 56.371 46.926 56.759 ;
     RECT  46.764 56.759 46.926 56.911 ;
     RECT  47.772 56.489 48.597 56.911 ;
     RECT  49.716 56.155 50.706 56.939 ;
     RECT  46.764 56.911 48.597 57.101 ;
     RECT  49.752 56.939 50.706 57.137 ;
     RECT  50.184 57.137 50.706 57.299 ;
     RECT  46.764 57.101 46.782 57.335 ;
     RECT  47.7 57.101 48.597 57.407 ;
     RECT  50.184 57.299 50.202 57.479 ;
     RECT  51.732 56.299 51.75 57.569 ;
     RECT  0.036 56.759 46.026 57.991 ;
     RECT  0.036 57.991 46.53 58.109 ;
     RECT  47.772 57.407 48.597 58.261 ;
     RECT  47.304 58.261 48.597 58.387 ;
     RECT  49.32 58.261 49.338 58.387 ;
     RECT  50.148 58.315 50.166 58.459 ;
     RECT  47.304 58.387 49.338 58.649 ;
     RECT  47.34 58.649 49.338 58.685 ;
     RECT  47.34 58.685 49.23 58.919 ;
     RECT  0.036 58.109 46.17 58.963 ;
     RECT  0.036 58.963 46.602 59.701 ;
     RECT  47.34 58.919 48.597 59.701 ;
     RECT  0.036 59.701 48.597 59.729 ;
     RECT  23.976 59.729 48.597 59.845 ;
     RECT  23.976 59.845 49.158 59.999 ;
     RECT  50.148 58.459 50.706 60.043 ;
     RECT  23.976 59.999 48.654 60.269 ;
     RECT  50.112 60.043 50.706 60.331 ;
     RECT  23.976 60.269 47.142 60.449 ;
     RECT  49.608 60.331 50.706 60.539 ;
     RECT  0.036 59.729 23.166 60.583 ;
     RECT  23.976 60.449 46.314 60.583 ;
     RECT  49.608 60.539 50.166 60.647 ;
     RECT  51.732 58.387 51.75 60.809 ;
     RECT  47.88 60.269 48.654 60.953 ;
     RECT  50.148 60.647 50.166 61.079 ;
     RECT  48.315 60.953 48.654 61.115 ;
     RECT  0.036 60.583 46.314 61.231 ;
     RECT  47.052 60.449 47.142 61.231 ;
     RECT  0.036 61.231 47.142 61.691 ;
     RECT  2.415 61.691 47.142 61.799 ;
     RECT  42.768 61.799 47.142 62.041 ;
     RECT  2.415 61.799 41.922 62.069 ;
     RECT  42.768 62.041 47.502 62.275 ;
     RECT  48.315 61.115 48.597 62.275 ;
     RECT  50.688 62.041 50.706 62.311 ;
     RECT  0.036 61.691 1.458 62.465 ;
     RECT  42.768 62.275 48.597 62.509 ;
     RECT  23.868 62.069 41.922 62.573 ;
     RECT  2.415 62.069 23.058 62.699 ;
     RECT  28.908 62.573 41.922 62.699 ;
     RECT  28.98 62.699 41.922 62.735 ;
     RECT  42.768 62.509 48.69 62.743 ;
     RECT  29.016 62.735 41.922 62.815 ;
     RECT  42.696 62.743 48.69 62.815 ;
     RECT  29.016 62.815 49.23 62.851 ;
     RECT  50.112 62.311 50.706 62.851 ;
     RECT  15.768 62.699 23.058 62.941 ;
     RECT  23.868 62.573 28.098 62.941 ;
     RECT  29.016 62.851 50.706 63.239 ;
     RECT  2.415 62.699 14.994 63.245 ;
     RECT  48.132 63.239 50.706 63.247 ;
     RECT  29.016 63.239 44.226 63.481 ;
     RECT  48.132 63.247 50.742 63.509 ;
     RECT  15.768 62.941 28.098 63.517 ;
     RECT  48.315 63.509 50.742 63.533 ;
     RECT  11.664 63.245 14.994 63.553 ;
     RECT  15.768 63.517 28.134 63.553 ;
     RECT  28.944 63.481 44.226 63.553 ;
     RECT  0.036 62.465 1.17 63.677 ;
     RECT  48.315 63.533 50.67 63.677 ;
     RECT  11.664 63.553 44.226 63.815 ;
     RECT  19.728 63.815 43.197 63.887 ;
     RECT  45.036 63.239 47.322 63.923 ;
     RECT  2.415 63.245 10.854 64.027 ;
     RECT  11.664 63.815 18.897 64.027 ;
     RECT  43.992 63.815 44.226 64.165 ;
     RECT  43.992 64.165 44.262 64.205 ;
     RECT  48.315 63.677 50.238 64.253 ;
     RECT  48.315 64.253 49.338 64.471 ;
     RECT  2.415 64.027 18.897 64.507 ;
     RECT  45.108 63.923 47.322 64.555 ;
     RECT  2.376 64.507 18.897 64.589 ;
     RECT  45.108 64.555 47.358 64.669 ;
     RECT  20.052 63.887 43.197 64.699 ;
     RECT  45.108 64.669 47.394 64.699 ;
     RECT  50.148 64.253 50.238 64.829 ;
     RECT  20.052 64.699 43.65 64.891 ;
     RECT  19.62 64.891 43.65 64.939 ;
     RECT  44.856 64.699 47.394 64.939 ;
     RECT  48.168 64.471 49.338 64.939 ;
     RECT  2.376 64.589 2.697 64.987 ;
     RECT  3.492 64.589 18.897 65.011 ;
     RECT  19.62 64.939 49.338 65.011 ;
     RECT  50.688 64.831 50.706 65.011 ;
     RECT  1.98 64.987 2.697 65.117 ;
     RECT  3.492 65.011 49.338 65.227 ;
     RECT  0.036 63.677 0.558 65.237 ;
     RECT  3.492 65.227 49.698 65.309 ;
     RECT  3.6 65.309 49.482 65.399 ;
     RECT  0.108 65.237 0.558 65.405 ;
     RECT  3.6 65.399 44.226 65.435 ;
     RECT  0.18 65.405 0.558 65.563 ;
     RECT  10.332 65.435 44.226 65.579 ;
     RECT  3.6 65.435 9.45 65.669 ;
     RECT  0.18 65.563 0.594 65.741 ;
     RECT  2.268 65.117 2.697 65.821 ;
     RECT  3.636 65.669 9.45 65.975 ;
     RECT  0.18 65.741 0.558 65.981 ;
     RECT  50.688 65.011 50.742 65.981 ;
     RECT  2.268 65.821 2.862 66.011 ;
     RECT  45.108 65.399 49.482 66.085 ;
     RECT  2.268 66.011 2.79 66.125 ;
     RECT  45.108 66.085 49.626 66.125 ;
     RECT  3.744 65.975 9.45 66.331 ;
     RECT  10.332 65.579 44.046 66.331 ;
     RECT  3.744 66.331 44.046 66.389 ;
     RECT  4.212 66.389 44.046 66.479 ;
     RECT  2.304 66.125 2.79 66.515 ;
     RECT  2.415 66.515 2.79 66.659 ;
     RECT  4.212 66.479 43.938 66.659 ;
     RECT  4.212 66.659 11.43 66.701 ;
     RECT  50.688 65.981 50.706 66.749 ;
     RECT  51.732 65.659 51.75 66.857 ;
     RECT  45.108 66.125 49.014 66.901 ;
     RECT  12.312 66.659 43.938 67.019 ;
     RECT  12.312 67.019 17.802 67.055 ;
     RECT  45.108 66.901 49.626 67.099 ;
     RECT  18.54 67.019 43.938 67.163 ;
     RECT  0.18 65.981 0.522 67.171 ;
     RECT  18.615 67.163 43.938 67.243 ;
     RECT  18.615 67.243 44.334 67.261 ;
     RECT  45.108 67.099 50.166 67.261 ;
     RECT  18.615 67.261 50.166 67.421 ;
     RECT  4.356 66.701 11.43 67.441 ;
     RECT  12.312 67.055 17.766 67.441 ;
     RECT  18.615 67.421 49.014 67.559 ;
     RECT  18.615 67.559 22.806 67.595 ;
     RECT  0.108 67.171 0.522 67.711 ;
     RECT  50.184 67.531 50.706 67.801 ;
     RECT  0.108 67.711 0.558 67.945 ;
     RECT  2.415 66.659 2.697 67.963 ;
     RECT  4.356 67.441 17.766 67.981 ;
     RECT  18.615 67.595 22.77 67.981 ;
     RECT  50.184 67.801 50.742 67.997 ;
     RECT  23.94 67.559 49.014 68.099 ;
     RECT  4.356 67.981 22.77 68.203 ;
     RECT  3.96 68.203 22.77 68.237 ;
     RECT  44.424 68.099 49.014 68.245 ;
     RECT  3.96 68.237 4.374 68.279 ;
     RECT  44.424 68.245 49.626 68.279 ;
     RECT  5.115 68.237 22.77 68.285 ;
     RECT  0.108 67.945 1.134 68.288 ;
     RECT  6.768 68.285 22.77 68.347 ;
     RECT  23.94 68.099 27.954 68.369 ;
     RECT  6.768 68.347 23.13 68.377 ;
     RECT  23.94 68.369 27.918 68.377 ;
     RECT  6.768 68.377 27.918 68.429 ;
     RECT  44.784 68.279 49.626 68.675 ;
     RECT  49.608 68.675 49.626 68.861 ;
     RECT  5.115 68.285 5.778 68.909 ;
     RECT  28.98 68.099 43.434 68.923 ;
     RECT  50.688 67.997 50.742 68.989 ;
     RECT  28.98 68.923 43.47 69.061 ;
     RECT  7.128 68.429 27.918 69.151 ;
     RECT  28.98 69.061 43.686 69.151 ;
     RECT  7.128 69.151 43.686 69.295 ;
     RECT  0.396 68.288 1.134 69.307 ;
     RECT  0.144 69.307 1.134 69.331 ;
     RECT  6.732 69.295 43.686 69.331 ;
     RECT  6.732 69.331 43.902 69.449 ;
     RECT  44.784 68.675 48.597 69.457 ;
     RECT  44.64 69.457 48.597 69.533 ;
     RECT  50.184 68.989 50.742 69.581 ;
     RECT  4.356 68.279 4.374 69.592 ;
     RECT  5.115 68.909 5.742 69.592 ;
     RECT  50.184 69.581 50.706 69.601 ;
     RECT  49.608 69.601 50.706 69.725 ;
     RECT  2.304 67.963 2.697 69.787 ;
     RECT  0.144 69.331 1.422 69.821 ;
     RECT  4.356 69.592 5.742 69.827 ;
     RECT  45.036 69.533 48.597 69.827 ;
     RECT  6.732 69.449 43.614 69.835 ;
     RECT  4.356 69.827 5.454 69.899 ;
     RECT  45.108 69.827 48.597 70.141 ;
     RECT  4.356 69.899 5.397 70.169 ;
     RECT  6.264 69.835 43.614 70.411 ;
     RECT  50.148 69.725 50.706 70.529 ;
     RECT  2.304 69.787 3.078 70.565 ;
     RECT  2.415 70.565 3.078 70.672 ;
     RECT  6.264 70.411 44.226 70.681 ;
     RECT  45.108 70.141 49.05 70.681 ;
     RECT  0.396 69.821 1.422 70.699 ;
     RECT  6.264 70.681 49.878 70.709 ;
     RECT  5.115 70.169 5.397 70.747 ;
     RECT  6.264 70.709 44.73 70.747 ;
     RECT  5.115 70.747 44.73 70.835 ;
     RECT  2.415 70.672 3.186 70.951 ;
     RECT  6.588 70.835 44.73 71.069 ;
     RECT  21.024 71.069 27.702 71.075 ;
     RECT  28.512 71.069 44.73 71.177 ;
     RECT  28.512 71.177 43.902 71.213 ;
     RECT  45.615 70.709 49.878 71.249 ;
     RECT  49.644 71.249 49.878 71.309 ;
     RECT  2.415 70.951 3.258 71.311 ;
     RECT  44.712 71.177 44.73 71.339 ;
     RECT  49.716 71.309 49.878 71.347 ;
     RECT  50.688 70.529 50.706 71.347 ;
     RECT  5.115 70.835 5.634 71.581 ;
     RECT  6.588 71.069 20.25 71.581 ;
     RECT  2.415 71.311 3.474 71.609 ;
     RECT  5.115 71.581 20.25 71.609 ;
     RECT  4.356 70.169 4.374 71.689 ;
     RECT  5.115 71.609 8.298 71.689 ;
     RECT  2.415 71.609 3.402 71.851 ;
     RECT  32.115 71.213 43.902 71.995 ;
     RECT  21.06 71.075 27.702 72.031 ;
     RECT  28.512 71.213 31.05 72.031 ;
     RECT  32.115 71.995 44.046 72.031 ;
     RECT  31.86 72.031 44.046 72.059 ;
     RECT  9.144 71.609 20.25 72.121 ;
     RECT  21.06 72.031 31.05 72.121 ;
     RECT  31.86 72.059 43.902 72.121 ;
     RECT  45.615 71.249 48.597 72.121 ;
     RECT  44.856 72.121 48.597 72.149 ;
     RECT  0.144 70.699 1.422 72.265 ;
     RECT  9.144 72.121 43.902 72.329 ;
     RECT  2.304 71.851 3.402 72.419 ;
     RECT  49.716 71.347 50.706 72.427 ;
     RECT  4.356 71.689 8.298 72.455 ;
     RECT  48.315 72.149 48.597 72.499 ;
     RECT  49.608 72.427 50.706 72.499 ;
     RECT  7.236 72.455 8.298 72.535 ;
     RECT  9.144 72.329 27.702 72.535 ;
     RECT  7.236 72.535 27.702 72.563 ;
     RECT  44.856 72.149 47.574 72.599 ;
     RECT  48.315 72.499 50.706 72.661 ;
     RECT  4.356 72.455 6.462 72.749 ;
     RECT  28.44 72.329 43.902 72.869 ;
     RECT  48.315 72.661 50.742 72.893 ;
     RECT  29.16 72.869 43.902 72.931 ;
     RECT  44.856 72.599 47.466 72.931 ;
     RECT  3.636 72.841 3.654 72.959 ;
     RECT  18.54 72.563 27.702 72.989 ;
     RECT  29.16 72.931 47.466 73.031 ;
     RECT  7.236 72.563 17.802 73.037 ;
     RECT  23.364 72.989 27.702 73.051 ;
     RECT  16.92 73.037 17.802 73.345 ;
     RECT  18.54 72.989 22.626 73.345 ;
     RECT  2.304 72.419 2.79 73.373 ;
     RECT  16.92 73.345 22.626 73.379 ;
     RECT  7.236 73.037 16.197 73.499 ;
     RECT  16.92 73.379 20.034 73.499 ;
     RECT  20.808 73.379 22.626 73.499 ;
     RECT  5.04 72.749 6.462 73.507 ;
     RECT  7.236 73.499 9.162 73.507 ;
     RECT  16.92 73.499 19.962 73.535 ;
     RECT  48.315 72.893 49.41 73.535 ;
     RECT  5.04 73.507 9.162 73.769 ;
     RECT  20.844 73.499 22.626 73.769 ;
     RECT  21.06 73.769 22.626 73.777 ;
     RECT  23.364 73.051 28.278 73.777 ;
     RECT  29.16 73.031 44.442 73.813 ;
     RECT  29.16 73.813 44.838 73.819 ;
     RECT  29.088 73.819 44.838 73.877 ;
     RECT  21.06 73.777 28.278 73.885 ;
     RECT  29.088 73.877 37.962 73.885 ;
     RECT  0.036 72.265 1.422 73.901 ;
     RECT  45.576 73.031 47.466 73.921 ;
     RECT  48.315 73.535 49.302 73.921 ;
     RECT  45.576 73.921 49.302 73.997 ;
     RECT  38.772 73.877 44.838 74.039 ;
     RECT  47.664 73.997 49.302 74.039 ;
     RECT  50.184 72.893 50.742 74.045 ;
     RECT  38.772 74.039 44.226 74.093 ;
     RECT  2.304 73.373 2.697 74.155 ;
     RECT  50.688 74.045 50.742 74.189 ;
     RECT  5.04 73.769 9.018 74.191 ;
     RECT  2.304 74.155 3.15 74.309 ;
     RECT  2.304 74.309 2.697 74.345 ;
     RECT  21.06 73.885 37.962 74.381 ;
     RECT  9.9 73.499 16.197 74.389 ;
     RECT  9.9 74.389 16.398 74.425 ;
     RECT  45.576 73.997 46.89 74.425 ;
     RECT  33.444 74.381 37.962 74.453 ;
     RECT  0.036 73.901 0.846 74.477 ;
     RECT  4.5 74.191 9.018 74.551 ;
     RECT  9.828 74.425 16.398 74.551 ;
     RECT  48.315 74.039 49.302 74.551 ;
     RECT  48.315 74.551 49.626 74.579 ;
     RECT  4.5 74.551 16.398 74.587 ;
     RECT  17.136 73.535 19.962 74.587 ;
     RECT  4.5 74.587 19.962 74.615 ;
     RECT  4.5 74.615 6.894 74.623 ;
     RECT  4.284 74.623 6.894 74.651 ;
     RECT  21.06 74.381 32.634 74.651 ;
     RECT  6.876 74.651 6.894 74.669 ;
     RECT  21.06 74.651 30.762 74.669 ;
     RECT  21.06 74.669 28.458 74.678 ;
     RECT  4.284 74.651 6.138 74.683 ;
     RECT  31.536 74.651 32.634 74.687 ;
     RECT  33.768 74.453 37.962 74.731 ;
     RECT  3.96 74.683 6.138 74.759 ;
     RECT  33.768 74.731 37.998 74.779 ;
     RECT  38.772 74.093 43.578 74.779 ;
     RECT  31.716 74.687 32.634 74.849 ;
     RECT  45 74.425 46.89 74.849 ;
     RECT  29.232 74.669 30.762 74.885 ;
     RECT  4.284 74.759 6.138 74.909 ;
     RECT  29.34 74.885 30.762 74.921 ;
     RECT  29.34 74.921 30.726 74.957 ;
     RECT  51.732 74.299 51.75 74.957 ;
     RECT  7.668 74.615 19.962 74.965 ;
     RECT  21.024 74.678 28.458 74.965 ;
     RECT  45.615 74.849 46.89 75.067 ;
     RECT  45.615 75.067 46.926 75.091 ;
     RECT  33.768 74.779 43.578 75.115 ;
     RECT  7.668 74.965 28.458 75.191 ;
     RECT  2.415 74.345 2.697 75.259 ;
     RECT  33.768 75.115 44.046 75.271 ;
     RECT  45.615 75.091 47.214 75.293 ;
     RECT  49.32 74.579 49.626 75.361 ;
     RECT  2.415 75.259 2.79 75.451 ;
     RECT  4.536 74.909 6.138 75.499 ;
     RECT  4.536 75.499 6.246 75.505 ;
     RECT  45.615 75.293 46.854 75.533 ;
     RECT  23.256 75.191 28.458 75.631 ;
     RECT  48.315 74.579 48.597 75.631 ;
     RECT  49.32 75.361 49.662 75.631 ;
     RECT  48.06 75.631 49.662 75.731 ;
     RECT  33.696 75.271 44.478 75.739 ;
     RECT  45.615 75.533 46.818 75.739 ;
     RECT  0.036 74.477 0.558 75.775 ;
     RECT  4.536 75.505 6.786 75.775 ;
     RECT  23.256 75.631 28.494 75.775 ;
     RECT  48.06 75.731 48.654 75.803 ;
     RECT  2.304 75.451 2.79 75.811 ;
     RECT  31.824 74.849 32.634 75.811 ;
     RECT  33.696 75.739 46.818 75.811 ;
     RECT  0.036 75.775 0.63 75.821 ;
     RECT  0.036 75.821 0.558 75.884 ;
     RECT  49.608 75.731 49.662 75.917 ;
     RECT  7.668 75.191 16.938 75.931 ;
     RECT  4.248 75.775 6.786 75.937 ;
     RECT  7.56 75.931 16.938 75.937 ;
     RECT  17.676 75.191 22.41 76.009 ;
     RECT  23.256 75.775 28.53 76.009 ;
     RECT  29.415 74.957 30.726 76.009 ;
     RECT  48.06 75.803 48.597 76.009 ;
     RECT  50.688 74.189 50.706 76.009 ;
     RECT  31.824 75.811 46.818 76.037 ;
     RECT  38.772 76.037 46.818 76.073 ;
     RECT  4.248 75.937 16.938 76.081 ;
     RECT  17.676 76.009 30.726 76.081 ;
     RECT  50.688 76.009 50.742 76.081 ;
     RECT  3.888 76.081 30.726 76.171 ;
     RECT  31.824 76.037 37.962 76.171 ;
     RECT  3.816 76.171 37.962 76.199 ;
     RECT  0.108 75.884 0.558 76.205 ;
     RECT  47.628 76.009 48.597 76.307 ;
     RECT  0.252 76.205 0.558 76.349 ;
     RECT  3.816 76.199 20.142 76.469 ;
     RECT  3.816 76.469 19.17 76.505 ;
     RECT  2.304 75.811 2.862 76.621 ;
     RECT  3.816 76.505 19.098 76.621 ;
     RECT  50.148 76.081 50.742 76.637 ;
     RECT  2.304 76.621 19.098 76.649 ;
     RECT  38.772 76.073 46.242 76.739 ;
     RECT  2.304 76.649 14.922 76.747 ;
     RECT  15.732 76.649 19.098 76.811 ;
     RECT  38.772 76.739 44.262 76.843 ;
     RECT  1.98 76.747 14.922 76.883 ;
     RECT  15.732 76.811 18.99 76.883 ;
     RECT  45.072 76.739 46.242 76.891 ;
     RECT  1.98 76.883 3.582 76.925 ;
     RECT  45.072 76.891 46.602 76.981 ;
     RECT  47.448 76.621 47.466 76.981 ;
     RECT  48.315 76.307 48.597 76.981 ;
     RECT  4.716 76.883 14.922 77.009 ;
     RECT  19.908 76.469 20.142 77.017 ;
     RECT  20.916 76.199 37.962 77.017 ;
     RECT  48.315 76.981 48.978 77.035 ;
     RECT  50.148 76.637 50.166 77.035 ;
     RECT  4.716 77.009 12.294 77.045 ;
     RECT  45.072 76.981 47.466 77.053 ;
     RECT  48.315 77.035 50.166 77.053 ;
     RECT  4.716 77.045 12.15 77.117 ;
     RECT  13.032 77.009 14.922 77.117 ;
     RECT  45.072 77.053 50.166 77.117 ;
     RECT  0.468 76.349 0.558 77.131 ;
     RECT  19.908 77.017 37.962 77.161 ;
     RECT  38.736 76.843 44.262 77.161 ;
     RECT  6.3 77.117 12.15 77.279 ;
     RECT  51.732 77.179 51.75 77.315 ;
     RECT  50.148 77.117 50.166 77.387 ;
     RECT  19.908 77.161 44.262 77.521 ;
     RECT  45.072 77.117 49.41 77.521 ;
     RECT  50.616 77.431 50.706 77.521 ;
     RECT  50.616 77.521 50.742 77.593 ;
     RECT  19.908 77.521 49.41 77.611 ;
     RECT  15.732 76.883 18.897 77.656 ;
     RECT  19.692 77.611 49.41 77.656 ;
     RECT  2.415 76.925 3.582 77.657 ;
     RECT  3.564 77.657 3.582 77.665 ;
     RECT  4.716 77.117 5.397 77.665 ;
     RECT  13.104 77.117 14.922 77.665 ;
     RECT  15.732 77.656 49.41 77.665 ;
     RECT  0.144 77.131 0.558 77.789 ;
     RECT  6.948 77.279 12.15 77.803 ;
     RECT  6.948 77.803 12.366 77.863 ;
     RECT  13.104 77.665 49.41 77.863 ;
     RECT  6.948 77.863 49.41 77.899 ;
     RECT  0.144 77.789 0.522 77.933 ;
     RECT  2.415 77.657 2.826 78.187 ;
     RECT  3.564 77.665 5.397 78.205 ;
     RECT  6.948 77.899 49.626 78.205 ;
     RECT  3.564 78.205 5.67 78.241 ;
     RECT  6.408 78.205 49.626 78.241 ;
     RECT  2.304 78.187 2.826 78.365 ;
     RECT  2.415 78.365 2.826 78.379 ;
     RECT  3.564 78.241 49.662 78.379 ;
     RECT  2.415 78.379 49.662 78.439 ;
     RECT  50.616 77.593 50.778 78.439 ;
     RECT  2.415 78.439 50.778 78.653 ;
     RECT  2.415 78.653 49.662 78.665 ;
     RECT  4.32 78.665 49.662 78.773 ;
     RECT  0.144 77.933 0.27 78.979 ;
     RECT  4.32 78.773 43.578 79.007 ;
     RECT  4.32 79.007 30.834 79.037 ;
     RECT  0.144 78.979 0.522 79.051 ;
     RECT  4.32 79.037 30.51 79.079 ;
     RECT  4.32 79.079 6.426 79.169 ;
     RECT  7.38 79.079 30.51 79.169 ;
     RECT  31.608 79.007 43.578 79.169 ;
     RECT  31.608 79.169 32.742 79.181 ;
     RECT  4.32 79.169 4.338 79.205 ;
     RECT  5.076 79.169 6.318 79.205 ;
     RECT  18.468 79.169 30.474 79.229 ;
     RECT  33.66 79.169 36.09 79.229 ;
     RECT  36.936 79.169 43.578 79.229 ;
     RECT  36.936 79.229 38.79 79.241 ;
     RECT  7.38 79.169 17.37 79.277 ;
     RECT  18.54 79.229 30.474 79.277 ;
     RECT  31.608 79.181 32.67 79.277 ;
     RECT  33.66 79.229 35.19 79.277 ;
     RECT  35.964 79.229 36.09 79.277 ;
     RECT  39.528 79.229 43.578 79.277 ;
     RECT  7.38 79.277 14.922 79.313 ;
     RECT  7.815 79.313 14.922 79.325 ;
     RECT  5.076 79.205 5.397 79.439 ;
     RECT  9.72 79.325 14.922 79.439 ;
     RECT  18.54 79.277 30.438 79.439 ;
     RECT  34.776 79.277 35.19 79.439 ;
     RECT  39.528 79.277 41.31 79.439 ;
     RECT  44.388 78.773 49.662 79.439 ;
     RECT  13.215 79.439 14.922 79.475 ;
     RECT  15.915 79.277 17.118 79.475 ;
     RECT  18.54 79.439 22.41 79.475 ;
     RECT  23.976 79.439 25.29 79.475 ;
     RECT  33.66 79.277 33.966 79.475 ;
     RECT  36.936 79.241 38.502 79.475 ;
     RECT  39.528 79.439 41.13 79.475 ;
     RECT  1.656 78.943 1.674 79.483 ;
     RECT  2.415 78.665 3.546 79.483 ;
     RECT  45.072 79.439 49.662 79.517 ;
     RECT  7.815 79.325 8.982 79.547 ;
     RECT  14.832 79.475 14.922 79.547 ;
     RECT  26.244 79.439 28.026 79.547 ;
     RECT  29.088 79.439 30.438 79.547 ;
     RECT  33.948 79.475 33.966 79.547 ;
     RECT  39.528 79.475 40.497 79.547 ;
     RECT  17.1 79.475 17.118 79.565 ;
     RECT  26.532 79.547 28.026 79.565 ;
     RECT  7.815 79.547 8.262 79.583 ;
     RECT  29.088 79.547 30.33 79.583 ;
     RECT  42.228 79.277 43.578 79.591 ;
     RECT  13.215 79.475 13.626 79.619 ;
     RECT  46.872 79.517 49.662 79.619 ;
     RECT  0.144 79.051 0.558 79.661 ;
     RECT  18.54 79.475 21.654 79.661 ;
     RECT  5.115 79.439 5.397 79.667 ;
     RECT  7.815 79.583 8.097 79.667 ;
     RECT  10.515 79.439 10.797 79.667 ;
     RECT  13.215 79.619 13.497 79.667 ;
     RECT  15.915 79.475 16.197 79.667 ;
     RECT  24.015 79.475 24.297 79.667 ;
     RECT  29.088 79.583 29.697 79.667 ;
     RECT  31.608 79.277 32.397 79.667 ;
     RECT  34.776 79.439 35.097 79.667 ;
     RECT  39.564 79.547 40.497 79.667 ;
     RECT  45.072 79.517 45.897 79.667 ;
     RECT  6.228 79.205 6.318 79.709 ;
     RECT  11.7 79.439 12.042 79.709 ;
     RECT  18.54 79.661 19.71 79.709 ;
     RECT  20.484 79.661 21.654 79.709 ;
     RECT  37.044 79.475 38.502 79.709 ;
     RECT  42.228 79.591 43.83 79.709 ;
     RECT  47.088 79.619 49.662 79.709 ;
     RECT  18.615 79.709 19.566 79.715 ;
     RECT  47.088 79.709 47.106 79.715 ;
     RECT  12.024 79.709 12.042 79.745 ;
     RECT  20.952 79.709 21.654 79.745 ;
     RECT  25.272 79.475 25.29 79.745 ;
     RECT  29.088 79.667 29.505 79.745 ;
     RECT  36 79.277 36.09 79.745 ;
     RECT  37.044 79.709 38.466 79.745 ;
     RECT  42.228 79.709 43.686 79.745 ;
     RECT  48.096 79.709 49.662 79.745 ;
     RECT  37.044 79.745 37.605 79.757 ;
     RECT  15.915 79.667 16.074 79.781 ;
     RECT  18.615 79.715 19.422 79.781 ;
     RECT  34.776 79.667 34.905 79.781 ;
     RECT  36.072 79.745 36.09 79.781 ;
     RECT  38.448 79.745 38.466 79.781 ;
     RECT  42.228 79.745 43.005 79.781 ;
     RECT  45.072 79.667 45.705 79.781 ;
     RECT  26.532 79.565 27.594 79.805 ;
     RECT  48.315 79.745 49.662 79.805 ;
     RECT  42.48 79.781 43.005 79.889 ;
     RECT  1.656 79.483 3.546 79.937 ;
     RECT  5.115 79.667 5.205 79.937 ;
     RECT  7.815 79.667 7.905 79.937 ;
     RECT  10.515 79.667 10.605 79.937 ;
     RECT  13.215 79.667 13.305 79.937 ;
     RECT  15.915 79.781 16.005 79.937 ;
     RECT  18.615 79.781 18.705 79.937 ;
     RECT  24.015 79.667 24.105 79.937 ;
     RECT  29.415 79.745 29.505 79.937 ;
     RECT  31.608 79.667 32.205 79.937 ;
     RECT  34.815 79.781 34.905 79.937 ;
     RECT  37.515 79.757 37.605 79.937 ;
     RECT  39.564 79.667 40.305 79.937 ;
     RECT  42.915 79.889 43.005 79.937 ;
     RECT  45.36 79.781 45.705 79.937 ;
     RECT  48.315 79.805 49.626 79.937 ;
     RECT  0.504 79.661 0.558 79.949 ;
     RECT  50.688 78.653 50.778 79.949 ;
     RECT  0.504 79.949 0.522 80.093 ;
     RECT  45.36 79.937 45.558 80.093 ;
     RECT  39.564 79.937 39.582 80.237 ;
     RECT  26.532 79.805 26.874 80.381 ;
     RECT  48.672 79.937 49.626 80.381 ;
     RECT  2.808 79.937 3.546 80.525 ;
     RECT  50.688 79.949 50.706 80.525 ;
     RECT  2.808 80.525 2.826 80.669 ;
     RECT  45.36 80.093 45.486 80.669 ;
     RECT  31.608 79.937 31.626 80.813 ;
     RECT  48.672 80.381 49.554 80.813 ;
     RECT  21.24 79.745 21.654 80.905 ;
     RECT  26.856 80.381 26.874 80.933 ;
     RECT  5.148 80.905 5.166 80.957 ;
     RECT  9.108 80.905 9.198 80.957 ;
     RECT  13.068 80.905 13.086 80.957 ;
     RECT  17.1 80.905 17.118 80.957 ;
     RECT  21.024 80.905 21.654 80.957 ;
     RECT  25.056 80.905 25.146 80.957 ;
     RECT  49.536 80.813 49.554 80.957 ;
     RECT  1.656 79.937 1.71 81.101 ;
     RECT  48.672 80.813 48.69 81.101 ;
     RECT  1.656 81.101 1.674 81.245 ;
     RECT  45.36 80.669 45.378 81.245 ;
     RECT  21.24 80.957 21.654 82.049 ;
     RECT  21.276 82.049 21.51 82.061 ;
    LAYER M4 ;
     RECT  0.025 60.864 0.06 60.888 ;
     RECT  0.06 21.456 0.385 23.64 ;
     RECT  0.06 53.712 0.569 81.24 ;
     RECT  0.569 53.856 1.145 81.24 ;
     RECT  1.145 60.672 1.685 81.24 ;
     RECT  1.685 60.672 1.721 81.096 ;
     RECT  0.385 21.456 2.401 23.688 ;
     RECT  0.06 0.72 2.408 19.032 ;
     RECT  2.401 21.168 2.408 23.688 ;
     RECT  0.06 24.912 2.408 52.44 ;
     RECT  1.145 53.856 2.408 59.544 ;
     RECT  1.721 60.672 2.408 80.952 ;
     RECT  2.408 0.72 2.704 80.952 ;
     RECT  2.704 31.824 2.837 59.544 ;
     RECT  2.837 33.888 2.909 59.544 ;
     RECT  2.704 24.864 2.963 28.296 ;
     RECT  2.704 0.72 3.089 23.832 ;
     RECT  2.909 34.128 3.155 59.544 ;
     RECT  3.155 53.856 3.269 59.544 ;
     RECT  2.704 29.52 3.341 29.784 ;
     RECT  2.837 31.824 3.436 32.808 ;
     RECT  3.436 31.824 3.697 32.472 ;
     RECT  2.963 24.864 3.949 26.808 ;
     RECT  2.963 27.936 3.949 28.296 ;
     RECT  3.155 34.128 3.949 52.296 ;
     RECT  2.704 60.624 3.949 80.952 ;
     RECT  3.697 31.392 4.025 32.472 ;
     RECT  3.341 29.616 4.057 29.784 ;
     RECT  3.089 0.72 4.237 20.376 ;
     RECT  3.089 21.456 4.237 23.832 ;
     RECT  3.949 33.936 4.273 52.296 ;
     RECT  3.949 24.864 4.357 28.296 ;
     RECT  3.269 53.856 4.381 59.496 ;
     RECT  3.949 60.576 4.381 80.952 ;
     RECT  4.273 33.696 4.501 52.296 ;
     RECT  4.057 29.616 4.556 30.072 ;
     RECT  4.025 31.392 4.556 32.088 ;
     RECT  4.501 33.696 4.556 52.728 ;
     RECT  4.381 53.856 4.556 80.952 ;
     RECT  4.237 0.72 4.597 23.832 ;
     RECT  4.357 24.864 4.597 28.488 ;
     RECT  4.556 29.616 4.885 32.088 ;
     RECT  4.556 33.696 4.921 80.952 ;
     RECT  4.597 0.72 5.108 28.488 ;
     RECT  4.885 29.52 5.108 32.088 ;
     RECT  4.921 33.6 5.108 80.952 ;
     RECT  5.108 0.72 5.177 80.952 ;
     RECT  5.177 0.72 5.404 80.808 ;
     RECT  5.404 20.16 5.429 27.912 ;
     RECT  5.429 26.4 5.645 27.912 ;
     RECT  5.404 0.72 5.681 19.176 ;
     RECT  5.429 20.16 5.681 25.416 ;
     RECT  5.681 11.184 5.789 19.176 ;
     RECT  5.645 26.4 6.365 27.72 ;
     RECT  5.404 28.992 6.433 30.072 ;
     RECT  5.789 11.232 6.505 19.176 ;
     RECT  5.681 21.12 6.721 25.416 ;
     RECT  5.404 33.552 6.797 80.808 ;
     RECT  6.721 20.4 6.829 25.416 ;
     RECT  6.365 26.4 6.829 27.672 ;
     RECT  5.404 31.392 6.865 31.992 ;
     RECT  6.797 33.552 7.004 67.896 ;
     RECT  6.829 20.4 7.009 27.672 ;
     RECT  6.505 11.232 7.429 19.368 ;
     RECT  7.009 20.352 7.429 27.672 ;
     RECT  6.433 28.992 7.441 30.12 ;
     RECT  7.441 28.992 7.513 30.168 ;
     RECT  7.513 28.8 7.649 30.168 ;
     RECT  5.681 0.72 7.669 10.2 ;
     RECT  7.429 11.232 7.669 27.672 ;
     RECT  7.669 0.72 7.808 27.672 ;
     RECT  7.649 28.8 7.808 30.264 ;
     RECT  6.865 31.392 7.808 32.28 ;
     RECT  7.004 33.504 7.808 67.896 ;
     RECT  6.797 68.88 7.808 80.808 ;
     RECT  7.808 0.72 8.531 80.808 ;
     RECT  8.531 0.72 8.813 30.888 ;
     RECT  8.813 21.12 8.819 30.888 ;
     RECT  8.531 31.968 9.097 80.808 ;
     RECT  9.097 31.968 9.155 80.952 ;
     RECT  9.155 52.992 9.209 80.952 ;
     RECT  8.819 21.12 9.353 23.64 ;
     RECT  8.819 25.248 9.601 30.888 ;
     RECT  9.155 31.968 9.601 52.008 ;
     RECT  8.813 0.72 9.889 20.088 ;
     RECT  9.353 21.12 9.889 23.592 ;
     RECT  9.601 25.248 10.213 52.008 ;
     RECT  9.889 0.72 10.508 23.592 ;
     RECT  10.213 24.72 10.508 52.008 ;
     RECT  9.209 52.992 10.508 80.808 ;
     RECT  10.508 0.72 12.161 80.808 ;
     RECT  12.161 32.784 13.057 80.808 ;
     RECT  12.161 0.72 13.165 31.704 ;
     RECT  13.057 32.784 13.165 80.952 ;
     RECT  13.165 0.72 13.504 80.952 ;
     RECT  13.504 43.872 13.715 80.952 ;
     RECT  13.504 0.72 14.753 42.552 ;
     RECT  13.715 43.92 14.789 80.952 ;
     RECT  14.753 0.72 14.819 31.176 ;
     RECT  14.753 32.4 15.001 42.552 ;
     RECT  14.789 43.92 15.217 68.136 ;
     RECT  15.001 32.4 15.289 42.744 ;
     RECT  15.217 43.872 15.289 68.136 ;
     RECT  14.819 26.256 15.793 31.176 ;
     RECT  15.793 26.256 15.865 31.416 ;
     RECT  15.289 32.4 15.865 68.136 ;
     RECT  14.819 0.72 15.908 25.272 ;
     RECT  15.865 26.256 15.908 68.136 ;
     RECT  14.789 69.264 15.908 80.952 ;
     RECT  15.908 0.72 16.204 80.952 ;
     RECT  16.204 11.232 16.733 80.952 ;
     RECT  16.733 11.52 17.129 80.952 ;
     RECT  17.129 11.52 17.267 80.808 ;
     RECT  17.267 53.088 17.417 80.808 ;
     RECT  17.267 11.52 17.845 51.768 ;
     RECT  16.204 0.72 17.917 10.2 ;
     RECT  17.845 11.184 17.917 51.768 ;
     RECT  17.917 0.72 18.608 51.768 ;
     RECT  17.417 53.088 18.608 70.296 ;
     RECT  17.417 71.472 18.608 80.808 ;
     RECT  18.608 0.72 18.904 80.808 ;
     RECT  18.904 52.56 18.965 80.808 ;
     RECT  18.904 0.72 19.037 51.48 ;
     RECT  19.037 22.56 19.217 51.48 ;
     RECT  19.217 22.56 19.685 51.432 ;
     RECT  18.965 70.656 19.901 80.808 ;
     RECT  18.965 52.56 19.909 69.624 ;
     RECT  19.909 52.464 19.933 69.624 ;
     RECT  19.901 70.656 19.933 70.824 ;
     RECT  19.037 0.72 19.937 21.528 ;
     RECT  19.933 52.464 20.051 70.824 ;
     RECT  19.685 28.752 20.329 51.432 ;
     RECT  20.051 52.464 20.329 69.432 ;
     RECT  19.685 22.56 20.761 27.624 ;
     RECT  20.329 28.752 20.761 69.432 ;
     RECT  20.051 70.56 20.972 70.824 ;
     RECT  19.901 72 20.972 80.808 ;
     RECT  20.972 70.56 21.013 80.808 ;
     RECT  19.937 0.72 21.049 19.32 ;
     RECT  19.937 20.592 21.049 21.528 ;
     RECT  21.013 70.56 21.125 80.952 ;
     RECT  20.761 22.56 21.157 69.432 ;
     RECT  21.125 70.56 21.157 80.808 ;
     RECT  21.049 0.72 21.308 21.528 ;
     RECT  21.157 22.56 21.308 80.808 ;
     RECT  21.308 0.72 21.625 80.808 ;
     RECT  21.625 0.096 21.779 80.808 ;
     RECT  21.779 0.72 21.881 80.808 ;
     RECT  21.881 0.72 22.025 69.48 ;
     RECT  22.025 0.72 22.3 25.32 ;
     RECT  22.3 0.72 22.499 5.208 ;
     RECT  22.3 6.288 22.745 25.32 ;
     RECT  22.745 6.288 22.781 9.288 ;
     RECT  22.745 10.368 22.787 25.32 ;
     RECT  22.781 6.288 23.281 9.096 ;
     RECT  22.787 20.928 23.317 25.32 ;
     RECT  22.025 26.304 23.317 69.48 ;
     RECT  22.499 0.72 23.605 5.064 ;
     RECT  23.281 6.048 23.605 9.096 ;
     RECT  23.317 20.928 23.893 69.48 ;
     RECT  21.881 70.56 23.893 80.808 ;
     RECT  23.893 20.928 23.965 80.808 ;
     RECT  23.605 0.72 24.008 9.096 ;
     RECT  22.787 10.368 24.008 19.896 ;
     RECT  23.965 20.88 24.008 80.808 ;
     RECT  24.008 0.72 24.304 80.808 ;
     RECT  24.304 31.488 24.725 50.568 ;
     RECT  24.304 51.696 24.905 80.808 ;
     RECT  24.905 63.504 25.045 80.808 ;
     RECT  25.045 63.504 25.049 80.952 ;
     RECT  25.049 64.896 25.139 80.952 ;
     RECT  25.139 64.992 25.157 80.952 ;
     RECT  24.304 0.72 25.193 26.424 ;
     RECT  24.725 31.632 25.265 50.568 ;
     RECT  24.304 27.6 25.549 30.456 ;
     RECT  25.265 49.536 25.657 50.568 ;
     RECT  25.157 64.992 25.667 80.808 ;
     RECT  25.549 27.6 25.813 30.6 ;
     RECT  25.265 31.632 25.813 48.504 ;
     RECT  25.193 4.896 25.981 26.424 ;
     RECT  25.813 27.6 25.981 48.504 ;
     RECT  25.657 49.536 26.005 50.712 ;
     RECT  24.905 51.696 26.005 62.472 ;
     RECT  26.005 49.536 26.125 62.472 ;
     RECT  25.049 63.504 26.125 63.912 ;
     RECT  25.667 64.992 26.125 66.888 ;
     RECT  25.193 0.72 26.233 3.912 ;
     RECT  25.981 4.896 26.233 48.504 ;
     RECT  26.233 0.72 26.708 48.504 ;
     RECT  26.125 49.536 26.708 66.888 ;
     RECT  25.667 67.92 26.708 80.808 ;
     RECT  26.708 0.72 27.004 80.808 ;
     RECT  27.004 0.72 27.281 20.184 ;
     RECT  27.004 63.504 27.389 70.296 ;
     RECT  27.389 69.024 27.461 70.296 ;
     RECT  27.281 0.72 27.641 14.76 ;
     RECT  27.004 49.296 27.821 62.472 ;
     RECT  27.461 69.312 27.929 70.296 ;
     RECT  27.004 21.216 28.037 48.168 ;
     RECT  27.389 63.504 28.067 67.992 ;
     RECT  28.037 21.216 28.073 30.888 ;
     RECT  28.067 63.552 28.073 67.992 ;
     RECT  28.073 63.552 28.145 65.448 ;
     RECT  27.929 70.032 28.177 70.296 ;
     RECT  27.641 11.712 28.285 14.76 ;
     RECT  27.281 15.984 28.285 20.184 ;
     RECT  28.073 21.216 28.361 27.912 ;
     RECT  28.037 31.92 28.405 48.168 ;
     RECT  27.821 49.296 28.405 50.136 ;
     RECT  28.073 66.528 28.453 67.992 ;
     RECT  28.285 11.712 28.537 20.184 ;
     RECT  28.361 21.216 28.537 27.768 ;
     RECT  28.177 70.032 28.537 70.632 ;
     RECT  28.537 70.032 28.609 70.872 ;
     RECT  27.004 72 28.632 76.872 ;
     RECT  28.632 72 28.693 76.92 ;
     RECT  27.004 77.952 28.693 80.808 ;
     RECT  27.641 0.72 28.741 10.728 ;
     RECT  28.537 11.712 28.741 27.768 ;
     RECT  28.741 0.72 28.901 27.768 ;
     RECT  28.901 0.72 29.045 0.744 ;
     RECT  27.821 51.168 29.077 62.472 ;
     RECT  28.145 63.6 29.077 65.448 ;
     RECT  28.453 66.528 29.077 68.664 ;
     RECT  28.073 28.944 29.113 30.888 ;
     RECT  28.405 31.92 29.113 50.136 ;
     RECT  29.077 51.168 29.173 62.568 ;
     RECT  29.077 63.6 29.173 68.664 ;
     RECT  28.901 2.016 29.408 27.768 ;
     RECT  29.113 28.944 29.408 50.136 ;
     RECT  29.173 51.168 29.408 68.664 ;
     RECT  28.609 70.032 29.408 70.968 ;
     RECT  28.693 72 29.408 80.808 ;
     RECT  29.408 2.016 29.704 80.808 ;
     RECT  29.704 29.088 29.873 69.048 ;
     RECT  29.873 39.504 30.017 69.048 ;
     RECT  30.017 39.504 30.089 68.664 ;
     RECT  29.704 70.08 30.161 80.808 ;
     RECT  29.704 2.016 30.413 27.624 ;
     RECT  30.161 70.08 30.557 75.48 ;
     RECT  29.873 29.088 30.901 38.52 ;
     RECT  30.413 2.784 30.913 27.624 ;
     RECT  30.901 28.8 30.913 38.52 ;
     RECT  30.913 2.784 31.025 38.52 ;
     RECT  31.025 2.832 31.061 38.52 ;
     RECT  31.061 18.432 31.129 38.52 ;
     RECT  30.089 39.504 31.129 68.52 ;
     RECT  30.557 70.32 31.201 75.48 ;
     RECT  30.161 76.464 31.201 80.808 ;
     RECT  31.201 70.32 31.633 80.808 ;
     RECT  31.633 69.984 31.637 80.808 ;
     RECT  31.129 18.432 31.772 68.52 ;
     RECT  31.772 18.432 31.957 68.904 ;
     RECT  31.637 69.984 31.957 80.232 ;
     RECT  31.061 2.832 32.108 17.448 ;
     RECT  31.957 18.432 32.108 80.232 ;
     RECT  32.108 2.148 32.212 80.232 ;
     RECT  32.212 2.418 32.404 80.232 ;
     RECT  32.404 27.6 32.789 29.304 ;
     RECT  32.404 10.608 32.969 26.616 ;
     RECT  32.404 66.096 33.107 80.232 ;
     RECT  32.404 32.256 33.149 64.584 ;
     RECT  33.149 32.256 33.257 48.168 ;
     RECT  33.149 49.2 33.299 64.584 ;
     RECT  33.257 32.256 33.469 37.368 ;
     RECT  33.299 49.488 33.577 64.584 ;
     RECT  32.789 27.6 33.617 29.112 ;
     RECT  32.969 10.608 33.653 26.472 ;
     RECT  33.469 31.776 33.761 37.368 ;
     RECT  32.404 2.736 33.865 9.528 ;
     RECT  33.653 10.608 33.865 13.368 ;
     RECT  32.404 30.432 33.865 30.792 ;
     RECT  33.577 49.488 34.009 64.68 ;
     RECT  33.761 32.256 34.333 37.368 ;
     RECT  33.257 38.4 34.333 48.168 ;
     RECT  34.009 49.488 34.405 64.872 ;
     RECT  34.333 32.256 34.597 48.168 ;
     RECT  34.405 49.488 34.621 65.16 ;
     RECT  33.865 2.736 34.693 13.368 ;
     RECT  33.653 14.448 34.693 20.184 ;
     RECT  34.597 32.256 34.801 48.264 ;
     RECT  34.693 2.736 34.808 20.184 ;
     RECT  33.653 21.168 34.808 26.472 ;
     RECT  33.617 27.6 34.808 29.064 ;
     RECT  33.865 30.432 34.808 30.984 ;
     RECT  34.801 32.256 34.808 48.504 ;
     RECT  34.621 49.488 34.808 65.256 ;
     RECT  33.107 66.24 34.808 80.232 ;
     RECT  34.808 2.148 34.912 80.232 ;
     RECT  34.912 2.418 35.104 80.232 ;
     RECT  35.104 2.832 35.363 80.232 ;
     RECT  35.363 2.832 35.453 55.608 ;
     RECT  35.453 51.168 35.489 55.512 ;
     RECT  35.363 56.784 35.843 80.232 ;
     RECT  35.843 69.84 35.885 80.232 ;
     RECT  35.843 56.784 35.993 68.856 ;
     RECT  35.993 66.048 36.245 68.808 ;
     RECT  35.993 56.784 36.281 64.344 ;
     RECT  36.245 67.824 36.317 68.808 ;
     RECT  36.281 56.976 36.389 64.344 ;
     RECT  35.885 69.936 36.389 80.232 ;
     RECT  36.245 66.048 36.461 66.792 ;
     RECT  35.453 2.832 36.493 50.136 ;
     RECT  35.489 51.168 36.493 55.464 ;
     RECT  36.389 56.976 36.533 63.816 ;
     RECT  36.493 2.832 37.033 55.464 ;
     RECT  36.533 56.976 37.333 60.024 ;
     RECT  36.317 67.824 37.381 68.52 ;
     RECT  36.389 70.032 37.381 80.232 ;
     RECT  36.461 66.48 37.429 66.792 ;
     RECT  37.381 67.824 37.429 80.232 ;
     RECT  37.033 2.832 37.508 55.512 ;
     RECT  37.333 56.592 37.508 60.024 ;
     RECT  36.533 61.344 37.508 63.816 ;
     RECT  37.429 66.336 37.508 80.232 ;
     RECT  37.508 2.148 37.612 80.232 ;
     RECT  37.612 2.418 37.804 80.232 ;
     RECT  37.804 45.456 37.865 65.544 ;
     RECT  37.804 66.528 37.865 68.952 ;
     RECT  37.804 30.432 38.195 44.424 ;
     RECT  38.195 30.432 38.225 32.52 ;
     RECT  37.804 18.816 38.333 29.4 ;
     RECT  37.865 45.552 38.387 65.544 ;
     RECT  38.387 61.968 38.621 65.544 ;
     RECT  37.804 70.128 38.621 72.024 ;
     RECT  38.387 45.552 38.693 60.792 ;
     RECT  37.865 67.104 38.729 68.952 ;
     RECT  37.804 73.344 38.773 75.48 ;
     RECT  38.729 67.104 38.833 68.28 ;
     RECT  38.693 45.552 38.941 60.552 ;
     RECT  37.804 2.784 38.977 4.296 ;
     RECT  37.804 5.808 38.977 17.496 ;
     RECT  38.833 66.768 38.981 68.28 ;
     RECT  38.621 70.272 38.981 72.024 ;
     RECT  38.195 33.648 39.017 44.424 ;
     RECT  38.981 71.616 39.049 72.024 ;
     RECT  38.773 73.248 39.049 75.48 ;
     RECT  38.225 30.432 39.053 32.28 ;
     RECT  39.017 36.816 39.089 44.424 ;
     RECT  39.049 71.616 39.164 75.48 ;
     RECT  37.804 76.512 39.164 80.232 ;
     RECT  39.053 32.256 39.229 32.28 ;
     RECT  39.017 33.648 39.229 35.784 ;
     RECT  39.089 39.456 39.229 44.424 ;
     RECT  38.941 45.456 39.229 60.552 ;
     RECT  38.981 66.768 39.229 68.232 ;
     RECT  39.229 66.72 39.265 68.232 ;
     RECT  38.621 64.608 39.301 65.544 ;
     RECT  39.265 66.624 39.301 68.232 ;
     RECT  38.977 2.784 39.373 17.496 ;
     RECT  38.333 23.904 39.553 29.4 ;
     RECT  39.164 71.616 39.593 80.232 ;
     RECT  38.333 18.816 39.769 22.872 ;
     RECT  38.981 70.272 39.781 70.392 ;
     RECT  39.373 2.496 39.913 17.496 ;
     RECT  39.769 18.48 39.913 22.872 ;
     RECT  39.229 39.456 40.021 60.552 ;
     RECT  39.229 32.256 40.069 35.784 ;
     RECT  39.089 36.816 40.069 38.472 ;
     RECT  39.553 23.856 40.093 29.4 ;
     RECT  39.053 30.432 40.093 31.224 ;
     RECT  39.913 2.496 40.208 22.872 ;
     RECT  40.093 23.856 40.208 31.224 ;
     RECT  40.069 32.256 40.208 38.472 ;
     RECT  40.021 39.456 40.208 60.936 ;
     RECT  38.621 61.968 40.208 63.624 ;
     RECT  39.301 64.608 40.208 68.232 ;
     RECT  39.781 69.504 40.208 70.392 ;
     RECT  39.593 71.616 40.208 79.932 ;
     RECT  40.208 2.148 40.312 79.932 ;
     RECT  40.312 2.352 40.504 79.752 ;
     RECT  40.504 69.312 40.643 79.752 ;
     RECT  40.504 39.456 40.673 68.232 ;
     RECT  40.673 39.456 40.745 50.664 ;
     RECT  40.673 51.648 40.781 68.232 ;
     RECT  40.781 51.648 40.889 66.216 ;
     RECT  40.889 51.696 41.027 66.216 ;
     RECT  41.027 66.192 41.141 66.216 ;
     RECT  40.504 2.352 41.429 31.224 ;
     RECT  40.504 32.256 41.509 38.472 ;
     RECT  40.745 39.456 41.509 50.328 ;
     RECT  41.429 2.352 41.645 31.032 ;
     RECT  41.027 51.696 41.645 65.16 ;
     RECT  41.645 56.304 41.651 65.16 ;
     RECT  40.643 69.312 41.681 72.888 ;
     RECT  41.645 2.352 41.717 3.72 ;
     RECT  41.651 56.832 41.717 65.16 ;
     RECT  41.717 56.832 41.753 65.016 ;
     RECT  40.781 67.296 41.785 68.232 ;
     RECT  41.509 32.256 41.821 50.328 ;
     RECT  41.645 4.752 41.825 31.032 ;
     RECT  41.825 27.312 41.861 31.032 ;
     RECT  41.825 5.04 41.891 26.328 ;
     RECT  41.861 29.472 41.933 31.032 ;
     RECT  41.785 67.248 42.037 68.232 ;
     RECT  40.643 74.016 42.073 79.752 ;
     RECT  42.037 66.624 42.253 68.232 ;
     RECT  41.681 71.472 42.277 72.888 ;
     RECT  42.073 73.92 42.277 79.752 ;
     RECT  42.253 66.528 42.325 68.232 ;
     RECT  41.821 32.256 42.541 50.424 ;
     RECT  41.645 51.696 42.541 55.32 ;
     RECT  42.325 66.096 42.541 68.232 ;
     RECT  41.681 69.312 42.541 70.104 ;
     RECT  42.541 66.096 42.757 70.104 ;
     RECT  41.717 2.352 42.908 3.432 ;
     RECT  41.891 5.04 42.908 7.752 ;
     RECT  41.891 8.736 42.908 26.328 ;
     RECT  41.861 27.312 42.908 28.296 ;
     RECT  41.933 29.472 42.908 30.888 ;
     RECT  42.541 32.256 42.908 55.32 ;
     RECT  41.753 56.832 42.908 64.728 ;
     RECT  42.757 66.048 42.908 70.104 ;
     RECT  42.277 71.472 42.908 79.752 ;
     RECT  42.908 2.148 43.012 79.932 ;
     RECT  43.012 2.418 43.204 79.704 ;
     RECT  43.204 54 43.265 55.224 ;
     RECT  43.204 74.064 43.265 79.704 ;
     RECT  43.204 25.728 43.373 32.856 ;
     RECT  43.204 38.448 43.373 47.928 ;
     RECT  43.265 74.064 43.379 77.064 ;
     RECT  43.204 17.616 43.409 24.504 ;
     RECT  43.204 72 43.475 72.84 ;
     RECT  43.204 67.248 43.516 69.864 ;
     RECT  43.204 34.992 43.625 37.08 ;
     RECT  43.409 17.616 43.661 17.736 ;
     RECT  43.204 2.88 43.689 2.904 ;
     RECT  43.373 26.16 43.697 32.856 ;
     RECT  43.516 67.248 43.697 69.096 ;
     RECT  43.379 75.12 43.697 77.064 ;
     RECT  43.265 78.144 43.697 79.704 ;
     RECT  43.204 4.08 43.708 5.064 ;
     RECT  43.697 26.16 43.733 29.064 ;
     RECT  43.697 30.144 43.733 32.856 ;
     RECT  43.373 38.448 43.733 44.712 ;
     RECT  43.204 66.048 43.769 66.072 ;
     RECT  43.708 5.04 43.805 5.064 ;
     RECT  43.204 8.304 43.811 16.488 ;
     RECT  43.697 75.12 43.841 76.536 ;
     RECT  43.204 57.84 43.877 63.624 ;
     RECT  43.811 11.712 43.907 16.488 ;
     RECT  43.475 72 43.913 72.408 ;
     RECT  43.841 75.12 43.913 76.392 ;
     RECT  43.907 15.456 43.948 16.488 ;
     RECT  43.811 8.832 43.949 8.856 ;
     RECT  43.733 26.16 43.955 28.536 ;
     RECT  43.204 51.696 44.003 53.016 ;
     RECT  43.811 10.032 44.021 10.056 ;
     RECT  43.955 26.16 44.021 26.328 ;
     RECT  43.733 30.144 44.021 32.472 ;
     RECT  43.265 54 44.051 55.128 ;
     RECT  43.913 72 44.057 72.024 ;
     RECT  43.409 18.72 44.092 24.504 ;
     RECT  44.092 18.72 44.093 22.872 ;
     RECT  44.021 30.144 44.093 31.944 ;
     RECT  43.907 11.712 44.129 13.368 ;
     RECT  43.204 33.888 44.197 33.912 ;
     RECT  43.877 58.656 44.197 63.624 ;
     RECT  43.204 64.704 44.197 64.728 ;
     RECT  44.021 26.16 44.201 26.184 ;
     RECT  44.093 30.144 44.201 31.56 ;
     RECT  44.093 18.72 44.237 21.528 ;
     RECT  44.201 30.144 44.237 30.456 ;
     RECT  43.733 38.448 44.345 42.84 ;
     RECT  43.697 67.248 44.345 68.232 ;
     RECT  44.092 23.904 44.377 24.504 ;
     RECT  43.948 16.032 44.417 16.488 ;
     RECT  44.197 33.648 44.453 33.912 ;
     RECT  44.197 58.656 44.485 64.728 ;
     RECT  44.003 51.936 44.531 53.016 ;
     RECT  44.129 11.712 44.561 12.552 ;
     RECT  44.345 38.448 44.561 39.048 ;
     RECT  44.485 58.656 44.605 65.352 ;
     RECT  43.661 17.712 44.629 17.736 ;
     RECT  44.237 18.72 44.629 18.84 ;
     RECT  43.733 43.824 44.629 44.712 ;
     RECT  43.373 45.744 44.629 47.928 ;
     RECT  44.051 54.384 44.773 55.128 ;
     RECT  43.204 48.912 44.809 50.328 ;
     RECT  44.629 43.824 44.845 47.928 ;
     RECT  44.809 48.912 44.845 50.616 ;
     RECT  43.913 75.12 44.881 75.768 ;
     RECT  44.377 23.904 44.953 24.648 ;
     RECT  44.701 71.28 44.965 71.304 ;
     RECT  43.379 74.064 44.972 74.088 ;
     RECT  44.881 75.12 44.972 75.816 ;
     RECT  44.413 2.736 44.989 2.808 ;
     RECT  44.531 51.936 44.989 52.488 ;
     RECT  43.907 14.4 45.013 14.472 ;
     RECT  44.444 57.024 45.097 57.048 ;
     RECT  44.972 74.064 45.157 75.816 ;
     RECT  45.097 56.544 45.169 57.048 ;
     RECT  44.453 33.648 45.277 33.672 ;
     RECT  45.349 81.216 45.457 81.24 ;
     RECT  44.093 22.56 45.493 22.872 ;
     RECT  44.953 23.904 45.493 25.32 ;
     RECT  44.989 2.256 45.529 2.808 ;
     RECT  43.697 78.144 45.529 79.224 ;
     RECT  45.457 80.64 45.529 81.24 ;
     RECT  44.629 69.504 45.601 69.528 ;
     RECT  44.965 70.656 45.601 71.304 ;
     RECT  45.529 1.728 45.608 2.808 ;
     RECT  43.204 6.816 45.608 7.224 ;
     RECT  44.917 10.416 45.608 11.4 ;
     RECT  44.561 12.48 45.608 12.552 ;
     RECT  45.013 14.064 45.608 14.472 ;
     RECT  44.417 16.368 45.608 16.488 ;
     RECT  44.629 17.712 45.608 18.84 ;
     RECT  44.237 19.92 45.608 21.528 ;
     RECT  45.493 22.56 45.608 25.32 ;
     RECT  43.955 27.6 45.608 28.536 ;
     RECT  44.237 30.432 45.608 30.456 ;
     RECT  44.201 31.536 45.608 31.56 ;
     RECT  45.277 33.36 45.608 33.672 ;
     RECT  43.625 35.76 45.608 37.08 ;
     RECT  44.561 38.448 45.608 38.472 ;
     RECT  44.345 40.032 45.608 42.84 ;
     RECT  44.845 43.824 45.608 50.616 ;
     RECT  44.989 51.744 45.608 52.488 ;
     RECT  44.773 54.384 45.608 55.176 ;
     RECT  45.169 56.544 45.608 57.336 ;
     RECT  44.605 59.472 45.608 65.352 ;
     RECT  44.345 67.296 45.608 68.232 ;
     RECT  45.601 69.504 45.608 71.304 ;
     RECT  45.157 74.064 45.608 76.728 ;
     RECT  45.529 78.144 45.608 81.24 ;
     RECT  45.608 1.728 45.904 81.24 ;
     RECT  45.904 59.232 45.929 61.656 ;
     RECT  45.904 78.192 45.965 81.24 ;
     RECT  45.929 59.232 46.001 60.936 ;
     RECT  45.904 65.184 46.001 66.072 ;
     RECT  45.904 6.816 46.019 7.416 ;
     RECT  45.904 41.952 46.019 43.32 ;
     RECT  45.904 54.624 46.019 57.336 ;
     RECT  45.904 67.296 46.019 70.296 ;
     RECT  46.019 56.448 46.037 57.336 ;
     RECT  45.904 10.224 46.073 10.44 ;
     RECT  45.904 1.728 46.109 4.536 ;
     RECT  45.904 38.016 46.181 39.384 ;
     RECT  45.904 18.144 46.211 18.84 ;
     RECT  45.904 22.56 46.253 24.504 ;
     RECT  46.019 7.056 46.289 7.416 ;
     RECT  45.904 15.408 46.361 17.112 ;
     RECT  46.361 16.56 46.397 17.112 ;
     RECT  45.904 29.616 46.397 32.376 ;
     RECT  46.037 56.448 46.397 56.904 ;
     RECT  46.019 67.296 46.397 68.808 ;
     RECT  46.019 69.984 46.397 70.008 ;
     RECT  45.904 40.944 46.433 40.968 ;
     RECT  46.397 67.776 46.441 68.808 ;
     RECT  46.073 10.224 46.451 10.248 ;
     RECT  46.211 18.24 46.577 18.84 ;
     RECT  45.965 78.624 46.646 81.24 ;
     RECT  46.577 18.24 46.685 18.264 ;
     RECT  46.253 22.8 46.691 24.504 ;
     RECT  46.397 31.296 46.691 32.376 ;
     RECT  46.181 38.16 46.693 39.384 ;
     RECT  45.904 46.128 46.721 51.768 ;
     RECT  45.904 36.192 46.729 36.264 ;
     RECT  45.904 20.208 46.739 21.528 ;
     RECT  45.904 75.072 46.739 75.768 ;
     RECT  46.289 7.056 46.757 7.08 ;
     RECT  46.361 15.408 46.829 15.432 ;
     RECT  46.019 54.624 46.829 55.032 ;
     RECT  46.397 29.616 46.835 30.216 ;
     RECT  45.904 26.928 46.865 28.488 ;
     RECT  46.109 2.736 46.937 4.248 ;
     RECT  46.865 26.928 46.937 26.952 ;
     RECT  46.829 55.008 46.937 55.032 ;
     RECT  46.739 75.072 46.937 75.288 ;
     RECT  46.397 56.88 47.027 56.904 ;
     RECT  45.904 52.896 47.041 53.448 ;
     RECT  46.691 31.296 47.045 32.04 ;
     RECT  46.721 46.128 47.045 48.408 ;
     RECT  45.904 8.832 47.077 8.856 ;
     RECT  47.077 8.832 47.117 9.144 ;
     RECT  46.739 20.592 47.153 21.528 ;
     RECT  45.904 25.584 47.153 25.608 ;
     RECT  45.904 63.216 47.173 63.816 ;
     RECT  46.693 38.16 47.189 38.616 ;
     RECT  47.173 63.216 47.219 64.584 ;
     RECT  46.109 1.728 47.221 1.752 ;
     RECT  46.937 2.736 47.221 3.96 ;
     RECT  46.729 36.192 47.221 36.216 ;
     RECT  47.221 35.664 47.267 36.216 ;
     RECT  46.019 41.952 47.297 42.552 ;
     RECT  46.441 68.16 47.317 68.808 ;
     RECT  47.117 9.12 47.333 9.144 ;
     RECT  47.219 63.216 47.333 63.24 ;
     RECT  45.904 73.968 47.333 73.992 ;
     RECT  46.691 22.8 47.653 23.928 ;
     RECT  47.276 77.232 47.653 77.256 ;
     RECT  46.646 78.672 47.653 81.24 ;
     RECT  47.221 1.728 48.308 3.96 ;
     RECT  45.904 12.528 48.308 12.552 ;
     RECT  46.397 16.56 48.308 16.584 ;
     RECT  47.153 20.592 48.308 20.616 ;
     RECT  47.653 22.032 48.308 23.928 ;
     RECT  47.045 31.296 48.308 31.32 ;
     RECT  47.653 32.496 48.308 32.52 ;
     RECT  47.413 34.512 48.308 34.536 ;
     RECT  47.267 35.664 48.308 35.688 ;
     RECT  47.189 38.16 48.308 38.184 ;
     RECT  47.077 40.464 48.308 40.488 ;
     RECT  47.297 42.528 48.308 42.552 ;
     RECT  47.045 46.128 48.308 46.632 ;
     RECT  47.045 47.856 48.308 48.408 ;
     RECT  46.721 50.112 48.308 51.768 ;
     RECT  47.041 52.896 48.308 53.592 ;
     RECT  46.001 59.232 48.308 60.12 ;
     RECT  47.219 64.56 48.308 64.584 ;
     RECT  47.317 68.16 48.308 69 ;
     RECT  46.937 75.264 48.308 75.288 ;
     RECT  47.653 77.232 48.308 81.24 ;
     RECT  48.308 1.728 48.604 81.24 ;
     RECT  48.604 7.92 49.597 7.944 ;
     RECT  48.604 9.504 49.597 9.528 ;
     RECT  48.604 11.952 49.597 13.704 ;
     RECT  48.604 21.744 49.597 21.768 ;
     RECT  48.604 30.24 49.597 30.264 ;
     RECT  48.604 34.848 49.597 34.872 ;
     RECT  48.604 46.608 49.597 48.12 ;
     RECT  48.604 51.744 49.597 51.768 ;
     RECT  48.604 70.56 49.597 70.584 ;
     RECT  48.604 74.736 49.597 75.336 ;
     RECT  48.604 78.912 49.597 81.24 ;
     RECT  49.597 66.096 49.633 70.872 ;
     RECT  49.597 34.848 49.669 35.448 ;
     RECT  49.597 51.744 49.669 52.584 ;
     RECT  48.604 63.936 49.669 64.536 ;
     RECT  49.633 66.096 49.669 71.304 ;
     RECT  49.669 34.416 49.705 35.448 ;
     RECT  49.669 55.008 49.705 55.752 ;
     RECT  49.669 63.936 49.705 71.304 ;
     RECT  49.597 72.432 49.705 72.888 ;
     RECT  48.604 6.768 49.741 6.792 ;
     RECT  49.597 7.92 49.741 9.528 ;
     RECT  49.669 51.696 49.741 52.584 ;
     RECT  48.604 53.568 49.741 53.592 ;
     RECT  49.705 55.008 49.741 56.472 ;
     RECT  49.597 5.04 49.777 5.208 ;
     RECT  48.604 25.488 49.777 28.248 ;
     RECT  49.705 33.696 49.777 35.448 ;
     RECT  49.597 46.512 49.777 48.408 ;
     RECT  48.604 1.728 49.813 3.912 ;
     RECT  49.777 5.04 49.813 5.496 ;
     RECT  49.741 6.768 49.813 9.528 ;
     RECT  49.597 19.584 49.813 19.608 ;
     RECT  49.597 21.312 49.813 21.768 ;
     RECT  48.604 39.168 49.813 39.192 ;
     RECT  48.604 40.176 49.813 40.2 ;
     RECT  49.597 41.328 49.813 41.928 ;
     RECT  48.604 44.64 49.813 45.384 ;
     RECT  49.777 46.368 49.813 48.408 ;
     RECT  48.604 50.112 49.813 50.712 ;
     RECT  49.741 51.696 49.813 53.592 ;
     RECT  49.813 19.584 49.849 21.768 ;
     RECT  49.813 32.688 49.849 32.712 ;
     RECT  49.777 33.696 49.849 36.024 ;
     RECT  49.813 1.728 49.957 9.528 ;
     RECT  49.597 11.376 50.101 13.704 ;
     RECT  49.597 60.336 50.101 60.36 ;
     RECT  49.705 63.936 50.101 72.888 ;
     RECT  49.957 0.864 50.137 9.528 ;
     RECT  50.101 11.376 50.137 14.136 ;
     RECT  49.777 15.12 50.137 15.432 ;
     RECT  48.604 16.416 50.137 17.016 ;
     RECT  49.597 18.576 50.137 18.6 ;
     RECT  49.597 23.616 50.137 23.64 ;
     RECT  49.777 24.624 50.137 28.248 ;
     RECT  49.597 29.952 50.137 30.264 ;
     RECT  49.849 32.688 50.137 36.024 ;
     RECT  48.604 37.008 50.137 37.32 ;
     RECT  49.813 39.168 50.137 40.2 ;
     RECT  49.813 41.328 50.137 42.504 ;
     RECT  49.813 44.64 50.137 48.408 ;
     RECT  49.741 55.008 50.137 56.616 ;
     RECT  50.101 60.048 50.137 60.36 ;
     RECT  50.101 63.36 50.137 72.888 ;
     RECT  49.597 74.592 50.137 75.912 ;
     RECT  49.597 77.04 50.137 77.064 ;
     RECT  50.137 0.72 50.173 10.392 ;
     RECT  50.137 11.376 50.173 18.6 ;
     RECT  49.849 19.584 50.173 22.2 ;
     RECT  50.137 23.184 50.173 28.248 ;
     RECT  50.137 29.952 50.173 31.128 ;
     RECT  50.137 32.688 50.173 42.936 ;
     RECT  50.137 44.208 50.173 48.84 ;
     RECT  50.137 54.864 50.173 56.616 ;
     RECT  50.137 63.216 50.173 72.888 ;
     RECT  50.137 74.592 50.173 77.352 ;
     RECT  50.173 62.928 50.605 77.352 ;
     RECT  49.597 78.336 50.605 81.24 ;
     RECT  50.173 29.952 50.641 48.84 ;
     RECT  49.813 50.112 50.641 53.592 ;
     RECT  50.173 54.864 50.641 57.048 ;
     RECT  50.641 29.952 50.677 57.048 ;
     RECT  50.137 58.32 50.677 60.36 ;
     RECT  50.173 0.72 51.804 28.248 ;
     RECT  50.677 29.52 51.804 57.048 ;
     RECT  50.677 58.32 51.804 60.504 ;
     RECT  50.605 62.928 51.804 81.24 ;
    LAYER M5 ;
     RECT  20.88 0.016 21.768 0.131 ;
     RECT  2.4 2.137 2.52 2.151 ;
     RECT  5.1 2.137 5.22 2.151 ;
     RECT  7.8 2.137 7.92 2.151 ;
     RECT  10.5 2.137 10.62 2.151 ;
     RECT  13.2 2.137 13.32 2.151 ;
     RECT  15.9 2.137 16.02 2.151 ;
     RECT  18.6 2.137 18.72 2.151 ;
     RECT  24 2.137 24.12 2.151 ;
     RECT  26.7 2.137 26.82 2.151 ;
     RECT  29.4 2.137 29.52 2.151 ;
     RECT  32.1 2.137 32.22 2.151 ;
     RECT  34.8 2.137 34.92 2.151 ;
     RECT  37.5 2.137 37.62 2.151 ;
     RECT  40.2 2.137 40.32 2.151 ;
     RECT  42.9 2.137 43.02 2.151 ;
     RECT  45.6 2.137 45.72 2.151 ;
     RECT  48.3 2.137 48.42 2.151 ;
     RECT  29.4 2.151 29.712 2.485 ;
     RECT  20.88 0.131 21.624 2.581 ;
     RECT  40.2 2.151 40.512 2.581 ;
     RECT  18.6 2.151 18.912 2.629 ;
     RECT  13.2 2.151 13.512 2.773 ;
     RECT  24 2.151 24.312 2.773 ;
     RECT  37.5 2.151 37.812 2.773 ;
     RECT  13.2 2.773 13.8 2.821 ;
     RECT  24 2.773 24.936 2.821 ;
     RECT  15.9 2.151 16.212 2.869 ;
     RECT  42.9 2.151 43.212 2.869 ;
     RECT  40.08 2.581 40.512 3.061 ;
     RECT  7.8 2.151 8.112 3.301 ;
     RECT  7.68 3.301 8.112 3.397 ;
     RECT  13.2 2.821 14.232 3.397 ;
     RECT  15.9 2.869 16.488 3.397 ;
     RECT  32.1 2.151 32.412 3.397 ;
     RECT  40.08 3.061 40.728 3.443 ;
     RECT  28.704 2.485 29.712 3.539 ;
     RECT  32.1 3.397 33.096 3.539 ;
     RECT  20.88 2.581 22.488 3.589 ;
     RECT  34.8 2.151 35.112 3.685 ;
     RECT  17.808 2.629 18.912 3.877 ;
     RECT  20.544 3.589 22.488 3.877 ;
     RECT  10.5 2.151 10.812 3.925 ;
     RECT  17.808 3.877 22.488 3.925 ;
     RECT  29.4 3.539 29.712 3.973 ;
     RECT  42.9 2.869 43.656 4.115 ;
     RECT  17.568 3.925 22.488 4.163 ;
     RECT  37.5 2.773 38.28 4.307 ;
     RECT  10.368 3.925 10.812 4.453 ;
     RECT  45.6 2.151 45.912 4.501 ;
     RECT  13.2 3.397 16.488 4.643 ;
     RECT  29.4 3.973 30.648 4.645 ;
     RECT  7.536 3.397 8.232 4.789 ;
     RECT  24 2.821 25.704 4.931 ;
     RECT  34.8 3.685 35.208 5.029 ;
     RECT  28.752 4.645 30.648 5.123 ;
     RECT  34.8 5.029 35.256 5.125 ;
     RECT  37.5 4.307 37.812 5.125 ;
     RECT  20.88 4.163 22.488 5.219 ;
     RECT  29.4 5.123 30.648 5.219 ;
     RECT  40.08 3.443 40.512 5.221 ;
     RECT  40.08 5.221 41.064 5.411 ;
     RECT  7.008 4.789 8.232 5.747 ;
     RECT  36.864 5.125 37.812 5.747 ;
     RECT  17.568 4.163 19.608 5.749 ;
     RECT  20.88 5.219 22.248 5.749 ;
     RECT  5.1 2.151 5.412 6.085 ;
     RECT  40.08 5.411 40.512 6.085 ;
     RECT  26.7 2.151 27.012 6.133 ;
     RECT  9.888 4.453 10.812 6.277 ;
     RECT  25.68 4.931 25.704 6.323 ;
     RECT  34.8 5.125 35.352 6.613 ;
     RECT  26.7 6.133 27.672 6.757 ;
     RECT  4.128 6.085 5.412 6.805 ;
     RECT  13.2 4.643 14.904 6.805 ;
     RECT  15.9 4.643 16.488 6.805 ;
     RECT  3.936 6.805 5.412 6.899 ;
     RECT  32.1 3.539 32.412 6.901 ;
     RECT  12.144 5.605 12.168 6.949 ;
     RECT  13.2 6.805 16.488 6.949 ;
     RECT  39.888 6.085 40.512 6.949 ;
     RECT  12.144 6.949 16.488 7.043 ;
     RECT  17.568 5.749 22.248 7.043 ;
     RECT  42.9 4.115 43.212 7.189 ;
     RECT  25.632 6.805 25.656 7.523 ;
     RECT  5.1 6.899 5.412 7.621 ;
     RECT  7.008 5.747 8.112 7.621 ;
     RECT  5.1 7.621 8.112 7.667 ;
     RECT  2.4 2.151 2.712 7.717 ;
     RECT  3.936 6.899 3.96 7.717 ;
     RECT  31.968 6.901 32.412 7.717 ;
     RECT  41.856 6.517 41.88 7.717 ;
     RECT  42.9 7.189 43.8 7.717 ;
     RECT  41.856 7.717 43.8 7.765 ;
     RECT  9.888 6.277 11.064 7.909 ;
     RECT  12.144 7.043 16.212 7.909 ;
     RECT  24 4.931 24.312 7.909 ;
     RECT  9.888 7.909 16.212 8.003 ;
     RECT  41.52 7.765 43.8 8.003 ;
     RECT  17.568 7.043 21.612 8.051 ;
     RECT  12 8.003 16.212 8.053 ;
     RECT  9.888 8.003 11.016 8.149 ;
     RECT  12 8.053 16.488 8.195 ;
     RECT  13.2 8.195 16.488 8.339 ;
     RECT  2.4 7.717 3.96 8.437 ;
     RECT  37.5 5.747 37.812 8.533 ;
     RECT  39.36 6.949 40.512 8.533 ;
     RECT  31.968 7.717 33.24 8.723 ;
     RECT  13.2 8.339 16.212 8.915 ;
     RECT  26.7 6.757 28.152 9.011 ;
     RECT  9.792 8.149 11.016 9.061 ;
     RECT  31.968 8.723 32.412 9.061 ;
     RECT  24 7.909 25.128 9.107 ;
     RECT  34.8 6.613 35.88 9.155 ;
     RECT  5.1 7.667 6.312 9.301 ;
     RECT  7.584 7.667 8.112 9.301 ;
     RECT  18.384 8.051 21.612 9.397 ;
     RECT  2.4 8.437 4.008 9.493 ;
     RECT  5.1 9.301 8.112 9.493 ;
     RECT  2.4 9.493 8.112 9.539 ;
     RECT  33.456 9.301 33.48 9.539 ;
     RECT  18.336 9.397 21.612 9.637 ;
     RECT  2.4 9.539 6.408 9.683 ;
     RECT  12 8.195 12.024 9.731 ;
     RECT  37.5 8.533 40.512 10.019 ;
     RECT  29.4 5.219 29.712 10.213 ;
     RECT  45.6 4.501 46.008 10.213 ;
     RECT  18.336 9.637 22.152 10.307 ;
     RECT  24 9.107 25.08 10.357 ;
     RECT  13.2 8.915 13.896 10.549 ;
     RECT  15.024 8.915 16.212 10.549 ;
     RECT  31.776 9.061 32.412 10.741 ;
     RECT  18.6 10.307 22.152 10.883 ;
     RECT  36.432 9.589 36.456 10.883 ;
     RECT  18.6 10.883 19.368 10.931 ;
     RECT  7.68 9.539 8.112 10.981 ;
     RECT  31.776 10.741 32.52 11.123 ;
     RECT  41.856 8.003 43.8 11.123 ;
     RECT  31.776 11.123 32.412 11.125 ;
     RECT  9.744 9.061 11.016 11.171 ;
     RECT  7.68 10.981 8.232 11.269 ;
     RECT  9.744 11.171 10.812 11.269 ;
     RECT  24 10.357 25.416 11.363 ;
     RECT  37.5 10.019 37.812 11.365 ;
     RECT  45.6 10.213 46.44 11.365 ;
     RECT  13.2 10.549 16.212 11.413 ;
     RECT  2.4 9.683 6.312 11.459 ;
     RECT  28.752 10.213 29.712 11.459 ;
     RECT  39.36 10.019 40.512 11.459 ;
     RECT  26.7 9.011 27.672 11.653 ;
     RECT  7.68 11.269 10.812 11.701 ;
     RECT  4.272 11.459 6.312 11.747 ;
     RECT  26.208 11.653 27.672 11.749 ;
     RECT  37.5 11.365 37.944 11.749 ;
     RECT  31.344 11.125 32.412 11.845 ;
     RECT  34.8 9.155 35.112 11.941 ;
     RECT  36.72 11.749 37.944 11.941 ;
     RECT  7.44 11.701 10.812 12.083 ;
     RECT  12.816 11.413 16.212 12.133 ;
     RECT  17.28 8.485 17.304 12.133 ;
     RECT  7.44 12.083 8.232 12.227 ;
     RECT  2.4 11.459 2.712 12.229 ;
     RECT  18.6 10.931 19.32 12.229 ;
     RECT  26.208 11.749 27.72 12.275 ;
     RECT  30.72 11.845 32.412 12.275 ;
     RECT  12.816 12.133 17.304 12.323 ;
     RECT  1.968 12.229 2.712 12.419 ;
     RECT  24 11.363 24.552 12.515 ;
     RECT  34.8 11.941 37.944 12.517 ;
     RECT  4.272 11.747 5.736 12.563 ;
     RECT  9.744 12.083 10.812 12.611 ;
     RECT  41.856 11.123 43.212 12.611 ;
     RECT  30.72 12.275 30.744 12.803 ;
     RECT  17.28 12.323 17.304 12.901 ;
     RECT  18.48 12.229 19.32 12.901 ;
     RECT  20.784 10.883 22.152 13.045 ;
     RECT  26.7 12.275 27.72 13.139 ;
     RECT  20.4 13.045 22.152 13.235 ;
     RECT  24 12.515 24.312 13.237 ;
     RECT  29.4 11.459 29.712 13.285 ;
     RECT  34.704 12.517 37.944 13.379 ;
     RECT  15.024 12.323 16.212 13.381 ;
     RECT  17.28 12.901 19.32 13.381 ;
     RECT  29.232 13.285 29.712 13.381 ;
     RECT  7.8 12.227 8.232 13.429 ;
     RECT  29.232 13.381 30.264 13.475 ;
     RECT  2.4 12.419 2.712 13.573 ;
     RECT  7.68 13.429 8.232 13.573 ;
     RECT  34.704 13.379 35.112 13.715 ;
     RECT  36.48 13.379 37.944 13.715 ;
     RECT  4.752 12.563 5.736 13.811 ;
     RECT  12.816 12.323 13.992 13.813 ;
     RECT  5.1 13.811 5.736 14.099 ;
     RECT  45.024 11.365 46.44 14.099 ;
     RECT  36.72 13.715 37.944 14.197 ;
     RECT  42.24 12.611 43.212 14.197 ;
     RECT  25.488 13.045 25.512 14.339 ;
     RECT  9.792 12.611 10.812 14.533 ;
     RECT  6.96 13.573 8.232 14.723 ;
     RECT  5.1 14.099 5.412 14.821 ;
     RECT  15.024 13.381 19.32 14.869 ;
     RECT  20.4 13.235 21.612 14.869 ;
     RECT  23.184 13.237 24.312 14.965 ;
     RECT  34.8 13.715 35.112 15.013 ;
     RECT  36.72 14.197 38.76 15.013 ;
     RECT  22.752 14.965 24.312 15.155 ;
     RECT  2.4 13.573 3 15.347 ;
     RECT  7.68 14.723 8.232 15.347 ;
     RECT  45.6 14.099 46.44 15.443 ;
     RECT  26.7 13.139 27.672 15.445 ;
     RECT  29.4 13.475 30.264 15.445 ;
     RECT  31.968 12.275 32.412 15.445 ;
     RECT  4.8 14.821 5.412 15.491 ;
     RECT  26.7 15.445 30.264 15.587 ;
     RECT  7.8 15.347 8.232 15.635 ;
     RECT  31.968 15.445 32.52 15.685 ;
     RECT  9.216 14.533 10.812 15.827 ;
     RECT  25.44 14.773 25.464 15.875 ;
     RECT  40.08 11.459 40.512 15.973 ;
     RECT  42.24 14.197 43.896 15.973 ;
     RECT  33.648 13.333 33.672 16.019 ;
     RECT  22.752 15.155 22.776 16.115 ;
     RECT  15.024 14.869 21.612 16.165 ;
     RECT  9.216 15.827 9.384 16.259 ;
     RECT  34.8 15.013 38.76 16.259 ;
     RECT  31.824 15.685 32.52 16.309 ;
     RECT  34.8 16.259 37.812 16.499 ;
     RECT  40.08 15.973 43.896 16.499 ;
     RECT  7.8 15.635 8.112 16.501 ;
     RECT  10.368 15.827 10.812 16.501 ;
     RECT  34.8 16.499 36.456 16.643 ;
     RECT  31.824 16.309 33.048 16.931 ;
     RECT  24 15.155 24.312 16.933 ;
     RECT  26.7 15.587 30.216 16.979 ;
     RECT  9.36 16.259 9.384 17.029 ;
     RECT  10.368 16.501 11.544 17.029 ;
     RECT  45.6 15.443 46.2 17.077 ;
     RECT  24 16.933 25.656 17.123 ;
     RECT  32.1 16.931 33.048 17.123 ;
     RECT  40.08 16.499 43.212 17.171 ;
     RECT  5.1 15.491 5.412 17.173 ;
     RECT  4.992 17.173 5.412 17.315 ;
     RECT  15.024 16.165 22.2 17.411 ;
     RECT  12.528 13.813 13.992 17.413 ;
     RECT  15.024 17.411 21.612 17.413 ;
     RECT  0.144 16.837 0.168 17.555 ;
     RECT  2.4 15.347 2.712 17.605 ;
     RECT  3.936 15.829 3.96 17.605 ;
     RECT  2.4 17.605 3.96 17.651 ;
     RECT  6.816 16.501 8.112 17.699 ;
     RECT  26.7 16.979 28.248 17.699 ;
     RECT  34.8 16.643 35.976 17.699 ;
     RECT  6.912 17.699 8.112 17.843 ;
     RECT  12.528 17.413 21.612 17.939 ;
     RECT  9.36 17.029 11.544 18.181 ;
     RECT  12.528 17.939 19.368 18.181 ;
     RECT  37.5 16.499 37.812 18.181 ;
     RECT  20.4 17.939 21.612 18.227 ;
     RECT  9.36 18.181 19.368 18.275 ;
     RECT  45.6 17.077 46.248 18.275 ;
     RECT  9.36 18.275 13.512 18.419 ;
     RECT  5.1 17.315 5.412 18.421 ;
     RECT  29.4 16.979 30.216 18.469 ;
     RECT  20.496 18.227 21.612 18.515 ;
     RECT  26.7 17.699 27.96 18.515 ;
     RECT  20.784 18.515 21.612 18.517 ;
     RECT  10.368 18.419 13.512 18.659 ;
     RECT  14.544 18.275 19.368 18.755 ;
     RECT  7.8 17.843 8.112 18.757 ;
     RECT  9.36 18.419 9.384 18.757 ;
     RECT  4.992 18.421 5.412 18.901 ;
     RECT  25.632 17.123 25.656 19.043 ;
     RECT  4.992 18.901 6.024 19.091 ;
     RECT  29.4 18.469 31.032 19.091 ;
     RECT  40.08 17.171 41.256 19.187 ;
     RECT  20.784 18.517 22.392 19.235 ;
     RECT  32.1 17.123 32.52 19.237 ;
     RECT  14.544 18.755 14.856 19.331 ;
     RECT  2.4 17.651 3.432 19.379 ;
     RECT  20.88 19.235 22.392 19.381 ;
     RECT  4.992 19.091 5.412 19.427 ;
     RECT  12.144 18.659 13.512 19.573 ;
     RECT  14.544 19.331 14.568 19.573 ;
     RECT  15.9 18.755 19.368 19.811 ;
     RECT  10.368 18.659 10.812 19.909 ;
     RECT  12.144 19.573 14.568 19.909 ;
     RECT  45.6 18.275 46.2 19.909 ;
     RECT  34.8 17.699 35.112 19.957 ;
     RECT  36.48 18.181 37.812 19.957 ;
     RECT  40.2 19.187 41.256 19.957 ;
     RECT  7.8 18.757 9.384 20.053 ;
     RECT  10.368 19.909 14.568 20.099 ;
     RECT  44.88 19.909 46.2 20.197 ;
     RECT  2.4 19.379 3.24 20.387 ;
     RECT  24 17.123 24.408 20.437 ;
     RECT  29.4 19.091 29.712 20.485 ;
     RECT  31.008 19.091 31.032 20.485 ;
     RECT  34.8 19.957 37.812 20.867 ;
     RECT  20.88 19.381 22.776 20.917 ;
     RECT  10.5 20.099 14.568 21.155 ;
     RECT  24 20.437 25.224 21.155 ;
     RECT  40.2 19.957 41.304 21.155 ;
     RECT  42.768 17.171 43.212 21.155 ;
     RECT  44.88 20.197 46.728 21.155 ;
     RECT  7.44 20.053 9.384 21.157 ;
     RECT  29.4 20.485 31.032 21.203 ;
     RECT  30.912 21.203 31.032 21.253 ;
     RECT  32.1 19.237 33.048 21.253 ;
     RECT  10.5 21.155 14.088 21.395 ;
     RECT  12.48 21.395 14.088 21.683 ;
     RECT  17.28 19.811 19.368 21.683 ;
     RECT  15.9 19.811 16.212 21.685 ;
     RECT  17.28 21.683 17.304 21.685 ;
     RECT  20.784 20.917 22.776 21.731 ;
     RECT  15.9 21.685 17.304 21.733 ;
     RECT  2.4 20.387 2.712 21.781 ;
     RECT  6.576 21.157 9.384 21.827 ;
     RECT  1.968 21.781 2.712 21.923 ;
     RECT  3.936 21.781 3.96 21.971 ;
     RECT  18.432 21.683 19.368 21.971 ;
     RECT  24 21.155 24.504 21.973 ;
     RECT  36.912 20.867 37.812 22.019 ;
     RECT  29.4 21.203 29.712 22.021 ;
     RECT  2.4 21.923 2.712 22.069 ;
     RECT  7.68 21.827 9.384 22.069 ;
     RECT  10.5 21.395 11.448 22.069 ;
     RECT  2.4 22.069 2.904 22.165 ;
     RECT  5.1 19.427 5.412 22.165 ;
     RECT  4.992 22.165 5.412 22.453 ;
     RECT  6.576 21.827 6.6 22.453 ;
     RECT  4.992 22.453 6.6 22.499 ;
     RECT  42.9 21.155 43.212 22.597 ;
     RECT  37.392 22.019 37.812 22.693 ;
     RECT  15.792 21.733 17.304 22.787 ;
     RECT  30.912 21.253 33.048 22.787 ;
     RECT  4.992 22.499 6.312 22.883 ;
     RECT  2.4 22.165 2.952 23.029 ;
     RECT  3.936 23.029 3.96 23.171 ;
     RECT  1.968 23.029 2.952 23.219 ;
     RECT  18.6 21.971 19.368 23.267 ;
     RECT  7.68 22.069 11.448 23.315 ;
     RECT  31.968 22.787 33.048 23.317 ;
     RECT  34.8 20.867 35.112 23.317 ;
     RECT  37.392 22.693 38.088 23.317 ;
     RECT  28.848 22.021 29.712 23.557 ;
     RECT  28.752 23.557 29.712 23.939 ;
     RECT  28.848 23.939 29.712 23.987 ;
     RECT  5.1 22.883 6.312 24.085 ;
     RECT  7.68 23.315 9.288 24.085 ;
     RECT  31.968 23.317 35.112 24.179 ;
     RECT  20.784 21.731 22.488 24.181 ;
     RECT  23.904 21.973 24.504 24.181 ;
     RECT  30.912 22.787 30.984 24.229 ;
     RECT  31.968 24.179 33.048 24.229 ;
     RECT  42.9 22.597 44.04 24.275 ;
     RECT  20.784 24.181 24.504 24.323 ;
     RECT  5.1 24.085 9.288 24.371 ;
     RECT  42.9 24.275 43.212 24.373 ;
     RECT  30.912 24.229 33.048 24.419 ;
     RECT  40.2 21.155 40.92 24.419 ;
     RECT  34.8 24.179 35.112 24.421 ;
     RECT  5.1 24.371 5.412 24.469 ;
     RECT  45.6 21.155 46.2 24.469 ;
     RECT  10.272 23.315 11.448 24.515 ;
     RECT  6.768 24.371 9.288 24.659 ;
     RECT  7.8 24.659 9.288 24.709 ;
     RECT  10.272 24.515 10.812 24.709 ;
     RECT  12.48 21.683 13.512 24.755 ;
     RECT  18.6 23.267 19.32 25.045 ;
     RECT  20.784 24.323 24.408 25.045 ;
     RECT  4.608 24.469 5.412 25.237 ;
     RECT  15.9 22.787 17.304 25.283 ;
     RECT  15.9 25.283 17.112 25.379 ;
     RECT  26.7 18.515 27.012 25.525 ;
     RECT  7.8 24.709 10.812 25.667 ;
     RECT  9.12 25.667 10.812 25.715 ;
     RECT  14.784 23.605 14.808 25.715 ;
     RECT  42.768 24.373 43.212 25.813 ;
     RECT  37.248 23.317 38.088 25.859 ;
     RECT  42.768 25.813 43.32 25.859 ;
     RECT  18.6 25.045 24.408 25.957 ;
     RECT  9.12 25.715 9.288 26.003 ;
     RECT  37.392 25.859 37.944 26.099 ;
     RECT  10.272 25.715 10.812 26.101 ;
     RECT  40.2 24.419 40.512 26.101 ;
     RECT  42.9 25.859 43.32 26.149 ;
     RECT  34.8 24.421 35.352 26.243 ;
     RECT  26.7 25.525 27.384 26.291 ;
     RECT  39.648 26.101 40.512 26.389 ;
     RECT  18.192 25.957 24.408 26.437 ;
     RECT  15.9 25.379 16.212 26.581 ;
     RECT  15.9 26.581 16.344 26.629 ;
     RECT  12.672 24.755 13.512 26.677 ;
     RECT  10.272 26.101 10.92 26.821 ;
     RECT  15.792 26.629 16.344 26.821 ;
     RECT  30.912 24.419 32.412 26.915 ;
     RECT  7.8 25.667 8.112 27.061 ;
     RECT  9.12 26.003 9.144 27.061 ;
     RECT  10.272 26.821 11.448 27.107 ;
     RECT  17.904 26.437 24.408 27.155 ;
     RECT  39.648 26.389 41.256 27.157 ;
     RECT  18.192 27.155 24.408 27.203 ;
     RECT  42.9 26.149 43.944 27.301 ;
     RECT  7.8 27.061 9.144 27.349 ;
     RECT  7.104 27.349 9.336 27.731 ;
     RECT  15.36 26.821 16.344 27.877 ;
     RECT  26.7 26.291 27.012 27.877 ;
     RECT  37.5 26.099 37.944 27.877 ;
     RECT  2.4 23.219 2.952 27.971 ;
     RECT  39.504 27.157 41.256 27.973 ;
     RECT  42.24 27.301 43.944 27.973 ;
     RECT  39.504 27.973 43.944 28.067 ;
     RECT  9.312 27.731 9.336 28.117 ;
     RECT  10.5 27.107 11.448 28.117 ;
     RECT  9.312 28.117 11.448 28.163 ;
     RECT  4.512 25.237 5.412 28.213 ;
     RECT  15.264 27.877 16.344 28.213 ;
     RECT  18.288 27.203 24.408 28.213 ;
     RECT  26.7 27.877 27.624 28.453 ;
     RECT  42.9 28.067 43.944 28.453 ;
     RECT  45.6 24.469 46.68 28.453 ;
     RECT  15.264 28.213 17.016 28.499 ;
     RECT  39.504 28.067 41.832 28.499 ;
     RECT  12.528 26.677 13.512 28.547 ;
     RECT  31.008 26.915 32.412 28.789 ;
     RECT  36.96 27.877 37.944 28.931 ;
     RECT  29.4 23.987 29.712 28.933 ;
     RECT  26.496 28.453 27.624 28.979 ;
     RECT  15.36 28.499 17.016 29.029 ;
     RECT  18.288 28.213 24.6 29.123 ;
     RECT  30.912 28.789 32.412 29.123 ;
     RECT  40.2 28.499 41.832 29.123 ;
     RECT  15.36 29.029 17.112 29.171 ;
     RECT  7.104 27.731 8.328 29.219 ;
     RECT  9.6 28.163 11.448 29.267 ;
     RECT  26.496 28.979 27.336 29.507 ;
     RECT  9.6 29.267 10.812 29.509 ;
     RECT  0.144 29.413 0.168 29.555 ;
     RECT  36.96 28.931 37.812 29.557 ;
     RECT  28.608 28.933 29.712 29.939 ;
     RECT  36.432 29.557 37.812 30.083 ;
     RECT  31.008 29.123 32.412 30.085 ;
     RECT  18.288 29.123 24.312 30.181 ;
     RECT  45.6 28.453 46.824 30.227 ;
     RECT  7.68 29.219 8.328 30.275 ;
     RECT  15.36 29.171 17.016 30.613 ;
     RECT  3.984 28.213 5.412 30.803 ;
     RECT  39.12 29.317 39.144 30.803 ;
     RECT  42.9 28.453 44.184 30.803 ;
     RECT  9.552 29.509 10.812 30.851 ;
     RECT  26.7 29.507 27.336 30.853 ;
     RECT  15.312 30.613 17.016 30.947 ;
     RECT  12.048 30.037 12.072 31.187 ;
     RECT  7.8 30.275 8.328 31.285 ;
     RECT  37.5 30.083 37.812 31.285 ;
     RECT  36.432 30.083 36.456 31.379 ;
     RECT  3.984 30.803 4.008 31.427 ;
     RECT  13.2 28.547 13.512 31.429 ;
     RECT  29.4 29.939 29.712 31.525 ;
     RECT  30.768 30.085 32.412 31.525 ;
     RECT  7.8 31.285 8.472 31.717 ;
     RECT  18.288 30.181 24.504 31.765 ;
     RECT  7.8 31.717 8.52 31.957 ;
     RECT  25.824 30.853 27.336 31.957 ;
     RECT  25.824 31.957 27.48 32.195 ;
     RECT  7.536 31.957 9.384 32.197 ;
     RECT  18.288 31.765 24.6 32.339 ;
     RECT  15.312 30.947 16.824 32.389 ;
     RECT  18.288 32.339 24.552 32.389 ;
     RECT  29.4 31.525 32.412 32.437 ;
     RECT  2.4 27.971 2.712 32.773 ;
     RECT  34.8 26.243 35.112 32.821 ;
     RECT  36.144 32.293 36.168 32.821 ;
     RECT  13.2 31.429 13.656 33.011 ;
     RECT  15.168 32.389 16.824 33.013 ;
     RECT  34.8 32.821 36.168 33.395 ;
     RECT  25.968 32.195 27.48 33.397 ;
     RECT  7.056 32.197 9.384 33.539 ;
     RECT  28.656 32.437 32.412 33.539 ;
     RECT  5.1 30.803 5.412 33.541 ;
     RECT  15.072 33.013 16.824 33.589 ;
     RECT  18.24 32.389 24.552 33.635 ;
     RECT  28.656 33.539 29.712 33.635 ;
     RECT  25.68 33.397 27.48 33.731 ;
     RECT  13.2 33.011 13.512 33.925 ;
     RECT  37.5 31.285 38.184 34.069 ;
     RECT  18.24 33.635 24.504 34.115 ;
     RECT  25.68 33.731 27.012 34.115 ;
     RECT  12.528 33.925 13.512 34.117 ;
     RECT  14.832 33.589 16.824 34.117 ;
     RECT  37.5 34.069 38.76 34.117 ;
     RECT  40.2 29.123 41.256 34.117 ;
     RECT  10.5 30.851 10.812 34.165 ;
     RECT  2.4 32.773 3.384 34.211 ;
     RECT  12.528 34.117 16.824 34.259 ;
     RECT  25.68 34.115 25.704 34.259 ;
     RECT  7.056 33.539 8.568 34.355 ;
     RECT  37.5 34.117 41.256 34.403 ;
     RECT  12.528 34.259 14.088 34.499 ;
     RECT  39.648 34.403 41.256 34.501 ;
     RECT  42.9 30.803 43.212 34.501 ;
     RECT  45.6 30.227 46.68 34.501 ;
     RECT  48.3 2.151 48.612 34.501 ;
     RECT  7.536 34.355 8.568 34.693 ;
     RECT  10.08 34.165 10.812 34.693 ;
     RECT  30.768 33.539 32.412 34.835 ;
     RECT  13.056 34.499 14.088 35.171 ;
     RECT  22.656 34.115 24.504 35.173 ;
     RECT  2.4 34.211 2.712 35.317 ;
     RECT  39.648 34.501 43.212 35.651 ;
     RECT  45.6 34.501 48.612 35.699 ;
     RECT  7.536 34.693 10.812 35.749 ;
     RECT  18.24 34.115 21.612 35.795 ;
     RECT  34.8 33.395 35.592 35.797 ;
     RECT  31.536 34.835 32.412 35.845 ;
     RECT  33.6 35.173 33.624 35.845 ;
     RECT  7.536 35.749 11.592 36.035 ;
     RECT  2.4 35.317 3.432 36.037 ;
     RECT  9.168 36.035 11.592 36.227 ;
     RECT  45.6 35.699 47.256 36.227 ;
     RECT  15.168 34.259 16.824 36.229 ;
     RECT  26.7 34.115 27.012 36.229 ;
     RECT  10.08 36.227 11.592 36.277 ;
     RECT  18.6 35.795 21.612 36.323 ;
     RECT  22.656 35.173 24.552 36.515 ;
     RECT  37.5 34.403 38.52 36.515 ;
     RECT  34.8 35.797 35.928 36.563 ;
     RECT  40.08 35.651 43.212 36.659 ;
     RECT  14.976 36.229 16.824 36.755 ;
     RECT  13.056 35.171 13.512 36.805 ;
     RECT  7.536 36.035 8.112 36.997 ;
     RECT  5.1 33.541 5.544 37.283 ;
     RECT  18.6 36.323 19.896 37.429 ;
     RECT  20.88 36.323 21.612 37.429 ;
     RECT  15.744 36.755 16.824 37.573 ;
     RECT  15.744 37.573 17.496 37.619 ;
     RECT  38.88 37.333 38.904 37.715 ;
     RECT  10.08 36.277 11.688 37.859 ;
     RECT  15.792 37.619 17.496 37.955 ;
     RECT  10.224 37.859 11.688 38.005 ;
     RECT  12.672 36.805 13.512 38.005 ;
     RECT  22.656 36.515 24.504 38.149 ;
     RECT  31.536 35.845 33.624 38.149 ;
     RECT  6.816 36.997 8.112 38.195 ;
     RECT  28.8 33.635 29.712 38.195 ;
     RECT  7.536 38.195 8.112 38.243 ;
     RECT  40.2 36.659 43.212 38.243 ;
     RECT  42.336 38.243 43.212 38.291 ;
     RECT  37.5 36.515 37.812 38.533 ;
     RECT  22.656 38.149 24.648 38.677 ;
     RECT  25.92 36.229 27.012 38.677 ;
     RECT  15.792 37.955 16.212 38.773 ;
     RECT  37.008 38.533 37.812 38.819 ;
     RECT  29.088 38.195 29.712 38.867 ;
     RECT  5.1 37.283 5.412 38.917 ;
     RECT  29.28 38.867 29.712 39.155 ;
     RECT  22.656 38.677 27.012 39.205 ;
     RECT  40.2 38.243 41.256 39.253 ;
     RECT  42.9 38.291 43.212 39.253 ;
     RECT  45.6 36.227 46.68 39.395 ;
     RECT  2.4 36.037 4.104 39.443 ;
     RECT  15.36 38.773 16.212 39.491 ;
     RECT  22.656 39.205 27.144 39.587 ;
     RECT  15.792 39.491 16.212 39.637 ;
     RECT  17.472 37.955 17.496 39.637 ;
     RECT  34.8 36.563 35.592 39.877 ;
     RECT  9.12 39.061 9.144 39.923 ;
     RECT  15.792 39.637 17.496 39.923 ;
     RECT  37.5 38.819 37.812 40.117 ;
     RECT  22.752 39.587 27.144 40.307 ;
     RECT  37.056 40.117 37.812 40.355 ;
     RECT  5.1 38.917 6.312 40.403 ;
     RECT  10.224 38.005 13.512 40.499 ;
     RECT  38.784 39.253 38.808 40.595 ;
     RECT  40.2 39.253 43.212 40.595 ;
     RECT  18.6 37.429 21.612 40.741 ;
     RECT  30.72 38.149 33.624 40.835 ;
     RECT  12.672 40.499 13.512 40.885 ;
     RECT  15.792 39.923 17.016 40.981 ;
     RECT  15.792 40.981 17.112 41.077 ;
     RECT  4.08 39.443 4.104 41.125 ;
     RECT  5.1 40.403 5.412 41.125 ;
     RECT  22.752 40.307 27.012 41.171 ;
     RECT  15.792 41.077 17.208 41.219 ;
     RECT  4.08 41.125 5.412 41.557 ;
     RECT  10.224 40.499 11.688 41.651 ;
     RECT  22.752 41.171 24.648 41.651 ;
     RECT  40.2 40.595 41.544 41.653 ;
     RECT  7.8 38.243 8.112 41.845 ;
     RECT  31.968 40.835 33.624 42.037 ;
     RECT  37.5 40.355 37.812 42.037 ;
     RECT  4.08 41.557 5.544 42.179 ;
     RECT  30.72 40.835 30.84 42.181 ;
     RECT  31.92 42.037 33.624 42.181 ;
     RECT  30.72 42.181 33.624 42.325 ;
     RECT  34.8 39.877 35.736 42.325 ;
     RECT  40.2 41.653 41.592 42.469 ;
     RECT  30.72 42.325 35.736 42.613 ;
     RECT  30.72 42.613 35.88 42.803 ;
     RECT  15.792 41.219 17.064 43.043 ;
     RECT  18.48 40.741 21.612 43.045 ;
     RECT  6.912 41.845 8.112 43.235 ;
     RECT  15.792 43.043 16.68 43.285 ;
     RECT  45.6 39.395 45.912 43.285 ;
     RECT  29.4 39.155 29.712 43.477 ;
     RECT  30.72 42.803 35.352 43.477 ;
     RECT  42.9 40.595 43.212 43.573 ;
     RECT  10.5 41.651 11.688 43.813 ;
     RECT  18.48 43.045 21.816 43.813 ;
     RECT  37.152 42.037 37.812 43.813 ;
     RECT  45.6 43.285 46.008 43.813 ;
     RECT  12.672 40.885 13.656 43.861 ;
     RECT  18.48 43.813 21.912 43.955 ;
     RECT  42.9 43.573 43.32 43.955 ;
     RECT  25.92 41.171 27.012 44.053 ;
     RECT  29.4 43.477 35.352 44.147 ;
     RECT  15.312 43.285 16.68 44.341 ;
     RECT  5.1 42.179 5.544 44.629 ;
     RECT  2.4 39.443 2.712 44.773 ;
     RECT  1.968 44.773 2.712 44.915 ;
     RECT  39.312 42.469 41.592 44.915 ;
     RECT  40.2 44.915 41.592 44.917 ;
     RECT  42.9 43.955 43.212 44.917 ;
     RECT  4.08 42.179 4.104 45.541 ;
     RECT  5.1 44.629 6.264 45.541 ;
     RECT  25.92 44.053 27.144 45.541 ;
     RECT  34.8 44.147 35.352 45.635 ;
     RECT  42.9 44.917 43.32 45.683 ;
     RECT  10.32 43.813 11.688 45.877 ;
     RECT  34.8 45.635 35.208 45.971 ;
     RECT  29.4 44.147 33.432 46.019 ;
     RECT  4.08 45.541 6.264 46.211 ;
     RECT  18.6 43.955 21.912 46.211 ;
     RECT  40.2 44.917 41.64 46.213 ;
     RECT  36.432 43.813 37.812 46.259 ;
     RECT  12.672 43.861 13.704 46.261 ;
     RECT  9.36 45.877 11.688 46.307 ;
     RECT  20.544 46.211 21.912 46.357 ;
     RECT  23.088 41.651 24.648 46.357 ;
     RECT  44.832 43.813 46.008 46.453 ;
     RECT  31.2 46.019 33.432 46.547 ;
     RECT  44.448 46.453 46.008 46.595 ;
     RECT  25.92 45.541 27.96 46.645 ;
     RECT  29.4 46.019 30.216 46.645 ;
     RECT  4.08 46.211 5.544 46.787 ;
     RECT  50.112 46.597 50.136 46.787 ;
     RECT  44.688 46.595 46.008 46.835 ;
     RECT  10.368 46.307 11.688 46.837 ;
     RECT  12.672 46.261 14.232 46.837 ;
     RECT  10.368 46.837 14.232 46.979 ;
     RECT  34.8 45.971 35.112 47.029 ;
     RECT  20.544 46.357 24.648 47.077 ;
     RECT  25.92 46.645 30.216 47.077 ;
     RECT  12.672 46.979 14.232 47.221 ;
     RECT  2.4 44.915 2.712 47.269 ;
     RECT  7.8 43.235 8.112 47.269 ;
     RECT  15.312 44.341 16.92 47.269 ;
     RECT  33.408 46.547 33.432 47.317 ;
     RECT  34.608 47.029 35.112 47.317 ;
     RECT  33.408 47.317 35.112 47.605 ;
     RECT  12.672 47.221 14.28 47.653 ;
     RECT  15.312 47.269 17.592 47.653 ;
     RECT  37.296 46.259 37.812 47.699 ;
     RECT  20.544 47.077 30.216 47.747 ;
     RECT  6.864 47.269 8.112 47.797 ;
     RECT  18.6 46.211 19.56 47.845 ;
     RECT  20.544 47.747 29.832 47.845 ;
     RECT  6.864 47.797 8.328 48.083 ;
     RECT  12.672 47.653 17.592 48.277 ;
     RECT  12.576 48.277 17.592 48.371 ;
     RECT  42.9 45.683 43.212 48.373 ;
     RECT  9.36 46.307 9.384 48.419 ;
     RECT  31.2 46.547 32.412 48.419 ;
     RECT  18.6 47.845 29.832 48.515 ;
     RECT  12.576 48.371 16.632 48.563 ;
     RECT  39.36 46.213 41.64 48.803 ;
     RECT  5.1 46.787 5.544 48.901 ;
     RECT  36.48 48.613 36.504 48.901 ;
     RECT  37.5 47.699 37.812 48.901 ;
     RECT  31.296 48.419 32.412 48.949 ;
     RECT  33.408 47.605 35.208 48.949 ;
     RECT  39.36 48.803 41.352 48.949 ;
     RECT  14.976 48.563 16.632 48.995 ;
     RECT  31.296 48.949 35.208 49.091 ;
     RECT  2.4 47.269 2.904 49.093 ;
     RECT  10.368 46.979 11.352 49.189 ;
     RECT  1.968 49.093 2.904 49.235 ;
     RECT  7.68 48.083 8.328 49.235 ;
     RECT  14.976 48.995 16.536 49.331 ;
     RECT  12.576 48.563 13.608 49.427 ;
     RECT  10.272 49.189 11.352 49.477 ;
     RECT  36.48 48.901 37.812 49.523 ;
     RECT  23.088 48.515 29.832 49.525 ;
     RECT  18.6 48.515 21.72 49.667 ;
     RECT  23.088 49.525 30.024 49.667 ;
     RECT  31.968 49.091 35.208 49.859 ;
     RECT  9.648 49.477 11.352 50.003 ;
     RECT  15.312 49.331 16.536 50.051 ;
     RECT  39.312 48.949 41.352 50.051 ;
     RECT  5.1 48.901 5.592 50.099 ;
     RECT  15.648 50.051 16.536 50.195 ;
     RECT  40.2 50.051 41.352 50.389 ;
     RECT  42.768 48.373 43.212 50.389 ;
     RECT  18.6 49.667 19.512 50.677 ;
     RECT  20.544 49.667 21.72 50.677 ;
     RECT  2.4 49.235 2.904 50.819 ;
     RECT  7.8 49.235 8.328 50.821 ;
     RECT  7.44 50.821 8.328 50.963 ;
     RECT  7.8 50.963 8.328 50.965 ;
     RECT  9.648 50.003 10.968 50.965 ;
     RECT  23.088 49.667 27.384 51.107 ;
     RECT  4.08 46.787 4.104 51.205 ;
     RECT  5.1 50.099 5.412 51.205 ;
     RECT  18.6 50.677 21.72 51.205 ;
     RECT  0.144 51.109 0.168 51.251 ;
     RECT  15.648 50.195 16.488 51.253 ;
     RECT  31.968 49.859 35.112 51.349 ;
     RECT  4.08 51.205 5.412 51.395 ;
     RECT  15.648 51.253 17.256 51.395 ;
     RECT  18.48 51.205 21.72 51.445 ;
     RECT  29.4 49.667 30.024 51.493 ;
     RECT  18.432 51.445 21.72 51.683 ;
     RECT  40.2 50.389 43.212 51.685 ;
     RECT  44.688 46.835 45.912 51.685 ;
     RECT  12.672 49.427 13.608 51.829 ;
     RECT  29.04 51.493 30.024 51.971 ;
     RECT  15.9 51.395 17.256 52.211 ;
     RECT  36.96 49.523 37.812 52.357 ;
     RECT  36.72 52.357 37.812 52.405 ;
     RECT  40.2 51.685 45.912 52.451 ;
     RECT  12.672 51.829 14.184 52.453 ;
     RECT  41.952 52.451 45.912 52.499 ;
     RECT  31.968 51.349 35.208 52.501 ;
     RECT  7.8 50.965 10.968 52.549 ;
     RECT  7.8 52.549 11.352 52.933 ;
     RECT  2.4 50.819 2.712 52.981 ;
     RECT  36.72 52.405 38.856 53.557 ;
     RECT  40.2 52.451 40.512 53.557 ;
     RECT  7.536 52.933 11.352 53.603 ;
     RECT  36.72 53.557 40.512 53.603 ;
     RECT  7.8 53.603 11.352 53.651 ;
     RECT  12.672 52.453 14.76 53.795 ;
     RECT  37.392 53.603 40.512 53.795 ;
     RECT  4.512 51.395 5.412 53.893 ;
     RECT  4.512 53.893 5.784 54.325 ;
     RECT  31.968 52.501 35.352 54.613 ;
     RECT  31.872 54.613 35.352 54.661 ;
     RECT  15.9 52.211 16.488 54.997 ;
     RECT  31.776 54.661 35.352 54.997 ;
     RECT  41.952 52.499 44.52 54.997 ;
     RECT  9.696 53.651 11.352 55.093 ;
     RECT  12.672 53.795 14.28 55.139 ;
     RECT  41.616 54.997 44.52 55.139 ;
     RECT  37.392 53.795 37.944 55.523 ;
     RECT  12.672 55.139 13.512 55.573 ;
     RECT  4.224 54.325 5.784 55.667 ;
     RECT  18.432 51.683 21.612 55.717 ;
     RECT  0.144 55.525 0.168 55.763 ;
     RECT  15.9 54.997 17.256 55.813 ;
     RECT  18.432 55.717 21.72 55.859 ;
     RECT  31.104 54.997 35.352 55.859 ;
     RECT  29.04 51.971 29.712 55.861 ;
     RECT  15.696 55.813 17.256 55.957 ;
     RECT  45.6 52.499 45.912 55.957 ;
     RECT  39.36 53.795 40.512 56.053 ;
     RECT  41.616 55.139 43.212 56.053 ;
     RECT  2.4 52.981 3.144 56.099 ;
     RECT  15.696 55.957 17.448 56.147 ;
     RECT  9.696 55.093 11.592 56.243 ;
     RECT  15.696 56.147 17.256 56.339 ;
     RECT  39.36 56.053 43.212 56.339 ;
     RECT  7.8 53.651 8.52 56.389 ;
     RECT  9.696 56.243 11.352 56.389 ;
     RECT  18.432 55.859 21.612 56.483 ;
     RECT  28.896 55.861 29.712 56.483 ;
     RECT  45.6 55.957 46.008 56.579 ;
     RECT  37.392 55.523 37.812 56.581 ;
     RECT  0.144 56.773 0.168 56.915 ;
     RECT  7.8 56.389 11.352 57.013 ;
     RECT  7.68 57.013 11.352 57.059 ;
     RECT  15.696 56.339 16.488 57.107 ;
     RECT  7.68 57.059 8.52 57.109 ;
     RECT  4.32 55.667 5.784 57.155 ;
     RECT  40.2 56.339 43.212 57.299 ;
     RECT  20.448 56.483 21.612 57.347 ;
     RECT  40.2 57.299 40.512 57.541 ;
     RECT  23.088 51.107 27.012 57.635 ;
     RECT  31.104 55.859 35.112 57.635 ;
     RECT  41.616 57.299 43.212 57.635 ;
     RECT  7.632 57.109 8.52 57.875 ;
     RECT  18.432 56.483 19.464 57.973 ;
     RECT  29.4 56.483 29.712 57.973 ;
     RECT  4.32 57.155 5.412 58.069 ;
     RECT  20.592 57.347 21.612 58.069 ;
     RECT  33.408 57.635 35.112 58.069 ;
     RECT  15.792 57.107 16.488 58.117 ;
     RECT  37.344 56.581 37.812 58.165 ;
     RECT  39.6 57.541 40.512 58.165 ;
     RECT  20.592 58.069 21.864 58.357 ;
     RECT  23.088 57.635 24.312 58.357 ;
     RECT  15.792 58.117 17.256 58.451 ;
     RECT  37.344 58.165 40.512 58.547 ;
     RECT  15.792 58.451 16.488 58.549 ;
     RECT  18.384 57.973 19.464 58.549 ;
     RECT  20.592 58.357 24.312 58.549 ;
     RECT  31.296 57.635 32.412 58.595 ;
     RECT  39.6 58.547 40.512 58.597 ;
     RECT  41.952 57.635 43.212 58.597 ;
     RECT  31.776 58.595 32.412 58.645 ;
     RECT  33.408 58.069 35.544 58.645 ;
     RECT  44.496 55.139 44.52 58.645 ;
     RECT  18.384 58.549 24.312 58.691 ;
     RECT  18.384 58.691 22.488 58.741 ;
     RECT  18.144 58.741 22.488 58.787 ;
     RECT  31.776 58.645 35.544 58.883 ;
     RECT  4.176 58.069 5.412 59.221 ;
     RECT  46.992 56.869 47.016 59.267 ;
     RECT  39.6 58.597 43.212 59.315 ;
     RECT  4.176 59.221 5.544 59.459 ;
     RECT  25.344 57.635 27.012 59.507 ;
     RECT  44.496 58.645 44.568 59.507 ;
     RECT  7.68 57.875 8.52 59.603 ;
     RECT  7.8 59.603 8.52 59.749 ;
     RECT  9.696 57.059 10.812 59.749 ;
     RECT  18.144 58.787 19.944 59.749 ;
     RECT  37.344 58.547 37.812 59.891 ;
     RECT  41.952 59.315 43.212 59.891 ;
     RECT  4.32 59.459 5.544 59.987 ;
     RECT  18.048 59.749 19.944 59.987 ;
     RECT  25.344 59.507 25.656 59.987 ;
     RECT  31.776 58.883 33.432 60.085 ;
     RECT  34.8 58.883 35.544 60.085 ;
     RECT  12.624 55.573 13.512 60.275 ;
     RECT  28.944 57.973 29.712 60.275 ;
     RECT  18.048 59.987 19.656 60.419 ;
     RECT  4.32 59.987 5.412 60.611 ;
     RECT  15.504 58.549 16.488 60.611 ;
     RECT  20.928 58.787 22.488 60.757 ;
     RECT  24 58.691 24.312 60.757 ;
     RECT  2.4 56.099 2.712 60.901 ;
     RECT  12.864 60.275 13.512 60.901 ;
     RECT  42.768 59.891 43.212 60.901 ;
     RECT  44.496 59.507 44.52 60.901 ;
     RECT  31.776 60.085 35.544 60.947 ;
     RECT  18.192 60.419 19.656 60.949 ;
     RECT  20.928 60.757 24.312 60.949 ;
     RECT  18.192 60.949 24.312 60.997 ;
     RECT  25.632 59.987 25.656 60.997 ;
     RECT  37.392 59.891 37.812 61.237 ;
     RECT  15.504 60.611 16.212 61.429 ;
     RECT  31.776 60.947 32.568 61.477 ;
     RECT  25.536 60.997 25.656 61.525 ;
     RECT  26.7 59.507 27.012 61.525 ;
     RECT  12.864 60.901 14.424 61.621 ;
     RECT  15.456 61.429 16.212 61.621 ;
     RECT  4.992 60.611 5.412 61.765 ;
     RECT  34.176 60.947 35.544 61.765 ;
     RECT  18.192 60.997 24.408 61.859 ;
     RECT  12.864 61.621 16.824 61.907 ;
     RECT  7.8 59.749 10.812 62.005 ;
     RECT  25.536 61.525 27.012 62.051 ;
     RECT  12.96 61.907 16.824 62.195 ;
     RECT  39.6 59.315 40.512 62.339 ;
     RECT  31.728 61.477 32.568 62.341 ;
     RECT  34.176 61.765 36.36 62.341 ;
     RECT  31.728 62.341 36.36 62.437 ;
     RECT  40.2 62.339 40.512 62.437 ;
     RECT  21.3 61.859 24.408 62.533 ;
     RECT  7.8 62.005 11.4 62.723 ;
     RECT  37.392 61.237 38.376 62.723 ;
     RECT  42.768 60.901 44.52 62.723 ;
     RECT  40.2 62.437 40.632 63.251 ;
     RECT  13.104 62.195 16.824 63.253 ;
     RECT  18.192 61.859 19.656 63.253 ;
     RECT  25.68 62.051 27.012 63.299 ;
     RECT  40.2 63.251 40.512 63.301 ;
     RECT  4.992 61.765 5.736 63.347 ;
     RECT  42.9 62.723 44.52 63.347 ;
     RECT  29.4 60.275 29.712 63.349 ;
     RECT  4.992 63.347 5.412 63.395 ;
     RECT  25.68 63.299 25.704 63.539 ;
     RECT  21.3 62.533 24.456 63.685 ;
     RECT  2.4 60.901 3.144 63.779 ;
     RECT  7.8 62.723 11.304 63.781 ;
     RECT  28.032 63.493 28.056 63.827 ;
     RECT  13.104 63.253 19.656 63.829 ;
     RECT  44.208 63.347 44.52 63.829 ;
     RECT  45.6 56.579 45.912 63.829 ;
     RECT  6.912 63.781 11.304 64.021 ;
     RECT  31.584 62.437 36.36 64.067 ;
     RECT  29.184 63.349 29.712 64.165 ;
     RECT  29.04 64.165 29.712 64.357 ;
     RECT  37.392 62.723 37.812 64.357 ;
     RECT  3.984 64.117 4.008 64.403 ;
     RECT  21.3 63.685 25.368 64.595 ;
     RECT  31.584 64.067 33.24 64.595 ;
     RECT  47.184 63.781 47.208 64.595 ;
     RECT  2.4 63.779 2.904 64.643 ;
     RECT  22.608 64.595 25.368 64.739 ;
     RECT  44.208 63.829 45.912 64.739 ;
     RECT  6.912 64.021 11.544 64.885 ;
     RECT  40.08 63.301 40.512 64.885 ;
     RECT  13.008 63.829 19.656 64.931 ;
     RECT  40.08 64.885 40.68 64.933 ;
     RECT  6.912 64.885 11.736 65.027 ;
     RECT  23.184 64.739 25.368 65.027 ;
     RECT  29.04 64.357 29.88 65.027 ;
     RECT  13.008 64.931 17.16 65.267 ;
     RECT  44.496 64.739 45.912 65.363 ;
     RECT  6.912 65.027 8.112 65.365 ;
     RECT  21.3 64.595 21.612 65.365 ;
     RECT  31.584 64.595 32.412 65.459 ;
     RECT  39.888 64.933 40.68 65.509 ;
     RECT  39.888 65.509 41.016 65.555 ;
     RECT  13.008 65.267 14.904 65.939 ;
     RECT  31.68 65.459 32.412 66.085 ;
     RECT  42.9 63.347 43.212 66.085 ;
     RECT  40.08 65.555 41.016 66.227 ;
     RECT  23.184 65.027 25.224 66.565 ;
     RECT  23.184 66.565 25.656 66.611 ;
     RECT  5.1 63.395 5.412 66.661 ;
     RECT  31.68 66.085 33.096 66.707 ;
     RECT  42.48 66.085 43.212 66.707 ;
     RECT  18.288 64.931 18.912 66.803 ;
     RECT  9.984 65.027 11.736 66.899 ;
     RECT  6.528 65.365 8.112 67.189 ;
     RECT  4.224 66.661 5.412 67.283 ;
     RECT  9.984 66.899 11.544 67.283 ;
     RECT  37.392 64.357 37.944 67.283 ;
     RECT  5.1 67.283 5.412 67.285 ;
     RECT  6.528 67.189 8.808 67.285 ;
     RECT  44.976 65.363 45.912 67.331 ;
     RECT  29.04 65.027 29.712 67.477 ;
     RECT  29.04 67.477 30.6 67.573 ;
     RECT  20.544 65.365 21.612 67.669 ;
     RECT  31.68 66.707 33.048 67.715 ;
     RECT  13.008 65.939 13.512 67.717 ;
     RECT  28.512 67.573 30.6 67.765 ;
     RECT  45.6 67.331 45.912 67.765 ;
     RECT  14.544 65.939 14.904 67.811 ;
     RECT  24 66.611 25.656 67.859 ;
     RECT  15.9 65.267 17.16 68.099 ;
     RECT  28.464 67.765 30.6 68.099 ;
     RECT  45.6 67.765 46.392 68.149 ;
     RECT  48.3 35.699 48.612 68.149 ;
     RECT  9.984 67.283 11.304 68.243 ;
     RECT  18.6 66.803 18.912 68.245 ;
     RECT  19.968 67.669 21.612 68.245 ;
     RECT  14.64 67.811 14.904 68.339 ;
     RECT  18.6 68.245 21.612 68.341 ;
     RECT  22.704 67.765 22.728 68.341 ;
     RECT  18.6 68.341 22.728 68.387 ;
     RECT  28.464 68.099 29.712 68.675 ;
     RECT  5.1 67.285 8.808 68.915 ;
     RECT  42.576 66.707 43.212 68.915 ;
     RECT  7.536 68.915 8.808 68.917 ;
     RECT  9.984 68.243 10.812 68.917 ;
     RECT  31.824 67.715 33.048 68.917 ;
     RECT  34.8 64.067 36.36 68.917 ;
     RECT  37.392 67.283 37.812 68.917 ;
     RECT  21.024 68.387 22.728 68.965 ;
     RECT  24 67.859 24.312 68.965 ;
     RECT  21.024 68.965 24.312 69.011 ;
     RECT  45.6 68.149 48.612 69.011 ;
     RECT  18.6 68.387 20.04 69.107 ;
     RECT  31.824 68.917 36.36 69.107 ;
     RECT  21.024 69.011 22.2 69.251 ;
     RECT  40.08 66.227 40.512 69.301 ;
     RECT  15.9 68.099 16.344 69.349 ;
     RECT  7.536 68.917 10.812 69.493 ;
     RECT  40.08 69.301 41.208 69.493 ;
     RECT  42.9 68.915 43.212 69.829 ;
     RECT  5.1 68.915 6.168 70.021 ;
     RECT  7.536 69.493 11.544 70.021 ;
     RECT  23.184 69.011 24.312 70.021 ;
     RECT  25.296 67.859 25.656 70.021 ;
     RECT  28.512 68.675 29.712 70.067 ;
     RECT  19.968 69.107 20.04 70.163 ;
     RECT  12.912 67.717 13.512 70.211 ;
     RECT  14.88 68.339 14.904 70.261 ;
     RECT  31.824 69.107 33.672 70.355 ;
     RECT  39.792 69.493 41.208 70.403 ;
     RECT  5.1 70.021 11.544 70.405 ;
     RECT  40.08 70.403 41.208 70.499 ;
     RECT  19.968 70.163 19.992 70.595 ;
     RECT  23.184 70.021 25.656 70.595 ;
     RECT  5.1 70.405 11.592 70.643 ;
     RECT  23.28 70.595 25.656 70.643 ;
     RECT  9.696 70.643 11.592 70.645 ;
     RECT  15.9 69.349 16.44 70.645 ;
     RECT  45.6 69.011 46.392 70.645 ;
     RECT  25.584 70.643 25.656 70.739 ;
     RECT  14.832 70.261 14.904 70.837 ;
     RECT  28.944 70.067 29.712 70.883 ;
     RECT  14.784 70.837 14.904 70.933 ;
     RECT  15.9 70.645 16.488 70.933 ;
     RECT  28.992 70.883 29.712 70.933 ;
     RECT  9.696 70.645 11.928 70.979 ;
     RECT  14.784 70.933 16.488 71.027 ;
     RECT  23.28 70.643 24.408 71.075 ;
     RECT  14.832 71.027 16.488 71.077 ;
     RECT  44.976 70.645 46.392 71.315 ;
     RECT  37.392 68.917 38.232 71.363 ;
     RECT  40.08 70.499 40.632 71.605 ;
     RECT  18.6 69.107 18.912 71.653 ;
     RECT  28.992 70.933 30.552 71.843 ;
     RECT  9.696 70.979 10.812 71.891 ;
     RECT  25.584 70.739 25.608 71.939 ;
     RECT  31.824 70.355 33.624 72.083 ;
     RECT  5.1 70.643 8.568 72.133 ;
     RECT  10.08 71.891 10.812 72.229 ;
     RECT  11.904 70.979 11.928 72.229 ;
     RECT  31.824 72.083 33.384 72.275 ;
     RECT  42.9 69.829 43.464 72.373 ;
     RECT  10.08 72.229 11.928 72.419 ;
     RECT  14.832 71.077 16.584 72.419 ;
     RECT  34.8 69.107 36.36 72.419 ;
     RECT  37.392 71.363 37.812 72.467 ;
     RECT  18.48 71.653 18.912 72.469 ;
     RECT  5.1 72.133 8.904 72.659 ;
     RECT  18.144 72.469 18.912 72.709 ;
     RECT  14.832 72.419 16.488 72.755 ;
     RECT  13.2 70.211 13.512 72.805 ;
     RECT  14.832 72.755 16.344 72.805 ;
     RECT  26.7 63.299 27.012 72.805 ;
     RECT  42.288 72.373 43.464 72.851 ;
     RECT  23.28 71.075 24.312 72.901 ;
     RECT  28.992 71.843 29.712 72.901 ;
     RECT  21.024 69.251 21.612 72.949 ;
     RECT  23.28 72.901 24.408 72.949 ;
     RECT  39.888 71.605 40.632 73.523 ;
     RECT  31.824 72.275 32.412 73.525 ;
     RECT  6.912 72.659 8.904 73.571 ;
     RECT  10.368 72.419 11.784 73.811 ;
     RECT  28.992 72.901 30.216 73.811 ;
     RECT  7.8 73.571 8.904 73.813 ;
     RECT  13.2 72.805 16.344 73.861 ;
     RECT  13.104 73.861 16.344 73.907 ;
     RECT  31.824 73.525 32.856 74.005 ;
     RECT  40.032 73.523 40.632 74.005 ;
     RECT  26.7 72.805 27.912 74.053 ;
     RECT  28.992 73.811 29.712 74.053 ;
     RECT  45.6 71.315 46.392 74.053 ;
     RECT  5.1 72.659 5.412 74.101 ;
     RECT  21.024 72.949 24.408 74.293 ;
     RECT  34.8 72.419 35.592 74.389 ;
     RECT  13.104 73.907 13.512 74.485 ;
     RECT  7.8 73.813 9 74.629 ;
     RECT  40.032 74.005 40.92 74.629 ;
     RECT  42.288 72.851 43.212 74.629 ;
     RECT  18.048 72.709 18.912 74.677 ;
     RECT  21.024 74.293 25.272 74.723 ;
     RECT  39.84 74.629 40.92 74.723 ;
     RECT  7.536 74.629 9 74.771 ;
     RECT  15.072 73.907 16.344 74.771 ;
     RECT  34.8 74.389 35.976 74.771 ;
     RECT  21.024 74.723 21.612 74.965 ;
     RECT  45.024 74.053 46.392 75.061 ;
     RECT  39.84 74.723 40.512 75.155 ;
     RECT  10.368 73.811 10.812 75.157 ;
     RECT  12.912 74.485 13.512 75.157 ;
     RECT  45.024 75.061 46.728 75.203 ;
     RECT  45.168 75.203 46.728 75.253 ;
     RECT  48.3 69.011 48.612 75.253 ;
     RECT  15.9 74.771 16.344 75.299 ;
     RECT  38.784 73.237 38.808 75.299 ;
     RECT  42.288 74.629 43.368 75.395 ;
     RECT  31.488 74.005 32.856 75.541 ;
     RECT  0.624 75.637 0.648 75.779 ;
     RECT  45.168 75.253 48.612 75.779 ;
     RECT  17.664 74.677 18.912 75.827 ;
     RECT  15.9 75.299 16.212 75.829 ;
     RECT  20.88 74.965 21.612 75.875 ;
     RECT  26.7 74.053 29.712 75.875 ;
     RECT  7.536 74.771 8.112 75.971 ;
     RECT  15.36 75.829 16.212 76.019 ;
     RECT  23.04 74.723 25.272 76.211 ;
     RECT  40.032 75.155 40.512 76.357 ;
     RECT  21.024 75.875 21.612 76.451 ;
     RECT  5.1 74.101 5.88 76.499 ;
     RECT  18.048 75.827 18.912 76.549 ;
     RECT  10.368 75.157 13.512 76.597 ;
     RECT  45.168 75.779 45.912 76.739 ;
     RECT  34.8 74.771 35.832 76.787 ;
     RECT  31.488 75.541 33.144 76.885 ;
     RECT  39.216 76.357 40.512 76.885 ;
     RECT  38.88 76.885 40.512 76.931 ;
     RECT  21.168 76.451 21.612 77.029 ;
     RECT  23.04 76.211 25.224 77.029 ;
     RECT  21.168 77.029 25.224 77.075 ;
     RECT  9.696 76.597 13.512 77.123 ;
     RECT  21.3 77.075 25.224 77.171 ;
     RECT  40.2 76.931 40.512 77.173 ;
     RECT  47.328 75.779 48.612 77.267 ;
     RECT  18.048 76.549 19.32 77.315 ;
     RECT  7.68 75.971 8.112 77.699 ;
     RECT  28.704 75.875 29.712 77.699 ;
     RECT  9.696 77.123 10.812 77.749 ;
     RECT  31.2 76.885 33.144 78.083 ;
     RECT  26.7 75.875 27.012 78.085 ;
     RECT  21.3 77.171 25.128 78.181 ;
     RECT  26.7 78.085 27.864 78.227 ;
     RECT  20.976 78.181 25.128 78.323 ;
     RECT  9.36 77.749 10.812 78.325 ;
     RECT  37.5 72.467 37.812 78.325 ;
     RECT  34.8 76.787 35.352 78.371 ;
     RECT  9.36 78.325 10.92 78.421 ;
     RECT  18.6 77.315 19.32 78.517 ;
     RECT  37.056 78.325 37.812 78.563 ;
     RECT  21.168 78.323 25.128 78.611 ;
     RECT  23.04 78.611 25.128 78.659 ;
     RECT  40.2 77.173 41.16 78.659 ;
     RECT  9.12 78.421 10.92 78.707 ;
     RECT  42.288 75.395 43.212 78.707 ;
     RECT  23.04 78.659 25.032 78.899 ;
     RECT  29.088 77.699 29.712 79.091 ;
     RECT  12.336 77.123 13.512 79.139 ;
     RECT  32.1 78.083 33.144 79.187 ;
     RECT  38.88 76.931 38.904 79.187 ;
     RECT  21.168 78.611 21.612 79.235 ;
     RECT  23.04 78.899 24.312 79.235 ;
     RECT  34.8 78.371 35.304 79.283 ;
     RECT  9.696 78.707 10.812 79.331 ;
     RECT  18.6 78.517 19.56 79.715 ;
     RECT  2.4 64.643 2.712 79.929 ;
     RECT  5.1 76.499 5.412 79.929 ;
     RECT  7.8 77.699 8.112 79.929 ;
     RECT  10.5 79.331 10.812 79.929 ;
     RECT  13.2 79.139 13.512 79.929 ;
     RECT  15.9 76.019 16.212 79.929 ;
     RECT  18.6 79.715 18.912 79.929 ;
     RECT  21.3 79.235 21.612 79.929 ;
     RECT  24 79.235 24.312 79.929 ;
     RECT  26.7 78.227 27.012 79.929 ;
     RECT  29.4 79.091 29.712 79.929 ;
     RECT  32.1 79.187 32.412 79.929 ;
     RECT  34.8 79.283 35.112 79.929 ;
     RECT  37.5 78.563 37.812 79.929 ;
     RECT  40.2 78.659 40.512 79.929 ;
     RECT  42.9 78.707 43.212 79.929 ;
     RECT  45.6 76.739 45.912 79.929 ;
     RECT  48.3 77.267 48.612 79.929 ;
     RECT  2.4 79.929 2.52 79.943 ;
     RECT  5.1 79.929 5.22 79.943 ;
     RECT  7.8 79.929 7.92 79.943 ;
     RECT  10.5 79.929 10.62 79.943 ;
     RECT  13.2 79.929 13.32 79.943 ;
     RECT  15.9 79.929 16.02 79.943 ;
     RECT  18.6 79.929 18.72 79.943 ;
     RECT  21.3 79.929 21.42 79.943 ;
     RECT  24 79.929 24.12 79.943 ;
     RECT  26.7 79.929 26.82 79.943 ;
     RECT  29.4 79.929 29.52 79.943 ;
     RECT  32.1 79.929 32.22 79.943 ;
     RECT  34.8 79.929 34.92 79.943 ;
     RECT  37.5 79.929 37.62 79.943 ;
     RECT  40.2 79.929 40.32 79.943 ;
     RECT  42.9 79.929 43.02 79.943 ;
     RECT  45.6 79.929 45.72 79.943 ;
     RECT  48.3 79.929 48.42 79.943 ;
  END
END qkd_landsh_528
END LIBRARY
